VERSION 5.8 ;
BUSBITCHARS "[]" ;
DIVIDERCHAR "/" ;
UNITS
    DATABASE MICRONS 1000 ;
END UNITS

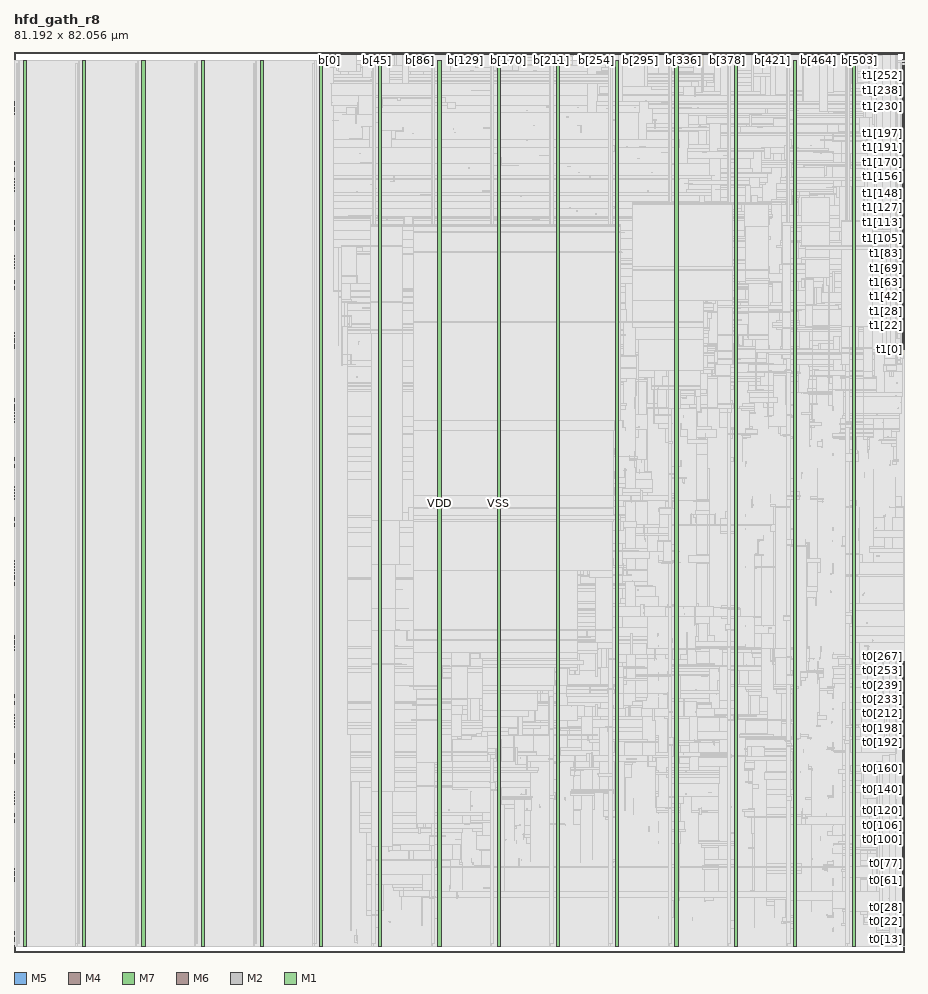
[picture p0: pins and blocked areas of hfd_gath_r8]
MACRO hfd_gath_r8
  FOREIGN hfd_gath_r8 0 0 ;
  CLASS BLOCK ;
  SIZE 81.192 BY 82.056 ;
  PIN b[0]
    DIRECTION OUTPUT ;
    USE SIGNAL ;
    PORT
      LAYER M5 ;
        RECT  28.752 81.864 28.776 82.056 ;
    END
  END b[0]
  PIN b[100]
    DIRECTION OUTPUT ;
    USE SIGNAL ;
    PORT
      LAYER M5 ;
        RECT  38.352 81.864 38.376 82.056 ;
    END
  END b[100]
  PIN b[101]
    DIRECTION OUTPUT ;
    USE SIGNAL ;
    PORT
      LAYER M5 ;
        RECT  38.448 81.864 38.472 82.056 ;
    END
  END b[101]
  PIN b[102]
    DIRECTION OUTPUT ;
    USE SIGNAL ;
    PORT
      LAYER M5 ;
        RECT  38.544 81.864 38.568 82.056 ;
    END
  END b[102]
  PIN b[103]
    DIRECTION OUTPUT ;
    USE SIGNAL ;
    PORT
      LAYER M5 ;
        RECT  38.64 81.864 38.664 82.056 ;
    END
  END b[103]
  PIN b[104]
    DIRECTION OUTPUT ;
    USE SIGNAL ;
    PORT
      LAYER M5 ;
        RECT  38.736 81.864 38.76 82.056 ;
    END
  END b[104]
  PIN b[105]
    DIRECTION OUTPUT ;
    USE SIGNAL ;
    PORT
      LAYER M5 ;
        RECT  38.832 81.864 38.856 82.056 ;
    END
  END b[105]
  PIN b[106]
    DIRECTION OUTPUT ;
    USE SIGNAL ;
    PORT
      LAYER M5 ;
        RECT  38.928 81.864 38.952 82.056 ;
    END
  END b[106]
  PIN b[107]
    DIRECTION OUTPUT ;
    USE SIGNAL ;
    PORT
      LAYER M5 ;
        RECT  39.024 81.864 39.048 82.056 ;
    END
  END b[107]
  PIN b[108]
    DIRECTION OUTPUT ;
    USE SIGNAL ;
    PORT
      LAYER M5 ;
        RECT  39.12 81.864 39.144 82.056 ;
    END
  END b[108]
  PIN b[109]
    DIRECTION OUTPUT ;
    USE SIGNAL ;
    PORT
      LAYER M5 ;
        RECT  39.216 81.864 39.24 82.056 ;
    END
  END b[109]
  PIN b[10]
    DIRECTION OUTPUT ;
    USE SIGNAL ;
    PORT
      LAYER M5 ;
        RECT  29.712 81.864 29.736 82.056 ;
    END
  END b[10]
  PIN b[110]
    DIRECTION OUTPUT ;
    USE SIGNAL ;
    PORT
      LAYER M5 ;
        RECT  39.312 81.864 39.336 82.056 ;
    END
  END b[110]
  PIN b[111]
    DIRECTION OUTPUT ;
    USE SIGNAL ;
    PORT
      LAYER M5 ;
        RECT  39.408 81.864 39.432 82.056 ;
    END
  END b[111]
  PIN b[112]
    DIRECTION OUTPUT ;
    USE SIGNAL ;
    PORT
      LAYER M5 ;
        RECT  39.504 81.864 39.528 82.056 ;
    END
  END b[112]
  PIN b[113]
    DIRECTION OUTPUT ;
    USE SIGNAL ;
    PORT
      LAYER M5 ;
        RECT  39.6 81.864 39.624 82.056 ;
    END
  END b[113]
  PIN b[114]
    DIRECTION OUTPUT ;
    USE SIGNAL ;
    PORT
      LAYER M5 ;
        RECT  39.696 81.864 39.72 82.056 ;
    END
  END b[114]
  PIN b[115]
    DIRECTION OUTPUT ;
    USE SIGNAL ;
    PORT
      LAYER M5 ;
        RECT  39.792 81.864 39.816 82.056 ;
    END
  END b[115]
  PIN b[116]
    DIRECTION OUTPUT ;
    USE SIGNAL ;
    PORT
      LAYER M5 ;
        RECT  39.888 81.864 39.912 82.056 ;
    END
  END b[116]
  PIN b[117]
    DIRECTION OUTPUT ;
    USE SIGNAL ;
    PORT
      LAYER M5 ;
        RECT  39.984 81.864 40.008 82.056 ;
    END
  END b[117]
  PIN b[118]
    DIRECTION OUTPUT ;
    USE SIGNAL ;
    PORT
      LAYER M5 ;
        RECT  40.08 81.864 40.104 82.056 ;
    END
  END b[118]
  PIN b[119]
    DIRECTION OUTPUT ;
    USE SIGNAL ;
    PORT
      LAYER M5 ;
        RECT  40.176 81.864 40.2 82.056 ;
    END
  END b[119]
  PIN b[11]
    DIRECTION OUTPUT ;
    USE SIGNAL ;
    PORT
      LAYER M5 ;
        RECT  29.808 81.864 29.832 82.056 ;
    END
  END b[11]
  PIN b[120]
    DIRECTION OUTPUT ;
    USE SIGNAL ;
    PORT
      LAYER M5 ;
        RECT  40.272 81.864 40.296 82.056 ;
    END
  END b[120]
  PIN b[121]
    DIRECTION OUTPUT ;
    USE SIGNAL ;
    PORT
      LAYER M5 ;
        RECT  40.368 81.864 40.392 82.056 ;
    END
  END b[121]
  PIN b[122]
    DIRECTION OUTPUT ;
    USE SIGNAL ;
    PORT
      LAYER M5 ;
        RECT  40.464 81.864 40.488 82.056 ;
    END
  END b[122]
  PIN b[123]
    DIRECTION OUTPUT ;
    USE SIGNAL ;
    PORT
      LAYER M5 ;
        RECT  40.56 81.864 40.584 82.056 ;
    END
  END b[123]
  PIN b[124]
    DIRECTION OUTPUT ;
    USE SIGNAL ;
    PORT
      LAYER M5 ;
        RECT  40.656 81.864 40.68 82.056 ;
    END
  END b[124]
  PIN b[125]
    DIRECTION OUTPUT ;
    USE SIGNAL ;
    PORT
      LAYER M5 ;
        RECT  40.752 81.864 40.776 82.056 ;
    END
  END b[125]
  PIN b[126]
    DIRECTION OUTPUT ;
    USE SIGNAL ;
    PORT
      LAYER M5 ;
        RECT  40.848 81.864 40.872 82.056 ;
    END
  END b[126]
  PIN b[127]
    DIRECTION OUTPUT ;
    USE SIGNAL ;
    PORT
      LAYER M5 ;
        RECT  40.944 81.864 40.968 82.056 ;
    END
  END b[127]
  PIN b[128]
    DIRECTION OUTPUT ;
    USE SIGNAL ;
    PORT
      LAYER M5 ;
        RECT  41.04 81.864 41.064 82.056 ;
    END
  END b[128]
  PIN b[129]
    DIRECTION OUTPUT ;
    USE SIGNAL ;
    PORT
      LAYER M5 ;
        RECT  41.136 81.864 41.16 82.056 ;
    END
  END b[129]
  PIN b[12]
    DIRECTION OUTPUT ;
    USE SIGNAL ;
    PORT
      LAYER M5 ;
        RECT  29.904 81.864 29.928 82.056 ;
    END
  END b[12]
  PIN b[130]
    DIRECTION OUTPUT ;
    USE SIGNAL ;
    PORT
      LAYER M5 ;
        RECT  41.232 81.864 41.256 82.056 ;
    END
  END b[130]
  PIN b[131]
    DIRECTION OUTPUT ;
    USE SIGNAL ;
    PORT
      LAYER M5 ;
        RECT  41.328 81.864 41.352 82.056 ;
    END
  END b[131]
  PIN b[132]
    DIRECTION OUTPUT ;
    USE SIGNAL ;
    PORT
      LAYER M5 ;
        RECT  41.424 81.864 41.448 82.056 ;
    END
  END b[132]
  PIN b[133]
    DIRECTION OUTPUT ;
    USE SIGNAL ;
    PORT
      LAYER M5 ;
        RECT  41.52 81.864 41.544 82.056 ;
    END
  END b[133]
  PIN b[134]
    DIRECTION OUTPUT ;
    USE SIGNAL ;
    PORT
      LAYER M5 ;
        RECT  41.616 81.864 41.64 82.056 ;
    END
  END b[134]
  PIN b[135]
    DIRECTION OUTPUT ;
    USE SIGNAL ;
    PORT
      LAYER M5 ;
        RECT  41.712 81.864 41.736 82.056 ;
    END
  END b[135]
  PIN b[136]
    DIRECTION OUTPUT ;
    USE SIGNAL ;
    PORT
      LAYER M5 ;
        RECT  41.808 81.864 41.832 82.056 ;
    END
  END b[136]
  PIN b[137]
    DIRECTION OUTPUT ;
    USE SIGNAL ;
    PORT
      LAYER M5 ;
        RECT  41.904 81.864 41.928 82.056 ;
    END
  END b[137]
  PIN b[138]
    DIRECTION OUTPUT ;
    USE SIGNAL ;
    PORT
      LAYER M5 ;
        RECT  42 81.864 42.024 82.056 ;
    END
  END b[138]
  PIN b[139]
    DIRECTION OUTPUT ;
    USE SIGNAL ;
    PORT
      LAYER M5 ;
        RECT  42.096 81.864 42.12 82.056 ;
    END
  END b[139]
  PIN b[13]
    DIRECTION OUTPUT ;
    USE SIGNAL ;
    PORT
      LAYER M5 ;
        RECT  30 81.864 30.024 82.056 ;
    END
  END b[13]
  PIN b[140]
    DIRECTION OUTPUT ;
    USE SIGNAL ;
    PORT
      LAYER M5 ;
        RECT  42.192 81.864 42.216 82.056 ;
    END
  END b[140]
  PIN b[141]
    DIRECTION OUTPUT ;
    USE SIGNAL ;
    PORT
      LAYER M5 ;
        RECT  42.288 81.864 42.312 82.056 ;
    END
  END b[141]
  PIN b[142]
    DIRECTION OUTPUT ;
    USE SIGNAL ;
    PORT
      LAYER M5 ;
        RECT  42.384 81.864 42.408 82.056 ;
    END
  END b[142]
  PIN b[143]
    DIRECTION OUTPUT ;
    USE SIGNAL ;
    PORT
      LAYER M5 ;
        RECT  42.48 81.864 42.504 82.056 ;
    END
  END b[143]
  PIN b[144]
    DIRECTION OUTPUT ;
    USE SIGNAL ;
    PORT
      LAYER M5 ;
        RECT  42.576 81.864 42.6 82.056 ;
    END
  END b[144]
  PIN b[145]
    DIRECTION OUTPUT ;
    USE SIGNAL ;
    PORT
      LAYER M5 ;
        RECT  42.672 81.864 42.696 82.056 ;
    END
  END b[145]
  PIN b[146]
    DIRECTION OUTPUT ;
    USE SIGNAL ;
    PORT
      LAYER M5 ;
        RECT  42.768 81.864 42.792 82.056 ;
    END
  END b[146]
  PIN b[147]
    DIRECTION OUTPUT ;
    USE SIGNAL ;
    PORT
      LAYER M5 ;
        RECT  42.864 81.864 42.888 82.056 ;
    END
  END b[147]
  PIN b[148]
    DIRECTION OUTPUT ;
    USE SIGNAL ;
    PORT
      LAYER M5 ;
        RECT  42.96 81.864 42.984 82.056 ;
    END
  END b[148]
  PIN b[149]
    DIRECTION OUTPUT ;
    USE SIGNAL ;
    PORT
      LAYER M5 ;
        RECT  43.056 81.864 43.08 82.056 ;
    END
  END b[149]
  PIN b[14]
    DIRECTION OUTPUT ;
    USE SIGNAL ;
    PORT
      LAYER M5 ;
        RECT  30.096 81.864 30.12 82.056 ;
    END
  END b[14]
  PIN b[150]
    DIRECTION OUTPUT ;
    USE SIGNAL ;
    PORT
      LAYER M5 ;
        RECT  43.152 81.864 43.176 82.056 ;
    END
  END b[150]
  PIN b[151]
    DIRECTION OUTPUT ;
    USE SIGNAL ;
    PORT
      LAYER M5 ;
        RECT  43.248 81.864 43.272 82.056 ;
    END
  END b[151]
  PIN b[152]
    DIRECTION OUTPUT ;
    USE SIGNAL ;
    PORT
      LAYER M5 ;
        RECT  43.344 81.864 43.368 82.056 ;
    END
  END b[152]
  PIN b[153]
    DIRECTION OUTPUT ;
    USE SIGNAL ;
    PORT
      LAYER M5 ;
        RECT  43.44 81.864 43.464 82.056 ;
    END
  END b[153]
  PIN b[154]
    DIRECTION OUTPUT ;
    USE SIGNAL ;
    PORT
      LAYER M5 ;
        RECT  43.536 81.864 43.56 82.056 ;
    END
  END b[154]
  PIN b[155]
    DIRECTION OUTPUT ;
    USE SIGNAL ;
    PORT
      LAYER M5 ;
        RECT  43.632 81.864 43.656 82.056 ;
    END
  END b[155]
  PIN b[156]
    DIRECTION OUTPUT ;
    USE SIGNAL ;
    PORT
      LAYER M5 ;
        RECT  43.728 81.864 43.752 82.056 ;
    END
  END b[156]
  PIN b[157]
    DIRECTION OUTPUT ;
    USE SIGNAL ;
    PORT
      LAYER M5 ;
        RECT  43.824 81.864 43.848 82.056 ;
    END
  END b[157]
  PIN b[158]
    DIRECTION OUTPUT ;
    USE SIGNAL ;
    PORT
      LAYER M5 ;
        RECT  43.92 81.864 43.944 82.056 ;
    END
  END b[158]
  PIN b[159]
    DIRECTION OUTPUT ;
    USE SIGNAL ;
    PORT
      LAYER M5 ;
        RECT  44.016 81.864 44.04 82.056 ;
    END
  END b[159]
  PIN b[15]
    DIRECTION OUTPUT ;
    USE SIGNAL ;
    PORT
      LAYER M5 ;
        RECT  30.192 81.864 30.216 82.056 ;
    END
  END b[15]
  PIN b[160]
    DIRECTION OUTPUT ;
    USE SIGNAL ;
    PORT
      LAYER M5 ;
        RECT  44.112 81.864 44.136 82.056 ;
    END
  END b[160]
  PIN b[161]
    DIRECTION OUTPUT ;
    USE SIGNAL ;
    PORT
      LAYER M5 ;
        RECT  44.208 81.864 44.232 82.056 ;
    END
  END b[161]
  PIN b[162]
    DIRECTION OUTPUT ;
    USE SIGNAL ;
    PORT
      LAYER M5 ;
        RECT  44.304 81.864 44.328 82.056 ;
    END
  END b[162]
  PIN b[163]
    DIRECTION OUTPUT ;
    USE SIGNAL ;
    PORT
      LAYER M5 ;
        RECT  44.4 81.864 44.424 82.056 ;
    END
  END b[163]
  PIN b[164]
    DIRECTION OUTPUT ;
    USE SIGNAL ;
    PORT
      LAYER M5 ;
        RECT  44.496 81.864 44.52 82.056 ;
    END
  END b[164]
  PIN b[165]
    DIRECTION OUTPUT ;
    USE SIGNAL ;
    PORT
      LAYER M5 ;
        RECT  44.592 81.864 44.616 82.056 ;
    END
  END b[165]
  PIN b[166]
    DIRECTION OUTPUT ;
    USE SIGNAL ;
    PORT
      LAYER M5 ;
        RECT  44.688 81.864 44.712 82.056 ;
    END
  END b[166]
  PIN b[167]
    DIRECTION OUTPUT ;
    USE SIGNAL ;
    PORT
      LAYER M5 ;
        RECT  44.784 81.864 44.808 82.056 ;
    END
  END b[167]
  PIN b[168]
    DIRECTION OUTPUT ;
    USE SIGNAL ;
    PORT
      LAYER M5 ;
        RECT  44.88 81.864 44.904 82.056 ;
    END
  END b[168]
  PIN b[169]
    DIRECTION OUTPUT ;
    USE SIGNAL ;
    PORT
      LAYER M5 ;
        RECT  44.976 81.864 45 82.056 ;
    END
  END b[169]
  PIN b[16]
    DIRECTION OUTPUT ;
    USE SIGNAL ;
    PORT
      LAYER M5 ;
        RECT  30.288 81.864 30.312 82.056 ;
    END
  END b[16]
  PIN b[170]
    DIRECTION OUTPUT ;
    USE SIGNAL ;
    PORT
      LAYER M5 ;
        RECT  45.072 81.864 45.096 82.056 ;
    END
  END b[170]
  PIN b[171]
    DIRECTION OUTPUT ;
    USE SIGNAL ;
    PORT
      LAYER M5 ;
        RECT  45.168 81.864 45.192 82.056 ;
    END
  END b[171]
  PIN b[172]
    DIRECTION OUTPUT ;
    USE SIGNAL ;
    PORT
      LAYER M5 ;
        RECT  45.264 81.864 45.288 82.056 ;
    END
  END b[172]
  PIN b[173]
    DIRECTION OUTPUT ;
    USE SIGNAL ;
    PORT
      LAYER M5 ;
        RECT  45.36 81.864 45.384 82.056 ;
    END
  END b[173]
  PIN b[174]
    DIRECTION OUTPUT ;
    USE SIGNAL ;
    PORT
      LAYER M5 ;
        RECT  45.456 81.864 45.48 82.056 ;
    END
  END b[174]
  PIN b[175]
    DIRECTION OUTPUT ;
    USE SIGNAL ;
    PORT
      LAYER M5 ;
        RECT  45.552 81.864 45.576 82.056 ;
    END
  END b[175]
  PIN b[176]
    DIRECTION OUTPUT ;
    USE SIGNAL ;
    PORT
      LAYER M5 ;
        RECT  45.648 81.864 45.672 82.056 ;
    END
  END b[176]
  PIN b[177]
    DIRECTION OUTPUT ;
    USE SIGNAL ;
    PORT
      LAYER M5 ;
        RECT  45.744 81.864 45.768 82.056 ;
    END
  END b[177]
  PIN b[178]
    DIRECTION OUTPUT ;
    USE SIGNAL ;
    PORT
      LAYER M5 ;
        RECT  45.84 81.864 45.864 82.056 ;
    END
  END b[178]
  PIN b[179]
    DIRECTION OUTPUT ;
    USE SIGNAL ;
    PORT
      LAYER M5 ;
        RECT  45.936 81.864 45.96 82.056 ;
    END
  END b[179]
  PIN b[17]
    DIRECTION OUTPUT ;
    USE SIGNAL ;
    PORT
      LAYER M5 ;
        RECT  30.384 81.864 30.408 82.056 ;
    END
  END b[17]
  PIN b[180]
    DIRECTION OUTPUT ;
    USE SIGNAL ;
    PORT
      LAYER M5 ;
        RECT  46.032 81.864 46.056 82.056 ;
    END
  END b[180]
  PIN b[181]
    DIRECTION OUTPUT ;
    USE SIGNAL ;
    PORT
      LAYER M5 ;
        RECT  46.128 81.864 46.152 82.056 ;
    END
  END b[181]
  PIN b[182]
    DIRECTION OUTPUT ;
    USE SIGNAL ;
    PORT
      LAYER M5 ;
        RECT  46.224 81.864 46.248 82.056 ;
    END
  END b[182]
  PIN b[183]
    DIRECTION OUTPUT ;
    USE SIGNAL ;
    PORT
      LAYER M5 ;
        RECT  46.32 81.864 46.344 82.056 ;
    END
  END b[183]
  PIN b[184]
    DIRECTION OUTPUT ;
    USE SIGNAL ;
    PORT
      LAYER M5 ;
        RECT  46.416 81.864 46.44 82.056 ;
    END
  END b[184]
  PIN b[185]
    DIRECTION OUTPUT ;
    USE SIGNAL ;
    PORT
      LAYER M5 ;
        RECT  46.512 81.864 46.536 82.056 ;
    END
  END b[185]
  PIN b[186]
    DIRECTION OUTPUT ;
    USE SIGNAL ;
    PORT
      LAYER M5 ;
        RECT  46.608 81.864 46.632 82.056 ;
    END
  END b[186]
  PIN b[187]
    DIRECTION OUTPUT ;
    USE SIGNAL ;
    PORT
      LAYER M5 ;
        RECT  46.704 81.864 46.728 82.056 ;
    END
  END b[187]
  PIN b[188]
    DIRECTION OUTPUT ;
    USE SIGNAL ;
    PORT
      LAYER M5 ;
        RECT  46.8 81.864 46.824 82.056 ;
    END
  END b[188]
  PIN b[189]
    DIRECTION OUTPUT ;
    USE SIGNAL ;
    PORT
      LAYER M5 ;
        RECT  46.896 81.864 46.92 82.056 ;
    END
  END b[189]
  PIN b[18]
    DIRECTION OUTPUT ;
    USE SIGNAL ;
    PORT
      LAYER M5 ;
        RECT  30.48 81.864 30.504 82.056 ;
    END
  END b[18]
  PIN b[190]
    DIRECTION OUTPUT ;
    USE SIGNAL ;
    PORT
      LAYER M5 ;
        RECT  46.992 81.864 47.016 82.056 ;
    END
  END b[190]
  PIN b[191]
    DIRECTION OUTPUT ;
    USE SIGNAL ;
    PORT
      LAYER M5 ;
        RECT  47.088 81.864 47.112 82.056 ;
    END
  END b[191]
  PIN b[192]
    DIRECTION OUTPUT ;
    USE SIGNAL ;
    PORT
      LAYER M5 ;
        RECT  47.184 81.864 47.208 82.056 ;
    END
  END b[192]
  PIN b[193]
    DIRECTION OUTPUT ;
    USE SIGNAL ;
    PORT
      LAYER M5 ;
        RECT  47.28 81.864 47.304 82.056 ;
    END
  END b[193]
  PIN b[194]
    DIRECTION OUTPUT ;
    USE SIGNAL ;
    PORT
      LAYER M5 ;
        RECT  47.376 81.864 47.4 82.056 ;
    END
  END b[194]
  PIN b[195]
    DIRECTION OUTPUT ;
    USE SIGNAL ;
    PORT
      LAYER M5 ;
        RECT  47.472 81.864 47.496 82.056 ;
    END
  END b[195]
  PIN b[196]
    DIRECTION OUTPUT ;
    USE SIGNAL ;
    PORT
      LAYER M5 ;
        RECT  47.568 81.864 47.592 82.056 ;
    END
  END b[196]
  PIN b[197]
    DIRECTION OUTPUT ;
    USE SIGNAL ;
    PORT
      LAYER M5 ;
        RECT  47.664 81.864 47.688 82.056 ;
    END
  END b[197]
  PIN b[198]
    DIRECTION OUTPUT ;
    USE SIGNAL ;
    PORT
      LAYER M5 ;
        RECT  47.76 81.864 47.784 82.056 ;
    END
  END b[198]
  PIN b[199]
    DIRECTION OUTPUT ;
    USE SIGNAL ;
    PORT
      LAYER M5 ;
        RECT  47.856 81.864 47.88 82.056 ;
    END
  END b[199]
  PIN b[19]
    DIRECTION OUTPUT ;
    USE SIGNAL ;
    PORT
      LAYER M5 ;
        RECT  30.576 81.864 30.6 82.056 ;
    END
  END b[19]
  PIN b[1]
    DIRECTION OUTPUT ;
    USE SIGNAL ;
    PORT
      LAYER M5 ;
        RECT  28.848 81.864 28.872 82.056 ;
    END
  END b[1]
  PIN b[200]
    DIRECTION OUTPUT ;
    USE SIGNAL ;
    PORT
      LAYER M5 ;
        RECT  47.952 81.864 47.976 82.056 ;
    END
  END b[200]
  PIN b[201]
    DIRECTION OUTPUT ;
    USE SIGNAL ;
    PORT
      LAYER M5 ;
        RECT  48.048 81.864 48.072 82.056 ;
    END
  END b[201]
  PIN b[202]
    DIRECTION OUTPUT ;
    USE SIGNAL ;
    PORT
      LAYER M5 ;
        RECT  48.144 81.864 48.168 82.056 ;
    END
  END b[202]
  PIN b[203]
    DIRECTION OUTPUT ;
    USE SIGNAL ;
    PORT
      LAYER M5 ;
        RECT  48.24 81.864 48.264 82.056 ;
    END
  END b[203]
  PIN b[204]
    DIRECTION OUTPUT ;
    USE SIGNAL ;
    PORT
      LAYER M5 ;
        RECT  48.336 81.864 48.36 82.056 ;
    END
  END b[204]
  PIN b[205]
    DIRECTION OUTPUT ;
    USE SIGNAL ;
    PORT
      LAYER M5 ;
        RECT  48.432 81.864 48.456 82.056 ;
    END
  END b[205]
  PIN b[206]
    DIRECTION OUTPUT ;
    USE SIGNAL ;
    PORT
      LAYER M5 ;
        RECT  48.528 81.864 48.552 82.056 ;
    END
  END b[206]
  PIN b[207]
    DIRECTION OUTPUT ;
    USE SIGNAL ;
    PORT
      LAYER M5 ;
        RECT  48.624 81.864 48.648 82.056 ;
    END
  END b[207]
  PIN b[208]
    DIRECTION OUTPUT ;
    USE SIGNAL ;
    PORT
      LAYER M5 ;
        RECT  48.72 81.864 48.744 82.056 ;
    END
  END b[208]
  PIN b[209]
    DIRECTION OUTPUT ;
    USE SIGNAL ;
    PORT
      LAYER M5 ;
        RECT  48.816 81.864 48.84 82.056 ;
    END
  END b[209]
  PIN b[20]
    DIRECTION OUTPUT ;
    USE SIGNAL ;
    PORT
      LAYER M5 ;
        RECT  30.672 81.864 30.696 82.056 ;
    END
  END b[20]
  PIN b[210]
    DIRECTION OUTPUT ;
    USE SIGNAL ;
    PORT
      LAYER M5 ;
        RECT  48.912 81.864 48.936 82.056 ;
    END
  END b[210]
  PIN b[211]
    DIRECTION OUTPUT ;
    USE SIGNAL ;
    PORT
      LAYER M5 ;
        RECT  49.008 81.864 49.032 82.056 ;
    END
  END b[211]
  PIN b[212]
    DIRECTION OUTPUT ;
    USE SIGNAL ;
    PORT
      LAYER M5 ;
        RECT  49.104 81.864 49.128 82.056 ;
    END
  END b[212]
  PIN b[213]
    DIRECTION OUTPUT ;
    USE SIGNAL ;
    PORT
      LAYER M5 ;
        RECT  49.2 81.864 49.224 82.056 ;
    END
  END b[213]
  PIN b[214]
    DIRECTION OUTPUT ;
    USE SIGNAL ;
    PORT
      LAYER M5 ;
        RECT  49.296 81.864 49.32 82.056 ;
    END
  END b[214]
  PIN b[215]
    DIRECTION OUTPUT ;
    USE SIGNAL ;
    PORT
      LAYER M5 ;
        RECT  49.392 81.864 49.416 82.056 ;
    END
  END b[215]
  PIN b[216]
    DIRECTION OUTPUT ;
    USE SIGNAL ;
    PORT
      LAYER M5 ;
        RECT  49.488 81.864 49.512 82.056 ;
    END
  END b[216]
  PIN b[217]
    DIRECTION OUTPUT ;
    USE SIGNAL ;
    PORT
      LAYER M5 ;
        RECT  49.584 81.864 49.608 82.056 ;
    END
  END b[217]
  PIN b[218]
    DIRECTION OUTPUT ;
    USE SIGNAL ;
    PORT
      LAYER M5 ;
        RECT  49.68 81.864 49.704 82.056 ;
    END
  END b[218]
  PIN b[219]
    DIRECTION OUTPUT ;
    USE SIGNAL ;
    PORT
      LAYER M5 ;
        RECT  49.776 81.864 49.8 82.056 ;
    END
  END b[219]
  PIN b[21]
    DIRECTION OUTPUT ;
    USE SIGNAL ;
    PORT
      LAYER M5 ;
        RECT  30.768 81.864 30.792 82.056 ;
    END
  END b[21]
  PIN b[220]
    DIRECTION OUTPUT ;
    USE SIGNAL ;
    PORT
      LAYER M5 ;
        RECT  49.872 81.864 49.896 82.056 ;
    END
  END b[220]
  PIN b[221]
    DIRECTION OUTPUT ;
    USE SIGNAL ;
    PORT
      LAYER M5 ;
        RECT  49.968 81.864 49.992 82.056 ;
    END
  END b[221]
  PIN b[222]
    DIRECTION OUTPUT ;
    USE SIGNAL ;
    PORT
      LAYER M5 ;
        RECT  50.064 81.864 50.088 82.056 ;
    END
  END b[222]
  PIN b[223]
    DIRECTION OUTPUT ;
    USE SIGNAL ;
    PORT
      LAYER M5 ;
        RECT  50.16 81.864 50.184 82.056 ;
    END
  END b[223]
  PIN b[224]
    DIRECTION OUTPUT ;
    USE SIGNAL ;
    PORT
      LAYER M5 ;
        RECT  50.256 81.864 50.28 82.056 ;
    END
  END b[224]
  PIN b[225]
    DIRECTION OUTPUT ;
    USE SIGNAL ;
    PORT
      LAYER M5 ;
        RECT  50.352 81.864 50.376 82.056 ;
    END
  END b[225]
  PIN b[226]
    DIRECTION OUTPUT ;
    USE SIGNAL ;
    PORT
      LAYER M5 ;
        RECT  50.448 81.864 50.472 82.056 ;
    END
  END b[226]
  PIN b[227]
    DIRECTION OUTPUT ;
    USE SIGNAL ;
    PORT
      LAYER M5 ;
        RECT  50.544 81.864 50.568 82.056 ;
    END
  END b[227]
  PIN b[228]
    DIRECTION OUTPUT ;
    USE SIGNAL ;
    PORT
      LAYER M5 ;
        RECT  50.64 81.864 50.664 82.056 ;
    END
  END b[228]
  PIN b[229]
    DIRECTION OUTPUT ;
    USE SIGNAL ;
    PORT
      LAYER M5 ;
        RECT  50.736 81.864 50.76 82.056 ;
    END
  END b[229]
  PIN b[22]
    DIRECTION OUTPUT ;
    USE SIGNAL ;
    PORT
      LAYER M5 ;
        RECT  30.864 81.864 30.888 82.056 ;
    END
  END b[22]
  PIN b[230]
    DIRECTION OUTPUT ;
    USE SIGNAL ;
    PORT
      LAYER M5 ;
        RECT  50.832 81.864 50.856 82.056 ;
    END
  END b[230]
  PIN b[231]
    DIRECTION OUTPUT ;
    USE SIGNAL ;
    PORT
      LAYER M5 ;
        RECT  50.928 81.864 50.952 82.056 ;
    END
  END b[231]
  PIN b[232]
    DIRECTION OUTPUT ;
    USE SIGNAL ;
    PORT
      LAYER M5 ;
        RECT  51.024 81.864 51.048 82.056 ;
    END
  END b[232]
  PIN b[233]
    DIRECTION OUTPUT ;
    USE SIGNAL ;
    PORT
      LAYER M5 ;
        RECT  51.12 81.864 51.144 82.056 ;
    END
  END b[233]
  PIN b[234]
    DIRECTION OUTPUT ;
    USE SIGNAL ;
    PORT
      LAYER M5 ;
        RECT  51.216 81.864 51.24 82.056 ;
    END
  END b[234]
  PIN b[235]
    DIRECTION OUTPUT ;
    USE SIGNAL ;
    PORT
      LAYER M5 ;
        RECT  51.312 81.864 51.336 82.056 ;
    END
  END b[235]
  PIN b[236]
    DIRECTION OUTPUT ;
    USE SIGNAL ;
    PORT
      LAYER M5 ;
        RECT  51.408 81.864 51.432 82.056 ;
    END
  END b[236]
  PIN b[237]
    DIRECTION OUTPUT ;
    USE SIGNAL ;
    PORT
      LAYER M5 ;
        RECT  51.504 81.864 51.528 82.056 ;
    END
  END b[237]
  PIN b[238]
    DIRECTION OUTPUT ;
    USE SIGNAL ;
    PORT
      LAYER M5 ;
        RECT  51.6 81.864 51.624 82.056 ;
    END
  END b[238]
  PIN b[239]
    DIRECTION OUTPUT ;
    USE SIGNAL ;
    PORT
      LAYER M5 ;
        RECT  51.696 81.864 51.72 82.056 ;
    END
  END b[239]
  PIN b[23]
    DIRECTION OUTPUT ;
    USE SIGNAL ;
    PORT
      LAYER M5 ;
        RECT  30.96 81.864 30.984 82.056 ;
    END
  END b[23]
  PIN b[240]
    DIRECTION OUTPUT ;
    USE SIGNAL ;
    PORT
      LAYER M5 ;
        RECT  51.792 81.864 51.816 82.056 ;
    END
  END b[240]
  PIN b[241]
    DIRECTION OUTPUT ;
    USE SIGNAL ;
    PORT
      LAYER M5 ;
        RECT  51.888 81.864 51.912 82.056 ;
    END
  END b[241]
  PIN b[242]
    DIRECTION OUTPUT ;
    USE SIGNAL ;
    PORT
      LAYER M5 ;
        RECT  51.984 81.864 52.008 82.056 ;
    END
  END b[242]
  PIN b[243]
    DIRECTION OUTPUT ;
    USE SIGNAL ;
    PORT
      LAYER M5 ;
        RECT  52.08 81.864 52.104 82.056 ;
    END
  END b[243]
  PIN b[244]
    DIRECTION OUTPUT ;
    USE SIGNAL ;
    PORT
      LAYER M5 ;
        RECT  52.176 81.864 52.2 82.056 ;
    END
  END b[244]
  PIN b[245]
    DIRECTION OUTPUT ;
    USE SIGNAL ;
    PORT
      LAYER M5 ;
        RECT  52.272 81.864 52.296 82.056 ;
    END
  END b[245]
  PIN b[246]
    DIRECTION OUTPUT ;
    USE SIGNAL ;
    PORT
      LAYER M5 ;
        RECT  52.368 81.864 52.392 82.056 ;
    END
  END b[246]
  PIN b[247]
    DIRECTION OUTPUT ;
    USE SIGNAL ;
    PORT
      LAYER M5 ;
        RECT  52.464 81.864 52.488 82.056 ;
    END
  END b[247]
  PIN b[248]
    DIRECTION OUTPUT ;
    USE SIGNAL ;
    PORT
      LAYER M5 ;
        RECT  52.56 81.864 52.584 82.056 ;
    END
  END b[248]
  PIN b[249]
    DIRECTION OUTPUT ;
    USE SIGNAL ;
    PORT
      LAYER M5 ;
        RECT  52.656 81.864 52.68 82.056 ;
    END
  END b[249]
  PIN b[24]
    DIRECTION OUTPUT ;
    USE SIGNAL ;
    PORT
      LAYER M5 ;
        RECT  31.056 81.864 31.08 82.056 ;
    END
  END b[24]
  PIN b[250]
    DIRECTION OUTPUT ;
    USE SIGNAL ;
    PORT
      LAYER M5 ;
        RECT  52.752 81.864 52.776 82.056 ;
    END
  END b[250]
  PIN b[251]
    DIRECTION OUTPUT ;
    USE SIGNAL ;
    PORT
      LAYER M5 ;
        RECT  52.848 81.864 52.872 82.056 ;
    END
  END b[251]
  PIN b[252]
    DIRECTION OUTPUT ;
    USE SIGNAL ;
    PORT
      LAYER M5 ;
        RECT  52.944 81.864 52.968 82.056 ;
    END
  END b[252]
  PIN b[253]
    DIRECTION OUTPUT ;
    USE SIGNAL ;
    PORT
      LAYER M5 ;
        RECT  53.04 81.864 53.064 82.056 ;
    END
  END b[253]
  PIN b[254]
    DIRECTION OUTPUT ;
    USE SIGNAL ;
    PORT
      LAYER M5 ;
        RECT  53.136 81.864 53.16 82.056 ;
    END
  END b[254]
  PIN b[255]
    DIRECTION OUTPUT ;
    USE SIGNAL ;
    PORT
      LAYER M5 ;
        RECT  53.232 81.864 53.256 82.056 ;
    END
  END b[255]
  PIN b[256]
    DIRECTION OUTPUT ;
    USE SIGNAL ;
    PORT
      LAYER M5 ;
        RECT  53.328 81.864 53.352 82.056 ;
    END
  END b[256]
  PIN b[257]
    DIRECTION OUTPUT ;
    USE SIGNAL ;
    PORT
      LAYER M5 ;
        RECT  53.424 81.864 53.448 82.056 ;
    END
  END b[257]
  PIN b[258]
    DIRECTION OUTPUT ;
    USE SIGNAL ;
    PORT
      LAYER M5 ;
        RECT  53.52 81.864 53.544 82.056 ;
    END
  END b[258]
  PIN b[259]
    DIRECTION OUTPUT ;
    USE SIGNAL ;
    PORT
      LAYER M5 ;
        RECT  53.616 81.864 53.64 82.056 ;
    END
  END b[259]
  PIN b[25]
    DIRECTION OUTPUT ;
    USE SIGNAL ;
    PORT
      LAYER M5 ;
        RECT  31.152 81.864 31.176 82.056 ;
    END
  END b[25]
  PIN b[260]
    DIRECTION OUTPUT ;
    USE SIGNAL ;
    PORT
      LAYER M5 ;
        RECT  53.712 81.864 53.736 82.056 ;
    END
  END b[260]
  PIN b[261]
    DIRECTION OUTPUT ;
    USE SIGNAL ;
    PORT
      LAYER M5 ;
        RECT  53.808 81.864 53.832 82.056 ;
    END
  END b[261]
  PIN b[262]
    DIRECTION OUTPUT ;
    USE SIGNAL ;
    PORT
      LAYER M5 ;
        RECT  53.904 81.864 53.928 82.056 ;
    END
  END b[262]
  PIN b[263]
    DIRECTION OUTPUT ;
    USE SIGNAL ;
    PORT
      LAYER M5 ;
        RECT  54 81.864 54.024 82.056 ;
    END
  END b[263]
  PIN b[264]
    DIRECTION OUTPUT ;
    USE SIGNAL ;
    PORT
      LAYER M5 ;
        RECT  54.096 81.864 54.12 82.056 ;
    END
  END b[264]
  PIN b[265]
    DIRECTION OUTPUT ;
    USE SIGNAL ;
    PORT
      LAYER M5 ;
        RECT  54.192 81.864 54.216 82.056 ;
    END
  END b[265]
  PIN b[266]
    DIRECTION OUTPUT ;
    USE SIGNAL ;
    PORT
      LAYER M5 ;
        RECT  54.288 81.864 54.312 82.056 ;
    END
  END b[266]
  PIN b[267]
    DIRECTION OUTPUT ;
    USE SIGNAL ;
    PORT
      LAYER M5 ;
        RECT  54.384 81.864 54.408 82.056 ;
    END
  END b[267]
  PIN b[268]
    DIRECTION OUTPUT ;
    USE SIGNAL ;
    PORT
      LAYER M5 ;
        RECT  54.48 81.864 54.504 82.056 ;
    END
  END b[268]
  PIN b[269]
    DIRECTION OUTPUT ;
    USE SIGNAL ;
    PORT
      LAYER M5 ;
        RECT  54.576 81.864 54.6 82.056 ;
    END
  END b[269]
  PIN b[26]
    DIRECTION OUTPUT ;
    USE SIGNAL ;
    PORT
      LAYER M5 ;
        RECT  31.248 81.864 31.272 82.056 ;
    END
  END b[26]
  PIN b[270]
    DIRECTION OUTPUT ;
    USE SIGNAL ;
    PORT
      LAYER M5 ;
        RECT  54.672 81.864 54.696 82.056 ;
    END
  END b[270]
  PIN b[271]
    DIRECTION OUTPUT ;
    USE SIGNAL ;
    PORT
      LAYER M5 ;
        RECT  54.768 81.864 54.792 82.056 ;
    END
  END b[271]
  PIN b[272]
    DIRECTION OUTPUT ;
    USE SIGNAL ;
    PORT
      LAYER M5 ;
        RECT  54.864 81.864 54.888 82.056 ;
    END
  END b[272]
  PIN b[273]
    DIRECTION OUTPUT ;
    USE SIGNAL ;
    PORT
      LAYER M5 ;
        RECT  54.96 81.864 54.984 82.056 ;
    END
  END b[273]
  PIN b[274]
    DIRECTION OUTPUT ;
    USE SIGNAL ;
    PORT
      LAYER M5 ;
        RECT  55.056 81.864 55.08 82.056 ;
    END
  END b[274]
  PIN b[275]
    DIRECTION OUTPUT ;
    USE SIGNAL ;
    PORT
      LAYER M5 ;
        RECT  55.152 81.864 55.176 82.056 ;
    END
  END b[275]
  PIN b[276]
    DIRECTION OUTPUT ;
    USE SIGNAL ;
    PORT
      LAYER M5 ;
        RECT  55.248 81.864 55.272 82.056 ;
    END
  END b[276]
  PIN b[277]
    DIRECTION OUTPUT ;
    USE SIGNAL ;
    PORT
      LAYER M5 ;
        RECT  55.344 81.864 55.368 82.056 ;
    END
  END b[277]
  PIN b[278]
    DIRECTION OUTPUT ;
    USE SIGNAL ;
    PORT
      LAYER M5 ;
        RECT  55.44 81.864 55.464 82.056 ;
    END
  END b[278]
  PIN b[279]
    DIRECTION OUTPUT ;
    USE SIGNAL ;
    PORT
      LAYER M5 ;
        RECT  55.536 81.864 55.56 82.056 ;
    END
  END b[279]
  PIN b[27]
    DIRECTION OUTPUT ;
    USE SIGNAL ;
    PORT
      LAYER M5 ;
        RECT  31.344 81.864 31.368 82.056 ;
    END
  END b[27]
  PIN b[280]
    DIRECTION OUTPUT ;
    USE SIGNAL ;
    PORT
      LAYER M5 ;
        RECT  55.632 81.864 55.656 82.056 ;
    END
  END b[280]
  PIN b[281]
    DIRECTION OUTPUT ;
    USE SIGNAL ;
    PORT
      LAYER M5 ;
        RECT  55.728 81.864 55.752 82.056 ;
    END
  END b[281]
  PIN b[282]
    DIRECTION OUTPUT ;
    USE SIGNAL ;
    PORT
      LAYER M5 ;
        RECT  55.824 81.864 55.848 82.056 ;
    END
  END b[282]
  PIN b[283]
    DIRECTION OUTPUT ;
    USE SIGNAL ;
    PORT
      LAYER M5 ;
        RECT  55.92 81.864 55.944 82.056 ;
    END
  END b[283]
  PIN b[284]
    DIRECTION OUTPUT ;
    USE SIGNAL ;
    PORT
      LAYER M5 ;
        RECT  56.016 81.864 56.04 82.056 ;
    END
  END b[284]
  PIN b[285]
    DIRECTION OUTPUT ;
    USE SIGNAL ;
    PORT
      LAYER M5 ;
        RECT  56.112 81.864 56.136 82.056 ;
    END
  END b[285]
  PIN b[286]
    DIRECTION OUTPUT ;
    USE SIGNAL ;
    PORT
      LAYER M5 ;
        RECT  56.208 81.864 56.232 82.056 ;
    END
  END b[286]
  PIN b[287]
    DIRECTION OUTPUT ;
    USE SIGNAL ;
    PORT
      LAYER M5 ;
        RECT  56.304 81.864 56.328 82.056 ;
    END
  END b[287]
  PIN b[288]
    DIRECTION OUTPUT ;
    USE SIGNAL ;
    PORT
      LAYER M5 ;
        RECT  56.4 81.864 56.424 82.056 ;
    END
  END b[288]
  PIN b[289]
    DIRECTION OUTPUT ;
    USE SIGNAL ;
    PORT
      LAYER M5 ;
        RECT  56.496 81.864 56.52 82.056 ;
    END
  END b[289]
  PIN b[28]
    DIRECTION OUTPUT ;
    USE SIGNAL ;
    PORT
      LAYER M5 ;
        RECT  31.44 81.864 31.464 82.056 ;
    END
  END b[28]
  PIN b[290]
    DIRECTION OUTPUT ;
    USE SIGNAL ;
    PORT
      LAYER M5 ;
        RECT  56.592 81.864 56.616 82.056 ;
    END
  END b[290]
  PIN b[291]
    DIRECTION OUTPUT ;
    USE SIGNAL ;
    PORT
      LAYER M5 ;
        RECT  56.688 81.864 56.712 82.056 ;
    END
  END b[291]
  PIN b[292]
    DIRECTION OUTPUT ;
    USE SIGNAL ;
    PORT
      LAYER M5 ;
        RECT  56.784 81.864 56.808 82.056 ;
    END
  END b[292]
  PIN b[293]
    DIRECTION OUTPUT ;
    USE SIGNAL ;
    PORT
      LAYER M5 ;
        RECT  56.88 81.864 56.904 82.056 ;
    END
  END b[293]
  PIN b[294]
    DIRECTION OUTPUT ;
    USE SIGNAL ;
    PORT
      LAYER M5 ;
        RECT  56.976 81.864 57 82.056 ;
    END
  END b[294]
  PIN b[295]
    DIRECTION OUTPUT ;
    USE SIGNAL ;
    PORT
      LAYER M5 ;
        RECT  57.072 81.864 57.096 82.056 ;
    END
  END b[295]
  PIN b[296]
    DIRECTION OUTPUT ;
    USE SIGNAL ;
    PORT
      LAYER M5 ;
        RECT  57.168 81.864 57.192 82.056 ;
    END
  END b[296]
  PIN b[297]
    DIRECTION OUTPUT ;
    USE SIGNAL ;
    PORT
      LAYER M5 ;
        RECT  57.264 81.864 57.288 82.056 ;
    END
  END b[297]
  PIN b[298]
    DIRECTION OUTPUT ;
    USE SIGNAL ;
    PORT
      LAYER M5 ;
        RECT  57.36 81.864 57.384 82.056 ;
    END
  END b[298]
  PIN b[299]
    DIRECTION OUTPUT ;
    USE SIGNAL ;
    PORT
      LAYER M5 ;
        RECT  57.456 81.864 57.48 82.056 ;
    END
  END b[299]
  PIN b[29]
    DIRECTION OUTPUT ;
    USE SIGNAL ;
    PORT
      LAYER M5 ;
        RECT  31.536 81.864 31.56 82.056 ;
    END
  END b[29]
  PIN b[2]
    DIRECTION OUTPUT ;
    USE SIGNAL ;
    PORT
      LAYER M5 ;
        RECT  28.944 81.864 28.968 82.056 ;
    END
  END b[2]
  PIN b[300]
    DIRECTION OUTPUT ;
    USE SIGNAL ;
    PORT
      LAYER M5 ;
        RECT  57.552 81.864 57.576 82.056 ;
    END
  END b[300]
  PIN b[301]
    DIRECTION OUTPUT ;
    USE SIGNAL ;
    PORT
      LAYER M5 ;
        RECT  57.648 81.864 57.672 82.056 ;
    END
  END b[301]
  PIN b[302]
    DIRECTION OUTPUT ;
    USE SIGNAL ;
    PORT
      LAYER M5 ;
        RECT  57.744 81.864 57.768 82.056 ;
    END
  END b[302]
  PIN b[303]
    DIRECTION OUTPUT ;
    USE SIGNAL ;
    PORT
      LAYER M5 ;
        RECT  57.84 81.864 57.864 82.056 ;
    END
  END b[303]
  PIN b[304]
    DIRECTION OUTPUT ;
    USE SIGNAL ;
    PORT
      LAYER M5 ;
        RECT  57.936 81.864 57.96 82.056 ;
    END
  END b[304]
  PIN b[305]
    DIRECTION OUTPUT ;
    USE SIGNAL ;
    PORT
      LAYER M5 ;
        RECT  58.032 81.864 58.056 82.056 ;
    END
  END b[305]
  PIN b[306]
    DIRECTION OUTPUT ;
    USE SIGNAL ;
    PORT
      LAYER M5 ;
        RECT  58.128 81.864 58.152 82.056 ;
    END
  END b[306]
  PIN b[307]
    DIRECTION OUTPUT ;
    USE SIGNAL ;
    PORT
      LAYER M5 ;
        RECT  58.224 81.864 58.248 82.056 ;
    END
  END b[307]
  PIN b[308]
    DIRECTION OUTPUT ;
    USE SIGNAL ;
    PORT
      LAYER M5 ;
        RECT  58.32 81.864 58.344 82.056 ;
    END
  END b[308]
  PIN b[309]
    DIRECTION OUTPUT ;
    USE SIGNAL ;
    PORT
      LAYER M5 ;
        RECT  58.416 81.864 58.44 82.056 ;
    END
  END b[309]
  PIN b[30]
    DIRECTION OUTPUT ;
    USE SIGNAL ;
    PORT
      LAYER M5 ;
        RECT  31.632 81.864 31.656 82.056 ;
    END
  END b[30]
  PIN b[310]
    DIRECTION OUTPUT ;
    USE SIGNAL ;
    PORT
      LAYER M5 ;
        RECT  58.512 81.864 58.536 82.056 ;
    END
  END b[310]
  PIN b[311]
    DIRECTION OUTPUT ;
    USE SIGNAL ;
    PORT
      LAYER M5 ;
        RECT  58.608 81.864 58.632 82.056 ;
    END
  END b[311]
  PIN b[312]
    DIRECTION OUTPUT ;
    USE SIGNAL ;
    PORT
      LAYER M5 ;
        RECT  58.704 81.864 58.728 82.056 ;
    END
  END b[312]
  PIN b[313]
    DIRECTION OUTPUT ;
    USE SIGNAL ;
    PORT
      LAYER M5 ;
        RECT  58.8 81.864 58.824 82.056 ;
    END
  END b[313]
  PIN b[314]
    DIRECTION OUTPUT ;
    USE SIGNAL ;
    PORT
      LAYER M5 ;
        RECT  58.896 81.864 58.92 82.056 ;
    END
  END b[314]
  PIN b[315]
    DIRECTION OUTPUT ;
    USE SIGNAL ;
    PORT
      LAYER M5 ;
        RECT  58.992 81.864 59.016 82.056 ;
    END
  END b[315]
  PIN b[316]
    DIRECTION OUTPUT ;
    USE SIGNAL ;
    PORT
      LAYER M5 ;
        RECT  59.088 81.864 59.112 82.056 ;
    END
  END b[316]
  PIN b[317]
    DIRECTION OUTPUT ;
    USE SIGNAL ;
    PORT
      LAYER M5 ;
        RECT  59.184 81.864 59.208 82.056 ;
    END
  END b[317]
  PIN b[318]
    DIRECTION OUTPUT ;
    USE SIGNAL ;
    PORT
      LAYER M5 ;
        RECT  59.28 81.864 59.304 82.056 ;
    END
  END b[318]
  PIN b[319]
    DIRECTION OUTPUT ;
    USE SIGNAL ;
    PORT
      LAYER M5 ;
        RECT  59.376 81.864 59.4 82.056 ;
    END
  END b[319]
  PIN b[31]
    DIRECTION OUTPUT ;
    USE SIGNAL ;
    PORT
      LAYER M5 ;
        RECT  31.728 81.864 31.752 82.056 ;
    END
  END b[31]
  PIN b[320]
    DIRECTION OUTPUT ;
    USE SIGNAL ;
    PORT
      LAYER M5 ;
        RECT  59.472 81.864 59.496 82.056 ;
    END
  END b[320]
  PIN b[321]
    DIRECTION OUTPUT ;
    USE SIGNAL ;
    PORT
      LAYER M5 ;
        RECT  59.568 81.864 59.592 82.056 ;
    END
  END b[321]
  PIN b[322]
    DIRECTION OUTPUT ;
    USE SIGNAL ;
    PORT
      LAYER M5 ;
        RECT  59.664 81.864 59.688 82.056 ;
    END
  END b[322]
  PIN b[323]
    DIRECTION OUTPUT ;
    USE SIGNAL ;
    PORT
      LAYER M5 ;
        RECT  59.76 81.864 59.784 82.056 ;
    END
  END b[323]
  PIN b[324]
    DIRECTION OUTPUT ;
    USE SIGNAL ;
    PORT
      LAYER M5 ;
        RECT  59.856 81.864 59.88 82.056 ;
    END
  END b[324]
  PIN b[325]
    DIRECTION OUTPUT ;
    USE SIGNAL ;
    PORT
      LAYER M5 ;
        RECT  59.952 81.864 59.976 82.056 ;
    END
  END b[325]
  PIN b[326]
    DIRECTION OUTPUT ;
    USE SIGNAL ;
    PORT
      LAYER M5 ;
        RECT  60.048 81.864 60.072 82.056 ;
    END
  END b[326]
  PIN b[327]
    DIRECTION OUTPUT ;
    USE SIGNAL ;
    PORT
      LAYER M5 ;
        RECT  60.144 81.864 60.168 82.056 ;
    END
  END b[327]
  PIN b[328]
    DIRECTION OUTPUT ;
    USE SIGNAL ;
    PORT
      LAYER M5 ;
        RECT  60.24 81.864 60.264 82.056 ;
    END
  END b[328]
  PIN b[329]
    DIRECTION OUTPUT ;
    USE SIGNAL ;
    PORT
      LAYER M5 ;
        RECT  60.336 81.864 60.36 82.056 ;
    END
  END b[329]
  PIN b[32]
    DIRECTION OUTPUT ;
    USE SIGNAL ;
    PORT
      LAYER M5 ;
        RECT  31.824 81.864 31.848 82.056 ;
    END
  END b[32]
  PIN b[330]
    DIRECTION OUTPUT ;
    USE SIGNAL ;
    PORT
      LAYER M5 ;
        RECT  60.432 81.864 60.456 82.056 ;
    END
  END b[330]
  PIN b[331]
    DIRECTION OUTPUT ;
    USE SIGNAL ;
    PORT
      LAYER M5 ;
        RECT  60.528 81.864 60.552 82.056 ;
    END
  END b[331]
  PIN b[332]
    DIRECTION OUTPUT ;
    USE SIGNAL ;
    PORT
      LAYER M5 ;
        RECT  60.624 81.864 60.648 82.056 ;
    END
  END b[332]
  PIN b[333]
    DIRECTION OUTPUT ;
    USE SIGNAL ;
    PORT
      LAYER M5 ;
        RECT  60.72 81.864 60.744 82.056 ;
    END
  END b[333]
  PIN b[334]
    DIRECTION OUTPUT ;
    USE SIGNAL ;
    PORT
      LAYER M5 ;
        RECT  60.816 81.864 60.84 82.056 ;
    END
  END b[334]
  PIN b[335]
    DIRECTION OUTPUT ;
    USE SIGNAL ;
    PORT
      LAYER M5 ;
        RECT  60.912 81.864 60.936 82.056 ;
    END
  END b[335]
  PIN b[336]
    DIRECTION OUTPUT ;
    USE SIGNAL ;
    PORT
      LAYER M5 ;
        RECT  61.008 81.864 61.032 82.056 ;
    END
  END b[336]
  PIN b[337]
    DIRECTION OUTPUT ;
    USE SIGNAL ;
    PORT
      LAYER M5 ;
        RECT  61.104 81.864 61.128 82.056 ;
    END
  END b[337]
  PIN b[338]
    DIRECTION OUTPUT ;
    USE SIGNAL ;
    PORT
      LAYER M5 ;
        RECT  61.2 81.864 61.224 82.056 ;
    END
  END b[338]
  PIN b[339]
    DIRECTION OUTPUT ;
    USE SIGNAL ;
    PORT
      LAYER M5 ;
        RECT  61.296 81.864 61.32 82.056 ;
    END
  END b[339]
  PIN b[33]
    DIRECTION OUTPUT ;
    USE SIGNAL ;
    PORT
      LAYER M5 ;
        RECT  31.92 81.864 31.944 82.056 ;
    END
  END b[33]
  PIN b[340]
    DIRECTION OUTPUT ;
    USE SIGNAL ;
    PORT
      LAYER M5 ;
        RECT  61.392 81.864 61.416 82.056 ;
    END
  END b[340]
  PIN b[341]
    DIRECTION OUTPUT ;
    USE SIGNAL ;
    PORT
      LAYER M5 ;
        RECT  61.488 81.864 61.512 82.056 ;
    END
  END b[341]
  PIN b[342]
    DIRECTION OUTPUT ;
    USE SIGNAL ;
    PORT
      LAYER M5 ;
        RECT  61.584 81.864 61.608 82.056 ;
    END
  END b[342]
  PIN b[343]
    DIRECTION OUTPUT ;
    USE SIGNAL ;
    PORT
      LAYER M5 ;
        RECT  61.68 81.864 61.704 82.056 ;
    END
  END b[343]
  PIN b[344]
    DIRECTION OUTPUT ;
    USE SIGNAL ;
    PORT
      LAYER M5 ;
        RECT  61.776 81.864 61.8 82.056 ;
    END
  END b[344]
  PIN b[345]
    DIRECTION OUTPUT ;
    USE SIGNAL ;
    PORT
      LAYER M5 ;
        RECT  61.872 81.864 61.896 82.056 ;
    END
  END b[345]
  PIN b[346]
    DIRECTION OUTPUT ;
    USE SIGNAL ;
    PORT
      LAYER M5 ;
        RECT  61.968 81.864 61.992 82.056 ;
    END
  END b[346]
  PIN b[347]
    DIRECTION OUTPUT ;
    USE SIGNAL ;
    PORT
      LAYER M5 ;
        RECT  62.064 81.864 62.088 82.056 ;
    END
  END b[347]
  PIN b[348]
    DIRECTION OUTPUT ;
    USE SIGNAL ;
    PORT
      LAYER M5 ;
        RECT  62.16 81.864 62.184 82.056 ;
    END
  END b[348]
  PIN b[349]
    DIRECTION OUTPUT ;
    USE SIGNAL ;
    PORT
      LAYER M5 ;
        RECT  62.256 81.864 62.28 82.056 ;
    END
  END b[349]
  PIN b[34]
    DIRECTION OUTPUT ;
    USE SIGNAL ;
    PORT
      LAYER M5 ;
        RECT  32.016 81.864 32.04 82.056 ;
    END
  END b[34]
  PIN b[350]
    DIRECTION OUTPUT ;
    USE SIGNAL ;
    PORT
      LAYER M5 ;
        RECT  62.352 81.864 62.376 82.056 ;
    END
  END b[350]
  PIN b[351]
    DIRECTION OUTPUT ;
    USE SIGNAL ;
    PORT
      LAYER M5 ;
        RECT  62.448 81.864 62.472 82.056 ;
    END
  END b[351]
  PIN b[352]
    DIRECTION OUTPUT ;
    USE SIGNAL ;
    PORT
      LAYER M5 ;
        RECT  62.544 81.864 62.568 82.056 ;
    END
  END b[352]
  PIN b[353]
    DIRECTION OUTPUT ;
    USE SIGNAL ;
    PORT
      LAYER M5 ;
        RECT  62.64 81.864 62.664 82.056 ;
    END
  END b[353]
  PIN b[354]
    DIRECTION OUTPUT ;
    USE SIGNAL ;
    PORT
      LAYER M5 ;
        RECT  62.736 81.864 62.76 82.056 ;
    END
  END b[354]
  PIN b[355]
    DIRECTION OUTPUT ;
    USE SIGNAL ;
    PORT
      LAYER M5 ;
        RECT  62.832 81.864 62.856 82.056 ;
    END
  END b[355]
  PIN b[356]
    DIRECTION OUTPUT ;
    USE SIGNAL ;
    PORT
      LAYER M5 ;
        RECT  62.928 81.864 62.952 82.056 ;
    END
  END b[356]
  PIN b[357]
    DIRECTION OUTPUT ;
    USE SIGNAL ;
    PORT
      LAYER M5 ;
        RECT  63.024 81.864 63.048 82.056 ;
    END
  END b[357]
  PIN b[358]
    DIRECTION OUTPUT ;
    USE SIGNAL ;
    PORT
      LAYER M5 ;
        RECT  63.12 81.864 63.144 82.056 ;
    END
  END b[358]
  PIN b[359]
    DIRECTION OUTPUT ;
    USE SIGNAL ;
    PORT
      LAYER M5 ;
        RECT  63.216 81.864 63.24 82.056 ;
    END
  END b[359]
  PIN b[35]
    DIRECTION OUTPUT ;
    USE SIGNAL ;
    PORT
      LAYER M5 ;
        RECT  32.112 81.864 32.136 82.056 ;
    END
  END b[35]
  PIN b[360]
    DIRECTION OUTPUT ;
    USE SIGNAL ;
    PORT
      LAYER M5 ;
        RECT  63.312 81.864 63.336 82.056 ;
    END
  END b[360]
  PIN b[361]
    DIRECTION OUTPUT ;
    USE SIGNAL ;
    PORT
      LAYER M5 ;
        RECT  63.408 81.864 63.432 82.056 ;
    END
  END b[361]
  PIN b[362]
    DIRECTION OUTPUT ;
    USE SIGNAL ;
    PORT
      LAYER M5 ;
        RECT  63.504 81.864 63.528 82.056 ;
    END
  END b[362]
  PIN b[363]
    DIRECTION OUTPUT ;
    USE SIGNAL ;
    PORT
      LAYER M5 ;
        RECT  63.6 81.864 63.624 82.056 ;
    END
  END b[363]
  PIN b[364]
    DIRECTION OUTPUT ;
    USE SIGNAL ;
    PORT
      LAYER M5 ;
        RECT  63.696 81.864 63.72 82.056 ;
    END
  END b[364]
  PIN b[365]
    DIRECTION OUTPUT ;
    USE SIGNAL ;
    PORT
      LAYER M5 ;
        RECT  63.792 81.864 63.816 82.056 ;
    END
  END b[365]
  PIN b[366]
    DIRECTION OUTPUT ;
    USE SIGNAL ;
    PORT
      LAYER M5 ;
        RECT  63.888 81.864 63.912 82.056 ;
    END
  END b[366]
  PIN b[367]
    DIRECTION OUTPUT ;
    USE SIGNAL ;
    PORT
      LAYER M5 ;
        RECT  63.984 81.864 64.008 82.056 ;
    END
  END b[367]
  PIN b[368]
    DIRECTION OUTPUT ;
    USE SIGNAL ;
    PORT
      LAYER M5 ;
        RECT  64.08 81.864 64.104 82.056 ;
    END
  END b[368]
  PIN b[369]
    DIRECTION OUTPUT ;
    USE SIGNAL ;
    PORT
      LAYER M5 ;
        RECT  64.176 81.864 64.2 82.056 ;
    END
  END b[369]
  PIN b[36]
    DIRECTION OUTPUT ;
    USE SIGNAL ;
    PORT
      LAYER M5 ;
        RECT  32.208 81.864 32.232 82.056 ;
    END
  END b[36]
  PIN b[370]
    DIRECTION OUTPUT ;
    USE SIGNAL ;
    PORT
      LAYER M5 ;
        RECT  64.272 81.864 64.296 82.056 ;
    END
  END b[370]
  PIN b[371]
    DIRECTION OUTPUT ;
    USE SIGNAL ;
    PORT
      LAYER M5 ;
        RECT  64.368 81.864 64.392 82.056 ;
    END
  END b[371]
  PIN b[372]
    DIRECTION OUTPUT ;
    USE SIGNAL ;
    PORT
      LAYER M5 ;
        RECT  64.464 81.864 64.488 82.056 ;
    END
  END b[372]
  PIN b[373]
    DIRECTION OUTPUT ;
    USE SIGNAL ;
    PORT
      LAYER M5 ;
        RECT  64.56 81.864 64.584 82.056 ;
    END
  END b[373]
  PIN b[374]
    DIRECTION OUTPUT ;
    USE SIGNAL ;
    PORT
      LAYER M5 ;
        RECT  64.656 81.864 64.68 82.056 ;
    END
  END b[374]
  PIN b[375]
    DIRECTION OUTPUT ;
    USE SIGNAL ;
    PORT
      LAYER M5 ;
        RECT  64.752 81.864 64.776 82.056 ;
    END
  END b[375]
  PIN b[376]
    DIRECTION OUTPUT ;
    USE SIGNAL ;
    PORT
      LAYER M5 ;
        RECT  64.848 81.864 64.872 82.056 ;
    END
  END b[376]
  PIN b[377]
    DIRECTION OUTPUT ;
    USE SIGNAL ;
    PORT
      LAYER M5 ;
        RECT  64.944 81.864 64.968 82.056 ;
    END
  END b[377]
  PIN b[378]
    DIRECTION OUTPUT ;
    USE SIGNAL ;
    PORT
      LAYER M5 ;
        RECT  65.04 81.864 65.064 82.056 ;
    END
  END b[378]
  PIN b[379]
    DIRECTION OUTPUT ;
    USE SIGNAL ;
    PORT
      LAYER M5 ;
        RECT  65.136 81.864 65.16 82.056 ;
    END
  END b[379]
  PIN b[37]
    DIRECTION OUTPUT ;
    USE SIGNAL ;
    PORT
      LAYER M5 ;
        RECT  32.304 81.864 32.328 82.056 ;
    END
  END b[37]
  PIN b[380]
    DIRECTION OUTPUT ;
    USE SIGNAL ;
    PORT
      LAYER M5 ;
        RECT  65.232 81.864 65.256 82.056 ;
    END
  END b[380]
  PIN b[381]
    DIRECTION OUTPUT ;
    USE SIGNAL ;
    PORT
      LAYER M5 ;
        RECT  65.328 81.864 65.352 82.056 ;
    END
  END b[381]
  PIN b[382]
    DIRECTION OUTPUT ;
    USE SIGNAL ;
    PORT
      LAYER M5 ;
        RECT  65.424 81.864 65.448 82.056 ;
    END
  END b[382]
  PIN b[383]
    DIRECTION OUTPUT ;
    USE SIGNAL ;
    PORT
      LAYER M5 ;
        RECT  65.52 81.864 65.544 82.056 ;
    END
  END b[383]
  PIN b[384]
    DIRECTION OUTPUT ;
    USE SIGNAL ;
    PORT
      LAYER M5 ;
        RECT  65.616 81.864 65.64 82.056 ;
    END
  END b[384]
  PIN b[385]
    DIRECTION OUTPUT ;
    USE SIGNAL ;
    PORT
      LAYER M5 ;
        RECT  65.712 81.864 65.736 82.056 ;
    END
  END b[385]
  PIN b[386]
    DIRECTION OUTPUT ;
    USE SIGNAL ;
    PORT
      LAYER M5 ;
        RECT  65.808 81.864 65.832 82.056 ;
    END
  END b[386]
  PIN b[387]
    DIRECTION OUTPUT ;
    USE SIGNAL ;
    PORT
      LAYER M5 ;
        RECT  65.904 81.864 65.928 82.056 ;
    END
  END b[387]
  PIN b[388]
    DIRECTION OUTPUT ;
    USE SIGNAL ;
    PORT
      LAYER M5 ;
        RECT  66 81.864 66.024 82.056 ;
    END
  END b[388]
  PIN b[389]
    DIRECTION OUTPUT ;
    USE SIGNAL ;
    PORT
      LAYER M5 ;
        RECT  66.096 81.864 66.12 82.056 ;
    END
  END b[389]
  PIN b[38]
    DIRECTION OUTPUT ;
    USE SIGNAL ;
    PORT
      LAYER M5 ;
        RECT  32.4 81.864 32.424 82.056 ;
    END
  END b[38]
  PIN b[390]
    DIRECTION OUTPUT ;
    USE SIGNAL ;
    PORT
      LAYER M5 ;
        RECT  66.192 81.864 66.216 82.056 ;
    END
  END b[390]
  PIN b[391]
    DIRECTION OUTPUT ;
    USE SIGNAL ;
    PORT
      LAYER M5 ;
        RECT  66.288 81.864 66.312 82.056 ;
    END
  END b[391]
  PIN b[392]
    DIRECTION OUTPUT ;
    USE SIGNAL ;
    PORT
      LAYER M5 ;
        RECT  66.384 81.864 66.408 82.056 ;
    END
  END b[392]
  PIN b[393]
    DIRECTION OUTPUT ;
    USE SIGNAL ;
    PORT
      LAYER M5 ;
        RECT  66.48 81.864 66.504 82.056 ;
    END
  END b[393]
  PIN b[394]
    DIRECTION OUTPUT ;
    USE SIGNAL ;
    PORT
      LAYER M5 ;
        RECT  66.576 81.864 66.6 82.056 ;
    END
  END b[394]
  PIN b[395]
    DIRECTION OUTPUT ;
    USE SIGNAL ;
    PORT
      LAYER M5 ;
        RECT  66.672 81.864 66.696 82.056 ;
    END
  END b[395]
  PIN b[396]
    DIRECTION OUTPUT ;
    USE SIGNAL ;
    PORT
      LAYER M5 ;
        RECT  66.768 81.864 66.792 82.056 ;
    END
  END b[396]
  PIN b[397]
    DIRECTION OUTPUT ;
    USE SIGNAL ;
    PORT
      LAYER M5 ;
        RECT  66.864 81.864 66.888 82.056 ;
    END
  END b[397]
  PIN b[398]
    DIRECTION OUTPUT ;
    USE SIGNAL ;
    PORT
      LAYER M5 ;
        RECT  66.96 81.864 66.984 82.056 ;
    END
  END b[398]
  PIN b[399]
    DIRECTION OUTPUT ;
    USE SIGNAL ;
    PORT
      LAYER M5 ;
        RECT  67.056 81.864 67.08 82.056 ;
    END
  END b[399]
  PIN b[39]
    DIRECTION OUTPUT ;
    USE SIGNAL ;
    PORT
      LAYER M5 ;
        RECT  32.496 81.864 32.52 82.056 ;
    END
  END b[39]
  PIN b[3]
    DIRECTION OUTPUT ;
    USE SIGNAL ;
    PORT
      LAYER M5 ;
        RECT  29.04 81.864 29.064 82.056 ;
    END
  END b[3]
  PIN b[400]
    DIRECTION OUTPUT ;
    USE SIGNAL ;
    PORT
      LAYER M5 ;
        RECT  67.152 81.864 67.176 82.056 ;
    END
  END b[400]
  PIN b[401]
    DIRECTION OUTPUT ;
    USE SIGNAL ;
    PORT
      LAYER M5 ;
        RECT  67.248 81.864 67.272 82.056 ;
    END
  END b[401]
  PIN b[402]
    DIRECTION OUTPUT ;
    USE SIGNAL ;
    PORT
      LAYER M5 ;
        RECT  67.344 81.864 67.368 82.056 ;
    END
  END b[402]
  PIN b[403]
    DIRECTION OUTPUT ;
    USE SIGNAL ;
    PORT
      LAYER M5 ;
        RECT  67.44 81.864 67.464 82.056 ;
    END
  END b[403]
  PIN b[404]
    DIRECTION OUTPUT ;
    USE SIGNAL ;
    PORT
      LAYER M5 ;
        RECT  67.536 81.864 67.56 82.056 ;
    END
  END b[404]
  PIN b[405]
    DIRECTION OUTPUT ;
    USE SIGNAL ;
    PORT
      LAYER M5 ;
        RECT  67.632 81.864 67.656 82.056 ;
    END
  END b[405]
  PIN b[406]
    DIRECTION OUTPUT ;
    USE SIGNAL ;
    PORT
      LAYER M5 ;
        RECT  67.728 81.864 67.752 82.056 ;
    END
  END b[406]
  PIN b[407]
    DIRECTION OUTPUT ;
    USE SIGNAL ;
    PORT
      LAYER M5 ;
        RECT  67.824 81.864 67.848 82.056 ;
    END
  END b[407]
  PIN b[408]
    DIRECTION OUTPUT ;
    USE SIGNAL ;
    PORT
      LAYER M5 ;
        RECT  67.92 81.864 67.944 82.056 ;
    END
  END b[408]
  PIN b[409]
    DIRECTION OUTPUT ;
    USE SIGNAL ;
    PORT
      LAYER M5 ;
        RECT  68.016 81.864 68.04 82.056 ;
    END
  END b[409]
  PIN b[40]
    DIRECTION OUTPUT ;
    USE SIGNAL ;
    PORT
      LAYER M5 ;
        RECT  32.592 81.864 32.616 82.056 ;
    END
  END b[40]
  PIN b[410]
    DIRECTION OUTPUT ;
    USE SIGNAL ;
    PORT
      LAYER M5 ;
        RECT  68.112 81.864 68.136 82.056 ;
    END
  END b[410]
  PIN b[411]
    DIRECTION OUTPUT ;
    USE SIGNAL ;
    PORT
      LAYER M5 ;
        RECT  68.208 81.864 68.232 82.056 ;
    END
  END b[411]
  PIN b[412]
    DIRECTION OUTPUT ;
    USE SIGNAL ;
    PORT
      LAYER M5 ;
        RECT  68.304 81.864 68.328 82.056 ;
    END
  END b[412]
  PIN b[413]
    DIRECTION OUTPUT ;
    USE SIGNAL ;
    PORT
      LAYER M5 ;
        RECT  68.4 81.864 68.424 82.056 ;
    END
  END b[413]
  PIN b[414]
    DIRECTION OUTPUT ;
    USE SIGNAL ;
    PORT
      LAYER M5 ;
        RECT  68.496 81.864 68.52 82.056 ;
    END
  END b[414]
  PIN b[415]
    DIRECTION OUTPUT ;
    USE SIGNAL ;
    PORT
      LAYER M5 ;
        RECT  68.592 81.864 68.616 82.056 ;
    END
  END b[415]
  PIN b[416]
    DIRECTION OUTPUT ;
    USE SIGNAL ;
    PORT
      LAYER M5 ;
        RECT  68.688 81.864 68.712 82.056 ;
    END
  END b[416]
  PIN b[417]
    DIRECTION OUTPUT ;
    USE SIGNAL ;
    PORT
      LAYER M5 ;
        RECT  68.784 81.864 68.808 82.056 ;
    END
  END b[417]
  PIN b[418]
    DIRECTION OUTPUT ;
    USE SIGNAL ;
    PORT
      LAYER M5 ;
        RECT  68.88 81.864 68.904 82.056 ;
    END
  END b[418]
  PIN b[419]
    DIRECTION OUTPUT ;
    USE SIGNAL ;
    PORT
      LAYER M5 ;
        RECT  68.976 81.864 69 82.056 ;
    END
  END b[419]
  PIN b[41]
    DIRECTION OUTPUT ;
    USE SIGNAL ;
    PORT
      LAYER M5 ;
        RECT  32.688 81.864 32.712 82.056 ;
    END
  END b[41]
  PIN b[420]
    DIRECTION OUTPUT ;
    USE SIGNAL ;
    PORT
      LAYER M5 ;
        RECT  69.072 81.864 69.096 82.056 ;
    END
  END b[420]
  PIN b[421]
    DIRECTION OUTPUT ;
    USE SIGNAL ;
    PORT
      LAYER M5 ;
        RECT  69.168 81.864 69.192 82.056 ;
    END
  END b[421]
  PIN b[422]
    DIRECTION OUTPUT ;
    USE SIGNAL ;
    PORT
      LAYER M5 ;
        RECT  69.264 81.864 69.288 82.056 ;
    END
  END b[422]
  PIN b[423]
    DIRECTION OUTPUT ;
    USE SIGNAL ;
    PORT
      LAYER M5 ;
        RECT  69.36 81.864 69.384 82.056 ;
    END
  END b[423]
  PIN b[424]
    DIRECTION OUTPUT ;
    USE SIGNAL ;
    PORT
      LAYER M5 ;
        RECT  69.456 81.864 69.48 82.056 ;
    END
  END b[424]
  PIN b[425]
    DIRECTION OUTPUT ;
    USE SIGNAL ;
    PORT
      LAYER M5 ;
        RECT  69.552 81.864 69.576 82.056 ;
    END
  END b[425]
  PIN b[426]
    DIRECTION OUTPUT ;
    USE SIGNAL ;
    PORT
      LAYER M5 ;
        RECT  69.648 81.864 69.672 82.056 ;
    END
  END b[426]
  PIN b[427]
    DIRECTION OUTPUT ;
    USE SIGNAL ;
    PORT
      LAYER M5 ;
        RECT  69.744 81.864 69.768 82.056 ;
    END
  END b[427]
  PIN b[428]
    DIRECTION OUTPUT ;
    USE SIGNAL ;
    PORT
      LAYER M5 ;
        RECT  69.84 81.864 69.864 82.056 ;
    END
  END b[428]
  PIN b[429]
    DIRECTION OUTPUT ;
    USE SIGNAL ;
    PORT
      LAYER M5 ;
        RECT  69.936 81.864 69.96 82.056 ;
    END
  END b[429]
  PIN b[42]
    DIRECTION OUTPUT ;
    USE SIGNAL ;
    PORT
      LAYER M5 ;
        RECT  32.784 81.864 32.808 82.056 ;
    END
  END b[42]
  PIN b[430]
    DIRECTION OUTPUT ;
    USE SIGNAL ;
    PORT
      LAYER M5 ;
        RECT  70.032 81.864 70.056 82.056 ;
    END
  END b[430]
  PIN b[431]
    DIRECTION OUTPUT ;
    USE SIGNAL ;
    PORT
      LAYER M5 ;
        RECT  70.128 81.864 70.152 82.056 ;
    END
  END b[431]
  PIN b[432]
    DIRECTION OUTPUT ;
    USE SIGNAL ;
    PORT
      LAYER M5 ;
        RECT  70.224 81.864 70.248 82.056 ;
    END
  END b[432]
  PIN b[433]
    DIRECTION OUTPUT ;
    USE SIGNAL ;
    PORT
      LAYER M5 ;
        RECT  70.32 81.864 70.344 82.056 ;
    END
  END b[433]
  PIN b[434]
    DIRECTION OUTPUT ;
    USE SIGNAL ;
    PORT
      LAYER M5 ;
        RECT  70.416 81.864 70.44 82.056 ;
    END
  END b[434]
  PIN b[435]
    DIRECTION OUTPUT ;
    USE SIGNAL ;
    PORT
      LAYER M5 ;
        RECT  70.512 81.864 70.536 82.056 ;
    END
  END b[435]
  PIN b[436]
    DIRECTION OUTPUT ;
    USE SIGNAL ;
    PORT
      LAYER M5 ;
        RECT  70.608 81.864 70.632 82.056 ;
    END
  END b[436]
  PIN b[437]
    DIRECTION OUTPUT ;
    USE SIGNAL ;
    PORT
      LAYER M5 ;
        RECT  70.704 81.864 70.728 82.056 ;
    END
  END b[437]
  PIN b[438]
    DIRECTION OUTPUT ;
    USE SIGNAL ;
    PORT
      LAYER M5 ;
        RECT  70.8 81.864 70.824 82.056 ;
    END
  END b[438]
  PIN b[439]
    DIRECTION OUTPUT ;
    USE SIGNAL ;
    PORT
      LAYER M5 ;
        RECT  70.896 81.864 70.92 82.056 ;
    END
  END b[439]
  PIN b[43]
    DIRECTION OUTPUT ;
    USE SIGNAL ;
    PORT
      LAYER M5 ;
        RECT  32.88 81.864 32.904 82.056 ;
    END
  END b[43]
  PIN b[440]
    DIRECTION OUTPUT ;
    USE SIGNAL ;
    PORT
      LAYER M5 ;
        RECT  70.992 81.864 71.016 82.056 ;
    END
  END b[440]
  PIN b[441]
    DIRECTION OUTPUT ;
    USE SIGNAL ;
    PORT
      LAYER M5 ;
        RECT  71.088 81.864 71.112 82.056 ;
    END
  END b[441]
  PIN b[442]
    DIRECTION OUTPUT ;
    USE SIGNAL ;
    PORT
      LAYER M5 ;
        RECT  71.184 81.864 71.208 82.056 ;
    END
  END b[442]
  PIN b[443]
    DIRECTION OUTPUT ;
    USE SIGNAL ;
    PORT
      LAYER M5 ;
        RECT  71.28 81.864 71.304 82.056 ;
    END
  END b[443]
  PIN b[444]
    DIRECTION OUTPUT ;
    USE SIGNAL ;
    PORT
      LAYER M5 ;
        RECT  71.376 81.864 71.4 82.056 ;
    END
  END b[444]
  PIN b[445]
    DIRECTION OUTPUT ;
    USE SIGNAL ;
    PORT
      LAYER M5 ;
        RECT  71.472 81.864 71.496 82.056 ;
    END
  END b[445]
  PIN b[446]
    DIRECTION OUTPUT ;
    USE SIGNAL ;
    PORT
      LAYER M5 ;
        RECT  71.568 81.864 71.592 82.056 ;
    END
  END b[446]
  PIN b[447]
    DIRECTION OUTPUT ;
    USE SIGNAL ;
    PORT
      LAYER M5 ;
        RECT  71.664 81.864 71.688 82.056 ;
    END
  END b[447]
  PIN b[448]
    DIRECTION OUTPUT ;
    USE SIGNAL ;
    PORT
      LAYER M5 ;
        RECT  71.76 81.864 71.784 82.056 ;
    END
  END b[448]
  PIN b[449]
    DIRECTION OUTPUT ;
    USE SIGNAL ;
    PORT
      LAYER M5 ;
        RECT  71.856 81.864 71.88 82.056 ;
    END
  END b[449]
  PIN b[44]
    DIRECTION OUTPUT ;
    USE SIGNAL ;
    PORT
      LAYER M5 ;
        RECT  32.976 81.864 33 82.056 ;
    END
  END b[44]
  PIN b[450]
    DIRECTION OUTPUT ;
    USE SIGNAL ;
    PORT
      LAYER M5 ;
        RECT  71.952 81.864 71.976 82.056 ;
    END
  END b[450]
  PIN b[451]
    DIRECTION OUTPUT ;
    USE SIGNAL ;
    PORT
      LAYER M5 ;
        RECT  72.048 81.864 72.072 82.056 ;
    END
  END b[451]
  PIN b[452]
    DIRECTION OUTPUT ;
    USE SIGNAL ;
    PORT
      LAYER M5 ;
        RECT  72.144 81.864 72.168 82.056 ;
    END
  END b[452]
  PIN b[453]
    DIRECTION OUTPUT ;
    USE SIGNAL ;
    PORT
      LAYER M5 ;
        RECT  72.24 81.864 72.264 82.056 ;
    END
  END b[453]
  PIN b[454]
    DIRECTION OUTPUT ;
    USE SIGNAL ;
    PORT
      LAYER M5 ;
        RECT  72.336 81.864 72.36 82.056 ;
    END
  END b[454]
  PIN b[455]
    DIRECTION OUTPUT ;
    USE SIGNAL ;
    PORT
      LAYER M5 ;
        RECT  72.432 81.864 72.456 82.056 ;
    END
  END b[455]
  PIN b[456]
    DIRECTION OUTPUT ;
    USE SIGNAL ;
    PORT
      LAYER M5 ;
        RECT  72.528 81.864 72.552 82.056 ;
    END
  END b[456]
  PIN b[457]
    DIRECTION OUTPUT ;
    USE SIGNAL ;
    PORT
      LAYER M5 ;
        RECT  72.624 81.864 72.648 82.056 ;
    END
  END b[457]
  PIN b[458]
    DIRECTION OUTPUT ;
    USE SIGNAL ;
    PORT
      LAYER M5 ;
        RECT  72.72 81.864 72.744 82.056 ;
    END
  END b[458]
  PIN b[459]
    DIRECTION OUTPUT ;
    USE SIGNAL ;
    PORT
      LAYER M5 ;
        RECT  72.816 81.864 72.84 82.056 ;
    END
  END b[459]
  PIN b[45]
    DIRECTION OUTPUT ;
    USE SIGNAL ;
    PORT
      LAYER M5 ;
        RECT  33.072 81.864 33.096 82.056 ;
    END
  END b[45]
  PIN b[460]
    DIRECTION OUTPUT ;
    USE SIGNAL ;
    PORT
      LAYER M5 ;
        RECT  72.912 81.864 72.936 82.056 ;
    END
  END b[460]
  PIN b[461]
    DIRECTION OUTPUT ;
    USE SIGNAL ;
    PORT
      LAYER M5 ;
        RECT  73.008 81.864 73.032 82.056 ;
    END
  END b[461]
  PIN b[462]
    DIRECTION OUTPUT ;
    USE SIGNAL ;
    PORT
      LAYER M5 ;
        RECT  73.104 81.864 73.128 82.056 ;
    END
  END b[462]
  PIN b[463]
    DIRECTION OUTPUT ;
    USE SIGNAL ;
    PORT
      LAYER M5 ;
        RECT  73.2 81.864 73.224 82.056 ;
    END
  END b[463]
  PIN b[464]
    DIRECTION OUTPUT ;
    USE SIGNAL ;
    PORT
      LAYER M5 ;
        RECT  73.296 81.864 73.32 82.056 ;
    END
  END b[464]
  PIN b[465]
    DIRECTION OUTPUT ;
    USE SIGNAL ;
    PORT
      LAYER M5 ;
        RECT  73.392 81.864 73.416 82.056 ;
    END
  END b[465]
  PIN b[466]
    DIRECTION OUTPUT ;
    USE SIGNAL ;
    PORT
      LAYER M5 ;
        RECT  73.488 81.864 73.512 82.056 ;
    END
  END b[466]
  PIN b[467]
    DIRECTION OUTPUT ;
    USE SIGNAL ;
    PORT
      LAYER M5 ;
        RECT  73.584 81.864 73.608 82.056 ;
    END
  END b[467]
  PIN b[468]
    DIRECTION OUTPUT ;
    USE SIGNAL ;
    PORT
      LAYER M5 ;
        RECT  73.68 81.864 73.704 82.056 ;
    END
  END b[468]
  PIN b[469]
    DIRECTION OUTPUT ;
    USE SIGNAL ;
    PORT
      LAYER M5 ;
        RECT  73.776 81.864 73.8 82.056 ;
    END
  END b[469]
  PIN b[46]
    DIRECTION OUTPUT ;
    USE SIGNAL ;
    PORT
      LAYER M5 ;
        RECT  33.168 81.864 33.192 82.056 ;
    END
  END b[46]
  PIN b[470]
    DIRECTION OUTPUT ;
    USE SIGNAL ;
    PORT
      LAYER M5 ;
        RECT  73.872 81.864 73.896 82.056 ;
    END
  END b[470]
  PIN b[471]
    DIRECTION OUTPUT ;
    USE SIGNAL ;
    PORT
      LAYER M5 ;
        RECT  73.968 81.864 73.992 82.056 ;
    END
  END b[471]
  PIN b[472]
    DIRECTION OUTPUT ;
    USE SIGNAL ;
    PORT
      LAYER M5 ;
        RECT  74.064 81.864 74.088 82.056 ;
    END
  END b[472]
  PIN b[473]
    DIRECTION OUTPUT ;
    USE SIGNAL ;
    PORT
      LAYER M5 ;
        RECT  74.16 81.864 74.184 82.056 ;
    END
  END b[473]
  PIN b[474]
    DIRECTION OUTPUT ;
    USE SIGNAL ;
    PORT
      LAYER M5 ;
        RECT  74.256 81.864 74.28 82.056 ;
    END
  END b[474]
  PIN b[475]
    DIRECTION OUTPUT ;
    USE SIGNAL ;
    PORT
      LAYER M5 ;
        RECT  74.352 81.864 74.376 82.056 ;
    END
  END b[475]
  PIN b[476]
    DIRECTION OUTPUT ;
    USE SIGNAL ;
    PORT
      LAYER M5 ;
        RECT  74.448 81.864 74.472 82.056 ;
    END
  END b[476]
  PIN b[477]
    DIRECTION OUTPUT ;
    USE SIGNAL ;
    PORT
      LAYER M5 ;
        RECT  74.544 81.864 74.568 82.056 ;
    END
  END b[477]
  PIN b[478]
    DIRECTION OUTPUT ;
    USE SIGNAL ;
    PORT
      LAYER M5 ;
        RECT  74.64 81.864 74.664 82.056 ;
    END
  END b[478]
  PIN b[479]
    DIRECTION OUTPUT ;
    USE SIGNAL ;
    PORT
      LAYER M5 ;
        RECT  74.736 81.864 74.76 82.056 ;
    END
  END b[479]
  PIN b[47]
    DIRECTION OUTPUT ;
    USE SIGNAL ;
    PORT
      LAYER M5 ;
        RECT  33.264 81.864 33.288 82.056 ;
    END
  END b[47]
  PIN b[480]
    DIRECTION OUTPUT ;
    USE SIGNAL ;
    PORT
      LAYER M5 ;
        RECT  74.832 81.864 74.856 82.056 ;
    END
  END b[480]
  PIN b[481]
    DIRECTION OUTPUT ;
    USE SIGNAL ;
    PORT
      LAYER M5 ;
        RECT  74.928 81.864 74.952 82.056 ;
    END
  END b[481]
  PIN b[482]
    DIRECTION OUTPUT ;
    USE SIGNAL ;
    PORT
      LAYER M5 ;
        RECT  75.024 81.864 75.048 82.056 ;
    END
  END b[482]
  PIN b[483]
    DIRECTION OUTPUT ;
    USE SIGNAL ;
    PORT
      LAYER M5 ;
        RECT  75.12 81.864 75.144 82.056 ;
    END
  END b[483]
  PIN b[484]
    DIRECTION OUTPUT ;
    USE SIGNAL ;
    PORT
      LAYER M5 ;
        RECT  75.216 81.864 75.24 82.056 ;
    END
  END b[484]
  PIN b[485]
    DIRECTION OUTPUT ;
    USE SIGNAL ;
    PORT
      LAYER M5 ;
        RECT  75.312 81.864 75.336 82.056 ;
    END
  END b[485]
  PIN b[486]
    DIRECTION OUTPUT ;
    USE SIGNAL ;
    PORT
      LAYER M5 ;
        RECT  75.408 81.864 75.432 82.056 ;
    END
  END b[486]
  PIN b[487]
    DIRECTION OUTPUT ;
    USE SIGNAL ;
    PORT
      LAYER M5 ;
        RECT  75.504 81.864 75.528 82.056 ;
    END
  END b[487]
  PIN b[488]
    DIRECTION OUTPUT ;
    USE SIGNAL ;
    PORT
      LAYER M5 ;
        RECT  75.6 81.864 75.624 82.056 ;
    END
  END b[488]
  PIN b[489]
    DIRECTION OUTPUT ;
    USE SIGNAL ;
    PORT
      LAYER M5 ;
        RECT  75.696 81.864 75.72 82.056 ;
    END
  END b[489]
  PIN b[48]
    DIRECTION OUTPUT ;
    USE SIGNAL ;
    PORT
      LAYER M5 ;
        RECT  33.36 81.864 33.384 82.056 ;
    END
  END b[48]
  PIN b[490]
    DIRECTION OUTPUT ;
    USE SIGNAL ;
    PORT
      LAYER M5 ;
        RECT  75.792 81.864 75.816 82.056 ;
    END
  END b[490]
  PIN b[491]
    DIRECTION OUTPUT ;
    USE SIGNAL ;
    PORT
      LAYER M5 ;
        RECT  75.888 81.864 75.912 82.056 ;
    END
  END b[491]
  PIN b[492]
    DIRECTION OUTPUT ;
    USE SIGNAL ;
    PORT
      LAYER M5 ;
        RECT  75.984 81.864 76.008 82.056 ;
    END
  END b[492]
  PIN b[493]
    DIRECTION OUTPUT ;
    USE SIGNAL ;
    PORT
      LAYER M5 ;
        RECT  76.08 81.864 76.104 82.056 ;
    END
  END b[493]
  PIN b[494]
    DIRECTION OUTPUT ;
    USE SIGNAL ;
    PORT
      LAYER M5 ;
        RECT  76.176 81.864 76.2 82.056 ;
    END
  END b[494]
  PIN b[495]
    DIRECTION OUTPUT ;
    USE SIGNAL ;
    PORT
      LAYER M5 ;
        RECT  76.272 81.864 76.296 82.056 ;
    END
  END b[495]
  PIN b[496]
    DIRECTION OUTPUT ;
    USE SIGNAL ;
    PORT
      LAYER M5 ;
        RECT  76.368 81.864 76.392 82.056 ;
    END
  END b[496]
  PIN b[497]
    DIRECTION OUTPUT ;
    USE SIGNAL ;
    PORT
      LAYER M5 ;
        RECT  76.464 81.864 76.488 82.056 ;
    END
  END b[497]
  PIN b[498]
    DIRECTION OUTPUT ;
    USE SIGNAL ;
    PORT
      LAYER M5 ;
        RECT  76.56 81.864 76.584 82.056 ;
    END
  END b[498]
  PIN b[499]
    DIRECTION OUTPUT ;
    USE SIGNAL ;
    PORT
      LAYER M5 ;
        RECT  76.656 81.864 76.68 82.056 ;
    END
  END b[499]
  PIN b[49]
    DIRECTION OUTPUT ;
    USE SIGNAL ;
    PORT
      LAYER M5 ;
        RECT  33.456 81.864 33.48 82.056 ;
    END
  END b[49]
  PIN b[4]
    DIRECTION OUTPUT ;
    USE SIGNAL ;
    PORT
      LAYER M5 ;
        RECT  29.136 81.864 29.16 82.056 ;
    END
  END b[4]
  PIN b[500]
    DIRECTION OUTPUT ;
    USE SIGNAL ;
    PORT
      LAYER M5 ;
        RECT  76.752 81.864 76.776 82.056 ;
    END
  END b[500]
  PIN b[501]
    DIRECTION OUTPUT ;
    USE SIGNAL ;
    PORT
      LAYER M5 ;
        RECT  76.848 81.864 76.872 82.056 ;
    END
  END b[501]
  PIN b[502]
    DIRECTION OUTPUT ;
    USE SIGNAL ;
    PORT
      LAYER M5 ;
        RECT  76.944 81.864 76.968 82.056 ;
    END
  END b[502]
  PIN b[503]
    DIRECTION OUTPUT ;
    USE SIGNAL ;
    PORT
      LAYER M5 ;
        RECT  77.04 81.864 77.064 82.056 ;
    END
  END b[503]
  PIN b[504]
    DIRECTION OUTPUT ;
    USE SIGNAL ;
    PORT
      LAYER M5 ;
        RECT  77.136 81.864 77.16 82.056 ;
    END
  END b[504]
  PIN b[505]
    DIRECTION OUTPUT ;
    USE SIGNAL ;
    PORT
      LAYER M5 ;
        RECT  77.232 81.864 77.256 82.056 ;
    END
  END b[505]
  PIN b[506]
    DIRECTION OUTPUT ;
    USE SIGNAL ;
    PORT
      LAYER M5 ;
        RECT  77.328 81.864 77.352 82.056 ;
    END
  END b[506]
  PIN b[507]
    DIRECTION OUTPUT ;
    USE SIGNAL ;
    PORT
      LAYER M5 ;
        RECT  77.424 81.864 77.448 82.056 ;
    END
  END b[507]
  PIN b[508]
    DIRECTION OUTPUT ;
    USE SIGNAL ;
    PORT
      LAYER M5 ;
        RECT  77.52 81.864 77.544 82.056 ;
    END
  END b[508]
  PIN b[509]
    DIRECTION OUTPUT ;
    USE SIGNAL ;
    PORT
      LAYER M5 ;
        RECT  77.616 81.864 77.64 82.056 ;
    END
  END b[509]
  PIN b[50]
    DIRECTION OUTPUT ;
    USE SIGNAL ;
    PORT
      LAYER M5 ;
        RECT  33.552 81.864 33.576 82.056 ;
    END
  END b[50]
  PIN b[510]
    DIRECTION OUTPUT ;
    USE SIGNAL ;
    PORT
      LAYER M5 ;
        RECT  77.712 81.864 77.736 82.056 ;
    END
  END b[510]
  PIN b[511]
    DIRECTION OUTPUT ;
    USE SIGNAL ;
    PORT
      LAYER M5 ;
        RECT  77.808 81.864 77.832 82.056 ;
    END
  END b[511]
  PIN b[512]
    DIRECTION OUTPUT ;
    USE SIGNAL ;
    PORT
      LAYER M5 ;
        RECT  77.904 81.864 77.928 82.056 ;
    END
  END b[512]
  PIN b[513]
    DIRECTION OUTPUT ;
    USE SIGNAL ;
    PORT
      LAYER M5 ;
        RECT  78 81.864 78.024 82.056 ;
    END
  END b[513]
  PIN b[514]
    DIRECTION OUTPUT ;
    USE SIGNAL ;
    PORT
      LAYER M5 ;
        RECT  78.096 81.864 78.12 82.056 ;
    END
  END b[514]
  PIN b[515]
    DIRECTION OUTPUT ;
    USE SIGNAL ;
    PORT
      LAYER M5 ;
        RECT  78.192 81.864 78.216 82.056 ;
    END
  END b[515]
  PIN b[516]
    DIRECTION OUTPUT ;
    USE SIGNAL ;
    PORT
      LAYER M5 ;
        RECT  78.288 81.864 78.312 82.056 ;
    END
  END b[516]
  PIN b[517]
    DIRECTION OUTPUT ;
    USE SIGNAL ;
    PORT
      LAYER M5 ;
        RECT  78.384 81.864 78.408 82.056 ;
    END
  END b[517]
  PIN b[518]
    DIRECTION OUTPUT ;
    USE SIGNAL ;
    PORT
      LAYER M5 ;
        RECT  78.48 81.864 78.504 82.056 ;
    END
  END b[518]
  PIN b[519]
    DIRECTION OUTPUT ;
    USE SIGNAL ;
    PORT
      LAYER M5 ;
        RECT  78.576 81.864 78.6 82.056 ;
    END
  END b[519]
  PIN b[51]
    DIRECTION OUTPUT ;
    USE SIGNAL ;
    PORT
      LAYER M5 ;
        RECT  33.648 81.864 33.672 82.056 ;
    END
  END b[51]
  PIN b[520]
    DIRECTION OUTPUT ;
    USE SIGNAL ;
    PORT
      LAYER M5 ;
        RECT  78.672 81.864 78.696 82.056 ;
    END
  END b[520]
  PIN b[521]
    DIRECTION OUTPUT ;
    USE SIGNAL ;
    PORT
      LAYER M5 ;
        RECT  78.768 81.864 78.792 82.056 ;
    END
  END b[521]
  PIN b[522]
    DIRECTION OUTPUT ;
    USE SIGNAL ;
    PORT
      LAYER M5 ;
        RECT  78.864 81.864 78.888 82.056 ;
    END
  END b[522]
  PIN b[523]
    DIRECTION OUTPUT ;
    USE SIGNAL ;
    PORT
      LAYER M5 ;
        RECT  78.96 81.864 78.984 82.056 ;
    END
  END b[523]
  PIN b[524]
    DIRECTION OUTPUT ;
    USE SIGNAL ;
    PORT
      LAYER M5 ;
        RECT  79.056 81.864 79.08 82.056 ;
    END
  END b[524]
  PIN b[525]
    DIRECTION OUTPUT ;
    USE SIGNAL ;
    PORT
      LAYER M5 ;
        RECT  79.152 81.864 79.176 82.056 ;
    END
  END b[525]
  PIN b[526]
    DIRECTION OUTPUT ;
    USE SIGNAL ;
    PORT
      LAYER M5 ;
        RECT  79.248 81.864 79.272 82.056 ;
    END
  END b[526]
  PIN b[527]
    DIRECTION OUTPUT ;
    USE SIGNAL ;
    PORT
      LAYER M5 ;
        RECT  79.344 81.864 79.368 82.056 ;
    END
  END b[527]
  PIN b[528]
    DIRECTION OUTPUT ;
    USE SIGNAL ;
    PORT
      LAYER M5 ;
        RECT  79.44 81.864 79.464 82.056 ;
    END
  END b[528]
  PIN b[529]
    DIRECTION OUTPUT ;
    USE SIGNAL ;
    PORT
      LAYER M5 ;
        RECT  79.536 81.864 79.56 82.056 ;
    END
  END b[529]
  PIN b[52]
    DIRECTION OUTPUT ;
    USE SIGNAL ;
    PORT
      LAYER M5 ;
        RECT  33.744 81.864 33.768 82.056 ;
    END
  END b[52]
  PIN b[530]
    DIRECTION OUTPUT ;
    USE SIGNAL ;
    PORT
      LAYER M5 ;
        RECT  79.632 81.864 79.656 82.056 ;
    END
  END b[530]
  PIN b[531]
    DIRECTION OUTPUT ;
    USE SIGNAL ;
    PORT
      LAYER M5 ;
        RECT  79.728 81.864 79.752 82.056 ;
    END
  END b[531]
  PIN b[532]
    DIRECTION OUTPUT ;
    USE SIGNAL ;
    PORT
      LAYER M5 ;
        RECT  79.824 81.864 79.848 82.056 ;
    END
  END b[532]
  PIN b[533]
    DIRECTION OUTPUT ;
    USE SIGNAL ;
    PORT
      LAYER M5 ;
        RECT  79.92 81.864 79.944 82.056 ;
    END
  END b[533]
  PIN b[534]
    DIRECTION OUTPUT ;
    USE SIGNAL ;
    PORT
      LAYER M5 ;
        RECT  80.016 81.864 80.04 82.056 ;
    END
  END b[534]
  PIN b[535]
    DIRECTION OUTPUT ;
    USE SIGNAL ;
    PORT
      LAYER M5 ;
        RECT  80.112 81.864 80.136 82.056 ;
    END
  END b[535]
  PIN b[536]
    DIRECTION OUTPUT ;
    USE SIGNAL ;
    PORT
      LAYER M5 ;
        RECT  80.208 81.864 80.232 82.056 ;
    END
  END b[536]
  PIN b[537]
    DIRECTION OUTPUT ;
    USE SIGNAL ;
    PORT
      LAYER M5 ;
        RECT  80.304 81.864 80.328 82.056 ;
    END
  END b[537]
  PIN b[538]
    DIRECTION OUTPUT ;
    USE SIGNAL ;
    PORT
      LAYER M5 ;
        RECT  80.4 81.864 80.424 82.056 ;
    END
  END b[538]
  PIN b[539]
    DIRECTION OUTPUT ;
    USE SIGNAL ;
    PORT
      LAYER M5 ;
        RECT  80.496 81.864 80.52 82.056 ;
    END
  END b[539]
  PIN b[53]
    DIRECTION OUTPUT ;
    USE SIGNAL ;
    PORT
      LAYER M5 ;
        RECT  33.84 81.864 33.864 82.056 ;
    END
  END b[53]
  PIN b[54]
    DIRECTION OUTPUT ;
    USE SIGNAL ;
    PORT
      LAYER M5 ;
        RECT  33.936 81.864 33.96 82.056 ;
    END
  END b[54]
  PIN b[55]
    DIRECTION OUTPUT ;
    USE SIGNAL ;
    PORT
      LAYER M5 ;
        RECT  34.032 81.864 34.056 82.056 ;
    END
  END b[55]
  PIN b[56]
    DIRECTION OUTPUT ;
    USE SIGNAL ;
    PORT
      LAYER M5 ;
        RECT  34.128 81.864 34.152 82.056 ;
    END
  END b[56]
  PIN b[57]
    DIRECTION OUTPUT ;
    USE SIGNAL ;
    PORT
      LAYER M5 ;
        RECT  34.224 81.864 34.248 82.056 ;
    END
  END b[57]
  PIN b[58]
    DIRECTION OUTPUT ;
    USE SIGNAL ;
    PORT
      LAYER M5 ;
        RECT  34.32 81.864 34.344 82.056 ;
    END
  END b[58]
  PIN b[59]
    DIRECTION OUTPUT ;
    USE SIGNAL ;
    PORT
      LAYER M5 ;
        RECT  34.416 81.864 34.44 82.056 ;
    END
  END b[59]
  PIN b[5]
    DIRECTION OUTPUT ;
    USE SIGNAL ;
    PORT
      LAYER M5 ;
        RECT  29.232 81.864 29.256 82.056 ;
    END
  END b[5]
  PIN b[60]
    DIRECTION OUTPUT ;
    USE SIGNAL ;
    PORT
      LAYER M5 ;
        RECT  34.512 81.864 34.536 82.056 ;
    END
  END b[60]
  PIN b[61]
    DIRECTION OUTPUT ;
    USE SIGNAL ;
    PORT
      LAYER M5 ;
        RECT  34.608 81.864 34.632 82.056 ;
    END
  END b[61]
  PIN b[62]
    DIRECTION OUTPUT ;
    USE SIGNAL ;
    PORT
      LAYER M5 ;
        RECT  34.704 81.864 34.728 82.056 ;
    END
  END b[62]
  PIN b[63]
    DIRECTION OUTPUT ;
    USE SIGNAL ;
    PORT
      LAYER M5 ;
        RECT  34.8 81.864 34.824 82.056 ;
    END
  END b[63]
  PIN b[64]
    DIRECTION OUTPUT ;
    USE SIGNAL ;
    PORT
      LAYER M5 ;
        RECT  34.896 81.864 34.92 82.056 ;
    END
  END b[64]
  PIN b[65]
    DIRECTION OUTPUT ;
    USE SIGNAL ;
    PORT
      LAYER M5 ;
        RECT  34.992 81.864 35.016 82.056 ;
    END
  END b[65]
  PIN b[66]
    DIRECTION OUTPUT ;
    USE SIGNAL ;
    PORT
      LAYER M5 ;
        RECT  35.088 81.864 35.112 82.056 ;
    END
  END b[66]
  PIN b[67]
    DIRECTION OUTPUT ;
    USE SIGNAL ;
    PORT
      LAYER M5 ;
        RECT  35.184 81.864 35.208 82.056 ;
    END
  END b[67]
  PIN b[68]
    DIRECTION OUTPUT ;
    USE SIGNAL ;
    PORT
      LAYER M5 ;
        RECT  35.28 81.864 35.304 82.056 ;
    END
  END b[68]
  PIN b[69]
    DIRECTION OUTPUT ;
    USE SIGNAL ;
    PORT
      LAYER M5 ;
        RECT  35.376 81.864 35.4 82.056 ;
    END
  END b[69]
  PIN b[6]
    DIRECTION OUTPUT ;
    USE SIGNAL ;
    PORT
      LAYER M5 ;
        RECT  29.328 81.864 29.352 82.056 ;
    END
  END b[6]
  PIN b[70]
    DIRECTION OUTPUT ;
    USE SIGNAL ;
    PORT
      LAYER M5 ;
        RECT  35.472 81.864 35.496 82.056 ;
    END
  END b[70]
  PIN b[71]
    DIRECTION OUTPUT ;
    USE SIGNAL ;
    PORT
      LAYER M5 ;
        RECT  35.568 81.864 35.592 82.056 ;
    END
  END b[71]
  PIN b[72]
    DIRECTION OUTPUT ;
    USE SIGNAL ;
    PORT
      LAYER M5 ;
        RECT  35.664 81.864 35.688 82.056 ;
    END
  END b[72]
  PIN b[73]
    DIRECTION OUTPUT ;
    USE SIGNAL ;
    PORT
      LAYER M5 ;
        RECT  35.76 81.864 35.784 82.056 ;
    END
  END b[73]
  PIN b[74]
    DIRECTION OUTPUT ;
    USE SIGNAL ;
    PORT
      LAYER M5 ;
        RECT  35.856 81.864 35.88 82.056 ;
    END
  END b[74]
  PIN b[75]
    DIRECTION OUTPUT ;
    USE SIGNAL ;
    PORT
      LAYER M5 ;
        RECT  35.952 81.864 35.976 82.056 ;
    END
  END b[75]
  PIN b[76]
    DIRECTION OUTPUT ;
    USE SIGNAL ;
    PORT
      LAYER M5 ;
        RECT  36.048 81.864 36.072 82.056 ;
    END
  END b[76]
  PIN b[77]
    DIRECTION OUTPUT ;
    USE SIGNAL ;
    PORT
      LAYER M5 ;
        RECT  36.144 81.864 36.168 82.056 ;
    END
  END b[77]
  PIN b[78]
    DIRECTION OUTPUT ;
    USE SIGNAL ;
    PORT
      LAYER M5 ;
        RECT  36.24 81.864 36.264 82.056 ;
    END
  END b[78]
  PIN b[79]
    DIRECTION OUTPUT ;
    USE SIGNAL ;
    PORT
      LAYER M5 ;
        RECT  36.336 81.864 36.36 82.056 ;
    END
  END b[79]
  PIN b[7]
    DIRECTION OUTPUT ;
    USE SIGNAL ;
    PORT
      LAYER M5 ;
        RECT  29.424 81.864 29.448 82.056 ;
    END
  END b[7]
  PIN b[80]
    DIRECTION OUTPUT ;
    USE SIGNAL ;
    PORT
      LAYER M5 ;
        RECT  36.432 81.864 36.456 82.056 ;
    END
  END b[80]
  PIN b[81]
    DIRECTION OUTPUT ;
    USE SIGNAL ;
    PORT
      LAYER M5 ;
        RECT  36.528 81.864 36.552 82.056 ;
    END
  END b[81]
  PIN b[82]
    DIRECTION OUTPUT ;
    USE SIGNAL ;
    PORT
      LAYER M5 ;
        RECT  36.624 81.864 36.648 82.056 ;
    END
  END b[82]
  PIN b[83]
    DIRECTION OUTPUT ;
    USE SIGNAL ;
    PORT
      LAYER M5 ;
        RECT  36.72 81.864 36.744 82.056 ;
    END
  END b[83]
  PIN b[84]
    DIRECTION OUTPUT ;
    USE SIGNAL ;
    PORT
      LAYER M5 ;
        RECT  36.816 81.864 36.84 82.056 ;
    END
  END b[84]
  PIN b[85]
    DIRECTION OUTPUT ;
    USE SIGNAL ;
    PORT
      LAYER M5 ;
        RECT  36.912 81.864 36.936 82.056 ;
    END
  END b[85]
  PIN b[86]
    DIRECTION OUTPUT ;
    USE SIGNAL ;
    PORT
      LAYER M5 ;
        RECT  37.008 81.864 37.032 82.056 ;
    END
  END b[86]
  PIN b[87]
    DIRECTION OUTPUT ;
    USE SIGNAL ;
    PORT
      LAYER M5 ;
        RECT  37.104 81.864 37.128 82.056 ;
    END
  END b[87]
  PIN b[88]
    DIRECTION OUTPUT ;
    USE SIGNAL ;
    PORT
      LAYER M5 ;
        RECT  37.2 81.864 37.224 82.056 ;
    END
  END b[88]
  PIN b[89]
    DIRECTION OUTPUT ;
    USE SIGNAL ;
    PORT
      LAYER M5 ;
        RECT  37.296 81.864 37.32 82.056 ;
    END
  END b[89]
  PIN b[8]
    DIRECTION OUTPUT ;
    USE SIGNAL ;
    PORT
      LAYER M5 ;
        RECT  29.52 81.864 29.544 82.056 ;
    END
  END b[8]
  PIN b[90]
    DIRECTION OUTPUT ;
    USE SIGNAL ;
    PORT
      LAYER M5 ;
        RECT  37.392 81.864 37.416 82.056 ;
    END
  END b[90]
  PIN b[91]
    DIRECTION OUTPUT ;
    USE SIGNAL ;
    PORT
      LAYER M5 ;
        RECT  37.488 81.864 37.512 82.056 ;
    END
  END b[91]
  PIN b[92]
    DIRECTION OUTPUT ;
    USE SIGNAL ;
    PORT
      LAYER M5 ;
        RECT  37.584 81.864 37.608 82.056 ;
    END
  END b[92]
  PIN b[93]
    DIRECTION OUTPUT ;
    USE SIGNAL ;
    PORT
      LAYER M5 ;
        RECT  37.68 81.864 37.704 82.056 ;
    END
  END b[93]
  PIN b[94]
    DIRECTION OUTPUT ;
    USE SIGNAL ;
    PORT
      LAYER M5 ;
        RECT  37.776 81.864 37.8 82.056 ;
    END
  END b[94]
  PIN b[95]
    DIRECTION OUTPUT ;
    USE SIGNAL ;
    PORT
      LAYER M5 ;
        RECT  37.872 81.864 37.896 82.056 ;
    END
  END b[95]
  PIN b[96]
    DIRECTION OUTPUT ;
    USE SIGNAL ;
    PORT
      LAYER M5 ;
        RECT  37.968 81.864 37.992 82.056 ;
    END
  END b[96]
  PIN b[97]
    DIRECTION OUTPUT ;
    USE SIGNAL ;
    PORT
      LAYER M5 ;
        RECT  38.064 81.864 38.088 82.056 ;
    END
  END b[97]
  PIN b[98]
    DIRECTION OUTPUT ;
    USE SIGNAL ;
    PORT
      LAYER M5 ;
        RECT  38.16 81.864 38.184 82.056 ;
    END
  END b[98]
  PIN b[99]
    DIRECTION OUTPUT ;
    USE SIGNAL ;
    PORT
      LAYER M5 ;
        RECT  38.256 81.864 38.28 82.056 ;
    END
  END b[99]
  PIN b[9]
    DIRECTION OUTPUT ;
    USE SIGNAL ;
    PORT
      LAYER M5 ;
        RECT  29.616 81.864 29.64 82.056 ;
    END
  END b[9]
  PIN ck[0]
    DIRECTION INPUT ;
    USE SIGNAL ;
    PORT
      LAYER M4 ;
        RECT  81 81.072 81.192 81.096 ;
    END
  END ck[0]
  PIN rst[0]
    DIRECTION INPUT ;
    USE SIGNAL ;
    PORT
      LAYER M4 ;
        RECT  81 81.36 81.192 81.384 ;
    END
  END rst[0]
  PIN t0[0]
    DIRECTION INPUT ;
    USE SIGNAL ;
    PORT
      LAYER M4 ;
        RECT  81 0.624 81.192 0.648 ;
    END
  END t0[0]
  PIN t0[100]
    DIRECTION INPUT ;
    USE SIGNAL ;
    PORT
      LAYER M4 ;
        RECT  81 10.224 81.192 10.248 ;
    END
  END t0[100]
  PIN t0[101]
    DIRECTION INPUT ;
    USE SIGNAL ;
    PORT
      LAYER M4 ;
        RECT  81 10.32 81.192 10.344 ;
    END
  END t0[101]
  PIN t0[102]
    DIRECTION INPUT ;
    USE SIGNAL ;
    PORT
      LAYER M4 ;
        RECT  81 10.416 81.192 10.44 ;
    END
  END t0[102]
  PIN t0[103]
    DIRECTION INPUT ;
    USE SIGNAL ;
    PORT
      LAYER M4 ;
        RECT  81 10.512 81.192 10.536 ;
    END
  END t0[103]
  PIN t0[104]
    DIRECTION INPUT ;
    USE SIGNAL ;
    PORT
      LAYER M4 ;
        RECT  81 10.608 81.192 10.632 ;
    END
  END t0[104]
  PIN t0[105]
    DIRECTION INPUT ;
    USE SIGNAL ;
    PORT
      LAYER M4 ;
        RECT  81 10.704 81.192 10.728 ;
    END
  END t0[105]
  PIN t0[106]
    DIRECTION INPUT ;
    USE SIGNAL ;
    PORT
      LAYER M4 ;
        RECT  81 10.8 81.192 10.824 ;
    END
  END t0[106]
  PIN t0[107]
    DIRECTION INPUT ;
    USE SIGNAL ;
    PORT
      LAYER M4 ;
        RECT  81 10.896 81.192 10.92 ;
    END
  END t0[107]
  PIN t0[108]
    DIRECTION INPUT ;
    USE SIGNAL ;
    PORT
      LAYER M4 ;
        RECT  81 10.992 81.192 11.016 ;
    END
  END t0[108]
  PIN t0[109]
    DIRECTION INPUT ;
    USE SIGNAL ;
    PORT
      LAYER M4 ;
        RECT  81 11.088 81.192 11.112 ;
    END
  END t0[109]
  PIN t0[10]
    DIRECTION INPUT ;
    USE SIGNAL ;
    PORT
      LAYER M4 ;
        RECT  81 1.584 81.192 1.608 ;
    END
  END t0[10]
  PIN t0[110]
    DIRECTION INPUT ;
    USE SIGNAL ;
    PORT
      LAYER M4 ;
        RECT  81 11.184 81.192 11.208 ;
    END
  END t0[110]
  PIN t0[111]
    DIRECTION INPUT ;
    USE SIGNAL ;
    PORT
      LAYER M4 ;
        RECT  81 11.28 81.192 11.304 ;
    END
  END t0[111]
  PIN t0[112]
    DIRECTION INPUT ;
    USE SIGNAL ;
    PORT
      LAYER M4 ;
        RECT  81 11.376 81.192 11.4 ;
    END
  END t0[112]
  PIN t0[113]
    DIRECTION INPUT ;
    USE SIGNAL ;
    PORT
      LAYER M4 ;
        RECT  81 11.472 81.192 11.496 ;
    END
  END t0[113]
  PIN t0[114]
    DIRECTION INPUT ;
    USE SIGNAL ;
    PORT
      LAYER M4 ;
        RECT  81 11.568 81.192 11.592 ;
    END
  END t0[114]
  PIN t0[115]
    DIRECTION INPUT ;
    USE SIGNAL ;
    PORT
      LAYER M4 ;
        RECT  81 11.664 81.192 11.688 ;
    END
  END t0[115]
  PIN t0[116]
    DIRECTION INPUT ;
    USE SIGNAL ;
    PORT
      LAYER M4 ;
        RECT  81 11.76 81.192 11.784 ;
    END
  END t0[116]
  PIN t0[117]
    DIRECTION INPUT ;
    USE SIGNAL ;
    PORT
      LAYER M4 ;
        RECT  81 11.856 81.192 11.88 ;
    END
  END t0[117]
  PIN t0[118]
    DIRECTION INPUT ;
    USE SIGNAL ;
    PORT
      LAYER M4 ;
        RECT  81 11.952 81.192 11.976 ;
    END
  END t0[118]
  PIN t0[119]
    DIRECTION INPUT ;
    USE SIGNAL ;
    PORT
      LAYER M4 ;
        RECT  81 12.048 81.192 12.072 ;
    END
  END t0[119]
  PIN t0[11]
    DIRECTION INPUT ;
    USE SIGNAL ;
    PORT
      LAYER M4 ;
        RECT  81 1.68 81.192 1.704 ;
    END
  END t0[11]
  PIN t0[120]
    DIRECTION INPUT ;
    USE SIGNAL ;
    PORT
      LAYER M4 ;
        RECT  81 12.144 81.192 12.168 ;
    END
  END t0[120]
  PIN t0[121]
    DIRECTION INPUT ;
    USE SIGNAL ;
    PORT
      LAYER M4 ;
        RECT  81 12.24 81.192 12.264 ;
    END
  END t0[121]
  PIN t0[122]
    DIRECTION INPUT ;
    USE SIGNAL ;
    PORT
      LAYER M4 ;
        RECT  81 12.336 81.192 12.36 ;
    END
  END t0[122]
  PIN t0[123]
    DIRECTION INPUT ;
    USE SIGNAL ;
    PORT
      LAYER M4 ;
        RECT  81 12.432 81.192 12.456 ;
    END
  END t0[123]
  PIN t0[124]
    DIRECTION INPUT ;
    USE SIGNAL ;
    PORT
      LAYER M4 ;
        RECT  81 12.528 81.192 12.552 ;
    END
  END t0[124]
  PIN t0[125]
    DIRECTION INPUT ;
    USE SIGNAL ;
    PORT
      LAYER M4 ;
        RECT  81 12.624 81.192 12.648 ;
    END
  END t0[125]
  PIN t0[126]
    DIRECTION INPUT ;
    USE SIGNAL ;
    PORT
      LAYER M4 ;
        RECT  81 12.72 81.192 12.744 ;
    END
  END t0[126]
  PIN t0[127]
    DIRECTION INPUT ;
    USE SIGNAL ;
    PORT
      LAYER M4 ;
        RECT  81 12.816 81.192 12.84 ;
    END
  END t0[127]
  PIN t0[128]
    DIRECTION INPUT ;
    USE SIGNAL ;
    PORT
      LAYER M4 ;
        RECT  81 12.912 81.192 12.936 ;
    END
  END t0[128]
  PIN t0[129]
    DIRECTION INPUT ;
    USE SIGNAL ;
    PORT
      LAYER M4 ;
        RECT  81 13.008 81.192 13.032 ;
    END
  END t0[129]
  PIN t0[12]
    DIRECTION INPUT ;
    USE SIGNAL ;
    PORT
      LAYER M4 ;
        RECT  81 1.776 81.192 1.8 ;
    END
  END t0[12]
  PIN t0[130]
    DIRECTION INPUT ;
    USE SIGNAL ;
    PORT
      LAYER M4 ;
        RECT  81 13.104 81.192 13.128 ;
    END
  END t0[130]
  PIN t0[131]
    DIRECTION INPUT ;
    USE SIGNAL ;
    PORT
      LAYER M4 ;
        RECT  81 13.2 81.192 13.224 ;
    END
  END t0[131]
  PIN t0[132]
    DIRECTION INPUT ;
    USE SIGNAL ;
    PORT
      LAYER M4 ;
        RECT  81 13.296 81.192 13.32 ;
    END
  END t0[132]
  PIN t0[133]
    DIRECTION INPUT ;
    USE SIGNAL ;
    PORT
      LAYER M4 ;
        RECT  81 13.392 81.192 13.416 ;
    END
  END t0[133]
  PIN t0[134]
    DIRECTION INPUT ;
    USE SIGNAL ;
    PORT
      LAYER M4 ;
        RECT  81 13.488 81.192 13.512 ;
    END
  END t0[134]
  PIN t0[135]
    DIRECTION INPUT ;
    USE SIGNAL ;
    PORT
      LAYER M4 ;
        RECT  81 13.584 81.192 13.608 ;
    END
  END t0[135]
  PIN t0[136]
    DIRECTION INPUT ;
    USE SIGNAL ;
    PORT
      LAYER M4 ;
        RECT  81 13.68 81.192 13.704 ;
    END
  END t0[136]
  PIN t0[137]
    DIRECTION INPUT ;
    USE SIGNAL ;
    PORT
      LAYER M4 ;
        RECT  81 13.776 81.192 13.8 ;
    END
  END t0[137]
  PIN t0[138]
    DIRECTION INPUT ;
    USE SIGNAL ;
    PORT
      LAYER M4 ;
        RECT  81 13.872 81.192 13.896 ;
    END
  END t0[138]
  PIN t0[139]
    DIRECTION INPUT ;
    USE SIGNAL ;
    PORT
      LAYER M4 ;
        RECT  81 13.968 81.192 13.992 ;
    END
  END t0[139]
  PIN t0[13]
    DIRECTION INPUT ;
    USE SIGNAL ;
    PORT
      LAYER M4 ;
        RECT  81 1.872 81.192 1.896 ;
    END
  END t0[13]
  PIN t0[140]
    DIRECTION INPUT ;
    USE SIGNAL ;
    PORT
      LAYER M4 ;
        RECT  81 14.064 81.192 14.088 ;
    END
  END t0[140]
  PIN t0[141]
    DIRECTION INPUT ;
    USE SIGNAL ;
    PORT
      LAYER M4 ;
        RECT  81 14.16 81.192 14.184 ;
    END
  END t0[141]
  PIN t0[142]
    DIRECTION INPUT ;
    USE SIGNAL ;
    PORT
      LAYER M4 ;
        RECT  81 14.256 81.192 14.28 ;
    END
  END t0[142]
  PIN t0[143]
    DIRECTION INPUT ;
    USE SIGNAL ;
    PORT
      LAYER M4 ;
        RECT  81 14.352 81.192 14.376 ;
    END
  END t0[143]
  PIN t0[144]
    DIRECTION INPUT ;
    USE SIGNAL ;
    PORT
      LAYER M4 ;
        RECT  81 14.448 81.192 14.472 ;
    END
  END t0[144]
  PIN t0[145]
    DIRECTION INPUT ;
    USE SIGNAL ;
    PORT
      LAYER M4 ;
        RECT  81 14.544 81.192 14.568 ;
    END
  END t0[145]
  PIN t0[146]
    DIRECTION INPUT ;
    USE SIGNAL ;
    PORT
      LAYER M4 ;
        RECT  81 14.64 81.192 14.664 ;
    END
  END t0[146]
  PIN t0[147]
    DIRECTION INPUT ;
    USE SIGNAL ;
    PORT
      LAYER M4 ;
        RECT  81 14.736 81.192 14.76 ;
    END
  END t0[147]
  PIN t0[148]
    DIRECTION INPUT ;
    USE SIGNAL ;
    PORT
      LAYER M4 ;
        RECT  81 14.832 81.192 14.856 ;
    END
  END t0[148]
  PIN t0[149]
    DIRECTION INPUT ;
    USE SIGNAL ;
    PORT
      LAYER M4 ;
        RECT  81 14.928 81.192 14.952 ;
    END
  END t0[149]
  PIN t0[14]
    DIRECTION INPUT ;
    USE SIGNAL ;
    PORT
      LAYER M4 ;
        RECT  81 1.968 81.192 1.992 ;
    END
  END t0[14]
  PIN t0[150]
    DIRECTION INPUT ;
    USE SIGNAL ;
    PORT
      LAYER M4 ;
        RECT  81 15.024 81.192 15.048 ;
    END
  END t0[150]
  PIN t0[151]
    DIRECTION INPUT ;
    USE SIGNAL ;
    PORT
      LAYER M4 ;
        RECT  81 15.12 81.192 15.144 ;
    END
  END t0[151]
  PIN t0[152]
    DIRECTION INPUT ;
    USE SIGNAL ;
    PORT
      LAYER M4 ;
        RECT  81 15.216 81.192 15.24 ;
    END
  END t0[152]
  PIN t0[153]
    DIRECTION INPUT ;
    USE SIGNAL ;
    PORT
      LAYER M4 ;
        RECT  81 15.312 81.192 15.336 ;
    END
  END t0[153]
  PIN t0[154]
    DIRECTION INPUT ;
    USE SIGNAL ;
    PORT
      LAYER M4 ;
        RECT  81 15.408 81.192 15.432 ;
    END
  END t0[154]
  PIN t0[155]
    DIRECTION INPUT ;
    USE SIGNAL ;
    PORT
      LAYER M4 ;
        RECT  81 15.504 81.192 15.528 ;
    END
  END t0[155]
  PIN t0[156]
    DIRECTION INPUT ;
    USE SIGNAL ;
    PORT
      LAYER M4 ;
        RECT  81 15.6 81.192 15.624 ;
    END
  END t0[156]
  PIN t0[157]
    DIRECTION INPUT ;
    USE SIGNAL ;
    PORT
      LAYER M4 ;
        RECT  81 15.696 81.192 15.72 ;
    END
  END t0[157]
  PIN t0[158]
    DIRECTION INPUT ;
    USE SIGNAL ;
    PORT
      LAYER M4 ;
        RECT  81 15.792 81.192 15.816 ;
    END
  END t0[158]
  PIN t0[159]
    DIRECTION INPUT ;
    USE SIGNAL ;
    PORT
      LAYER M4 ;
        RECT  81 15.888 81.192 15.912 ;
    END
  END t0[159]
  PIN t0[15]
    DIRECTION INPUT ;
    USE SIGNAL ;
    PORT
      LAYER M4 ;
        RECT  81 2.064 81.192 2.088 ;
    END
  END t0[15]
  PIN t0[160]
    DIRECTION INPUT ;
    USE SIGNAL ;
    PORT
      LAYER M4 ;
        RECT  81 15.984 81.192 16.008 ;
    END
  END t0[160]
  PIN t0[161]
    DIRECTION INPUT ;
    USE SIGNAL ;
    PORT
      LAYER M4 ;
        RECT  81 16.08 81.192 16.104 ;
    END
  END t0[161]
  PIN t0[162]
    DIRECTION INPUT ;
    USE SIGNAL ;
    PORT
      LAYER M4 ;
        RECT  81 16.176 81.192 16.2 ;
    END
  END t0[162]
  PIN t0[163]
    DIRECTION INPUT ;
    USE SIGNAL ;
    PORT
      LAYER M4 ;
        RECT  81 16.272 81.192 16.296 ;
    END
  END t0[163]
  PIN t0[164]
    DIRECTION INPUT ;
    USE SIGNAL ;
    PORT
      LAYER M4 ;
        RECT  81 16.368 81.192 16.392 ;
    END
  END t0[164]
  PIN t0[165]
    DIRECTION INPUT ;
    USE SIGNAL ;
    PORT
      LAYER M4 ;
        RECT  81 16.464 81.192 16.488 ;
    END
  END t0[165]
  PIN t0[166]
    DIRECTION INPUT ;
    USE SIGNAL ;
    PORT
      LAYER M4 ;
        RECT  81 16.56 81.192 16.584 ;
    END
  END t0[166]
  PIN t0[167]
    DIRECTION INPUT ;
    USE SIGNAL ;
    PORT
      LAYER M4 ;
        RECT  81 16.656 81.192 16.68 ;
    END
  END t0[167]
  PIN t0[168]
    DIRECTION INPUT ;
    USE SIGNAL ;
    PORT
      LAYER M4 ;
        RECT  81 16.752 81.192 16.776 ;
    END
  END t0[168]
  PIN t0[169]
    DIRECTION INPUT ;
    USE SIGNAL ;
    PORT
      LAYER M4 ;
        RECT  81 16.848 81.192 16.872 ;
    END
  END t0[169]
  PIN t0[16]
    DIRECTION INPUT ;
    USE SIGNAL ;
    PORT
      LAYER M4 ;
        RECT  81 2.16 81.192 2.184 ;
    END
  END t0[16]
  PIN t0[170]
    DIRECTION INPUT ;
    USE SIGNAL ;
    PORT
      LAYER M4 ;
        RECT  81 16.944 81.192 16.968 ;
    END
  END t0[170]
  PIN t0[171]
    DIRECTION INPUT ;
    USE SIGNAL ;
    PORT
      LAYER M4 ;
        RECT  81 17.04 81.192 17.064 ;
    END
  END t0[171]
  PIN t0[172]
    DIRECTION INPUT ;
    USE SIGNAL ;
    PORT
      LAYER M4 ;
        RECT  81 17.136 81.192 17.16 ;
    END
  END t0[172]
  PIN t0[173]
    DIRECTION INPUT ;
    USE SIGNAL ;
    PORT
      LAYER M4 ;
        RECT  81 17.232 81.192 17.256 ;
    END
  END t0[173]
  PIN t0[174]
    DIRECTION INPUT ;
    USE SIGNAL ;
    PORT
      LAYER M4 ;
        RECT  81 17.328 81.192 17.352 ;
    END
  END t0[174]
  PIN t0[175]
    DIRECTION INPUT ;
    USE SIGNAL ;
    PORT
      LAYER M4 ;
        RECT  81 17.424 81.192 17.448 ;
    END
  END t0[175]
  PIN t0[176]
    DIRECTION INPUT ;
    USE SIGNAL ;
    PORT
      LAYER M4 ;
        RECT  81 17.52 81.192 17.544 ;
    END
  END t0[176]
  PIN t0[177]
    DIRECTION INPUT ;
    USE SIGNAL ;
    PORT
      LAYER M4 ;
        RECT  81 17.616 81.192 17.64 ;
    END
  END t0[177]
  PIN t0[178]
    DIRECTION INPUT ;
    USE SIGNAL ;
    PORT
      LAYER M4 ;
        RECT  81 17.712 81.192 17.736 ;
    END
  END t0[178]
  PIN t0[179]
    DIRECTION INPUT ;
    USE SIGNAL ;
    PORT
      LAYER M4 ;
        RECT  81 17.808 81.192 17.832 ;
    END
  END t0[179]
  PIN t0[17]
    DIRECTION INPUT ;
    USE SIGNAL ;
    PORT
      LAYER M4 ;
        RECT  81 2.256 81.192 2.28 ;
    END
  END t0[17]
  PIN t0[180]
    DIRECTION INPUT ;
    USE SIGNAL ;
    PORT
      LAYER M4 ;
        RECT  81 17.904 81.192 17.928 ;
    END
  END t0[180]
  PIN t0[181]
    DIRECTION INPUT ;
    USE SIGNAL ;
    PORT
      LAYER M4 ;
        RECT  81 18 81.192 18.024 ;
    END
  END t0[181]
  PIN t0[182]
    DIRECTION INPUT ;
    USE SIGNAL ;
    PORT
      LAYER M4 ;
        RECT  81 18.096 81.192 18.12 ;
    END
  END t0[182]
  PIN t0[183]
    DIRECTION INPUT ;
    USE SIGNAL ;
    PORT
      LAYER M4 ;
        RECT  81 18.192 81.192 18.216 ;
    END
  END t0[183]
  PIN t0[184]
    DIRECTION INPUT ;
    USE SIGNAL ;
    PORT
      LAYER M4 ;
        RECT  81 18.288 81.192 18.312 ;
    END
  END t0[184]
  PIN t0[185]
    DIRECTION INPUT ;
    USE SIGNAL ;
    PORT
      LAYER M4 ;
        RECT  81 18.384 81.192 18.408 ;
    END
  END t0[185]
  PIN t0[186]
    DIRECTION INPUT ;
    USE SIGNAL ;
    PORT
      LAYER M4 ;
        RECT  81 18.48 81.192 18.504 ;
    END
  END t0[186]
  PIN t0[187]
    DIRECTION INPUT ;
    USE SIGNAL ;
    PORT
      LAYER M4 ;
        RECT  81 18.576 81.192 18.6 ;
    END
  END t0[187]
  PIN t0[188]
    DIRECTION INPUT ;
    USE SIGNAL ;
    PORT
      LAYER M4 ;
        RECT  81 18.672 81.192 18.696 ;
    END
  END t0[188]
  PIN t0[189]
    DIRECTION INPUT ;
    USE SIGNAL ;
    PORT
      LAYER M4 ;
        RECT  81 18.768 81.192 18.792 ;
    END
  END t0[189]
  PIN t0[18]
    DIRECTION INPUT ;
    USE SIGNAL ;
    PORT
      LAYER M4 ;
        RECT  81 2.352 81.192 2.376 ;
    END
  END t0[18]
  PIN t0[190]
    DIRECTION INPUT ;
    USE SIGNAL ;
    PORT
      LAYER M4 ;
        RECT  81 18.864 81.192 18.888 ;
    END
  END t0[190]
  PIN t0[191]
    DIRECTION INPUT ;
    USE SIGNAL ;
    PORT
      LAYER M4 ;
        RECT  81 18.96 81.192 18.984 ;
    END
  END t0[191]
  PIN t0[192]
    DIRECTION INPUT ;
    USE SIGNAL ;
    PORT
      LAYER M4 ;
        RECT  81 19.056 81.192 19.08 ;
    END
  END t0[192]
  PIN t0[193]
    DIRECTION INPUT ;
    USE SIGNAL ;
    PORT
      LAYER M4 ;
        RECT  81 19.152 81.192 19.176 ;
    END
  END t0[193]
  PIN t0[194]
    DIRECTION INPUT ;
    USE SIGNAL ;
    PORT
      LAYER M4 ;
        RECT  81 19.248 81.192 19.272 ;
    END
  END t0[194]
  PIN t0[195]
    DIRECTION INPUT ;
    USE SIGNAL ;
    PORT
      LAYER M4 ;
        RECT  81 19.344 81.192 19.368 ;
    END
  END t0[195]
  PIN t0[196]
    DIRECTION INPUT ;
    USE SIGNAL ;
    PORT
      LAYER M4 ;
        RECT  81 19.44 81.192 19.464 ;
    END
  END t0[196]
  PIN t0[197]
    DIRECTION INPUT ;
    USE SIGNAL ;
    PORT
      LAYER M4 ;
        RECT  81 19.536 81.192 19.56 ;
    END
  END t0[197]
  PIN t0[198]
    DIRECTION INPUT ;
    USE SIGNAL ;
    PORT
      LAYER M4 ;
        RECT  81 19.632 81.192 19.656 ;
    END
  END t0[198]
  PIN t0[199]
    DIRECTION INPUT ;
    USE SIGNAL ;
    PORT
      LAYER M4 ;
        RECT  81 19.728 81.192 19.752 ;
    END
  END t0[199]
  PIN t0[19]
    DIRECTION INPUT ;
    USE SIGNAL ;
    PORT
      LAYER M4 ;
        RECT  81 2.448 81.192 2.472 ;
    END
  END t0[19]
  PIN t0[1]
    DIRECTION INPUT ;
    USE SIGNAL ;
    PORT
      LAYER M4 ;
        RECT  81 0.72 81.192 0.744 ;
    END
  END t0[1]
  PIN t0[200]
    DIRECTION INPUT ;
    USE SIGNAL ;
    PORT
      LAYER M4 ;
        RECT  81 19.824 81.192 19.848 ;
    END
  END t0[200]
  PIN t0[201]
    DIRECTION INPUT ;
    USE SIGNAL ;
    PORT
      LAYER M4 ;
        RECT  81 19.92 81.192 19.944 ;
    END
  END t0[201]
  PIN t0[202]
    DIRECTION INPUT ;
    USE SIGNAL ;
    PORT
      LAYER M4 ;
        RECT  81 20.016 81.192 20.04 ;
    END
  END t0[202]
  PIN t0[203]
    DIRECTION INPUT ;
    USE SIGNAL ;
    PORT
      LAYER M4 ;
        RECT  81 20.112 81.192 20.136 ;
    END
  END t0[203]
  PIN t0[204]
    DIRECTION INPUT ;
    USE SIGNAL ;
    PORT
      LAYER M4 ;
        RECT  81 20.208 81.192 20.232 ;
    END
  END t0[204]
  PIN t0[205]
    DIRECTION INPUT ;
    USE SIGNAL ;
    PORT
      LAYER M4 ;
        RECT  81 20.304 81.192 20.328 ;
    END
  END t0[205]
  PIN t0[206]
    DIRECTION INPUT ;
    USE SIGNAL ;
    PORT
      LAYER M4 ;
        RECT  81 20.4 81.192 20.424 ;
    END
  END t0[206]
  PIN t0[207]
    DIRECTION INPUT ;
    USE SIGNAL ;
    PORT
      LAYER M4 ;
        RECT  81 20.496 81.192 20.52 ;
    END
  END t0[207]
  PIN t0[208]
    DIRECTION INPUT ;
    USE SIGNAL ;
    PORT
      LAYER M4 ;
        RECT  81 20.592 81.192 20.616 ;
    END
  END t0[208]
  PIN t0[209]
    DIRECTION INPUT ;
    USE SIGNAL ;
    PORT
      LAYER M4 ;
        RECT  81 20.688 81.192 20.712 ;
    END
  END t0[209]
  PIN t0[20]
    DIRECTION INPUT ;
    USE SIGNAL ;
    PORT
      LAYER M4 ;
        RECT  81 2.544 81.192 2.568 ;
    END
  END t0[20]
  PIN t0[210]
    DIRECTION INPUT ;
    USE SIGNAL ;
    PORT
      LAYER M4 ;
        RECT  81 20.784 81.192 20.808 ;
    END
  END t0[210]
  PIN t0[211]
    DIRECTION INPUT ;
    USE SIGNAL ;
    PORT
      LAYER M4 ;
        RECT  81 20.88 81.192 20.904 ;
    END
  END t0[211]
  PIN t0[212]
    DIRECTION INPUT ;
    USE SIGNAL ;
    PORT
      LAYER M4 ;
        RECT  81 20.976 81.192 21 ;
    END
  END t0[212]
  PIN t0[213]
    DIRECTION INPUT ;
    USE SIGNAL ;
    PORT
      LAYER M4 ;
        RECT  81 21.072 81.192 21.096 ;
    END
  END t0[213]
  PIN t0[214]
    DIRECTION INPUT ;
    USE SIGNAL ;
    PORT
      LAYER M4 ;
        RECT  81 21.168 81.192 21.192 ;
    END
  END t0[214]
  PIN t0[215]
    DIRECTION INPUT ;
    USE SIGNAL ;
    PORT
      LAYER M4 ;
        RECT  81 21.264 81.192 21.288 ;
    END
  END t0[215]
  PIN t0[216]
    DIRECTION INPUT ;
    USE SIGNAL ;
    PORT
      LAYER M4 ;
        RECT  81 21.36 81.192 21.384 ;
    END
  END t0[216]
  PIN t0[217]
    DIRECTION INPUT ;
    USE SIGNAL ;
    PORT
      LAYER M4 ;
        RECT  81 21.456 81.192 21.48 ;
    END
  END t0[217]
  PIN t0[218]
    DIRECTION INPUT ;
    USE SIGNAL ;
    PORT
      LAYER M4 ;
        RECT  81 21.552 81.192 21.576 ;
    END
  END t0[218]
  PIN t0[219]
    DIRECTION INPUT ;
    USE SIGNAL ;
    PORT
      LAYER M4 ;
        RECT  81 21.648 81.192 21.672 ;
    END
  END t0[219]
  PIN t0[21]
    DIRECTION INPUT ;
    USE SIGNAL ;
    PORT
      LAYER M4 ;
        RECT  81 2.64 81.192 2.664 ;
    END
  END t0[21]
  PIN t0[220]
    DIRECTION INPUT ;
    USE SIGNAL ;
    PORT
      LAYER M4 ;
        RECT  81 21.744 81.192 21.768 ;
    END
  END t0[220]
  PIN t0[221]
    DIRECTION INPUT ;
    USE SIGNAL ;
    PORT
      LAYER M4 ;
        RECT  81 21.84 81.192 21.864 ;
    END
  END t0[221]
  PIN t0[222]
    DIRECTION INPUT ;
    USE SIGNAL ;
    PORT
      LAYER M4 ;
        RECT  81 21.936 81.192 21.96 ;
    END
  END t0[222]
  PIN t0[223]
    DIRECTION INPUT ;
    USE SIGNAL ;
    PORT
      LAYER M4 ;
        RECT  81 22.032 81.192 22.056 ;
    END
  END t0[223]
  PIN t0[224]
    DIRECTION INPUT ;
    USE SIGNAL ;
    PORT
      LAYER M4 ;
        RECT  81 22.128 81.192 22.152 ;
    END
  END t0[224]
  PIN t0[225]
    DIRECTION INPUT ;
    USE SIGNAL ;
    PORT
      LAYER M4 ;
        RECT  81 22.224 81.192 22.248 ;
    END
  END t0[225]
  PIN t0[226]
    DIRECTION INPUT ;
    USE SIGNAL ;
    PORT
      LAYER M4 ;
        RECT  81 22.32 81.192 22.344 ;
    END
  END t0[226]
  PIN t0[227]
    DIRECTION INPUT ;
    USE SIGNAL ;
    PORT
      LAYER M4 ;
        RECT  81 22.416 81.192 22.44 ;
    END
  END t0[227]
  PIN t0[228]
    DIRECTION INPUT ;
    USE SIGNAL ;
    PORT
      LAYER M4 ;
        RECT  81 22.512 81.192 22.536 ;
    END
  END t0[228]
  PIN t0[229]
    DIRECTION INPUT ;
    USE SIGNAL ;
    PORT
      LAYER M4 ;
        RECT  81 22.608 81.192 22.632 ;
    END
  END t0[229]
  PIN t0[22]
    DIRECTION INPUT ;
    USE SIGNAL ;
    PORT
      LAYER M4 ;
        RECT  81 2.736 81.192 2.76 ;
    END
  END t0[22]
  PIN t0[230]
    DIRECTION INPUT ;
    USE SIGNAL ;
    PORT
      LAYER M4 ;
        RECT  81 22.704 81.192 22.728 ;
    END
  END t0[230]
  PIN t0[231]
    DIRECTION INPUT ;
    USE SIGNAL ;
    PORT
      LAYER M4 ;
        RECT  81 22.8 81.192 22.824 ;
    END
  END t0[231]
  PIN t0[232]
    DIRECTION INPUT ;
    USE SIGNAL ;
    PORT
      LAYER M4 ;
        RECT  81 22.896 81.192 22.92 ;
    END
  END t0[232]
  PIN t0[233]
    DIRECTION INPUT ;
    USE SIGNAL ;
    PORT
      LAYER M4 ;
        RECT  81 22.992 81.192 23.016 ;
    END
  END t0[233]
  PIN t0[234]
    DIRECTION INPUT ;
    USE SIGNAL ;
    PORT
      LAYER M4 ;
        RECT  81 23.088 81.192 23.112 ;
    END
  END t0[234]
  PIN t0[235]
    DIRECTION INPUT ;
    USE SIGNAL ;
    PORT
      LAYER M4 ;
        RECT  81 23.184 81.192 23.208 ;
    END
  END t0[235]
  PIN t0[236]
    DIRECTION INPUT ;
    USE SIGNAL ;
    PORT
      LAYER M4 ;
        RECT  81 23.28 81.192 23.304 ;
    END
  END t0[236]
  PIN t0[237]
    DIRECTION INPUT ;
    USE SIGNAL ;
    PORT
      LAYER M4 ;
        RECT  81 23.376 81.192 23.4 ;
    END
  END t0[237]
  PIN t0[238]
    DIRECTION INPUT ;
    USE SIGNAL ;
    PORT
      LAYER M4 ;
        RECT  81 23.472 81.192 23.496 ;
    END
  END t0[238]
  PIN t0[239]
    DIRECTION INPUT ;
    USE SIGNAL ;
    PORT
      LAYER M4 ;
        RECT  81 23.568 81.192 23.592 ;
    END
  END t0[239]
  PIN t0[23]
    DIRECTION INPUT ;
    USE SIGNAL ;
    PORT
      LAYER M4 ;
        RECT  81 2.832 81.192 2.856 ;
    END
  END t0[23]
  PIN t0[240]
    DIRECTION INPUT ;
    USE SIGNAL ;
    PORT
      LAYER M4 ;
        RECT  81 23.664 81.192 23.688 ;
    END
  END t0[240]
  PIN t0[241]
    DIRECTION INPUT ;
    USE SIGNAL ;
    PORT
      LAYER M4 ;
        RECT  81 23.76 81.192 23.784 ;
    END
  END t0[241]
  PIN t0[242]
    DIRECTION INPUT ;
    USE SIGNAL ;
    PORT
      LAYER M4 ;
        RECT  81 23.856 81.192 23.88 ;
    END
  END t0[242]
  PIN t0[243]
    DIRECTION INPUT ;
    USE SIGNAL ;
    PORT
      LAYER M4 ;
        RECT  81 23.952 81.192 23.976 ;
    END
  END t0[243]
  PIN t0[244]
    DIRECTION INPUT ;
    USE SIGNAL ;
    PORT
      LAYER M4 ;
        RECT  81 24.048 81.192 24.072 ;
    END
  END t0[244]
  PIN t0[245]
    DIRECTION INPUT ;
    USE SIGNAL ;
    PORT
      LAYER M4 ;
        RECT  81 24.144 81.192 24.168 ;
    END
  END t0[245]
  PIN t0[246]
    DIRECTION INPUT ;
    USE SIGNAL ;
    PORT
      LAYER M4 ;
        RECT  81 24.24 81.192 24.264 ;
    END
  END t0[246]
  PIN t0[247]
    DIRECTION INPUT ;
    USE SIGNAL ;
    PORT
      LAYER M4 ;
        RECT  81 24.336 81.192 24.36 ;
    END
  END t0[247]
  PIN t0[248]
    DIRECTION INPUT ;
    USE SIGNAL ;
    PORT
      LAYER M4 ;
        RECT  81 24.432 81.192 24.456 ;
    END
  END t0[248]
  PIN t0[249]
    DIRECTION INPUT ;
    USE SIGNAL ;
    PORT
      LAYER M4 ;
        RECT  81 24.528 81.192 24.552 ;
    END
  END t0[249]
  PIN t0[24]
    DIRECTION INPUT ;
    USE SIGNAL ;
    PORT
      LAYER M4 ;
        RECT  81 2.928 81.192 2.952 ;
    END
  END t0[24]
  PIN t0[250]
    DIRECTION INPUT ;
    USE SIGNAL ;
    PORT
      LAYER M4 ;
        RECT  81 24.624 81.192 24.648 ;
    END
  END t0[250]
  PIN t0[251]
    DIRECTION INPUT ;
    USE SIGNAL ;
    PORT
      LAYER M4 ;
        RECT  81 24.72 81.192 24.744 ;
    END
  END t0[251]
  PIN t0[252]
    DIRECTION INPUT ;
    USE SIGNAL ;
    PORT
      LAYER M4 ;
        RECT  81 24.816 81.192 24.84 ;
    END
  END t0[252]
  PIN t0[253]
    DIRECTION INPUT ;
    USE SIGNAL ;
    PORT
      LAYER M4 ;
        RECT  81 24.912 81.192 24.936 ;
    END
  END t0[253]
  PIN t0[254]
    DIRECTION INPUT ;
    USE SIGNAL ;
    PORT
      LAYER M4 ;
        RECT  81 25.008 81.192 25.032 ;
    END
  END t0[254]
  PIN t0[255]
    DIRECTION INPUT ;
    USE SIGNAL ;
    PORT
      LAYER M4 ;
        RECT  81 25.104 81.192 25.128 ;
    END
  END t0[255]
  PIN t0[256]
    DIRECTION INPUT ;
    USE SIGNAL ;
    PORT
      LAYER M4 ;
        RECT  81 25.2 81.192 25.224 ;
    END
  END t0[256]
  PIN t0[257]
    DIRECTION INPUT ;
    USE SIGNAL ;
    PORT
      LAYER M4 ;
        RECT  81 25.296 81.192 25.32 ;
    END
  END t0[257]
  PIN t0[258]
    DIRECTION INPUT ;
    USE SIGNAL ;
    PORT
      LAYER M4 ;
        RECT  81 25.392 81.192 25.416 ;
    END
  END t0[258]
  PIN t0[259]
    DIRECTION INPUT ;
    USE SIGNAL ;
    PORT
      LAYER M4 ;
        RECT  81 25.488 81.192 25.512 ;
    END
  END t0[259]
  PIN t0[25]
    DIRECTION INPUT ;
    USE SIGNAL ;
    PORT
      LAYER M4 ;
        RECT  81 3.024 81.192 3.048 ;
    END
  END t0[25]
  PIN t0[260]
    DIRECTION INPUT ;
    USE SIGNAL ;
    PORT
      LAYER M4 ;
        RECT  81 25.584 81.192 25.608 ;
    END
  END t0[260]
  PIN t0[261]
    DIRECTION INPUT ;
    USE SIGNAL ;
    PORT
      LAYER M4 ;
        RECT  81 25.68 81.192 25.704 ;
    END
  END t0[261]
  PIN t0[262]
    DIRECTION INPUT ;
    USE SIGNAL ;
    PORT
      LAYER M4 ;
        RECT  81 25.776 81.192 25.8 ;
    END
  END t0[262]
  PIN t0[263]
    DIRECTION INPUT ;
    USE SIGNAL ;
    PORT
      LAYER M4 ;
        RECT  81 25.872 81.192 25.896 ;
    END
  END t0[263]
  PIN t0[264]
    DIRECTION INPUT ;
    USE SIGNAL ;
    PORT
      LAYER M4 ;
        RECT  81 25.968 81.192 25.992 ;
    END
  END t0[264]
  PIN t0[265]
    DIRECTION INPUT ;
    USE SIGNAL ;
    PORT
      LAYER M4 ;
        RECT  81 26.064 81.192 26.088 ;
    END
  END t0[265]
  PIN t0[266]
    DIRECTION INPUT ;
    USE SIGNAL ;
    PORT
      LAYER M4 ;
        RECT  81 26.16 81.192 26.184 ;
    END
  END t0[266]
  PIN t0[267]
    DIRECTION INPUT ;
    USE SIGNAL ;
    PORT
      LAYER M4 ;
        RECT  81 26.256 81.192 26.28 ;
    END
  END t0[267]
  PIN t0[268]
    DIRECTION INPUT ;
    USE SIGNAL ;
    PORT
      LAYER M4 ;
        RECT  81 26.352 81.192 26.376 ;
    END
  END t0[268]
  PIN t0[269]
    DIRECTION INPUT ;
    USE SIGNAL ;
    PORT
      LAYER M4 ;
        RECT  81 26.448 81.192 26.472 ;
    END
  END t0[269]
  PIN t0[26]
    DIRECTION INPUT ;
    USE SIGNAL ;
    PORT
      LAYER M4 ;
        RECT  81 3.12 81.192 3.144 ;
    END
  END t0[26]
  PIN t0[27]
    DIRECTION INPUT ;
    USE SIGNAL ;
    PORT
      LAYER M4 ;
        RECT  81 3.216 81.192 3.24 ;
    END
  END t0[27]
  PIN t0[28]
    DIRECTION INPUT ;
    USE SIGNAL ;
    PORT
      LAYER M4 ;
        RECT  81 3.312 81.192 3.336 ;
    END
  END t0[28]
  PIN t0[29]
    DIRECTION INPUT ;
    USE SIGNAL ;
    PORT
      LAYER M4 ;
        RECT  81 3.408 81.192 3.432 ;
    END
  END t0[29]
  PIN t0[2]
    DIRECTION INPUT ;
    USE SIGNAL ;
    PORT
      LAYER M4 ;
        RECT  81 0.816 81.192 0.84 ;
    END
  END t0[2]
  PIN t0[30]
    DIRECTION INPUT ;
    USE SIGNAL ;
    PORT
      LAYER M4 ;
        RECT  81 3.504 81.192 3.528 ;
    END
  END t0[30]
  PIN t0[31]
    DIRECTION INPUT ;
    USE SIGNAL ;
    PORT
      LAYER M4 ;
        RECT  81 3.6 81.192 3.624 ;
    END
  END t0[31]
  PIN t0[32]
    DIRECTION INPUT ;
    USE SIGNAL ;
    PORT
      LAYER M4 ;
        RECT  81 3.696 81.192 3.72 ;
    END
  END t0[32]
  PIN t0[33]
    DIRECTION INPUT ;
    USE SIGNAL ;
    PORT
      LAYER M4 ;
        RECT  81 3.792 81.192 3.816 ;
    END
  END t0[33]
  PIN t0[34]
    DIRECTION INPUT ;
    USE SIGNAL ;
    PORT
      LAYER M4 ;
        RECT  81 3.888 81.192 3.912 ;
    END
  END t0[34]
  PIN t0[35]
    DIRECTION INPUT ;
    USE SIGNAL ;
    PORT
      LAYER M4 ;
        RECT  81 3.984 81.192 4.008 ;
    END
  END t0[35]
  PIN t0[36]
    DIRECTION INPUT ;
    USE SIGNAL ;
    PORT
      LAYER M4 ;
        RECT  81 4.08 81.192 4.104 ;
    END
  END t0[36]
  PIN t0[37]
    DIRECTION INPUT ;
    USE SIGNAL ;
    PORT
      LAYER M4 ;
        RECT  81 4.176 81.192 4.2 ;
    END
  END t0[37]
  PIN t0[38]
    DIRECTION INPUT ;
    USE SIGNAL ;
    PORT
      LAYER M4 ;
        RECT  81 4.272 81.192 4.296 ;
    END
  END t0[38]
  PIN t0[39]
    DIRECTION INPUT ;
    USE SIGNAL ;
    PORT
      LAYER M4 ;
        RECT  81 4.368 81.192 4.392 ;
    END
  END t0[39]
  PIN t0[3]
    DIRECTION INPUT ;
    USE SIGNAL ;
    PORT
      LAYER M4 ;
        RECT  81 0.912 81.192 0.936 ;
    END
  END t0[3]
  PIN t0[40]
    DIRECTION INPUT ;
    USE SIGNAL ;
    PORT
      LAYER M4 ;
        RECT  81 4.464 81.192 4.488 ;
    END
  END t0[40]
  PIN t0[41]
    DIRECTION INPUT ;
    USE SIGNAL ;
    PORT
      LAYER M4 ;
        RECT  81 4.56 81.192 4.584 ;
    END
  END t0[41]
  PIN t0[42]
    DIRECTION INPUT ;
    USE SIGNAL ;
    PORT
      LAYER M4 ;
        RECT  81 4.656 81.192 4.68 ;
    END
  END t0[42]
  PIN t0[43]
    DIRECTION INPUT ;
    USE SIGNAL ;
    PORT
      LAYER M4 ;
        RECT  81 4.752 81.192 4.776 ;
    END
  END t0[43]
  PIN t0[44]
    DIRECTION INPUT ;
    USE SIGNAL ;
    PORT
      LAYER M4 ;
        RECT  81 4.848 81.192 4.872 ;
    END
  END t0[44]
  PIN t0[45]
    DIRECTION INPUT ;
    USE SIGNAL ;
    PORT
      LAYER M4 ;
        RECT  81 4.944 81.192 4.968 ;
    END
  END t0[45]
  PIN t0[46]
    DIRECTION INPUT ;
    USE SIGNAL ;
    PORT
      LAYER M4 ;
        RECT  81 5.04 81.192 5.064 ;
    END
  END t0[46]
  PIN t0[47]
    DIRECTION INPUT ;
    USE SIGNAL ;
    PORT
      LAYER M4 ;
        RECT  81 5.136 81.192 5.16 ;
    END
  END t0[47]
  PIN t0[48]
    DIRECTION INPUT ;
    USE SIGNAL ;
    PORT
      LAYER M4 ;
        RECT  81 5.232 81.192 5.256 ;
    END
  END t0[48]
  PIN t0[49]
    DIRECTION INPUT ;
    USE SIGNAL ;
    PORT
      LAYER M4 ;
        RECT  81 5.328 81.192 5.352 ;
    END
  END t0[49]
  PIN t0[4]
    DIRECTION INPUT ;
    USE SIGNAL ;
    PORT
      LAYER M4 ;
        RECT  81 1.008 81.192 1.032 ;
    END
  END t0[4]
  PIN t0[50]
    DIRECTION INPUT ;
    USE SIGNAL ;
    PORT
      LAYER M4 ;
        RECT  81 5.424 81.192 5.448 ;
    END
  END t0[50]
  PIN t0[51]
    DIRECTION INPUT ;
    USE SIGNAL ;
    PORT
      LAYER M4 ;
        RECT  81 5.52 81.192 5.544 ;
    END
  END t0[51]
  PIN t0[52]
    DIRECTION INPUT ;
    USE SIGNAL ;
    PORT
      LAYER M4 ;
        RECT  81 5.616 81.192 5.64 ;
    END
  END t0[52]
  PIN t0[53]
    DIRECTION INPUT ;
    USE SIGNAL ;
    PORT
      LAYER M4 ;
        RECT  81 5.712 81.192 5.736 ;
    END
  END t0[53]
  PIN t0[54]
    DIRECTION INPUT ;
    USE SIGNAL ;
    PORT
      LAYER M4 ;
        RECT  81 5.808 81.192 5.832 ;
    END
  END t0[54]
  PIN t0[55]
    DIRECTION INPUT ;
    USE SIGNAL ;
    PORT
      LAYER M4 ;
        RECT  81 5.904 81.192 5.928 ;
    END
  END t0[55]
  PIN t0[56]
    DIRECTION INPUT ;
    USE SIGNAL ;
    PORT
      LAYER M4 ;
        RECT  81 6 81.192 6.024 ;
    END
  END t0[56]
  PIN t0[57]
    DIRECTION INPUT ;
    USE SIGNAL ;
    PORT
      LAYER M4 ;
        RECT  81 6.096 81.192 6.12 ;
    END
  END t0[57]
  PIN t0[58]
    DIRECTION INPUT ;
    USE SIGNAL ;
    PORT
      LAYER M4 ;
        RECT  81 6.192 81.192 6.216 ;
    END
  END t0[58]
  PIN t0[59]
    DIRECTION INPUT ;
    USE SIGNAL ;
    PORT
      LAYER M4 ;
        RECT  81 6.288 81.192 6.312 ;
    END
  END t0[59]
  PIN t0[5]
    DIRECTION INPUT ;
    USE SIGNAL ;
    PORT
      LAYER M4 ;
        RECT  81 1.104 81.192 1.128 ;
    END
  END t0[5]
  PIN t0[60]
    DIRECTION INPUT ;
    USE SIGNAL ;
    PORT
      LAYER M4 ;
        RECT  81 6.384 81.192 6.408 ;
    END
  END t0[60]
  PIN t0[61]
    DIRECTION INPUT ;
    USE SIGNAL ;
    PORT
      LAYER M4 ;
        RECT  81 6.48 81.192 6.504 ;
    END
  END t0[61]
  PIN t0[62]
    DIRECTION INPUT ;
    USE SIGNAL ;
    PORT
      LAYER M4 ;
        RECT  81 6.576 81.192 6.6 ;
    END
  END t0[62]
  PIN t0[63]
    DIRECTION INPUT ;
    USE SIGNAL ;
    PORT
      LAYER M4 ;
        RECT  81 6.672 81.192 6.696 ;
    END
  END t0[63]
  PIN t0[64]
    DIRECTION INPUT ;
    USE SIGNAL ;
    PORT
      LAYER M4 ;
        RECT  81 6.768 81.192 6.792 ;
    END
  END t0[64]
  PIN t0[65]
    DIRECTION INPUT ;
    USE SIGNAL ;
    PORT
      LAYER M4 ;
        RECT  81 6.864 81.192 6.888 ;
    END
  END t0[65]
  PIN t0[66]
    DIRECTION INPUT ;
    USE SIGNAL ;
    PORT
      LAYER M4 ;
        RECT  81 6.96 81.192 6.984 ;
    END
  END t0[66]
  PIN t0[67]
    DIRECTION INPUT ;
    USE SIGNAL ;
    PORT
      LAYER M4 ;
        RECT  81 7.056 81.192 7.08 ;
    END
  END t0[67]
  PIN t0[68]
    DIRECTION INPUT ;
    USE SIGNAL ;
    PORT
      LAYER M4 ;
        RECT  81 7.152 81.192 7.176 ;
    END
  END t0[68]
  PIN t0[69]
    DIRECTION INPUT ;
    USE SIGNAL ;
    PORT
      LAYER M4 ;
        RECT  81 7.248 81.192 7.272 ;
    END
  END t0[69]
  PIN t0[6]
    DIRECTION INPUT ;
    USE SIGNAL ;
    PORT
      LAYER M4 ;
        RECT  81 1.2 81.192 1.224 ;
    END
  END t0[6]
  PIN t0[70]
    DIRECTION INPUT ;
    USE SIGNAL ;
    PORT
      LAYER M4 ;
        RECT  81 7.344 81.192 7.368 ;
    END
  END t0[70]
  PIN t0[71]
    DIRECTION INPUT ;
    USE SIGNAL ;
    PORT
      LAYER M4 ;
        RECT  81 7.44 81.192 7.464 ;
    END
  END t0[71]
  PIN t0[72]
    DIRECTION INPUT ;
    USE SIGNAL ;
    PORT
      LAYER M4 ;
        RECT  81 7.536 81.192 7.56 ;
    END
  END t0[72]
  PIN t0[73]
    DIRECTION INPUT ;
    USE SIGNAL ;
    PORT
      LAYER M4 ;
        RECT  81 7.632 81.192 7.656 ;
    END
  END t0[73]
  PIN t0[74]
    DIRECTION INPUT ;
    USE SIGNAL ;
    PORT
      LAYER M4 ;
        RECT  81 7.728 81.192 7.752 ;
    END
  END t0[74]
  PIN t0[75]
    DIRECTION INPUT ;
    USE SIGNAL ;
    PORT
      LAYER M4 ;
        RECT  81 7.824 81.192 7.848 ;
    END
  END t0[75]
  PIN t0[76]
    DIRECTION INPUT ;
    USE SIGNAL ;
    PORT
      LAYER M4 ;
        RECT  81 7.92 81.192 7.944 ;
    END
  END t0[76]
  PIN t0[77]
    DIRECTION INPUT ;
    USE SIGNAL ;
    PORT
      LAYER M4 ;
        RECT  81 8.016 81.192 8.04 ;
    END
  END t0[77]
  PIN t0[78]
    DIRECTION INPUT ;
    USE SIGNAL ;
    PORT
      LAYER M4 ;
        RECT  81 8.112 81.192 8.136 ;
    END
  END t0[78]
  PIN t0[79]
    DIRECTION INPUT ;
    USE SIGNAL ;
    PORT
      LAYER M4 ;
        RECT  81 8.208 81.192 8.232 ;
    END
  END t0[79]
  PIN t0[7]
    DIRECTION INPUT ;
    USE SIGNAL ;
    PORT
      LAYER M4 ;
        RECT  81 1.296 81.192 1.32 ;
    END
  END t0[7]
  PIN t0[80]
    DIRECTION INPUT ;
    USE SIGNAL ;
    PORT
      LAYER M4 ;
        RECT  81 8.304 81.192 8.328 ;
    END
  END t0[80]
  PIN t0[81]
    DIRECTION INPUT ;
    USE SIGNAL ;
    PORT
      LAYER M4 ;
        RECT  81 8.4 81.192 8.424 ;
    END
  END t0[81]
  PIN t0[82]
    DIRECTION INPUT ;
    USE SIGNAL ;
    PORT
      LAYER M4 ;
        RECT  81 8.496 81.192 8.52 ;
    END
  END t0[82]
  PIN t0[83]
    DIRECTION INPUT ;
    USE SIGNAL ;
    PORT
      LAYER M4 ;
        RECT  81 8.592 81.192 8.616 ;
    END
  END t0[83]
  PIN t0[84]
    DIRECTION INPUT ;
    USE SIGNAL ;
    PORT
      LAYER M4 ;
        RECT  81 8.688 81.192 8.712 ;
    END
  END t0[84]
  PIN t0[85]
    DIRECTION INPUT ;
    USE SIGNAL ;
    PORT
      LAYER M4 ;
        RECT  81 8.784 81.192 8.808 ;
    END
  END t0[85]
  PIN t0[86]
    DIRECTION INPUT ;
    USE SIGNAL ;
    PORT
      LAYER M4 ;
        RECT  81 8.88 81.192 8.904 ;
    END
  END t0[86]
  PIN t0[87]
    DIRECTION INPUT ;
    USE SIGNAL ;
    PORT
      LAYER M4 ;
        RECT  81 8.976 81.192 9 ;
    END
  END t0[87]
  PIN t0[88]
    DIRECTION INPUT ;
    USE SIGNAL ;
    PORT
      LAYER M4 ;
        RECT  81 9.072 81.192 9.096 ;
    END
  END t0[88]
  PIN t0[89]
    DIRECTION INPUT ;
    USE SIGNAL ;
    PORT
      LAYER M4 ;
        RECT  81 9.168 81.192 9.192 ;
    END
  END t0[89]
  PIN t0[8]
    DIRECTION INPUT ;
    USE SIGNAL ;
    PORT
      LAYER M4 ;
        RECT  81 1.392 81.192 1.416 ;
    END
  END t0[8]
  PIN t0[90]
    DIRECTION INPUT ;
    USE SIGNAL ;
    PORT
      LAYER M4 ;
        RECT  81 9.264 81.192 9.288 ;
    END
  END t0[90]
  PIN t0[91]
    DIRECTION INPUT ;
    USE SIGNAL ;
    PORT
      LAYER M4 ;
        RECT  81 9.36 81.192 9.384 ;
    END
  END t0[91]
  PIN t0[92]
    DIRECTION INPUT ;
    USE SIGNAL ;
    PORT
      LAYER M4 ;
        RECT  81 9.456 81.192 9.48 ;
    END
  END t0[92]
  PIN t0[93]
    DIRECTION INPUT ;
    USE SIGNAL ;
    PORT
      LAYER M4 ;
        RECT  81 9.552 81.192 9.576 ;
    END
  END t0[93]
  PIN t0[94]
    DIRECTION INPUT ;
    USE SIGNAL ;
    PORT
      LAYER M4 ;
        RECT  81 9.648 81.192 9.672 ;
    END
  END t0[94]
  PIN t0[95]
    DIRECTION INPUT ;
    USE SIGNAL ;
    PORT
      LAYER M4 ;
        RECT  81 9.744 81.192 9.768 ;
    END
  END t0[95]
  PIN t0[96]
    DIRECTION INPUT ;
    USE SIGNAL ;
    PORT
      LAYER M4 ;
        RECT  81 9.84 81.192 9.864 ;
    END
  END t0[96]
  PIN t0[97]
    DIRECTION INPUT ;
    USE SIGNAL ;
    PORT
      LAYER M4 ;
        RECT  81 9.936 81.192 9.96 ;
    END
  END t0[97]
  PIN t0[98]
    DIRECTION INPUT ;
    USE SIGNAL ;
    PORT
      LAYER M4 ;
        RECT  81 10.032 81.192 10.056 ;
    END
  END t0[98]
  PIN t0[99]
    DIRECTION INPUT ;
    USE SIGNAL ;
    PORT
      LAYER M4 ;
        RECT  81 10.128 81.192 10.152 ;
    END
  END t0[99]
  PIN t0[9]
    DIRECTION INPUT ;
    USE SIGNAL ;
    PORT
      LAYER M4 ;
        RECT  81 1.488 81.192 1.512 ;
    END
  END t0[9]
  PIN t1[0]
    DIRECTION INPUT ;
    USE SIGNAL ;
    PORT
      LAYER M4 ;
        RECT  81 54.96 81.192 54.984 ;
    END
  END t1[0]
  PIN t1[100]
    DIRECTION INPUT ;
    USE SIGNAL ;
    PORT
      LAYER M4 ;
        RECT  81 64.56 81.192 64.584 ;
    END
  END t1[100]
  PIN t1[101]
    DIRECTION INPUT ;
    USE SIGNAL ;
    PORT
      LAYER M4 ;
        RECT  81 64.656 81.192 64.68 ;
    END
  END t1[101]
  PIN t1[102]
    DIRECTION INPUT ;
    USE SIGNAL ;
    PORT
      LAYER M4 ;
        RECT  81 64.752 81.192 64.776 ;
    END
  END t1[102]
  PIN t1[103]
    DIRECTION INPUT ;
    USE SIGNAL ;
    PORT
      LAYER M4 ;
        RECT  81 64.848 81.192 64.872 ;
    END
  END t1[103]
  PIN t1[104]
    DIRECTION INPUT ;
    USE SIGNAL ;
    PORT
      LAYER M4 ;
        RECT  81 64.944 81.192 64.968 ;
    END
  END t1[104]
  PIN t1[105]
    DIRECTION INPUT ;
    USE SIGNAL ;
    PORT
      LAYER M4 ;
        RECT  81 65.04 81.192 65.064 ;
    END
  END t1[105]
  PIN t1[106]
    DIRECTION INPUT ;
    USE SIGNAL ;
    PORT
      LAYER M4 ;
        RECT  81 65.136 81.192 65.16 ;
    END
  END t1[106]
  PIN t1[107]
    DIRECTION INPUT ;
    USE SIGNAL ;
    PORT
      LAYER M4 ;
        RECT  81 65.232 81.192 65.256 ;
    END
  END t1[107]
  PIN t1[108]
    DIRECTION INPUT ;
    USE SIGNAL ;
    PORT
      LAYER M4 ;
        RECT  81 65.328 81.192 65.352 ;
    END
  END t1[108]
  PIN t1[109]
    DIRECTION INPUT ;
    USE SIGNAL ;
    PORT
      LAYER M4 ;
        RECT  81 65.424 81.192 65.448 ;
    END
  END t1[109]
  PIN t1[10]
    DIRECTION INPUT ;
    USE SIGNAL ;
    PORT
      LAYER M4 ;
        RECT  81 55.92 81.192 55.944 ;
    END
  END t1[10]
  PIN t1[110]
    DIRECTION INPUT ;
    USE SIGNAL ;
    PORT
      LAYER M4 ;
        RECT  81 65.52 81.192 65.544 ;
    END
  END t1[110]
  PIN t1[111]
    DIRECTION INPUT ;
    USE SIGNAL ;
    PORT
      LAYER M4 ;
        RECT  81 65.616 81.192 65.64 ;
    END
  END t1[111]
  PIN t1[112]
    DIRECTION INPUT ;
    USE SIGNAL ;
    PORT
      LAYER M4 ;
        RECT  81 65.712 81.192 65.736 ;
    END
  END t1[112]
  PIN t1[113]
    DIRECTION INPUT ;
    USE SIGNAL ;
    PORT
      LAYER M4 ;
        RECT  81 65.808 81.192 65.832 ;
    END
  END t1[113]
  PIN t1[114]
    DIRECTION INPUT ;
    USE SIGNAL ;
    PORT
      LAYER M4 ;
        RECT  81 65.904 81.192 65.928 ;
    END
  END t1[114]
  PIN t1[115]
    DIRECTION INPUT ;
    USE SIGNAL ;
    PORT
      LAYER M4 ;
        RECT  81 66 81.192 66.024 ;
    END
  END t1[115]
  PIN t1[116]
    DIRECTION INPUT ;
    USE SIGNAL ;
    PORT
      LAYER M4 ;
        RECT  81 66.096 81.192 66.12 ;
    END
  END t1[116]
  PIN t1[117]
    DIRECTION INPUT ;
    USE SIGNAL ;
    PORT
      LAYER M4 ;
        RECT  81 66.192 81.192 66.216 ;
    END
  END t1[117]
  PIN t1[118]
    DIRECTION INPUT ;
    USE SIGNAL ;
    PORT
      LAYER M4 ;
        RECT  81 66.288 81.192 66.312 ;
    END
  END t1[118]
  PIN t1[119]
    DIRECTION INPUT ;
    USE SIGNAL ;
    PORT
      LAYER M4 ;
        RECT  81 66.384 81.192 66.408 ;
    END
  END t1[119]
  PIN t1[11]
    DIRECTION INPUT ;
    USE SIGNAL ;
    PORT
      LAYER M4 ;
        RECT  81 56.016 81.192 56.04 ;
    END
  END t1[11]
  PIN t1[120]
    DIRECTION INPUT ;
    USE SIGNAL ;
    PORT
      LAYER M4 ;
        RECT  81 66.48 81.192 66.504 ;
    END
  END t1[120]
  PIN t1[121]
    DIRECTION INPUT ;
    USE SIGNAL ;
    PORT
      LAYER M4 ;
        RECT  81 66.576 81.192 66.6 ;
    END
  END t1[121]
  PIN t1[122]
    DIRECTION INPUT ;
    USE SIGNAL ;
    PORT
      LAYER M4 ;
        RECT  81 66.672 81.192 66.696 ;
    END
  END t1[122]
  PIN t1[123]
    DIRECTION INPUT ;
    USE SIGNAL ;
    PORT
      LAYER M4 ;
        RECT  81 66.768 81.192 66.792 ;
    END
  END t1[123]
  PIN t1[124]
    DIRECTION INPUT ;
    USE SIGNAL ;
    PORT
      LAYER M4 ;
        RECT  81 66.864 81.192 66.888 ;
    END
  END t1[124]
  PIN t1[125]
    DIRECTION INPUT ;
    USE SIGNAL ;
    PORT
      LAYER M4 ;
        RECT  81 66.96 81.192 66.984 ;
    END
  END t1[125]
  PIN t1[126]
    DIRECTION INPUT ;
    USE SIGNAL ;
    PORT
      LAYER M4 ;
        RECT  81 67.056 81.192 67.08 ;
    END
  END t1[126]
  PIN t1[127]
    DIRECTION INPUT ;
    USE SIGNAL ;
    PORT
      LAYER M4 ;
        RECT  81 67.152 81.192 67.176 ;
    END
  END t1[127]
  PIN t1[128]
    DIRECTION INPUT ;
    USE SIGNAL ;
    PORT
      LAYER M4 ;
        RECT  81 67.248 81.192 67.272 ;
    END
  END t1[128]
  PIN t1[129]
    DIRECTION INPUT ;
    USE SIGNAL ;
    PORT
      LAYER M4 ;
        RECT  81 67.344 81.192 67.368 ;
    END
  END t1[129]
  PIN t1[12]
    DIRECTION INPUT ;
    USE SIGNAL ;
    PORT
      LAYER M4 ;
        RECT  81 56.112 81.192 56.136 ;
    END
  END t1[12]
  PIN t1[130]
    DIRECTION INPUT ;
    USE SIGNAL ;
    PORT
      LAYER M4 ;
        RECT  81 67.44 81.192 67.464 ;
    END
  END t1[130]
  PIN t1[131]
    DIRECTION INPUT ;
    USE SIGNAL ;
    PORT
      LAYER M4 ;
        RECT  81 67.536 81.192 67.56 ;
    END
  END t1[131]
  PIN t1[132]
    DIRECTION INPUT ;
    USE SIGNAL ;
    PORT
      LAYER M4 ;
        RECT  81 67.632 81.192 67.656 ;
    END
  END t1[132]
  PIN t1[133]
    DIRECTION INPUT ;
    USE SIGNAL ;
    PORT
      LAYER M4 ;
        RECT  81 67.728 81.192 67.752 ;
    END
  END t1[133]
  PIN t1[134]
    DIRECTION INPUT ;
    USE SIGNAL ;
    PORT
      LAYER M4 ;
        RECT  81 67.824 81.192 67.848 ;
    END
  END t1[134]
  PIN t1[135]
    DIRECTION INPUT ;
    USE SIGNAL ;
    PORT
      LAYER M4 ;
        RECT  81 67.92 81.192 67.944 ;
    END
  END t1[135]
  PIN t1[136]
    DIRECTION INPUT ;
    USE SIGNAL ;
    PORT
      LAYER M4 ;
        RECT  81 68.016 81.192 68.04 ;
    END
  END t1[136]
  PIN t1[137]
    DIRECTION INPUT ;
    USE SIGNAL ;
    PORT
      LAYER M4 ;
        RECT  81 68.112 81.192 68.136 ;
    END
  END t1[137]
  PIN t1[138]
    DIRECTION INPUT ;
    USE SIGNAL ;
    PORT
      LAYER M4 ;
        RECT  81 68.208 81.192 68.232 ;
    END
  END t1[138]
  PIN t1[139]
    DIRECTION INPUT ;
    USE SIGNAL ;
    PORT
      LAYER M4 ;
        RECT  81 68.304 81.192 68.328 ;
    END
  END t1[139]
  PIN t1[13]
    DIRECTION INPUT ;
    USE SIGNAL ;
    PORT
      LAYER M4 ;
        RECT  81 56.208 81.192 56.232 ;
    END
  END t1[13]
  PIN t1[140]
    DIRECTION INPUT ;
    USE SIGNAL ;
    PORT
      LAYER M4 ;
        RECT  81 68.4 81.192 68.424 ;
    END
  END t1[140]
  PIN t1[141]
    DIRECTION INPUT ;
    USE SIGNAL ;
    PORT
      LAYER M4 ;
        RECT  81 68.496 81.192 68.52 ;
    END
  END t1[141]
  PIN t1[142]
    DIRECTION INPUT ;
    USE SIGNAL ;
    PORT
      LAYER M4 ;
        RECT  81 68.592 81.192 68.616 ;
    END
  END t1[142]
  PIN t1[143]
    DIRECTION INPUT ;
    USE SIGNAL ;
    PORT
      LAYER M4 ;
        RECT  81 68.688 81.192 68.712 ;
    END
  END t1[143]
  PIN t1[144]
    DIRECTION INPUT ;
    USE SIGNAL ;
    PORT
      LAYER M4 ;
        RECT  81 68.784 81.192 68.808 ;
    END
  END t1[144]
  PIN t1[145]
    DIRECTION INPUT ;
    USE SIGNAL ;
    PORT
      LAYER M4 ;
        RECT  81 68.88 81.192 68.904 ;
    END
  END t1[145]
  PIN t1[146]
    DIRECTION INPUT ;
    USE SIGNAL ;
    PORT
      LAYER M4 ;
        RECT  81 68.976 81.192 69 ;
    END
  END t1[146]
  PIN t1[147]
    DIRECTION INPUT ;
    USE SIGNAL ;
    PORT
      LAYER M4 ;
        RECT  81 69.072 81.192 69.096 ;
    END
  END t1[147]
  PIN t1[148]
    DIRECTION INPUT ;
    USE SIGNAL ;
    PORT
      LAYER M4 ;
        RECT  81 69.168 81.192 69.192 ;
    END
  END t1[148]
  PIN t1[149]
    DIRECTION INPUT ;
    USE SIGNAL ;
    PORT
      LAYER M4 ;
        RECT  81 69.264 81.192 69.288 ;
    END
  END t1[149]
  PIN t1[14]
    DIRECTION INPUT ;
    USE SIGNAL ;
    PORT
      LAYER M4 ;
        RECT  81 56.304 81.192 56.328 ;
    END
  END t1[14]
  PIN t1[150]
    DIRECTION INPUT ;
    USE SIGNAL ;
    PORT
      LAYER M4 ;
        RECT  81 69.36 81.192 69.384 ;
    END
  END t1[150]
  PIN t1[151]
    DIRECTION INPUT ;
    USE SIGNAL ;
    PORT
      LAYER M4 ;
        RECT  81 69.456 81.192 69.48 ;
    END
  END t1[151]
  PIN t1[152]
    DIRECTION INPUT ;
    USE SIGNAL ;
    PORT
      LAYER M4 ;
        RECT  81 69.552 81.192 69.576 ;
    END
  END t1[152]
  PIN t1[153]
    DIRECTION INPUT ;
    USE SIGNAL ;
    PORT
      LAYER M4 ;
        RECT  81 69.648 81.192 69.672 ;
    END
  END t1[153]
  PIN t1[154]
    DIRECTION INPUT ;
    USE SIGNAL ;
    PORT
      LAYER M4 ;
        RECT  81 69.744 81.192 69.768 ;
    END
  END t1[154]
  PIN t1[155]
    DIRECTION INPUT ;
    USE SIGNAL ;
    PORT
      LAYER M4 ;
        RECT  81 69.84 81.192 69.864 ;
    END
  END t1[155]
  PIN t1[156]
    DIRECTION INPUT ;
    USE SIGNAL ;
    PORT
      LAYER M4 ;
        RECT  81 69.936 81.192 69.96 ;
    END
  END t1[156]
  PIN t1[157]
    DIRECTION INPUT ;
    USE SIGNAL ;
    PORT
      LAYER M4 ;
        RECT  81 70.032 81.192 70.056 ;
    END
  END t1[157]
  PIN t1[158]
    DIRECTION INPUT ;
    USE SIGNAL ;
    PORT
      LAYER M4 ;
        RECT  81 70.128 81.192 70.152 ;
    END
  END t1[158]
  PIN t1[159]
    DIRECTION INPUT ;
    USE SIGNAL ;
    PORT
      LAYER M4 ;
        RECT  81 70.224 81.192 70.248 ;
    END
  END t1[159]
  PIN t1[15]
    DIRECTION INPUT ;
    USE SIGNAL ;
    PORT
      LAYER M4 ;
        RECT  81 56.4 81.192 56.424 ;
    END
  END t1[15]
  PIN t1[160]
    DIRECTION INPUT ;
    USE SIGNAL ;
    PORT
      LAYER M4 ;
        RECT  81 70.32 81.192 70.344 ;
    END
  END t1[160]
  PIN t1[161]
    DIRECTION INPUT ;
    USE SIGNAL ;
    PORT
      LAYER M4 ;
        RECT  81 70.416 81.192 70.44 ;
    END
  END t1[161]
  PIN t1[162]
    DIRECTION INPUT ;
    USE SIGNAL ;
    PORT
      LAYER M4 ;
        RECT  81 70.512 81.192 70.536 ;
    END
  END t1[162]
  PIN t1[163]
    DIRECTION INPUT ;
    USE SIGNAL ;
    PORT
      LAYER M4 ;
        RECT  81 70.608 81.192 70.632 ;
    END
  END t1[163]
  PIN t1[164]
    DIRECTION INPUT ;
    USE SIGNAL ;
    PORT
      LAYER M4 ;
        RECT  81 70.704 81.192 70.728 ;
    END
  END t1[164]
  PIN t1[165]
    DIRECTION INPUT ;
    USE SIGNAL ;
    PORT
      LAYER M4 ;
        RECT  81 70.8 81.192 70.824 ;
    END
  END t1[165]
  PIN t1[166]
    DIRECTION INPUT ;
    USE SIGNAL ;
    PORT
      LAYER M4 ;
        RECT  81 70.896 81.192 70.92 ;
    END
  END t1[166]
  PIN t1[167]
    DIRECTION INPUT ;
    USE SIGNAL ;
    PORT
      LAYER M4 ;
        RECT  81 70.992 81.192 71.016 ;
    END
  END t1[167]
  PIN t1[168]
    DIRECTION INPUT ;
    USE SIGNAL ;
    PORT
      LAYER M4 ;
        RECT  81 71.088 81.192 71.112 ;
    END
  END t1[168]
  PIN t1[169]
    DIRECTION INPUT ;
    USE SIGNAL ;
    PORT
      LAYER M4 ;
        RECT  81 71.184 81.192 71.208 ;
    END
  END t1[169]
  PIN t1[16]
    DIRECTION INPUT ;
    USE SIGNAL ;
    PORT
      LAYER M4 ;
        RECT  81 56.496 81.192 56.52 ;
    END
  END t1[16]
  PIN t1[170]
    DIRECTION INPUT ;
    USE SIGNAL ;
    PORT
      LAYER M4 ;
        RECT  81 71.28 81.192 71.304 ;
    END
  END t1[170]
  PIN t1[171]
    DIRECTION INPUT ;
    USE SIGNAL ;
    PORT
      LAYER M4 ;
        RECT  81 71.376 81.192 71.4 ;
    END
  END t1[171]
  PIN t1[172]
    DIRECTION INPUT ;
    USE SIGNAL ;
    PORT
      LAYER M4 ;
        RECT  81 71.472 81.192 71.496 ;
    END
  END t1[172]
  PIN t1[173]
    DIRECTION INPUT ;
    USE SIGNAL ;
    PORT
      LAYER M4 ;
        RECT  81 71.568 81.192 71.592 ;
    END
  END t1[173]
  PIN t1[174]
    DIRECTION INPUT ;
    USE SIGNAL ;
    PORT
      LAYER M4 ;
        RECT  81 71.664 81.192 71.688 ;
    END
  END t1[174]
  PIN t1[175]
    DIRECTION INPUT ;
    USE SIGNAL ;
    PORT
      LAYER M4 ;
        RECT  81 71.76 81.192 71.784 ;
    END
  END t1[175]
  PIN t1[176]
    DIRECTION INPUT ;
    USE SIGNAL ;
    PORT
      LAYER M4 ;
        RECT  81 71.856 81.192 71.88 ;
    END
  END t1[176]
  PIN t1[177]
    DIRECTION INPUT ;
    USE SIGNAL ;
    PORT
      LAYER M4 ;
        RECT  81 71.952 81.192 71.976 ;
    END
  END t1[177]
  PIN t1[178]
    DIRECTION INPUT ;
    USE SIGNAL ;
    PORT
      LAYER M4 ;
        RECT  81 72.048 81.192 72.072 ;
    END
  END t1[178]
  PIN t1[179]
    DIRECTION INPUT ;
    USE SIGNAL ;
    PORT
      LAYER M4 ;
        RECT  81 72.144 81.192 72.168 ;
    END
  END t1[179]
  PIN t1[17]
    DIRECTION INPUT ;
    USE SIGNAL ;
    PORT
      LAYER M4 ;
        RECT  81 56.592 81.192 56.616 ;
    END
  END t1[17]
  PIN t1[180]
    DIRECTION INPUT ;
    USE SIGNAL ;
    PORT
      LAYER M4 ;
        RECT  81 72.24 81.192 72.264 ;
    END
  END t1[180]
  PIN t1[181]
    DIRECTION INPUT ;
    USE SIGNAL ;
    PORT
      LAYER M4 ;
        RECT  81 72.336 81.192 72.36 ;
    END
  END t1[181]
  PIN t1[182]
    DIRECTION INPUT ;
    USE SIGNAL ;
    PORT
      LAYER M4 ;
        RECT  81 72.432 81.192 72.456 ;
    END
  END t1[182]
  PIN t1[183]
    DIRECTION INPUT ;
    USE SIGNAL ;
    PORT
      LAYER M4 ;
        RECT  81 72.528 81.192 72.552 ;
    END
  END t1[183]
  PIN t1[184]
    DIRECTION INPUT ;
    USE SIGNAL ;
    PORT
      LAYER M4 ;
        RECT  81 72.624 81.192 72.648 ;
    END
  END t1[184]
  PIN t1[185]
    DIRECTION INPUT ;
    USE SIGNAL ;
    PORT
      LAYER M4 ;
        RECT  81 72.72 81.192 72.744 ;
    END
  END t1[185]
  PIN t1[186]
    DIRECTION INPUT ;
    USE SIGNAL ;
    PORT
      LAYER M4 ;
        RECT  81 72.816 81.192 72.84 ;
    END
  END t1[186]
  PIN t1[187]
    DIRECTION INPUT ;
    USE SIGNAL ;
    PORT
      LAYER M4 ;
        RECT  81 72.912 81.192 72.936 ;
    END
  END t1[187]
  PIN t1[188]
    DIRECTION INPUT ;
    USE SIGNAL ;
    PORT
      LAYER M4 ;
        RECT  81 73.008 81.192 73.032 ;
    END
  END t1[188]
  PIN t1[189]
    DIRECTION INPUT ;
    USE SIGNAL ;
    PORT
      LAYER M4 ;
        RECT  81 73.104 81.192 73.128 ;
    END
  END t1[189]
  PIN t1[18]
    DIRECTION INPUT ;
    USE SIGNAL ;
    PORT
      LAYER M4 ;
        RECT  81 56.688 81.192 56.712 ;
    END
  END t1[18]
  PIN t1[190]
    DIRECTION INPUT ;
    USE SIGNAL ;
    PORT
      LAYER M4 ;
        RECT  81 73.2 81.192 73.224 ;
    END
  END t1[190]
  PIN t1[191]
    DIRECTION INPUT ;
    USE SIGNAL ;
    PORT
      LAYER M4 ;
        RECT  81 73.296 81.192 73.32 ;
    END
  END t1[191]
  PIN t1[192]
    DIRECTION INPUT ;
    USE SIGNAL ;
    PORT
      LAYER M4 ;
        RECT  81 73.392 81.192 73.416 ;
    END
  END t1[192]
  PIN t1[193]
    DIRECTION INPUT ;
    USE SIGNAL ;
    PORT
      LAYER M4 ;
        RECT  81 73.488 81.192 73.512 ;
    END
  END t1[193]
  PIN t1[194]
    DIRECTION INPUT ;
    USE SIGNAL ;
    PORT
      LAYER M4 ;
        RECT  81 73.584 81.192 73.608 ;
    END
  END t1[194]
  PIN t1[195]
    DIRECTION INPUT ;
    USE SIGNAL ;
    PORT
      LAYER M4 ;
        RECT  81 73.68 81.192 73.704 ;
    END
  END t1[195]
  PIN t1[196]
    DIRECTION INPUT ;
    USE SIGNAL ;
    PORT
      LAYER M4 ;
        RECT  81 73.776 81.192 73.8 ;
    END
  END t1[196]
  PIN t1[197]
    DIRECTION INPUT ;
    USE SIGNAL ;
    PORT
      LAYER M4 ;
        RECT  81 73.872 81.192 73.896 ;
    END
  END t1[197]
  PIN t1[198]
    DIRECTION INPUT ;
    USE SIGNAL ;
    PORT
      LAYER M4 ;
        RECT  81 73.968 81.192 73.992 ;
    END
  END t1[198]
  PIN t1[199]
    DIRECTION INPUT ;
    USE SIGNAL ;
    PORT
      LAYER M4 ;
        RECT  81 74.064 81.192 74.088 ;
    END
  END t1[199]
  PIN t1[19]
    DIRECTION INPUT ;
    USE SIGNAL ;
    PORT
      LAYER M4 ;
        RECT  81 56.784 81.192 56.808 ;
    END
  END t1[19]
  PIN t1[1]
    DIRECTION INPUT ;
    USE SIGNAL ;
    PORT
      LAYER M4 ;
        RECT  81 55.056 81.192 55.08 ;
    END
  END t1[1]
  PIN t1[200]
    DIRECTION INPUT ;
    USE SIGNAL ;
    PORT
      LAYER M4 ;
        RECT  81 74.16 81.192 74.184 ;
    END
  END t1[200]
  PIN t1[201]
    DIRECTION INPUT ;
    USE SIGNAL ;
    PORT
      LAYER M4 ;
        RECT  81 74.256 81.192 74.28 ;
    END
  END t1[201]
  PIN t1[202]
    DIRECTION INPUT ;
    USE SIGNAL ;
    PORT
      LAYER M4 ;
        RECT  81 74.352 81.192 74.376 ;
    END
  END t1[202]
  PIN t1[203]
    DIRECTION INPUT ;
    USE SIGNAL ;
    PORT
      LAYER M4 ;
        RECT  81 74.448 81.192 74.472 ;
    END
  END t1[203]
  PIN t1[204]
    DIRECTION INPUT ;
    USE SIGNAL ;
    PORT
      LAYER M4 ;
        RECT  81 74.544 81.192 74.568 ;
    END
  END t1[204]
  PIN t1[205]
    DIRECTION INPUT ;
    USE SIGNAL ;
    PORT
      LAYER M4 ;
        RECT  81 74.64 81.192 74.664 ;
    END
  END t1[205]
  PIN t1[206]
    DIRECTION INPUT ;
    USE SIGNAL ;
    PORT
      LAYER M4 ;
        RECT  81 74.736 81.192 74.76 ;
    END
  END t1[206]
  PIN t1[207]
    DIRECTION INPUT ;
    USE SIGNAL ;
    PORT
      LAYER M4 ;
        RECT  81 74.832 81.192 74.856 ;
    END
  END t1[207]
  PIN t1[208]
    DIRECTION INPUT ;
    USE SIGNAL ;
    PORT
      LAYER M4 ;
        RECT  81 74.928 81.192 74.952 ;
    END
  END t1[208]
  PIN t1[209]
    DIRECTION INPUT ;
    USE SIGNAL ;
    PORT
      LAYER M4 ;
        RECT  81 75.024 81.192 75.048 ;
    END
  END t1[209]
  PIN t1[20]
    DIRECTION INPUT ;
    USE SIGNAL ;
    PORT
      LAYER M4 ;
        RECT  81 56.88 81.192 56.904 ;
    END
  END t1[20]
  PIN t1[210]
    DIRECTION INPUT ;
    USE SIGNAL ;
    PORT
      LAYER M4 ;
        RECT  81 75.12 81.192 75.144 ;
    END
  END t1[210]
  PIN t1[211]
    DIRECTION INPUT ;
    USE SIGNAL ;
    PORT
      LAYER M4 ;
        RECT  81 75.216 81.192 75.24 ;
    END
  END t1[211]
  PIN t1[212]
    DIRECTION INPUT ;
    USE SIGNAL ;
    PORT
      LAYER M4 ;
        RECT  81 75.312 81.192 75.336 ;
    END
  END t1[212]
  PIN t1[213]
    DIRECTION INPUT ;
    USE SIGNAL ;
    PORT
      LAYER M4 ;
        RECT  81 75.408 81.192 75.432 ;
    END
  END t1[213]
  PIN t1[214]
    DIRECTION INPUT ;
    USE SIGNAL ;
    PORT
      LAYER M4 ;
        RECT  81 75.504 81.192 75.528 ;
    END
  END t1[214]
  PIN t1[215]
    DIRECTION INPUT ;
    USE SIGNAL ;
    PORT
      LAYER M4 ;
        RECT  81 75.6 81.192 75.624 ;
    END
  END t1[215]
  PIN t1[216]
    DIRECTION INPUT ;
    USE SIGNAL ;
    PORT
      LAYER M4 ;
        RECT  81 75.696 81.192 75.72 ;
    END
  END t1[216]
  PIN t1[217]
    DIRECTION INPUT ;
    USE SIGNAL ;
    PORT
      LAYER M4 ;
        RECT  81 75.792 81.192 75.816 ;
    END
  END t1[217]
  PIN t1[218]
    DIRECTION INPUT ;
    USE SIGNAL ;
    PORT
      LAYER M4 ;
        RECT  81 75.888 81.192 75.912 ;
    END
  END t1[218]
  PIN t1[219]
    DIRECTION INPUT ;
    USE SIGNAL ;
    PORT
      LAYER M4 ;
        RECT  81 75.984 81.192 76.008 ;
    END
  END t1[219]
  PIN t1[21]
    DIRECTION INPUT ;
    USE SIGNAL ;
    PORT
      LAYER M4 ;
        RECT  81 56.976 81.192 57 ;
    END
  END t1[21]
  PIN t1[220]
    DIRECTION INPUT ;
    USE SIGNAL ;
    PORT
      LAYER M4 ;
        RECT  81 76.08 81.192 76.104 ;
    END
  END t1[220]
  PIN t1[221]
    DIRECTION INPUT ;
    USE SIGNAL ;
    PORT
      LAYER M4 ;
        RECT  81 76.176 81.192 76.2 ;
    END
  END t1[221]
  PIN t1[222]
    DIRECTION INPUT ;
    USE SIGNAL ;
    PORT
      LAYER M4 ;
        RECT  81 76.272 81.192 76.296 ;
    END
  END t1[222]
  PIN t1[223]
    DIRECTION INPUT ;
    USE SIGNAL ;
    PORT
      LAYER M4 ;
        RECT  81 76.368 81.192 76.392 ;
    END
  END t1[223]
  PIN t1[224]
    DIRECTION INPUT ;
    USE SIGNAL ;
    PORT
      LAYER M4 ;
        RECT  81 76.464 81.192 76.488 ;
    END
  END t1[224]
  PIN t1[225]
    DIRECTION INPUT ;
    USE SIGNAL ;
    PORT
      LAYER M4 ;
        RECT  81 76.56 81.192 76.584 ;
    END
  END t1[225]
  PIN t1[226]
    DIRECTION INPUT ;
    USE SIGNAL ;
    PORT
      LAYER M4 ;
        RECT  81 76.656 81.192 76.68 ;
    END
  END t1[226]
  PIN t1[227]
    DIRECTION INPUT ;
    USE SIGNAL ;
    PORT
      LAYER M4 ;
        RECT  81 76.752 81.192 76.776 ;
    END
  END t1[227]
  PIN t1[228]
    DIRECTION INPUT ;
    USE SIGNAL ;
    PORT
      LAYER M4 ;
        RECT  81 76.848 81.192 76.872 ;
    END
  END t1[228]
  PIN t1[229]
    DIRECTION INPUT ;
    USE SIGNAL ;
    PORT
      LAYER M4 ;
        RECT  81 76.944 81.192 76.968 ;
    END
  END t1[229]
  PIN t1[22]
    DIRECTION INPUT ;
    USE SIGNAL ;
    PORT
      LAYER M4 ;
        RECT  81 57.072 81.192 57.096 ;
    END
  END t1[22]
  PIN t1[230]
    DIRECTION INPUT ;
    USE SIGNAL ;
    PORT
      LAYER M4 ;
        RECT  81 77.04 81.192 77.064 ;
    END
  END t1[230]
  PIN t1[231]
    DIRECTION INPUT ;
    USE SIGNAL ;
    PORT
      LAYER M4 ;
        RECT  81 77.136 81.192 77.16 ;
    END
  END t1[231]
  PIN t1[232]
    DIRECTION INPUT ;
    USE SIGNAL ;
    PORT
      LAYER M4 ;
        RECT  81 77.232 81.192 77.256 ;
    END
  END t1[232]
  PIN t1[233]
    DIRECTION INPUT ;
    USE SIGNAL ;
    PORT
      LAYER M4 ;
        RECT  81 77.328 81.192 77.352 ;
    END
  END t1[233]
  PIN t1[234]
    DIRECTION INPUT ;
    USE SIGNAL ;
    PORT
      LAYER M4 ;
        RECT  81 77.424 81.192 77.448 ;
    END
  END t1[234]
  PIN t1[235]
    DIRECTION INPUT ;
    USE SIGNAL ;
    PORT
      LAYER M4 ;
        RECT  81 77.52 81.192 77.544 ;
    END
  END t1[235]
  PIN t1[236]
    DIRECTION INPUT ;
    USE SIGNAL ;
    PORT
      LAYER M4 ;
        RECT  81 77.616 81.192 77.64 ;
    END
  END t1[236]
  PIN t1[237]
    DIRECTION INPUT ;
    USE SIGNAL ;
    PORT
      LAYER M4 ;
        RECT  81 77.712 81.192 77.736 ;
    END
  END t1[237]
  PIN t1[238]
    DIRECTION INPUT ;
    USE SIGNAL ;
    PORT
      LAYER M4 ;
        RECT  81 77.808 81.192 77.832 ;
    END
  END t1[238]
  PIN t1[239]
    DIRECTION INPUT ;
    USE SIGNAL ;
    PORT
      LAYER M4 ;
        RECT  81 77.904 81.192 77.928 ;
    END
  END t1[239]
  PIN t1[23]
    DIRECTION INPUT ;
    USE SIGNAL ;
    PORT
      LAYER M4 ;
        RECT  81 57.168 81.192 57.192 ;
    END
  END t1[23]
  PIN t1[240]
    DIRECTION INPUT ;
    USE SIGNAL ;
    PORT
      LAYER M4 ;
        RECT  81 78 81.192 78.024 ;
    END
  END t1[240]
  PIN t1[241]
    DIRECTION INPUT ;
    USE SIGNAL ;
    PORT
      LAYER M4 ;
        RECT  81 78.096 81.192 78.12 ;
    END
  END t1[241]
  PIN t1[242]
    DIRECTION INPUT ;
    USE SIGNAL ;
    PORT
      LAYER M4 ;
        RECT  81 78.192 81.192 78.216 ;
    END
  END t1[242]
  PIN t1[243]
    DIRECTION INPUT ;
    USE SIGNAL ;
    PORT
      LAYER M4 ;
        RECT  81 78.288 81.192 78.312 ;
    END
  END t1[243]
  PIN t1[244]
    DIRECTION INPUT ;
    USE SIGNAL ;
    PORT
      LAYER M4 ;
        RECT  81 78.384 81.192 78.408 ;
    END
  END t1[244]
  PIN t1[245]
    DIRECTION INPUT ;
    USE SIGNAL ;
    PORT
      LAYER M4 ;
        RECT  81 78.48 81.192 78.504 ;
    END
  END t1[245]
  PIN t1[246]
    DIRECTION INPUT ;
    USE SIGNAL ;
    PORT
      LAYER M4 ;
        RECT  81 78.576 81.192 78.6 ;
    END
  END t1[246]
  PIN t1[247]
    DIRECTION INPUT ;
    USE SIGNAL ;
    PORT
      LAYER M4 ;
        RECT  81 78.672 81.192 78.696 ;
    END
  END t1[247]
  PIN t1[248]
    DIRECTION INPUT ;
    USE SIGNAL ;
    PORT
      LAYER M4 ;
        RECT  81 78.768 81.192 78.792 ;
    END
  END t1[248]
  PIN t1[249]
    DIRECTION INPUT ;
    USE SIGNAL ;
    PORT
      LAYER M4 ;
        RECT  81 78.864 81.192 78.888 ;
    END
  END t1[249]
  PIN t1[24]
    DIRECTION INPUT ;
    USE SIGNAL ;
    PORT
      LAYER M4 ;
        RECT  81 57.264 81.192 57.288 ;
    END
  END t1[24]
  PIN t1[250]
    DIRECTION INPUT ;
    USE SIGNAL ;
    PORT
      LAYER M4 ;
        RECT  81 78.96 81.192 78.984 ;
    END
  END t1[250]
  PIN t1[251]
    DIRECTION INPUT ;
    USE SIGNAL ;
    PORT
      LAYER M4 ;
        RECT  81 79.056 81.192 79.08 ;
    END
  END t1[251]
  PIN t1[252]
    DIRECTION INPUT ;
    USE SIGNAL ;
    PORT
      LAYER M4 ;
        RECT  81 79.152 81.192 79.176 ;
    END
  END t1[252]
  PIN t1[253]
    DIRECTION INPUT ;
    USE SIGNAL ;
    PORT
      LAYER M4 ;
        RECT  81 79.248 81.192 79.272 ;
    END
  END t1[253]
  PIN t1[254]
    DIRECTION INPUT ;
    USE SIGNAL ;
    PORT
      LAYER M4 ;
        RECT  81 79.344 81.192 79.368 ;
    END
  END t1[254]
  PIN t1[255]
    DIRECTION INPUT ;
    USE SIGNAL ;
    PORT
      LAYER M4 ;
        RECT  81 79.44 81.192 79.464 ;
    END
  END t1[255]
  PIN t1[256]
    DIRECTION INPUT ;
    USE SIGNAL ;
    PORT
      LAYER M4 ;
        RECT  81 79.536 81.192 79.56 ;
    END
  END t1[256]
  PIN t1[257]
    DIRECTION INPUT ;
    USE SIGNAL ;
    PORT
      LAYER M4 ;
        RECT  81 79.632 81.192 79.656 ;
    END
  END t1[257]
  PIN t1[258]
    DIRECTION INPUT ;
    USE SIGNAL ;
    PORT
      LAYER M4 ;
        RECT  81 79.728 81.192 79.752 ;
    END
  END t1[258]
  PIN t1[259]
    DIRECTION INPUT ;
    USE SIGNAL ;
    PORT
      LAYER M4 ;
        RECT  81 79.824 81.192 79.848 ;
    END
  END t1[259]
  PIN t1[25]
    DIRECTION INPUT ;
    USE SIGNAL ;
    PORT
      LAYER M4 ;
        RECT  81 57.36 81.192 57.384 ;
    END
  END t1[25]
  PIN t1[260]
    DIRECTION INPUT ;
    USE SIGNAL ;
    PORT
      LAYER M4 ;
        RECT  81 79.92 81.192 79.944 ;
    END
  END t1[260]
  PIN t1[261]
    DIRECTION INPUT ;
    USE SIGNAL ;
    PORT
      LAYER M4 ;
        RECT  81 80.016 81.192 80.04 ;
    END
  END t1[261]
  PIN t1[262]
    DIRECTION INPUT ;
    USE SIGNAL ;
    PORT
      LAYER M4 ;
        RECT  81 80.112 81.192 80.136 ;
    END
  END t1[262]
  PIN t1[263]
    DIRECTION INPUT ;
    USE SIGNAL ;
    PORT
      LAYER M4 ;
        RECT  81 80.208 81.192 80.232 ;
    END
  END t1[263]
  PIN t1[264]
    DIRECTION INPUT ;
    USE SIGNAL ;
    PORT
      LAYER M4 ;
        RECT  81 80.304 81.192 80.328 ;
    END
  END t1[264]
  PIN t1[265]
    DIRECTION INPUT ;
    USE SIGNAL ;
    PORT
      LAYER M4 ;
        RECT  81 80.4 81.192 80.424 ;
    END
  END t1[265]
  PIN t1[266]
    DIRECTION INPUT ;
    USE SIGNAL ;
    PORT
      LAYER M4 ;
        RECT  81 80.496 81.192 80.52 ;
    END
  END t1[266]
  PIN t1[267]
    DIRECTION INPUT ;
    USE SIGNAL ;
    PORT
      LAYER M4 ;
        RECT  81 80.592 81.192 80.616 ;
    END
  END t1[267]
  PIN t1[268]
    DIRECTION INPUT ;
    USE SIGNAL ;
    PORT
      LAYER M4 ;
        RECT  81 80.688 81.192 80.712 ;
    END
  END t1[268]
  PIN t1[269]
    DIRECTION INPUT ;
    USE SIGNAL ;
    PORT
      LAYER M4 ;
        RECT  81 80.784 81.192 80.808 ;
    END
  END t1[269]
  PIN t1[26]
    DIRECTION INPUT ;
    USE SIGNAL ;
    PORT
      LAYER M4 ;
        RECT  81 57.456 81.192 57.48 ;
    END
  END t1[26]
  PIN t1[27]
    DIRECTION INPUT ;
    USE SIGNAL ;
    PORT
      LAYER M4 ;
        RECT  81 57.552 81.192 57.576 ;
    END
  END t1[27]
  PIN t1[28]
    DIRECTION INPUT ;
    USE SIGNAL ;
    PORT
      LAYER M4 ;
        RECT  81 57.648 81.192 57.672 ;
    END
  END t1[28]
  PIN t1[29]
    DIRECTION INPUT ;
    USE SIGNAL ;
    PORT
      LAYER M4 ;
        RECT  81 57.744 81.192 57.768 ;
    END
  END t1[29]
  PIN t1[2]
    DIRECTION INPUT ;
    USE SIGNAL ;
    PORT
      LAYER M4 ;
        RECT  81 55.152 81.192 55.176 ;
    END
  END t1[2]
  PIN t1[30]
    DIRECTION INPUT ;
    USE SIGNAL ;
    PORT
      LAYER M4 ;
        RECT  81 57.84 81.192 57.864 ;
    END
  END t1[30]
  PIN t1[31]
    DIRECTION INPUT ;
    USE SIGNAL ;
    PORT
      LAYER M4 ;
        RECT  81 57.936 81.192 57.96 ;
    END
  END t1[31]
  PIN t1[32]
    DIRECTION INPUT ;
    USE SIGNAL ;
    PORT
      LAYER M4 ;
        RECT  81 58.032 81.192 58.056 ;
    END
  END t1[32]
  PIN t1[33]
    DIRECTION INPUT ;
    USE SIGNAL ;
    PORT
      LAYER M4 ;
        RECT  81 58.128 81.192 58.152 ;
    END
  END t1[33]
  PIN t1[34]
    DIRECTION INPUT ;
    USE SIGNAL ;
    PORT
      LAYER M4 ;
        RECT  81 58.224 81.192 58.248 ;
    END
  END t1[34]
  PIN t1[35]
    DIRECTION INPUT ;
    USE SIGNAL ;
    PORT
      LAYER M4 ;
        RECT  81 58.32 81.192 58.344 ;
    END
  END t1[35]
  PIN t1[36]
    DIRECTION INPUT ;
    USE SIGNAL ;
    PORT
      LAYER M4 ;
        RECT  81 58.416 81.192 58.44 ;
    END
  END t1[36]
  PIN t1[37]
    DIRECTION INPUT ;
    USE SIGNAL ;
    PORT
      LAYER M4 ;
        RECT  81 58.512 81.192 58.536 ;
    END
  END t1[37]
  PIN t1[38]
    DIRECTION INPUT ;
    USE SIGNAL ;
    PORT
      LAYER M4 ;
        RECT  81 58.608 81.192 58.632 ;
    END
  END t1[38]
  PIN t1[39]
    DIRECTION INPUT ;
    USE SIGNAL ;
    PORT
      LAYER M4 ;
        RECT  81 58.704 81.192 58.728 ;
    END
  END t1[39]
  PIN t1[3]
    DIRECTION INPUT ;
    USE SIGNAL ;
    PORT
      LAYER M4 ;
        RECT  81 55.248 81.192 55.272 ;
    END
  END t1[3]
  PIN t1[40]
    DIRECTION INPUT ;
    USE SIGNAL ;
    PORT
      LAYER M4 ;
        RECT  81 58.8 81.192 58.824 ;
    END
  END t1[40]
  PIN t1[41]
    DIRECTION INPUT ;
    USE SIGNAL ;
    PORT
      LAYER M4 ;
        RECT  81 58.896 81.192 58.92 ;
    END
  END t1[41]
  PIN t1[42]
    DIRECTION INPUT ;
    USE SIGNAL ;
    PORT
      LAYER M4 ;
        RECT  81 58.992 81.192 59.016 ;
    END
  END t1[42]
  PIN t1[43]
    DIRECTION INPUT ;
    USE SIGNAL ;
    PORT
      LAYER M4 ;
        RECT  81 59.088 81.192 59.112 ;
    END
  END t1[43]
  PIN t1[44]
    DIRECTION INPUT ;
    USE SIGNAL ;
    PORT
      LAYER M4 ;
        RECT  81 59.184 81.192 59.208 ;
    END
  END t1[44]
  PIN t1[45]
    DIRECTION INPUT ;
    USE SIGNAL ;
    PORT
      LAYER M4 ;
        RECT  81 59.28 81.192 59.304 ;
    END
  END t1[45]
  PIN t1[46]
    DIRECTION INPUT ;
    USE SIGNAL ;
    PORT
      LAYER M4 ;
        RECT  81 59.376 81.192 59.4 ;
    END
  END t1[46]
  PIN t1[47]
    DIRECTION INPUT ;
    USE SIGNAL ;
    PORT
      LAYER M4 ;
        RECT  81 59.472 81.192 59.496 ;
    END
  END t1[47]
  PIN t1[48]
    DIRECTION INPUT ;
    USE SIGNAL ;
    PORT
      LAYER M4 ;
        RECT  81 59.568 81.192 59.592 ;
    END
  END t1[48]
  PIN t1[49]
    DIRECTION INPUT ;
    USE SIGNAL ;
    PORT
      LAYER M4 ;
        RECT  81 59.664 81.192 59.688 ;
    END
  END t1[49]
  PIN t1[4]
    DIRECTION INPUT ;
    USE SIGNAL ;
    PORT
      LAYER M4 ;
        RECT  81 55.344 81.192 55.368 ;
    END
  END t1[4]
  PIN t1[50]
    DIRECTION INPUT ;
    USE SIGNAL ;
    PORT
      LAYER M4 ;
        RECT  81 59.76 81.192 59.784 ;
    END
  END t1[50]
  PIN t1[51]
    DIRECTION INPUT ;
    USE SIGNAL ;
    PORT
      LAYER M4 ;
        RECT  81 59.856 81.192 59.88 ;
    END
  END t1[51]
  PIN t1[52]
    DIRECTION INPUT ;
    USE SIGNAL ;
    PORT
      LAYER M4 ;
        RECT  81 59.952 81.192 59.976 ;
    END
  END t1[52]
  PIN t1[53]
    DIRECTION INPUT ;
    USE SIGNAL ;
    PORT
      LAYER M4 ;
        RECT  81 60.048 81.192 60.072 ;
    END
  END t1[53]
  PIN t1[54]
    DIRECTION INPUT ;
    USE SIGNAL ;
    PORT
      LAYER M4 ;
        RECT  81 60.144 81.192 60.168 ;
    END
  END t1[54]
  PIN t1[55]
    DIRECTION INPUT ;
    USE SIGNAL ;
    PORT
      LAYER M4 ;
        RECT  81 60.24 81.192 60.264 ;
    END
  END t1[55]
  PIN t1[56]
    DIRECTION INPUT ;
    USE SIGNAL ;
    PORT
      LAYER M4 ;
        RECT  81 60.336 81.192 60.36 ;
    END
  END t1[56]
  PIN t1[57]
    DIRECTION INPUT ;
    USE SIGNAL ;
    PORT
      LAYER M4 ;
        RECT  81 60.432 81.192 60.456 ;
    END
  END t1[57]
  PIN t1[58]
    DIRECTION INPUT ;
    USE SIGNAL ;
    PORT
      LAYER M4 ;
        RECT  81 60.528 81.192 60.552 ;
    END
  END t1[58]
  PIN t1[59]
    DIRECTION INPUT ;
    USE SIGNAL ;
    PORT
      LAYER M4 ;
        RECT  81 60.624 81.192 60.648 ;
    END
  END t1[59]
  PIN t1[5]
    DIRECTION INPUT ;
    USE SIGNAL ;
    PORT
      LAYER M4 ;
        RECT  81 55.44 81.192 55.464 ;
    END
  END t1[5]
  PIN t1[60]
    DIRECTION INPUT ;
    USE SIGNAL ;
    PORT
      LAYER M4 ;
        RECT  81 60.72 81.192 60.744 ;
    END
  END t1[60]
  PIN t1[61]
    DIRECTION INPUT ;
    USE SIGNAL ;
    PORT
      LAYER M4 ;
        RECT  81 60.816 81.192 60.84 ;
    END
  END t1[61]
  PIN t1[62]
    DIRECTION INPUT ;
    USE SIGNAL ;
    PORT
      LAYER M4 ;
        RECT  81 60.912 81.192 60.936 ;
    END
  END t1[62]
  PIN t1[63]
    DIRECTION INPUT ;
    USE SIGNAL ;
    PORT
      LAYER M4 ;
        RECT  81 61.008 81.192 61.032 ;
    END
  END t1[63]
  PIN t1[64]
    DIRECTION INPUT ;
    USE SIGNAL ;
    PORT
      LAYER M4 ;
        RECT  81 61.104 81.192 61.128 ;
    END
  END t1[64]
  PIN t1[65]
    DIRECTION INPUT ;
    USE SIGNAL ;
    PORT
      LAYER M4 ;
        RECT  81 61.2 81.192 61.224 ;
    END
  END t1[65]
  PIN t1[66]
    DIRECTION INPUT ;
    USE SIGNAL ;
    PORT
      LAYER M4 ;
        RECT  81 61.296 81.192 61.32 ;
    END
  END t1[66]
  PIN t1[67]
    DIRECTION INPUT ;
    USE SIGNAL ;
    PORT
      LAYER M4 ;
        RECT  81 61.392 81.192 61.416 ;
    END
  END t1[67]
  PIN t1[68]
    DIRECTION INPUT ;
    USE SIGNAL ;
    PORT
      LAYER M4 ;
        RECT  81 61.488 81.192 61.512 ;
    END
  END t1[68]
  PIN t1[69]
    DIRECTION INPUT ;
    USE SIGNAL ;
    PORT
      LAYER M4 ;
        RECT  81 61.584 81.192 61.608 ;
    END
  END t1[69]
  PIN t1[6]
    DIRECTION INPUT ;
    USE SIGNAL ;
    PORT
      LAYER M4 ;
        RECT  81 55.536 81.192 55.56 ;
    END
  END t1[6]
  PIN t1[70]
    DIRECTION INPUT ;
    USE SIGNAL ;
    PORT
      LAYER M4 ;
        RECT  81 61.68 81.192 61.704 ;
    END
  END t1[70]
  PIN t1[71]
    DIRECTION INPUT ;
    USE SIGNAL ;
    PORT
      LAYER M4 ;
        RECT  81 61.776 81.192 61.8 ;
    END
  END t1[71]
  PIN t1[72]
    DIRECTION INPUT ;
    USE SIGNAL ;
    PORT
      LAYER M4 ;
        RECT  81 61.872 81.192 61.896 ;
    END
  END t1[72]
  PIN t1[73]
    DIRECTION INPUT ;
    USE SIGNAL ;
    PORT
      LAYER M4 ;
        RECT  81 61.968 81.192 61.992 ;
    END
  END t1[73]
  PIN t1[74]
    DIRECTION INPUT ;
    USE SIGNAL ;
    PORT
      LAYER M4 ;
        RECT  81 62.064 81.192 62.088 ;
    END
  END t1[74]
  PIN t1[75]
    DIRECTION INPUT ;
    USE SIGNAL ;
    PORT
      LAYER M4 ;
        RECT  81 62.16 81.192 62.184 ;
    END
  END t1[75]
  PIN t1[76]
    DIRECTION INPUT ;
    USE SIGNAL ;
    PORT
      LAYER M4 ;
        RECT  81 62.256 81.192 62.28 ;
    END
  END t1[76]
  PIN t1[77]
    DIRECTION INPUT ;
    USE SIGNAL ;
    PORT
      LAYER M4 ;
        RECT  81 62.352 81.192 62.376 ;
    END
  END t1[77]
  PIN t1[78]
    DIRECTION INPUT ;
    USE SIGNAL ;
    PORT
      LAYER M4 ;
        RECT  81 62.448 81.192 62.472 ;
    END
  END t1[78]
  PIN t1[79]
    DIRECTION INPUT ;
    USE SIGNAL ;
    PORT
      LAYER M4 ;
        RECT  81 62.544 81.192 62.568 ;
    END
  END t1[79]
  PIN t1[7]
    DIRECTION INPUT ;
    USE SIGNAL ;
    PORT
      LAYER M4 ;
        RECT  81 55.632 81.192 55.656 ;
    END
  END t1[7]
  PIN t1[80]
    DIRECTION INPUT ;
    USE SIGNAL ;
    PORT
      LAYER M4 ;
        RECT  81 62.64 81.192 62.664 ;
    END
  END t1[80]
  PIN t1[81]
    DIRECTION INPUT ;
    USE SIGNAL ;
    PORT
      LAYER M4 ;
        RECT  81 62.736 81.192 62.76 ;
    END
  END t1[81]
  PIN t1[82]
    DIRECTION INPUT ;
    USE SIGNAL ;
    PORT
      LAYER M4 ;
        RECT  81 62.832 81.192 62.856 ;
    END
  END t1[82]
  PIN t1[83]
    DIRECTION INPUT ;
    USE SIGNAL ;
    PORT
      LAYER M4 ;
        RECT  81 62.928 81.192 62.952 ;
    END
  END t1[83]
  PIN t1[84]
    DIRECTION INPUT ;
    USE SIGNAL ;
    PORT
      LAYER M4 ;
        RECT  81 63.024 81.192 63.048 ;
    END
  END t1[84]
  PIN t1[85]
    DIRECTION INPUT ;
    USE SIGNAL ;
    PORT
      LAYER M4 ;
        RECT  81 63.12 81.192 63.144 ;
    END
  END t1[85]
  PIN t1[86]
    DIRECTION INPUT ;
    USE SIGNAL ;
    PORT
      LAYER M4 ;
        RECT  81 63.216 81.192 63.24 ;
    END
  END t1[86]
  PIN t1[87]
    DIRECTION INPUT ;
    USE SIGNAL ;
    PORT
      LAYER M4 ;
        RECT  81 63.312 81.192 63.336 ;
    END
  END t1[87]
  PIN t1[88]
    DIRECTION INPUT ;
    USE SIGNAL ;
    PORT
      LAYER M4 ;
        RECT  81 63.408 81.192 63.432 ;
    END
  END t1[88]
  PIN t1[89]
    DIRECTION INPUT ;
    USE SIGNAL ;
    PORT
      LAYER M4 ;
        RECT  81 63.504 81.192 63.528 ;
    END
  END t1[89]
  PIN t1[8]
    DIRECTION INPUT ;
    USE SIGNAL ;
    PORT
      LAYER M4 ;
        RECT  81 55.728 81.192 55.752 ;
    END
  END t1[8]
  PIN t1[90]
    DIRECTION INPUT ;
    USE SIGNAL ;
    PORT
      LAYER M4 ;
        RECT  81 63.6 81.192 63.624 ;
    END
  END t1[90]
  PIN t1[91]
    DIRECTION INPUT ;
    USE SIGNAL ;
    PORT
      LAYER M4 ;
        RECT  81 63.696 81.192 63.72 ;
    END
  END t1[91]
  PIN t1[92]
    DIRECTION INPUT ;
    USE SIGNAL ;
    PORT
      LAYER M4 ;
        RECT  81 63.792 81.192 63.816 ;
    END
  END t1[92]
  PIN t1[93]
    DIRECTION INPUT ;
    USE SIGNAL ;
    PORT
      LAYER M4 ;
        RECT  81 63.888 81.192 63.912 ;
    END
  END t1[93]
  PIN t1[94]
    DIRECTION INPUT ;
    USE SIGNAL ;
    PORT
      LAYER M4 ;
        RECT  81 63.984 81.192 64.008 ;
    END
  END t1[94]
  PIN t1[95]
    DIRECTION INPUT ;
    USE SIGNAL ;
    PORT
      LAYER M4 ;
        RECT  81 64.08 81.192 64.104 ;
    END
  END t1[95]
  PIN t1[96]
    DIRECTION INPUT ;
    USE SIGNAL ;
    PORT
      LAYER M4 ;
        RECT  81 64.176 81.192 64.2 ;
    END
  END t1[96]
  PIN t1[97]
    DIRECTION INPUT ;
    USE SIGNAL ;
    PORT
      LAYER M4 ;
        RECT  81 64.272 81.192 64.296 ;
    END
  END t1[97]
  PIN t1[98]
    DIRECTION INPUT ;
    USE SIGNAL ;
    PORT
      LAYER M4 ;
        RECT  81 64.368 81.192 64.392 ;
    END
  END t1[98]
  PIN t1[99]
    DIRECTION INPUT ;
    USE SIGNAL ;
    PORT
      LAYER M4 ;
        RECT  81 64.464 81.192 64.488 ;
    END
  END t1[99]
  PIN t1[9]
    DIRECTION INPUT ;
    USE SIGNAL ;
    PORT
      LAYER M4 ;
        RECT  81 55.824 81.192 55.848 ;
    END
  END t1[9]
  PIN VDD
    DIRECTION INOUT ;
    USE POWER ;
    PORT
      LAYER M7 ;
        RECT  71.056 0.531 71.344 81.279 ;
        RECT  60.256 0.531 60.544 81.279 ;
        RECT  49.456 0.531 49.744 81.279 ;
        RECT  38.656 0.531 38.944 81.279 ;
        RECT  27.856 0.531 28.144 81.279 ;
        RECT  17.056 0.531 17.344 81.279 ;
        RECT  6.256 0.531 6.544 81.279 ;
      LAYER M6 ;
        RECT  0 77.172 0.032 77.46 ;
        RECT  0 71.772 0.032 72.06 ;
        RECT  0 66.372 0.032 66.66 ;
        RECT  0 60.972 0.032 61.26 ;
        RECT  0 55.572 0.032 55.86 ;
        RECT  0 50.172 0.032 50.46 ;
        RECT  0 44.772 0.032 45.06 ;
        RECT  0 39.372 0.032 39.66 ;
        RECT  0 33.972 0.032 34.26 ;
        RECT  0 28.572 0.032 28.86 ;
        RECT  0 23.172 0.032 23.46 ;
        RECT  0 17.772 0.032 18.06 ;
        RECT  0 12.372 0.032 12.66 ;
        RECT  0 6.972 0.032 7.26 ;
        RECT  0 1.572 0.032 1.86 ;
      LAYER M2 ;
        RECT  0 81.261 0.018 81.279 ;
        RECT  0 80.721 0.018 80.739 ;
        RECT  0 80.181 0.018 80.199 ;
        RECT  0 79.641 0.018 79.659 ;
        RECT  0 79.101 0.018 79.119 ;
        RECT  0 78.561 0.018 78.579 ;
        RECT  0 78.021 0.018 78.039 ;
        RECT  0 77.481 0.018 77.499 ;
        RECT  0 76.941 0.018 76.959 ;
        RECT  0 76.401 0.018 76.419 ;
        RECT  0 75.861 0.018 75.879 ;
        RECT  0 75.321 0.018 75.339 ;
        RECT  0 74.781 0.018 74.799 ;
        RECT  0 74.241 0.018 74.259 ;
        RECT  0 73.701 0.018 73.719 ;
        RECT  0 73.161 0.018 73.179 ;
        RECT  0 72.621 0.018 72.639 ;
        RECT  0 72.081 0.018 72.099 ;
        RECT  0 71.541 0.018 71.559 ;
        RECT  0 71.001 0.018 71.019 ;
        RECT  0 70.461 0.018 70.479 ;
        RECT  0 69.921 0.018 69.939 ;
        RECT  0 69.381 0.018 69.399 ;
        RECT  0 68.841 0.018 68.859 ;
        RECT  0 68.301 0.018 68.319 ;
        RECT  0 67.761 0.018 67.779 ;
        RECT  0 67.221 0.018 67.239 ;
        RECT  0 66.681 0.018 66.699 ;
        RECT  0 66.141 0.018 66.159 ;
        RECT  0 65.601 0.018 65.619 ;
        RECT  0 65.061 0.018 65.079 ;
        RECT  0 64.521 0.018 64.539 ;
        RECT  0 63.981 0.018 63.999 ;
        RECT  0 63.441 0.018 63.459 ;
        RECT  0 62.901 0.018 62.919 ;
        RECT  0 62.361 0.018 62.379 ;
        RECT  0 61.821 0.018 61.839 ;
        RECT  0 61.281 0.018 61.299 ;
        RECT  0 60.741 0.018 60.759 ;
        RECT  0 60.201 0.018 60.219 ;
        RECT  0 59.661 0.018 59.679 ;
        RECT  0 59.121 0.018 59.139 ;
        RECT  0 58.581 0.018 58.599 ;
        RECT  0 58.041 0.018 58.059 ;
        RECT  0 57.501 0.018 57.519 ;
        RECT  0 56.961 0.018 56.979 ;
        RECT  0 56.421 0.018 56.439 ;
        RECT  0 55.881 0.018 55.899 ;
        RECT  0 55.341 0.018 55.359 ;
        RECT  0 54.801 0.018 54.819 ;
        RECT  0 54.261 0.018 54.279 ;
        RECT  0 53.721 0.018 53.739 ;
        RECT  0 53.181 0.018 53.199 ;
        RECT  0 52.641 0.018 52.659 ;
        RECT  0 52.101 0.018 52.119 ;
        RECT  0 51.561 0.018 51.579 ;
        RECT  0 51.021 0.018 51.039 ;
        RECT  0 50.481 0.018 50.499 ;
        RECT  0 49.941 0.018 49.959 ;
        RECT  0 49.401 0.018 49.419 ;
        RECT  0 48.861 0.018 48.879 ;
        RECT  0 48.321 0.018 48.339 ;
        RECT  0 47.781 0.018 47.799 ;
        RECT  0 47.241 0.018 47.259 ;
        RECT  0 46.701 0.018 46.719 ;
        RECT  0 46.161 0.018 46.179 ;
        RECT  0 45.621 0.018 45.639 ;
        RECT  0 45.081 0.018 45.099 ;
        RECT  0 44.541 0.018 44.559 ;
        RECT  0 44.001 0.018 44.019 ;
        RECT  0 43.461 0.018 43.479 ;
        RECT  0 42.921 0.018 42.939 ;
        RECT  0 42.381 0.018 42.399 ;
        RECT  0 41.841 0.018 41.859 ;
        RECT  0 41.301 0.018 41.319 ;
        RECT  0 40.761 0.018 40.779 ;
        RECT  0 40.221 0.018 40.239 ;
        RECT  0 39.681 0.018 39.699 ;
        RECT  0 39.141 0.018 39.159 ;
        RECT  0 38.601 0.018 38.619 ;
        RECT  0 38.061 0.018 38.079 ;
        RECT  0 37.521 0.018 37.539 ;
        RECT  0 36.981 0.018 36.999 ;
        RECT  0 36.441 0.018 36.459 ;
        RECT  0 35.901 0.018 35.919 ;
        RECT  0 35.361 0.018 35.379 ;
        RECT  0 34.821 0.018 34.839 ;
        RECT  0 34.281 0.018 34.299 ;
        RECT  0 33.741 0.018 33.759 ;
        RECT  0 33.201 0.018 33.219 ;
        RECT  0 32.661 0.018 32.679 ;
        RECT  0 32.121 0.018 32.139 ;
        RECT  0 31.581 0.018 31.599 ;
        RECT  0 31.041 0.018 31.059 ;
        RECT  0 30.501 0.018 30.519 ;
        RECT  0 29.961 0.018 29.979 ;
        RECT  0 29.421 0.018 29.439 ;
        RECT  0 28.881 0.018 28.899 ;
        RECT  0 28.341 0.018 28.359 ;
        RECT  0 27.801 0.018 27.819 ;
        RECT  0 27.261 0.018 27.279 ;
        RECT  0 26.721 0.018 26.739 ;
        RECT  0 26.181 0.018 26.199 ;
        RECT  0 25.641 0.018 25.659 ;
        RECT  0 25.101 0.018 25.119 ;
        RECT  0 24.561 0.018 24.579 ;
        RECT  0 24.021 0.018 24.039 ;
        RECT  0 23.481 0.018 23.499 ;
        RECT  0 22.941 0.018 22.959 ;
        RECT  0 22.401 0.018 22.419 ;
        RECT  0 21.861 0.018 21.879 ;
        RECT  0 21.321 0.018 21.339 ;
        RECT  0 20.781 0.018 20.799 ;
        RECT  0 20.241 0.018 20.259 ;
        RECT  0 19.701 0.018 19.719 ;
        RECT  0 19.161 0.018 19.179 ;
        RECT  0 18.621 0.018 18.639 ;
        RECT  0 18.081 0.018 18.099 ;
        RECT  0 17.541 0.018 17.559 ;
        RECT  0 17.001 0.018 17.019 ;
        RECT  0 16.461 0.018 16.479 ;
        RECT  0 15.921 0.018 15.939 ;
        RECT  0 15.381 0.018 15.399 ;
        RECT  0 14.841 0.018 14.859 ;
        RECT  0 14.301 0.018 14.319 ;
        RECT  0 13.761 0.018 13.779 ;
        RECT  0 13.221 0.018 13.239 ;
        RECT  0 12.681 0.018 12.699 ;
        RECT  0 12.141 0.018 12.159 ;
        RECT  0 11.601 0.018 11.619 ;
        RECT  0 11.061 0.018 11.079 ;
        RECT  0 10.521 0.018 10.539 ;
        RECT  0 9.981 0.018 9.999 ;
        RECT  0 9.441 0.018 9.459 ;
        RECT  0 8.901 0.018 8.919 ;
        RECT  0 8.361 0.018 8.379 ;
        RECT  0 7.821 0.018 7.839 ;
        RECT  0 7.281 0.018 7.299 ;
        RECT  0 6.741 0.018 6.759 ;
        RECT  0 6.201 0.018 6.219 ;
        RECT  0 5.661 0.018 5.679 ;
        RECT  0 5.121 0.018 5.139 ;
        RECT  0 4.581 0.018 4.599 ;
        RECT  0 4.041 0.018 4.059 ;
        RECT  0 3.501 0.018 3.519 ;
        RECT  0 2.961 0.018 2.979 ;
        RECT  0 2.421 0.018 2.439 ;
        RECT  0 1.881 0.018 1.899 ;
        RECT  0 1.341 0.018 1.359 ;
        RECT  0 0.801 0.018 0.819 ;
      LAYER M1 ;
        RECT  0 81.261 0.018 81.279 ;
        RECT  0 80.721 0.018 80.739 ;
        RECT  0 80.181 0.018 80.199 ;
        RECT  0 79.641 0.018 79.659 ;
        RECT  0 79.101 0.018 79.119 ;
        RECT  0 78.561 0.018 78.579 ;
        RECT  0 78.021 0.018 78.039 ;
        RECT  0 77.481 0.018 77.499 ;
        RECT  0 76.941 0.018 76.959 ;
        RECT  0 76.401 0.018 76.419 ;
        RECT  0 75.861 0.018 75.879 ;
        RECT  0 75.321 0.018 75.339 ;
        RECT  0 74.781 0.018 74.799 ;
        RECT  0 74.241 0.018 74.259 ;
        RECT  0 73.701 0.018 73.719 ;
        RECT  0 73.161 0.018 73.179 ;
        RECT  0 72.621 0.018 72.639 ;
        RECT  0 72.081 0.018 72.099 ;
        RECT  0 71.541 0.018 71.559 ;
        RECT  0 71.001 0.018 71.019 ;
        RECT  0 70.461 0.018 70.479 ;
        RECT  0 69.921 0.018 69.939 ;
        RECT  0 69.381 0.018 69.399 ;
        RECT  0 68.841 0.018 68.859 ;
        RECT  0 68.301 0.018 68.319 ;
        RECT  0 67.761 0.018 67.779 ;
        RECT  0 67.221 0.018 67.239 ;
        RECT  0 66.681 0.018 66.699 ;
        RECT  0 66.141 0.018 66.159 ;
        RECT  0 65.601 0.018 65.619 ;
        RECT  0 65.061 0.018 65.079 ;
        RECT  0 64.521 0.018 64.539 ;
        RECT  0 63.981 0.018 63.999 ;
        RECT  0 63.441 0.018 63.459 ;
        RECT  0 62.901 0.018 62.919 ;
        RECT  0 62.361 0.018 62.379 ;
        RECT  0 61.821 0.018 61.839 ;
        RECT  0 61.281 0.018 61.299 ;
        RECT  0 60.741 0.018 60.759 ;
        RECT  0 60.201 0.018 60.219 ;
        RECT  0 59.661 0.018 59.679 ;
        RECT  0 59.121 0.018 59.139 ;
        RECT  0 58.581 0.018 58.599 ;
        RECT  0 58.041 0.018 58.059 ;
        RECT  0 57.501 0.018 57.519 ;
        RECT  0 56.961 0.018 56.979 ;
        RECT  0 56.421 0.018 56.439 ;
        RECT  0 55.881 0.018 55.899 ;
        RECT  0 55.341 0.018 55.359 ;
        RECT  0 54.801 0.018 54.819 ;
        RECT  0 54.261 0.018 54.279 ;
        RECT  0 53.721 0.018 53.739 ;
        RECT  0 53.181 0.018 53.199 ;
        RECT  0 52.641 0.018 52.659 ;
        RECT  0 52.101 0.018 52.119 ;
        RECT  0 51.561 0.018 51.579 ;
        RECT  0 51.021 0.018 51.039 ;
        RECT  0 50.481 0.018 50.499 ;
        RECT  0 49.941 0.018 49.959 ;
        RECT  0 49.401 0.018 49.419 ;
        RECT  0 48.861 0.018 48.879 ;
        RECT  0 48.321 0.018 48.339 ;
        RECT  0 47.781 0.018 47.799 ;
        RECT  0 47.241 0.018 47.259 ;
        RECT  0 46.701 0.018 46.719 ;
        RECT  0 46.161 0.018 46.179 ;
        RECT  0 45.621 0.018 45.639 ;
        RECT  0 45.081 0.018 45.099 ;
        RECT  0 44.541 0.018 44.559 ;
        RECT  0 44.001 0.018 44.019 ;
        RECT  0 43.461 0.018 43.479 ;
        RECT  0 42.921 0.018 42.939 ;
        RECT  0 42.381 0.018 42.399 ;
        RECT  0 41.841 0.018 41.859 ;
        RECT  0 41.301 0.018 41.319 ;
        RECT  0 40.761 0.018 40.779 ;
        RECT  0 40.221 0.018 40.239 ;
        RECT  0 39.681 0.018 39.699 ;
        RECT  0 39.141 0.018 39.159 ;
        RECT  0 38.601 0.018 38.619 ;
        RECT  0 38.061 0.018 38.079 ;
        RECT  0 37.521 0.018 37.539 ;
        RECT  0 36.981 0.018 36.999 ;
        RECT  0 36.441 0.018 36.459 ;
        RECT  0 35.901 0.018 35.919 ;
        RECT  0 35.361 0.018 35.379 ;
        RECT  0 34.821 0.018 34.839 ;
        RECT  0 34.281 0.018 34.299 ;
        RECT  0 33.741 0.018 33.759 ;
        RECT  0 33.201 0.018 33.219 ;
        RECT  0 32.661 0.018 32.679 ;
        RECT  0 32.121 0.018 32.139 ;
        RECT  0 31.581 0.018 31.599 ;
        RECT  0 31.041 0.018 31.059 ;
        RECT  0 30.501 0.018 30.519 ;
        RECT  0 29.961 0.018 29.979 ;
        RECT  0 29.421 0.018 29.439 ;
        RECT  0 28.881 0.018 28.899 ;
        RECT  0 28.341 0.018 28.359 ;
        RECT  0 27.801 0.018 27.819 ;
        RECT  0 27.261 0.018 27.279 ;
        RECT  0 26.721 0.018 26.739 ;
        RECT  0 26.181 0.018 26.199 ;
        RECT  0 25.641 0.018 25.659 ;
        RECT  0 25.101 0.018 25.119 ;
        RECT  0 24.561 0.018 24.579 ;
        RECT  0 24.021 0.018 24.039 ;
        RECT  0 23.481 0.018 23.499 ;
        RECT  0 22.941 0.018 22.959 ;
        RECT  0 22.401 0.018 22.419 ;
        RECT  0 21.861 0.018 21.879 ;
        RECT  0 21.321 0.018 21.339 ;
        RECT  0 20.781 0.018 20.799 ;
        RECT  0 20.241 0.018 20.259 ;
        RECT  0 19.701 0.018 19.719 ;
        RECT  0 19.161 0.018 19.179 ;
        RECT  0 18.621 0.018 18.639 ;
        RECT  0 18.081 0.018 18.099 ;
        RECT  0 17.541 0.018 17.559 ;
        RECT  0 17.001 0.018 17.019 ;
        RECT  0 16.461 0.018 16.479 ;
        RECT  0 15.921 0.018 15.939 ;
        RECT  0 15.381 0.018 15.399 ;
        RECT  0 14.841 0.018 14.859 ;
        RECT  0 14.301 0.018 14.319 ;
        RECT  0 13.761 0.018 13.779 ;
        RECT  0 13.221 0.018 13.239 ;
        RECT  0 12.681 0.018 12.699 ;
        RECT  0 12.141 0.018 12.159 ;
        RECT  0 11.601 0.018 11.619 ;
        RECT  0 11.061 0.018 11.079 ;
        RECT  0 10.521 0.018 10.539 ;
        RECT  0 9.981 0.018 9.999 ;
        RECT  0 9.441 0.018 9.459 ;
        RECT  0 8.901 0.018 8.919 ;
        RECT  0 8.361 0.018 8.379 ;
        RECT  0 7.821 0.018 7.839 ;
        RECT  0 7.281 0.018 7.299 ;
        RECT  0 6.741 0.018 6.759 ;
        RECT  0 6.201 0.018 6.219 ;
        RECT  0 5.661 0.018 5.679 ;
        RECT  0 5.121 0.018 5.139 ;
        RECT  0 4.581 0.018 4.599 ;
        RECT  0 4.041 0.018 4.059 ;
        RECT  0 3.501 0.018 3.519 ;
        RECT  0 2.961 0.018 2.979 ;
        RECT  0 2.421 0.018 2.439 ;
        RECT  0 1.881 0.018 1.899 ;
        RECT  0 1.341 0.018 1.359 ;
        RECT  0 0.801 0.018 0.819 ;
    END
  END VDD
  PIN VSS
    DIRECTION INOUT ;
    USE GROUND ;
    PORT
      LAYER M7 ;
        RECT  76.456 0.531 76.744 81.279 ;
        RECT  65.656 0.531 65.944 81.279 ;
        RECT  54.856 0.531 55.144 81.279 ;
        RECT  44.056 0.531 44.344 81.279 ;
        RECT  33.256 0.531 33.544 81.279 ;
        RECT  22.456 0.531 22.744 81.279 ;
        RECT  11.656 0.531 11.944 81.279 ;
        RECT  0.856 0.531 1.144 81.279 ;
      LAYER M6 ;
        RECT  0 76.596 0.032 76.884 ;
        RECT  0 71.196 0.032 71.484 ;
        RECT  0 65.796 0.032 66.084 ;
        RECT  0 60.396 0.032 60.684 ;
        RECT  0 54.996 0.032 55.284 ;
        RECT  0 49.596 0.032 49.884 ;
        RECT  0 44.196 0.032 44.484 ;
        RECT  0 38.796 0.032 39.084 ;
        RECT  0 33.396 0.032 33.684 ;
        RECT  0 27.996 0.032 28.284 ;
        RECT  0 22.596 0.032 22.884 ;
        RECT  0 17.196 0.032 17.484 ;
        RECT  0 11.796 0.032 12.084 ;
        RECT  0 6.396 0.032 6.684 ;
        RECT  0 0.996 0.032 1.284 ;
      LAYER M2 ;
        RECT  0 80.991 0.018 81.009 ;
        RECT  0 80.451 0.018 80.469 ;
        RECT  0 79.911 0.018 79.929 ;
        RECT  0 79.371 0.018 79.389 ;
        RECT  0 78.831 0.018 78.849 ;
        RECT  0 78.291 0.018 78.309 ;
        RECT  0 77.751 0.018 77.769 ;
        RECT  0 77.211 0.018 77.229 ;
        RECT  0 76.671 0.018 76.689 ;
        RECT  0 76.131 0.018 76.149 ;
        RECT  0 75.591 0.018 75.609 ;
        RECT  0 75.051 0.018 75.069 ;
        RECT  0 74.511 0.018 74.529 ;
        RECT  0 73.971 0.018 73.989 ;
        RECT  0 73.431 0.018 73.449 ;
        RECT  0 72.891 0.018 72.909 ;
        RECT  0 72.351 0.018 72.369 ;
        RECT  0 71.811 0.018 71.829 ;
        RECT  0 71.271 0.018 71.289 ;
        RECT  0 70.731 0.018 70.749 ;
        RECT  0 70.191 0.018 70.209 ;
        RECT  0 69.651 0.018 69.669 ;
        RECT  0 69.111 0.018 69.129 ;
        RECT  0 68.571 0.018 68.589 ;
        RECT  0 68.031 0.018 68.049 ;
        RECT  0 67.491 0.018 67.509 ;
        RECT  0 66.951 0.018 66.969 ;
        RECT  0 66.411 0.018 66.429 ;
        RECT  0 65.871 0.018 65.889 ;
        RECT  0 65.331 0.018 65.349 ;
        RECT  0 64.791 0.018 64.809 ;
        RECT  0 64.251 0.018 64.269 ;
        RECT  0 63.711 0.018 63.729 ;
        RECT  0 63.171 0.018 63.189 ;
        RECT  0 62.631 0.018 62.649 ;
        RECT  0 62.091 0.018 62.109 ;
        RECT  0 61.551 0.018 61.569 ;
        RECT  0 61.011 0.018 61.029 ;
        RECT  0 60.471 0.018 60.489 ;
        RECT  0 59.931 0.018 59.949 ;
        RECT  0 59.391 0.018 59.409 ;
        RECT  0 58.851 0.018 58.869 ;
        RECT  0 58.311 0.018 58.329 ;
        RECT  0 57.771 0.018 57.789 ;
        RECT  0 57.231 0.018 57.249 ;
        RECT  0 56.691 0.018 56.709 ;
        RECT  0 56.151 0.018 56.169 ;
        RECT  0 55.611 0.018 55.629 ;
        RECT  0 55.071 0.018 55.089 ;
        RECT  0 54.531 0.018 54.549 ;
        RECT  0 53.991 0.018 54.009 ;
        RECT  0 53.451 0.018 53.469 ;
        RECT  0 52.911 0.018 52.929 ;
        RECT  0 52.371 0.018 52.389 ;
        RECT  0 51.831 0.018 51.849 ;
        RECT  0 51.291 0.018 51.309 ;
        RECT  0 50.751 0.018 50.769 ;
        RECT  0 50.211 0.018 50.229 ;
        RECT  0 49.671 0.018 49.689 ;
        RECT  0 49.131 0.018 49.149 ;
        RECT  0 48.591 0.018 48.609 ;
        RECT  0 48.051 0.018 48.069 ;
        RECT  0 47.511 0.018 47.529 ;
        RECT  0 46.971 0.018 46.989 ;
        RECT  0 46.431 0.018 46.449 ;
        RECT  0 45.891 0.018 45.909 ;
        RECT  0 45.351 0.018 45.369 ;
        RECT  0 44.811 0.018 44.829 ;
        RECT  0 44.271 0.018 44.289 ;
        RECT  0 43.731 0.018 43.749 ;
        RECT  0 43.191 0.018 43.209 ;
        RECT  0 42.651 0.018 42.669 ;
        RECT  0 42.111 0.018 42.129 ;
        RECT  0 41.571 0.018 41.589 ;
        RECT  0 41.031 0.018 41.049 ;
        RECT  0 40.491 0.018 40.509 ;
        RECT  0 39.951 0.018 39.969 ;
        RECT  0 39.411 0.018 39.429 ;
        RECT  0 38.871 0.018 38.889 ;
        RECT  0 38.331 0.018 38.349 ;
        RECT  0 37.791 0.018 37.809 ;
        RECT  0 37.251 0.018 37.269 ;
        RECT  0 36.711 0.018 36.729 ;
        RECT  0 36.171 0.018 36.189 ;
        RECT  0 35.631 0.018 35.649 ;
        RECT  0 35.091 0.018 35.109 ;
        RECT  0 34.551 0.018 34.569 ;
        RECT  0 34.011 0.018 34.029 ;
        RECT  0 33.471 0.018 33.489 ;
        RECT  0 32.931 0.018 32.949 ;
        RECT  0 32.391 0.018 32.409 ;
        RECT  0 31.851 0.018 31.869 ;
        RECT  0 31.311 0.018 31.329 ;
        RECT  0 30.771 0.018 30.789 ;
        RECT  0 30.231 0.018 30.249 ;
        RECT  0 29.691 0.018 29.709 ;
        RECT  0 29.151 0.018 29.169 ;
        RECT  0 28.611 0.018 28.629 ;
        RECT  0 28.071 0.018 28.089 ;
        RECT  0 27.531 0.018 27.549 ;
        RECT  0 26.991 0.018 27.009 ;
        RECT  0 26.451 0.018 26.469 ;
        RECT  0 25.911 0.018 25.929 ;
        RECT  0 25.371 0.018 25.389 ;
        RECT  0 24.831 0.018 24.849 ;
        RECT  0 24.291 0.018 24.309 ;
        RECT  0 23.751 0.018 23.769 ;
        RECT  0 23.211 0.018 23.229 ;
        RECT  0 22.671 0.018 22.689 ;
        RECT  0 22.131 0.018 22.149 ;
        RECT  0 21.591 0.018 21.609 ;
        RECT  0 21.051 0.018 21.069 ;
        RECT  0 20.511 0.018 20.529 ;
        RECT  0 19.971 0.018 19.989 ;
        RECT  0 19.431 0.018 19.449 ;
        RECT  0 18.891 0.018 18.909 ;
        RECT  0 18.351 0.018 18.369 ;
        RECT  0 17.811 0.018 17.829 ;
        RECT  0 17.271 0.018 17.289 ;
        RECT  0 16.731 0.018 16.749 ;
        RECT  0 16.191 0.018 16.209 ;
        RECT  0 15.651 0.018 15.669 ;
        RECT  0 15.111 0.018 15.129 ;
        RECT  0 14.571 0.018 14.589 ;
        RECT  0 14.031 0.018 14.049 ;
        RECT  0 13.491 0.018 13.509 ;
        RECT  0 12.951 0.018 12.969 ;
        RECT  0 12.411 0.018 12.429 ;
        RECT  0 11.871 0.018 11.889 ;
        RECT  0 11.331 0.018 11.349 ;
        RECT  0 10.791 0.018 10.809 ;
        RECT  0 10.251 0.018 10.269 ;
        RECT  0 9.711 0.018 9.729 ;
        RECT  0 9.171 0.018 9.189 ;
        RECT  0 8.631 0.018 8.649 ;
        RECT  0 8.091 0.018 8.109 ;
        RECT  0 7.551 0.018 7.569 ;
        RECT  0 7.011 0.018 7.029 ;
        RECT  0 6.471 0.018 6.489 ;
        RECT  0 5.931 0.018 5.949 ;
        RECT  0 5.391 0.018 5.409 ;
        RECT  0 4.851 0.018 4.869 ;
        RECT  0 4.311 0.018 4.329 ;
        RECT  0 3.771 0.018 3.789 ;
        RECT  0 3.231 0.018 3.249 ;
        RECT  0 2.691 0.018 2.709 ;
        RECT  0 2.151 0.018 2.169 ;
        RECT  0 1.611 0.018 1.629 ;
        RECT  0 1.071 0.018 1.089 ;
        RECT  0 0.531 0.018 0.549 ;
      LAYER M1 ;
        RECT  0 80.991 0.018 81.009 ;
        RECT  0 80.451 0.018 80.469 ;
        RECT  0 79.911 0.018 79.929 ;
        RECT  0 79.371 0.018 79.389 ;
        RECT  0 78.831 0.018 78.849 ;
        RECT  0 78.291 0.018 78.309 ;
        RECT  0 77.751 0.018 77.769 ;
        RECT  0 77.211 0.018 77.229 ;
        RECT  0 76.671 0.018 76.689 ;
        RECT  0 76.131 0.018 76.149 ;
        RECT  0 75.591 0.018 75.609 ;
        RECT  0 75.051 0.018 75.069 ;
        RECT  0 74.511 0.018 74.529 ;
        RECT  0 73.971 0.018 73.989 ;
        RECT  0 73.431 0.018 73.449 ;
        RECT  0 72.891 0.018 72.909 ;
        RECT  0 72.351 0.018 72.369 ;
        RECT  0 71.811 0.018 71.829 ;
        RECT  0 71.271 0.018 71.289 ;
        RECT  0 70.731 0.018 70.749 ;
        RECT  0 70.191 0.018 70.209 ;
        RECT  0 69.651 0.018 69.669 ;
        RECT  0 69.111 0.018 69.129 ;
        RECT  0 68.571 0.018 68.589 ;
        RECT  0 68.031 0.018 68.049 ;
        RECT  0 67.491 0.018 67.509 ;
        RECT  0 66.951 0.018 66.969 ;
        RECT  0 66.411 0.018 66.429 ;
        RECT  0 65.871 0.018 65.889 ;
        RECT  0 65.331 0.018 65.349 ;
        RECT  0 64.791 0.018 64.809 ;
        RECT  0 64.251 0.018 64.269 ;
        RECT  0 63.711 0.018 63.729 ;
        RECT  0 63.171 0.018 63.189 ;
        RECT  0 62.631 0.018 62.649 ;
        RECT  0 62.091 0.018 62.109 ;
        RECT  0 61.551 0.018 61.569 ;
        RECT  0 61.011 0.018 61.029 ;
        RECT  0 60.471 0.018 60.489 ;
        RECT  0 59.931 0.018 59.949 ;
        RECT  0 59.391 0.018 59.409 ;
        RECT  0 58.851 0.018 58.869 ;
        RECT  0 58.311 0.018 58.329 ;
        RECT  0 57.771 0.018 57.789 ;
        RECT  0 57.231 0.018 57.249 ;
        RECT  0 56.691 0.018 56.709 ;
        RECT  0 56.151 0.018 56.169 ;
        RECT  0 55.611 0.018 55.629 ;
        RECT  0 55.071 0.018 55.089 ;
        RECT  0 54.531 0.018 54.549 ;
        RECT  0 53.991 0.018 54.009 ;
        RECT  0 53.451 0.018 53.469 ;
        RECT  0 52.911 0.018 52.929 ;
        RECT  0 52.371 0.018 52.389 ;
        RECT  0 51.831 0.018 51.849 ;
        RECT  0 51.291 0.018 51.309 ;
        RECT  0 50.751 0.018 50.769 ;
        RECT  0 50.211 0.018 50.229 ;
        RECT  0 49.671 0.018 49.689 ;
        RECT  0 49.131 0.018 49.149 ;
        RECT  0 48.591 0.018 48.609 ;
        RECT  0 48.051 0.018 48.069 ;
        RECT  0 47.511 0.018 47.529 ;
        RECT  0 46.971 0.018 46.989 ;
        RECT  0 46.431 0.018 46.449 ;
        RECT  0 45.891 0.018 45.909 ;
        RECT  0 45.351 0.018 45.369 ;
        RECT  0 44.811 0.018 44.829 ;
        RECT  0 44.271 0.018 44.289 ;
        RECT  0 43.731 0.018 43.749 ;
        RECT  0 43.191 0.018 43.209 ;
        RECT  0 42.651 0.018 42.669 ;
        RECT  0 42.111 0.018 42.129 ;
        RECT  0 41.571 0.018 41.589 ;
        RECT  0 41.031 0.018 41.049 ;
        RECT  0 40.491 0.018 40.509 ;
        RECT  0 39.951 0.018 39.969 ;
        RECT  0 39.411 0.018 39.429 ;
        RECT  0 38.871 0.018 38.889 ;
        RECT  0 38.331 0.018 38.349 ;
        RECT  0 37.791 0.018 37.809 ;
        RECT  0 37.251 0.018 37.269 ;
        RECT  0 36.711 0.018 36.729 ;
        RECT  0 36.171 0.018 36.189 ;
        RECT  0 35.631 0.018 35.649 ;
        RECT  0 35.091 0.018 35.109 ;
        RECT  0 34.551 0.018 34.569 ;
        RECT  0 34.011 0.018 34.029 ;
        RECT  0 33.471 0.018 33.489 ;
        RECT  0 32.931 0.018 32.949 ;
        RECT  0 32.391 0.018 32.409 ;
        RECT  0 31.851 0.018 31.869 ;
        RECT  0 31.311 0.018 31.329 ;
        RECT  0 30.771 0.018 30.789 ;
        RECT  0 30.231 0.018 30.249 ;
        RECT  0 29.691 0.018 29.709 ;
        RECT  0 29.151 0.018 29.169 ;
        RECT  0 28.611 0.018 28.629 ;
        RECT  0 28.071 0.018 28.089 ;
        RECT  0 27.531 0.018 27.549 ;
        RECT  0 26.991 0.018 27.009 ;
        RECT  0 26.451 0.018 26.469 ;
        RECT  0 25.911 0.018 25.929 ;
        RECT  0 25.371 0.018 25.389 ;
        RECT  0 24.831 0.018 24.849 ;
        RECT  0 24.291 0.018 24.309 ;
        RECT  0 23.751 0.018 23.769 ;
        RECT  0 23.211 0.018 23.229 ;
        RECT  0 22.671 0.018 22.689 ;
        RECT  0 22.131 0.018 22.149 ;
        RECT  0 21.591 0.018 21.609 ;
        RECT  0 21.051 0.018 21.069 ;
        RECT  0 20.511 0.018 20.529 ;
        RECT  0 19.971 0.018 19.989 ;
        RECT  0 19.431 0.018 19.449 ;
        RECT  0 18.891 0.018 18.909 ;
        RECT  0 18.351 0.018 18.369 ;
        RECT  0 17.811 0.018 17.829 ;
        RECT  0 17.271 0.018 17.289 ;
        RECT  0 16.731 0.018 16.749 ;
        RECT  0 16.191 0.018 16.209 ;
        RECT  0 15.651 0.018 15.669 ;
        RECT  0 15.111 0.018 15.129 ;
        RECT  0 14.571 0.018 14.589 ;
        RECT  0 14.031 0.018 14.049 ;
        RECT  0 13.491 0.018 13.509 ;
        RECT  0 12.951 0.018 12.969 ;
        RECT  0 12.411 0.018 12.429 ;
        RECT  0 11.871 0.018 11.889 ;
        RECT  0 11.331 0.018 11.349 ;
        RECT  0 10.791 0.018 10.809 ;
        RECT  0 10.251 0.018 10.269 ;
        RECT  0 9.711 0.018 9.729 ;
        RECT  0 9.171 0.018 9.189 ;
        RECT  0 8.631 0.018 8.649 ;
        RECT  0 8.091 0.018 8.109 ;
        RECT  0 7.551 0.018 7.569 ;
        RECT  0 7.011 0.018 7.029 ;
        RECT  0 6.471 0.018 6.489 ;
        RECT  0 5.931 0.018 5.949 ;
        RECT  0 5.391 0.018 5.409 ;
        RECT  0 4.851 0.018 4.869 ;
        RECT  0 4.311 0.018 4.329 ;
        RECT  0 3.771 0.018 3.789 ;
        RECT  0 3.231 0.018 3.249 ;
        RECT  0 2.691 0.018 2.709 ;
        RECT  0 2.151 0.018 2.169 ;
        RECT  0 1.611 0.018 1.629 ;
        RECT  0 1.071 0.018 1.089 ;
        RECT  0 0.531 0.018 0.549 ;
    END
  END VSS
  OBS
    LAYER RVTN ;
     RECT  0 0.54 81.162 0.675 ;
     RECT  0 0.945 81.162 1.215 ;
     RECT  0 1.485 81.162 1.755 ;
     RECT  0 2.025 81.162 2.295 ;
     RECT  0 2.565 81.162 2.835 ;
     RECT  0 3.105 81.162 3.375 ;
     RECT  0 3.645 81.162 3.915 ;
     RECT  0 4.185 81.162 4.455 ;
     RECT  0 4.725 81.162 4.995 ;
     RECT  0 5.265 81.162 5.535 ;
     RECT  0 5.805 81.162 6.075 ;
     RECT  0 6.345 81.162 6.615 ;
     RECT  0 6.885 81.162 7.155 ;
     RECT  0 7.425 81.162 7.695 ;
     RECT  0 7.965 81.162 8.235 ;
     RECT  0 8.505 81.162 8.775 ;
     RECT  0 9.045 81.162 9.315 ;
     RECT  0 9.585 81.162 9.855 ;
     RECT  0 10.125 81.162 10.395 ;
     RECT  0 10.665 81.162 10.935 ;
     RECT  0 11.205 81.162 11.475 ;
     RECT  0 11.745 81.162 12.015 ;
     RECT  0 12.285 81.162 12.555 ;
     RECT  0 12.825 81.162 13.095 ;
     RECT  0 13.365 81.162 13.635 ;
     RECT  0 13.905 81.162 14.175 ;
     RECT  0 14.445 81.162 14.715 ;
     RECT  0 14.985 81.162 15.255 ;
     RECT  0 15.525 81.162 15.795 ;
     RECT  0 16.065 81.162 16.335 ;
     RECT  0 16.605 81.162 16.875 ;
     RECT  0 17.145 81.162 17.415 ;
     RECT  0 17.685 81.162 17.955 ;
     RECT  0 18.225 81.162 18.495 ;
     RECT  0 18.765 81.162 19.035 ;
     RECT  0 19.305 81.162 19.575 ;
     RECT  0 19.845 81.162 20.115 ;
     RECT  0 20.385 81.162 20.655 ;
     RECT  0 20.925 81.162 21.195 ;
     RECT  0 21.465 81.162 21.735 ;
     RECT  0 22.005 81.162 22.275 ;
     RECT  0 22.545 81.162 22.815 ;
     RECT  0 23.085 81.162 23.355 ;
     RECT  0 23.625 81.162 23.895 ;
     RECT  0 24.165 81.162 24.435 ;
     RECT  0 24.705 81.162 24.975 ;
     RECT  0 25.245 81.162 25.515 ;
     RECT  0 25.785 81.162 26.055 ;
     RECT  0 26.325 81.162 26.595 ;
     RECT  0 26.865 81.162 27.135 ;
     RECT  0 27.405 81.162 27.675 ;
     RECT  0 27.945 81.162 28.215 ;
     RECT  0 28.485 81.162 28.755 ;
     RECT  0 29.025 81.162 29.295 ;
     RECT  0 29.565 81.162 29.835 ;
     RECT  0 30.105 81.162 30.375 ;
     RECT  0 30.645 81.162 30.915 ;
     RECT  0 31.185 81.162 31.455 ;
     RECT  0 31.725 81.162 31.995 ;
     RECT  0 32.265 81.162 32.535 ;
     RECT  0 32.805 81.162 33.075 ;
     RECT  0 33.345 81.162 33.615 ;
     RECT  0 33.885 81.162 34.155 ;
     RECT  0 34.425 81.162 34.695 ;
     RECT  0 34.965 81.162 35.235 ;
     RECT  0 35.505 81.162 35.775 ;
     RECT  0 36.045 81.162 36.315 ;
     RECT  0 36.585 81.162 36.855 ;
     RECT  0 37.125 81.162 37.395 ;
     RECT  0 37.665 81.162 37.935 ;
     RECT  0 38.205 81.162 38.475 ;
     RECT  0 38.745 81.162 39.015 ;
     RECT  0 39.285 81.162 39.555 ;
     RECT  0 39.825 81.162 40.095 ;
     RECT  0 40.365 81.162 40.635 ;
     RECT  0 40.905 81.162 41.175 ;
     RECT  0 41.445 81.162 41.715 ;
     RECT  0 41.985 81.162 42.255 ;
     RECT  0 42.525 81.162 42.795 ;
     RECT  0 43.065 81.162 43.335 ;
     RECT  0 43.605 81.162 43.875 ;
     RECT  0 44.145 81.162 44.415 ;
     RECT  0 44.685 81.162 44.955 ;
     RECT  0 45.225 81.162 45.495 ;
     RECT  0 45.765 81.162 46.035 ;
     RECT  0 46.305 81.162 46.575 ;
     RECT  0 46.845 81.162 47.115 ;
     RECT  0 47.385 81.162 47.655 ;
     RECT  0 47.925 81.162 48.195 ;
     RECT  0 48.465 81.162 48.735 ;
     RECT  0 49.005 81.162 49.275 ;
     RECT  0 49.545 81.162 49.815 ;
     RECT  0 50.085 81.162 50.355 ;
     RECT  0 50.625 81.162 50.895 ;
     RECT  0 51.165 81.162 51.435 ;
     RECT  0 51.705 81.162 51.975 ;
     RECT  0 52.245 81.162 52.515 ;
     RECT  0 52.785 81.162 53.055 ;
     RECT  0 53.325 81.162 53.595 ;
     RECT  0 53.865 81.162 54.135 ;
     RECT  0 54.405 81.162 54.675 ;
     RECT  0 54.945 81.162 55.215 ;
     RECT  0 55.485 81.162 55.755 ;
     RECT  0 56.025 81.162 56.295 ;
     RECT  0 56.565 81.162 56.835 ;
     RECT  0 57.105 81.162 57.375 ;
     RECT  0 57.645 81.162 57.915 ;
     RECT  0 58.185 81.162 58.455 ;
     RECT  0 58.725 81.162 58.995 ;
     RECT  0 59.265 81.162 59.535 ;
     RECT  0 59.805 81.162 60.075 ;
     RECT  0 60.345 81.162 60.615 ;
     RECT  0 60.885 81.162 61.155 ;
     RECT  0 61.425 81.162 61.695 ;
     RECT  0 61.965 81.162 62.235 ;
     RECT  0 62.505 81.162 62.775 ;
     RECT  0 63.045 81.162 63.315 ;
     RECT  0 63.585 81.162 63.855 ;
     RECT  0 64.125 81.162 64.395 ;
     RECT  0 64.665 81.162 64.935 ;
     RECT  0 65.205 81.162 65.475 ;
     RECT  0 65.745 81.162 66.015 ;
     RECT  0 66.285 81.162 66.555 ;
     RECT  0 66.825 81.162 67.095 ;
     RECT  0 67.365 81.162 67.635 ;
     RECT  0 67.905 81.162 68.175 ;
     RECT  0 68.445 81.162 68.715 ;
     RECT  0 68.985 81.162 69.255 ;
     RECT  0 69.525 81.162 69.795 ;
     RECT  0 70.065 81.162 70.335 ;
     RECT  0 70.605 81.162 70.875 ;
     RECT  0 71.145 81.162 71.415 ;
     RECT  0 71.685 81.162 71.955 ;
     RECT  0 72.225 81.162 72.495 ;
     RECT  0 72.765 81.162 73.035 ;
     RECT  0 73.305 81.162 73.575 ;
     RECT  0 73.845 81.162 74.115 ;
     RECT  0 74.385 81.162 74.655 ;
     RECT  0 74.925 81.162 75.195 ;
     RECT  0 75.465 81.162 75.735 ;
     RECT  0 76.005 81.162 76.275 ;
     RECT  0 76.545 81.162 76.815 ;
     RECT  0 77.085 81.162 77.355 ;
     RECT  0 77.625 81.162 77.895 ;
     RECT  0 78.165 81.162 78.435 ;
     RECT  0 78.705 81.162 78.975 ;
     RECT  0 79.245 81.162 79.515 ;
     RECT  0 79.785 81.162 80.055 ;
     RECT  0 80.325 81.162 80.595 ;
     RECT  0 80.865 81.162 81.135 ;
    LAYER RVTP ;
     RECT  0 0.675 81.162 0.945 ;
     RECT  0 1.215 81.162 1.485 ;
     RECT  0 1.755 81.162 2.025 ;
     RECT  0 2.295 81.162 2.565 ;
     RECT  0 2.835 81.162 3.105 ;
     RECT  0 3.375 81.162 3.645 ;
     RECT  0 3.915 81.162 4.185 ;
     RECT  0 4.455 81.162 4.725 ;
     RECT  0 4.995 81.162 5.265 ;
     RECT  0 5.535 81.162 5.805 ;
     RECT  0 6.075 81.162 6.345 ;
     RECT  0 6.615 81.162 6.885 ;
     RECT  0 7.155 81.162 7.425 ;
     RECT  0 7.695 81.162 7.965 ;
     RECT  0 8.235 81.162 8.505 ;
     RECT  0 8.775 81.162 9.045 ;
     RECT  0 9.315 81.162 9.585 ;
     RECT  0 9.855 81.162 10.125 ;
     RECT  0 10.395 81.162 10.665 ;
     RECT  0 10.935 81.162 11.205 ;
     RECT  0 11.475 81.162 11.745 ;
     RECT  0 12.015 81.162 12.285 ;
     RECT  0 12.555 81.162 12.825 ;
     RECT  0 13.095 81.162 13.365 ;
     RECT  0 13.635 81.162 13.905 ;
     RECT  0 14.175 81.162 14.445 ;
     RECT  0 14.715 81.162 14.985 ;
     RECT  0 15.255 81.162 15.525 ;
     RECT  0 15.795 81.162 16.065 ;
     RECT  0 16.335 81.162 16.605 ;
     RECT  0 16.875 81.162 17.145 ;
     RECT  0 17.415 81.162 17.685 ;
     RECT  0 17.955 81.162 18.225 ;
     RECT  0 18.495 81.162 18.765 ;
     RECT  0 19.035 81.162 19.305 ;
     RECT  0 19.575 81.162 19.845 ;
     RECT  0 20.115 81.162 20.385 ;
     RECT  0 20.655 81.162 20.925 ;
     RECT  0 21.195 81.162 21.465 ;
     RECT  0 21.735 81.162 22.005 ;
     RECT  0 22.275 81.162 22.545 ;
     RECT  0 22.815 81.162 23.085 ;
     RECT  0 23.355 81.162 23.625 ;
     RECT  0 23.895 81.162 24.165 ;
     RECT  0 24.435 81.162 24.705 ;
     RECT  0 24.975 81.162 25.245 ;
     RECT  0 25.515 81.162 25.785 ;
     RECT  0 26.055 81.162 26.325 ;
     RECT  0 26.595 81.162 26.865 ;
     RECT  0 27.135 81.162 27.405 ;
     RECT  0 27.675 81.162 27.945 ;
     RECT  0 28.215 81.162 28.485 ;
     RECT  0 28.755 81.162 29.025 ;
     RECT  0 29.295 81.162 29.565 ;
     RECT  0 29.835 81.162 30.105 ;
     RECT  0 30.375 81.162 30.645 ;
     RECT  0 30.915 81.162 31.185 ;
     RECT  0 31.455 81.162 31.725 ;
     RECT  0 31.995 81.162 32.265 ;
     RECT  0 32.535 81.162 32.805 ;
     RECT  0 33.075 81.162 33.345 ;
     RECT  0 33.615 81.162 33.885 ;
     RECT  0 34.155 81.162 34.425 ;
     RECT  0 34.695 81.162 34.965 ;
     RECT  0 35.235 81.162 35.505 ;
     RECT  0 35.775 81.162 36.045 ;
     RECT  0 36.315 81.162 36.585 ;
     RECT  0 36.855 81.162 37.125 ;
     RECT  0 37.395 81.162 37.665 ;
     RECT  0 37.935 81.162 38.205 ;
     RECT  0 38.475 81.162 38.745 ;
     RECT  0 39.015 81.162 39.285 ;
     RECT  0 39.555 81.162 39.825 ;
     RECT  0 40.095 81.162 40.365 ;
     RECT  0 40.635 81.162 40.905 ;
     RECT  0 41.175 81.162 41.445 ;
     RECT  0 41.715 81.162 41.985 ;
     RECT  0 42.255 81.162 42.525 ;
     RECT  0 42.795 81.162 43.065 ;
     RECT  0 43.335 81.162 43.605 ;
     RECT  0 43.875 81.162 44.145 ;
     RECT  0 44.415 81.162 44.685 ;
     RECT  0 44.955 81.162 45.225 ;
     RECT  0 45.495 81.162 45.765 ;
     RECT  0 46.035 81.162 46.305 ;
     RECT  0 46.575 81.162 46.845 ;
     RECT  0 47.115 81.162 47.385 ;
     RECT  0 47.655 81.162 47.925 ;
     RECT  0 48.195 81.162 48.465 ;
     RECT  0 48.735 81.162 49.005 ;
     RECT  0 49.275 81.162 49.545 ;
     RECT  0 49.815 81.162 50.085 ;
     RECT  0 50.355 81.162 50.625 ;
     RECT  0 50.895 81.162 51.165 ;
     RECT  0 51.435 81.162 51.705 ;
     RECT  0 51.975 81.162 52.245 ;
     RECT  0 52.515 81.162 52.785 ;
     RECT  0 53.055 81.162 53.325 ;
     RECT  0 53.595 81.162 53.865 ;
     RECT  0 54.135 81.162 54.405 ;
     RECT  0 54.675 81.162 54.945 ;
     RECT  0 55.215 81.162 55.485 ;
     RECT  0 55.755 81.162 56.025 ;
     RECT  0 56.295 81.162 56.565 ;
     RECT  0 56.835 81.162 57.105 ;
     RECT  0 57.375 81.162 57.645 ;
     RECT  0 57.915 81.162 58.185 ;
     RECT  0 58.455 81.162 58.725 ;
     RECT  0 58.995 81.162 59.265 ;
     RECT  0 59.535 81.162 59.805 ;
     RECT  0 60.075 81.162 60.345 ;
     RECT  0 60.615 81.162 60.885 ;
     RECT  0 61.155 81.162 61.425 ;
     RECT  0 61.695 81.162 61.965 ;
     RECT  0 62.235 81.162 62.505 ;
     RECT  0 62.775 81.162 63.045 ;
     RECT  0 63.315 81.162 63.585 ;
     RECT  0 63.855 81.162 64.125 ;
     RECT  0 64.395 81.162 64.665 ;
     RECT  0 64.935 81.162 65.205 ;
     RECT  0 65.475 81.162 65.745 ;
     RECT  0 66.015 81.162 66.285 ;
     RECT  0 66.555 81.162 66.825 ;
     RECT  0 67.095 81.162 67.365 ;
     RECT  0 67.635 81.162 67.905 ;
     RECT  0 68.175 81.162 68.445 ;
     RECT  0 68.715 81.162 68.985 ;
     RECT  0 69.255 81.162 69.525 ;
     RECT  0 69.795 81.162 70.065 ;
     RECT  0 70.335 81.162 70.605 ;
     RECT  0 70.875 81.162 71.145 ;
     RECT  0 71.415 81.162 71.685 ;
     RECT  0 71.955 81.162 72.225 ;
     RECT  0 72.495 81.162 72.765 ;
     RECT  0 73.035 81.162 73.305 ;
     RECT  0 73.575 81.162 73.845 ;
     RECT  0 74.115 81.162 74.385 ;
     RECT  0 74.655 81.162 74.925 ;
     RECT  0 75.195 81.162 75.465 ;
     RECT  0 75.735 81.162 76.005 ;
     RECT  0 76.275 81.162 76.545 ;
     RECT  0 76.815 81.162 77.085 ;
     RECT  0 77.355 81.162 77.625 ;
     RECT  0 77.895 81.162 78.165 ;
     RECT  0 78.435 81.162 78.705 ;
     RECT  0 78.975 81.162 79.245 ;
     RECT  0 79.515 81.162 79.785 ;
     RECT  0 80.055 81.162 80.325 ;
     RECT  0 80.595 81.162 80.865 ;
     RECT  0 81.135 81.162 81.27 ;
    LAYER M1 ;
     RECT  0 0.531 81.162 81.279 ;
    LAYER M2 ;
     RECT  0 0.531 81.162 81.279 ;
     RECT  81.162 22.788 81.167 22.806 ;
     RECT  81.162 31.122 81.167 31.14 ;
     RECT  81.162 55.728 81.167 55.746 ;
     RECT  81.162 62.244 81.167 62.262 ;
     RECT  81.162 64.134 81.167 64.152 ;
     RECT  81.162 74.628 81.167 74.646 ;
    LAYER M3 ;
     RECT  80.388 0.619 80.406 0.715 ;
     RECT  0.255 0.523 0.345 0.793 ;
     RECT  5.655 0.523 5.745 0.793 ;
     RECT  11.055 0.523 11.145 0.793 ;
     RECT  16.455 0.523 16.545 0.793 ;
     RECT  21.855 0.523 21.945 0.793 ;
     RECT  27.255 0.523 27.345 0.793 ;
     RECT  32.655 0.523 32.745 0.793 ;
     RECT  38.055 0.523 38.145 0.793 ;
     RECT  43.455 0.523 43.545 0.793 ;
     RECT  48.855 0.523 48.945 0.793 ;
     RECT  54.255 0.523 54.345 0.793 ;
     RECT  59.655 0.523 59.745 0.793 ;
     RECT  65.055 0.523 65.145 0.793 ;
     RECT  70.455 0.523 70.545 0.793 ;
     RECT  75.855 0.523 75.945 0.793 ;
     RECT  79.812 0.715 80.406 0.811 ;
     RECT  79.812 0.811 80.442 0.907 ;
     RECT  79.812 0.907 80.478 1.003 ;
     RECT  31.068 0.859 31.086 1.021 ;
     RECT  79.812 1.003 80.514 1.099 ;
     RECT  78.408 0.859 78.426 1.139 ;
     RECT  79.812 1.099 80.586 1.195 ;
     RECT  79.812 1.195 80.622 1.291 ;
     RECT  79.272 1.291 80.658 1.387 ;
     RECT  31.068 1.021 31.302 1.421 ;
     RECT  79.272 1.387 80.694 1.435 ;
     RECT  31.068 1.421 31.086 1.481 ;
     RECT  79.272 1.435 80.766 1.483 ;
     RECT  79.272 1.483 80.838 1.795 ;
     RECT  78.66 1.795 80.838 1.963 ;
     RECT  32.655 0.793 32.937 2.065 ;
     RECT  65.055 0.793 65.337 2.101 ;
     RECT  70.455 0.793 70.737 2.101 ;
     RECT  74.664 1.831 74.682 2.101 ;
     RECT  74.664 2.101 74.754 2.129 ;
     RECT  32.655 2.065 32.994 2.227 ;
     RECT  74.736 2.129 74.754 2.255 ;
     RECT  78.624 1.963 80.838 2.291 ;
     RECT  75.855 0.793 76.137 2.371 ;
     RECT  75.456 2.371 76.137 2.561 ;
     RECT  78.66 2.291 80.694 2.597 ;
     RECT  77.508 2.539 77.526 2.635 ;
     RECT  70.455 2.101 71.154 2.641 ;
     RECT  78.66 2.597 80.658 2.669 ;
     RECT  34.236 2.725 34.254 2.765 ;
     RECT  70.02 2.641 71.154 2.795 ;
     RECT  34.164 2.767 34.182 2.813 ;
     RECT  65.055 2.101 65.826 2.839 ;
     RECT  79.2 2.669 80.658 2.861 ;
     RECT  38.055 0.793 38.337 3.073 ;
     RECT  61.848 2.875 61.866 3.101 ;
     RECT  70.056 2.795 71.154 3.101 ;
     RECT  59.655 0.793 59.937 3.109 ;
     RECT  70.38 3.101 71.154 3.145 ;
     RECT  74.664 3.109 74.682 3.181 ;
     RECT  77.472 2.635 77.526 3.181 ;
     RECT  58.716 3.073 58.734 3.209 ;
     RECT  74.196 3.181 74.682 3.271 ;
     RECT  70.38 3.145 71.37 3.335 ;
     RECT  74.124 3.271 74.682 3.341 ;
     RECT  32.655 2.227 33.426 3.343 ;
     RECT  77.472 3.181 77.814 3.379 ;
     RECT  74.628 3.341 74.682 3.605 ;
     RECT  75.672 2.561 76.137 3.691 ;
     RECT  75.672 3.691 76.374 3.721 ;
     RECT  79.2 2.861 80.514 3.787 ;
     RECT  32.112 3.343 33.426 3.811 ;
     RECT  78.66 3.787 80.514 3.811 ;
     RECT  75.492 3.721 76.446 3.875 ;
     RECT  69.3 3.181 69.318 4.261 ;
     RECT  68.652 4.261 69.318 4.621 ;
     RECT  70.38 3.335 71.154 4.651 ;
     RECT  59.655 3.109 60.138 4.693 ;
     RECT  63 4.621 63.018 4.693 ;
     RECT  63.756 4.657 63.774 4.693 ;
     RECT  70.38 4.651 71.73 4.699 ;
     RECT  75.492 3.875 76.374 4.721 ;
     RECT  68.616 4.621 69.318 4.793 ;
     RECT  68.652 4.793 69.318 4.801 ;
     RECT  70.38 4.699 71.802 4.801 ;
     RECT  75.492 4.721 76.302 4.829 ;
     RECT  37.188 2.461 37.206 4.927 ;
     RECT  38.055 3.073 38.934 4.927 ;
     RECT  40.392 4.891 40.41 4.928 ;
     RECT  37.188 4.927 38.934 4.973 ;
     RECT  35.316 3.847 35.334 5.035 ;
     RECT  35.316 5.035 35.514 5.071 ;
     RECT  40.464 5.071 40.482 5.117 ;
     RECT  65.055 2.839 65.898 5.305 ;
     RECT  67.536 2.191 67.554 5.305 ;
     RECT  68.652 4.801 71.802 5.333 ;
     RECT  63 4.693 63.774 5.341 ;
     RECT  64.944 5.305 65.898 5.341 ;
     RECT  63 5.341 65.898 5.357 ;
     RECT  78.66 3.811 80.622 5.419 ;
     RECT  37.188 4.973 37.206 5.467 ;
     RECT  78.66 5.419 80.982 5.467 ;
     RECT  78.66 5.467 81.054 5.504 ;
     RECT  36.792 5.467 37.206 5.515 ;
     RECT  35.136 5.071 35.514 5.563 ;
     RECT  67.14 5.305 67.554 5.567 ;
     RECT  74.628 3.605 74.646 5.567 ;
     RECT  34.848 5.563 35.514 5.611 ;
     RECT  43.455 0.793 43.737 5.773 ;
     RECT  39.672 5.035 39.69 5.809 ;
     RECT  34.56 5.611 35.514 5.845 ;
     RECT  34.524 5.845 35.514 5.881 ;
     RECT  36.432 5.515 37.206 5.881 ;
     RECT  42.768 5.773 43.737 5.909 ;
     RECT  39.672 5.809 39.762 6.035 ;
     RECT  39.744 6.035 39.762 6.071 ;
     RECT  32.112 3.811 33.714 6.151 ;
     RECT  34.524 5.881 37.206 6.151 ;
     RECT  77.22 3.379 77.814 6.571 ;
     RECT  78.66 5.504 80.874 6.571 ;
     RECT  77.22 6.571 80.874 6.619 ;
     RECT  74.664 6.043 74.682 6.719 ;
     RECT  77.22 6.619 80.946 6.719 ;
     RECT  75.492 4.829 76.137 6.763 ;
     RECT  32.112 6.151 37.206 7.051 ;
     RECT  38.055 4.973 38.934 7.051 ;
     RECT  68.652 5.333 71.334 7.123 ;
     RECT  75.492 6.763 76.374 7.321 ;
     RECT  68.652 7.123 71.766 7.393 ;
     RECT  74.124 7.321 74.142 7.393 ;
     RECT  75.456 7.321 76.374 7.493 ;
     RECT  63 5.357 64.242 7.501 ;
     RECT  73.908 7.393 74.142 7.501 ;
     RECT  73.692 7.501 74.142 7.619 ;
     RECT  43.455 5.909 43.737 7.699 ;
     RECT  73.728 7.619 74.142 7.727 ;
     RECT  75.492 7.493 76.374 7.727 ;
     RECT  73.8 7.727 74.142 7.735 ;
     RECT  41.94 7.771 41.958 7.861 ;
     RECT  42.804 7.699 43.737 7.861 ;
     RECT  41.94 7.861 43.737 7.889 ;
     RECT  62.748 7.501 64.242 7.889 ;
     RECT  73.8 7.735 74.754 7.889 ;
     RECT  77.22 6.719 80.802 7.889 ;
     RECT  73.836 7.889 74.682 7.961 ;
     RECT  40.896 5.701 40.914 8.005 ;
     RECT  63 7.889 64.242 8.005 ;
     RECT  65.055 5.357 65.898 8.005 ;
     RECT  68.652 7.393 71.838 8.069 ;
     RECT  41.832 8.005 41.85 8.159 ;
     RECT  54.255 0.793 54.537 8.167 ;
     RECT  40.644 8.005 40.914 8.195 ;
     RECT  74.124 7.961 74.682 8.231 ;
     RECT  72.684 3.721 72.702 8.239 ;
     RECT  54.255 8.167 54.702 8.275 ;
     RECT  74.664 8.231 74.682 8.303 ;
     RECT  32.112 7.051 38.934 8.311 ;
     RECT  39.78 6.151 39.798 8.311 ;
     RECT  41.724 8.203 41.742 8.311 ;
     RECT  77.22 7.889 80.766 8.339 ;
     RECT  32.112 8.311 39.798 8.401 ;
     RECT  40.644 8.195 40.77 8.401 ;
     RECT  47.088 8.239 47.106 8.401 ;
     RECT  72.684 8.239 72.738 8.401 ;
     RECT  32.112 8.401 40.77 8.429 ;
     RECT  41.688 8.311 41.742 8.429 ;
     RECT  46.26 8.311 46.278 8.429 ;
     RECT  63 8.005 65.898 8.429 ;
     RECT  54.255 8.275 54.846 8.465 ;
     RECT  41.688 8.429 41.706 8.501 ;
     RECT  78.66 8.339 80.766 8.501 ;
     RECT  46.08 8.491 46.098 8.537 ;
     RECT  47.052 8.401 47.106 8.537 ;
     RECT  72.684 8.401 72.846 8.537 ;
     RECT  78.696 8.501 80.766 8.779 ;
     RECT  75.492 7.727 76.137 8.815 ;
     RECT  78.696 8.779 80.91 8.969 ;
     RECT  78.696 8.969 80.766 9.005 ;
     RECT  42.588 7.889 43.737 9.211 ;
     RECT  77.22 8.339 77.814 9.259 ;
     RECT  78.696 9.005 80.622 9.259 ;
     RECT  42.444 9.211 43.737 9.355 ;
     RECT  75.492 8.815 76.446 9.355 ;
     RECT  77.22 9.259 80.622 9.355 ;
     RECT  67.356 5.567 67.554 9.391 ;
     RECT  74.628 8.971 74.646 9.419 ;
     RECT  66.924 9.391 67.554 9.545 ;
     RECT  75.492 9.355 80.622 9.545 ;
     RECT  63 8.429 64.242 9.553 ;
     RECT  62.712 9.553 64.242 9.751 ;
     RECT  65.055 8.429 65.898 9.751 ;
     RECT  74.736 9.751 74.754 9.787 ;
     RECT  75.492 9.545 76.482 9.787 ;
     RECT  32.112 8.429 39.942 9.823 ;
     RECT  40.752 8.429 40.77 9.823 ;
     RECT  74.736 9.787 76.482 9.851 ;
     RECT  47.052 8.537 47.07 9.859 ;
     RECT  75.168 9.851 76.41 9.887 ;
     RECT  59.655 4.693 60.714 9.931 ;
     RECT  62.712 9.751 65.898 9.931 ;
     RECT  77.22 9.545 80.622 10.027 ;
     RECT  58.716 9.931 58.734 10.049 ;
     RECT  62.424 9.931 65.898 10.049 ;
     RECT  75.168 9.887 76.137 10.049 ;
     RECT  62.424 10.049 64.314 10.121 ;
     RECT  45.792 9.859 45.81 10.157 ;
     RECT  44.748 4.963 44.766 10.201 ;
     RECT  44.748 10.201 44.838 10.253 ;
     RECT  46.728 9.859 47.07 10.435 ;
     RECT  73.548 10.201 73.566 10.499 ;
     RECT  42.156 9.355 43.737 10.589 ;
     RECT  74.628 10.603 74.646 10.633 ;
     RECT  46.584 10.435 47.07 10.669 ;
     RECT  46.404 10.669 47.07 10.733 ;
     RECT  65.055 10.049 65.898 10.769 ;
     RECT  77.22 10.027 80.838 10.795 ;
     RECT  67.356 9.545 67.554 10.831 ;
     RECT  65.055 10.769 65.826 10.859 ;
     RECT  32.112 9.823 40.77 10.867 ;
     RECT  31.464 10.867 40.77 10.939 ;
     RECT  74.124 10.633 74.646 10.967 ;
     RECT  42.156 10.589 42.714 11.011 ;
     RECT  58.788 10.867 58.806 11.011 ;
     RECT  59.655 9.931 60.786 11.011 ;
     RECT  58.716 11.011 58.806 11.039 ;
     RECT  59.655 11.011 61.218 11.129 ;
     RECT  76.932 10.795 80.838 11.165 ;
     RECT  31.464 10.939 40.914 11.245 ;
     RECT  41.796 11.011 42.714 11.245 ;
     RECT  31.464 11.245 41.022 11.281 ;
     RECT  41.76 11.245 42.714 11.281 ;
     RECT  45.648 10.201 45.666 11.281 ;
     RECT  45.648 11.281 45.774 11.399 ;
     RECT  57.888 10.975 57.906 11.399 ;
     RECT  74.628 10.967 74.646 11.435 ;
     RECT  77.22 11.165 80.838 11.507 ;
     RECT  45.648 11.399 45.666 11.515 ;
     RECT  46.584 10.733 47.07 11.551 ;
     RECT  45.612 11.515 45.666 11.552 ;
     RECT  50.256 11.551 50.274 11.641 ;
     RECT  51.624 8.131 51.642 11.641 ;
     RECT  50.112 11.641 50.274 11.669 ;
     RECT  50.112 11.669 50.13 11.693 ;
     RECT  31.464 11.281 42.714 11.705 ;
     RECT  74.736 11.551 74.754 11.705 ;
     RECT  78.624 11.507 80.838 11.705 ;
     RECT  41.652 11.705 42.714 11.785 ;
     RECT  43.455 10.589 43.737 11.785 ;
     RECT  58.716 11.039 58.734 11.821 ;
     RECT  58.716 11.821 58.806 11.849 ;
     RECT  58.788 11.849 58.806 11.939 ;
     RECT  59.655 11.129 61.146 11.939 ;
     RECT  41.652 11.785 43.737 11.975 ;
     RECT  54.255 8.465 54.537 12.091 ;
     RECT  72.684 8.537 72.702 12.187 ;
     RECT  68.652 8.069 71.334 12.235 ;
     RECT  72.072 12.187 72.702 12.235 ;
     RECT  78.66 11.705 80.838 12.245 ;
     RECT  53.964 12.091 54.537 12.253 ;
     RECT  67.284 10.831 67.554 12.283 ;
     RECT  53.964 12.253 54.882 12.325 ;
     RECT  66.924 12.283 67.554 12.361 ;
     RECT  31.464 11.705 40.878 12.451 ;
     RECT  41.652 11.975 42.714 12.451 ;
     RECT  68.652 12.235 72.702 12.515 ;
     RECT  72.18 12.515 72.702 12.557 ;
     RECT  74.088 12.235 74.106 12.587 ;
     RECT  31.464 12.451 42.714 12.721 ;
     RECT  43.455 11.975 43.737 12.721 ;
     RECT  62.424 10.121 64.242 12.721 ;
     RECT  58.716 12.595 58.734 12.757 ;
     RECT  59.655 11.939 60.786 12.757 ;
     RECT  78.66 12.245 80.766 12.785 ;
     RECT  66.6 12.361 67.554 12.793 ;
     RECT  61.74 12.721 64.242 12.857 ;
     RECT  51.048 11.641 51.642 12.865 ;
     RECT  58.572 12.757 60.786 12.865 ;
     RECT  46.548 11.551 47.07 12.901 ;
     RECT  53.712 12.325 54.882 12.929 ;
     RECT  51.048 12.865 51.678 12.991 ;
     RECT  66.384 12.793 67.554 13.019 ;
     RECT  52.704 8.401 52.722 13.027 ;
     RECT  66.996 13.019 67.554 13.091 ;
     RECT  44.748 10.253 44.766 13.099 ;
     RECT  45.648 11.552 45.666 13.099 ;
     RECT  67.356 13.091 67.554 13.127 ;
     RECT  65.055 10.859 65.337 13.135 ;
     RECT  68.652 12.515 71.334 13.163 ;
     RECT  58.536 12.865 60.786 13.171 ;
     RECT  58.5 13.171 60.786 13.199 ;
     RECT  47.916 13.171 48.006 13.289 ;
     RECT  65.055 13.135 65.394 13.289 ;
     RECT  44.748 13.099 45.666 13.405 ;
     RECT  47.916 13.289 47.934 13.469 ;
     RECT  59.655 13.199 60.786 13.531 ;
     RECT  78.66 12.785 80.694 13.867 ;
     RECT  50.256 13.801 50.274 13.909 ;
     RECT  72.684 12.557 72.702 13.909 ;
     RECT  44.46 13.405 45.666 13.945 ;
     RECT  46.548 12.901 47.142 13.945 ;
     RECT  48.855 0.793 49.137 13.945 ;
     RECT  56.448 12.559 56.466 13.973 ;
     RECT  44.46 13.945 47.142 13.981 ;
     RECT  44.46 13.981 47.178 14.071 ;
     RECT  74.232 13.981 74.25 14.071 ;
     RECT  50.184 13.909 50.274 14.099 ;
     RECT  72.144 13.909 72.702 14.099 ;
     RECT  59.655 13.531 61.002 14.143 ;
     RECT  61.812 12.857 64.242 14.143 ;
     RECT  74.232 14.071 74.682 14.143 ;
     RECT  44.46 14.071 47.25 14.171 ;
     RECT  58.5 13.199 58.554 14.179 ;
     RECT  51.048 12.991 51.786 14.251 ;
     RECT  52.704 13.027 52.902 14.251 ;
     RECT  74.16 14.143 74.682 14.279 ;
     RECT  68.652 13.163 71.154 14.341 ;
     RECT  78.66 13.867 80.838 14.449 ;
     RECT  50.724 14.251 52.902 14.477 ;
     RECT  53.712 12.929 54.774 14.485 ;
     RECT  58.5 14.179 58.734 14.485 ;
     RECT  48.855 13.945 49.41 14.521 ;
     RECT  50.76 14.477 52.902 14.521 ;
     RECT  53.712 14.485 54.846 14.521 ;
     RECT  75.492 10.049 76.137 14.539 ;
     RECT  77.22 11.507 77.814 14.539 ;
     RECT  78.66 14.449 80.946 14.549 ;
     RECT  58.5 14.485 58.806 14.639 ;
     RECT  50.76 14.521 54.846 14.675 ;
     RECT  50.796 14.675 54.846 14.747 ;
     RECT  50.796 14.747 54.774 14.783 ;
     RECT  68.652 14.341 71.334 14.783 ;
     RECT  52.704 14.783 54.774 14.813 ;
     RECT  50.868 14.783 51.822 14.819 ;
     RECT  51.048 14.819 51.822 14.861 ;
     RECT  67.356 13.127 67.374 14.881 ;
     RECT  31.464 12.721 43.737 14.989 ;
     RECT  44.46 14.171 47.106 14.989 ;
     RECT  75.492 14.539 77.814 15.061 ;
     RECT  78.66 14.549 80.694 15.061 ;
     RECT  74.664 14.279 74.682 15.179 ;
     RECT  67.356 14.881 67.878 15.287 ;
     RECT  59.655 14.143 64.242 15.331 ;
     RECT  67.356 15.287 67.374 15.331 ;
     RECT  66.996 15.331 67.374 15.421 ;
     RECT  30.708 1.993 30.726 15.529 ;
     RECT  31.464 14.989 47.106 15.529 ;
     RECT  66.708 15.421 67.374 15.557 ;
     RECT  75.492 15.061 80.694 15.595 ;
     RECT  48.855 14.521 49.59 15.719 ;
     RECT  68.652 14.783 70.974 15.763 ;
     RECT  55.692 12.901 55.71 15.871 ;
     RECT  59.655 15.331 64.314 15.871 ;
     RECT  51.048 14.861 51.642 16.069 ;
     RECT  58.5 14.639 58.734 16.141 ;
     RECT  59.508 15.871 64.314 16.141 ;
     RECT  75.492 15.595 80.838 16.267 ;
     RECT  75.204 16.267 80.838 16.295 ;
     RECT  58.5 16.141 64.314 16.331 ;
     RECT  68.4 15.763 70.974 16.331 ;
     RECT  30.708 15.529 47.106 16.339 ;
     RECT  77.22 16.295 80.838 16.411 ;
     RECT  68.472 16.331 70.974 16.439 ;
     RECT  71.712 16.339 71.73 16.439 ;
     RECT  58.5 16.331 58.734 16.529 ;
     RECT  59.508 16.331 64.314 16.529 ;
     RECT  30.708 16.339 47.754 16.537 ;
     RECT  50.724 16.069 51.642 16.537 ;
     RECT  66.996 15.557 67.374 16.537 ;
     RECT  72.684 14.099 72.702 16.537 ;
     RECT  50.724 16.537 51.894 16.609 ;
     RECT  52.704 14.813 53.406 16.609 ;
     RECT  72.684 16.537 72.774 16.609 ;
     RECT  75.204 16.295 76.266 16.673 ;
     RECT  66.564 16.537 67.374 16.681 ;
     RECT  72.612 16.609 72.774 16.681 ;
     RECT  72.396 16.681 72.774 16.709 ;
     RECT  77.22 16.411 80.946 16.747 ;
     RECT  66.564 16.681 67.482 16.771 ;
     RECT  30.708 16.537 47.826 16.799 ;
     RECT  50.724 16.609 53.406 16.799 ;
     RECT  59.508 16.529 61.614 16.799 ;
     RECT  30.708 16.799 47.79 16.835 ;
     RECT  62.424 16.529 64.314 16.879 ;
     RECT  65.055 13.289 65.337 16.879 ;
     RECT  72.396 16.709 72.702 16.907 ;
     RECT  58.5 16.529 58.554 16.915 ;
     RECT  75.492 16.673 76.266 17.041 ;
     RECT  77.22 16.747 80.982 17.041 ;
     RECT  72.396 16.907 72.414 17.069 ;
     RECT  55.692 15.871 56.322 17.113 ;
     RECT  59.655 16.799 61.614 17.141 ;
     RECT  48.855 15.719 49.137 17.149 ;
     RECT  66.564 16.771 67.554 17.249 ;
     RECT  48.855 17.149 49.338 17.311 ;
     RECT  55.692 17.113 56.358 17.311 ;
     RECT  57.816 16.915 58.554 17.375 ;
     RECT  55.692 17.311 56.646 17.419 ;
     RECT  66.708 17.249 67.554 17.419 ;
     RECT  68.652 16.439 70.974 17.419 ;
     RECT  48.855 17.311 49.806 17.581 ;
     RECT  55.692 17.419 56.898 17.581 ;
     RECT  48.855 17.581 49.878 17.689 ;
     RECT  54.255 14.813 54.774 17.689 ;
     RECT  51.048 16.799 53.406 17.725 ;
     RECT  58.5 17.375 58.554 17.725 ;
     RECT  58.5 17.725 58.842 17.755 ;
     RECT  59.655 17.141 59.937 17.755 ;
     RECT  30.708 16.835 47.106 17.761 ;
     RECT  60.696 17.141 61.614 17.761 ;
     RECT  62.424 16.879 65.337 17.761 ;
     RECT  48.855 17.689 49.914 17.851 ;
     RECT  55.692 17.581 57.726 17.879 ;
     RECT  60.696 17.761 61.65 17.887 ;
     RECT  62.424 17.761 65.394 17.887 ;
     RECT  60.696 17.887 65.394 17.947 ;
     RECT  48.855 17.851 49.986 17.951 ;
     RECT  30.708 17.761 47.61 17.959 ;
     RECT  49.86 17.951 49.986 17.959 ;
     RECT  50.796 17.725 53.406 17.959 ;
     RECT  60.66 17.947 65.394 17.987 ;
     RECT  60.696 17.987 65.337 18.059 ;
     RECT  60.768 18.059 65.337 18.149 ;
     RECT  54.255 17.689 54.81 18.185 ;
     RECT  30.708 17.959 47.682 18.194 ;
     RECT  58.5 17.755 59.937 18.221 ;
     RECT  75.492 17.041 80.982 18.221 ;
     RECT  75.492 18.221 76.266 18.229 ;
     RECT  66.708 17.419 70.974 18.265 ;
     RECT  30.708 18.194 47.646 18.293 ;
     RECT  74.808 18.229 76.266 18.301 ;
     RECT  49.86 17.959 53.406 18.329 ;
     RECT  74.736 18.301 76.266 18.329 ;
     RECT  74.736 18.329 74.754 18.379 ;
     RECT  66.708 18.265 71.226 18.427 ;
     RECT  74.592 18.379 74.754 18.427 ;
     RECT  72 18.229 72.018 18.455 ;
     RECT  74.052 18.427 74.754 18.464 ;
     RECT  66.6 18.427 71.226 18.527 ;
     RECT  66.708 18.527 71.226 18.571 ;
     RECT  74.196 18.464 74.754 18.605 ;
     RECT  49.86 18.329 51.714 18.689 ;
     RECT  48.855 17.951 49.137 18.805 ;
     RECT  77.292 18.221 80.982 18.805 ;
     RECT  59.544 18.221 59.937 18.859 ;
     RECT  60.768 18.149 61.614 18.859 ;
     RECT  52.704 18.329 53.406 19.075 ;
     RECT  55.692 17.879 57.33 19.111 ;
     RECT  58.5 18.221 58.734 19.111 ;
     RECT  59.544 18.859 61.614 19.111 ;
     RECT  62.388 18.149 64.314 19.111 ;
     RECT  74.664 18.605 74.682 19.139 ;
     RECT  54.255 18.185 54.774 19.201 ;
     RECT  55.692 19.111 58.734 19.201 ;
     RECT  54.255 19.201 58.734 19.229 ;
     RECT  48.78 18.805 49.137 19.265 ;
     RECT  59.544 19.111 64.314 19.325 ;
     RECT  50.436 18.689 51.714 19.339 ;
     RECT  52.452 19.075 53.406 19.339 ;
     RECT  62.352 19.325 64.314 19.345 ;
     RECT  65.055 18.149 65.337 19.345 ;
     RECT  75.492 18.329 76.266 19.345 ;
     RECT  77.292 18.805 81.126 19.345 ;
     RECT  50.436 19.339 53.406 19.379 ;
     RECT  54.255 19.229 57.762 19.379 ;
     RECT  58.5 19.229 58.734 19.381 ;
     RECT  66.708 18.571 71.334 19.381 ;
     RECT  66.708 19.381 71.55 19.471 ;
     RECT  72.612 19.435 72.63 19.471 ;
     RECT  66.708 19.471 71.73 19.499 ;
     RECT  72.612 19.471 72.738 19.517 ;
     RECT  72.612 19.517 72.63 19.535 ;
     RECT  66.708 19.499 70.974 19.543 ;
     RECT  58.5 19.381 58.806 19.571 ;
     RECT  71.712 19.499 71.73 19.615 ;
     RECT  66.132 19.543 70.974 19.643 ;
     RECT  75.492 19.345 81.126 19.643 ;
     RECT  58.5 19.571 58.734 19.769 ;
     RECT  66.132 19.643 69.21 19.805 ;
     RECT  71.712 19.615 72.414 19.805 ;
     RECT  30.708 18.293 47.394 19.813 ;
     RECT  66.24 19.805 68.706 19.913 ;
     RECT  71.712 19.805 71.73 19.949 ;
     RECT  62.352 19.345 65.337 20.111 ;
     RECT  54.255 19.379 57.33 20.119 ;
     RECT  50.436 19.379 51.75 20.191 ;
     RECT  48.855 19.265 49.137 20.299 ;
     RECT  30.42 19.813 47.394 20.353 ;
     RECT  77.148 19.643 81.126 20.381 ;
     RECT  48.852 20.299 49.137 20.389 ;
     RECT  49.86 20.191 51.75 20.389 ;
     RECT  52.704 19.379 53.406 20.425 ;
     RECT  54.144 20.119 57.33 20.425 ;
     RECT  48.852 20.389 51.75 20.489 ;
     RECT  77.256 20.381 81.126 20.525 ;
     RECT  50.436 20.489 51.75 20.587 ;
     RECT  73.26 20.551 73.278 20.587 ;
     RECT  73.152 20.587 73.278 20.624 ;
     RECT  30.42 20.353 48.006 20.659 ;
     RECT  48.852 20.489 49.59 20.659 ;
     RECT  70.02 19.643 70.974 20.821 ;
     RECT  74.556 20.821 74.574 20.893 ;
     RECT  30.42 20.659 49.59 20.921 ;
     RECT  70.02 20.821 71.118 20.993 ;
     RECT  74.556 20.893 74.646 20.993 ;
     RECT  66.708 19.913 68.706 21.091 ;
     RECT  70.02 20.993 70.974 21.091 ;
     RECT  58.5 19.769 58.518 21.115 ;
     RECT  58.356 21.115 58.518 21.119 ;
     RECT  52.704 20.425 57.33 21.155 ;
     RECT  58.356 21.119 58.374 21.155 ;
     RECT  66.708 21.091 70.974 21.163 ;
     RECT  66.096 21.163 70.974 21.191 ;
     RECT  73.26 20.624 73.278 21.235 ;
     RECT  48.78 20.921 49.59 21.271 ;
     RECT  50.436 20.587 51.786 21.271 ;
     RECT  59.544 19.325 61.614 21.271 ;
     RECT  66.096 21.191 68.706 21.271 ;
     RECT  62.352 20.111 64.314 21.361 ;
     RECT  65.055 20.111 65.337 21.361 ;
     RECT  59.292 21.271 61.614 21.533 ;
     RECT  73.26 21.235 74.106 21.541 ;
     RECT  54.255 21.155 57.33 21.569 ;
     RECT  73.224 21.541 74.106 21.569 ;
     RECT  62.352 21.361 65.337 21.631 ;
     RECT  66.06 21.271 68.706 21.631 ;
     RECT  62.352 21.631 68.706 21.659 ;
     RECT  48.78 21.271 51.786 21.803 ;
     RECT  73.224 21.569 73.422 21.839 ;
     RECT  68.004 21.659 68.706 21.929 ;
     RECT  30.42 20.921 47.97 22.081 ;
     RECT  48.78 21.803 49.626 22.081 ;
     RECT  58.788 22.009 58.806 22.081 ;
     RECT  75.492 19.643 76.266 22.081 ;
     RECT  77.292 20.525 81.126 22.081 ;
     RECT  58.716 22.081 58.806 22.109 ;
     RECT  74.664 22.081 74.682 22.199 ;
     RECT  62.352 21.659 65.826 22.235 ;
     RECT  50.436 21.803 51.786 22.315 ;
     RECT  52.704 21.155 53.442 22.315 ;
     RECT  54.255 21.569 54.63 22.505 ;
     RECT  55.584 21.569 57.33 22.505 ;
     RECT  59.544 21.533 61.614 22.549 ;
     RECT  62.352 22.235 63.558 22.549 ;
     RECT  30.42 22.081 49.626 22.621 ;
     RECT  59.544 22.549 63.558 22.649 ;
     RECT  30.42 22.621 49.662 22.739 ;
     RECT  59.616 22.649 63.558 22.739 ;
     RECT  75.492 22.081 81.126 22.739 ;
     RECT  50.436 22.315 53.442 22.747 ;
     RECT  54.255 22.505 54.537 22.747 ;
     RECT  75.855 22.739 81.126 22.783 ;
     RECT  56.412 22.505 57.33 22.811 ;
     RECT  30.42 22.739 49.59 22.883 ;
     RECT  56.628 22.811 57.33 22.891 ;
     RECT  64.296 22.235 65.826 22.919 ;
     RECT  59.616 22.739 63.378 23.081 ;
     RECT  56.628 22.891 57.654 23.161 ;
     RECT  74.664 23.089 74.682 23.161 ;
     RECT  58.716 22.109 58.734 23.189 ;
     RECT  68.004 21.929 68.67 23.189 ;
     RECT  50.436 22.747 54.537 23.287 ;
     RECT  66.996 21.659 67.158 23.359 ;
     RECT  68.004 23.189 68.13 23.359 ;
     RECT  58.788 23.359 58.806 23.459 ;
     RECT  59.616 23.081 59.937 23.521 ;
     RECT  70.02 21.191 70.974 23.557 ;
     RECT  74.664 23.161 74.754 23.557 ;
     RECT  60.768 23.081 63.378 23.563 ;
     RECT  64.296 22.919 64.314 23.563 ;
     RECT  59.22 23.521 59.937 23.597 ;
     RECT  48.855 22.883 49.59 23.665 ;
     RECT  59.616 23.597 59.937 23.693 ;
     RECT  66.996 23.359 68.13 23.755 ;
     RECT  66.96 23.755 68.13 23.791 ;
     RECT  73.404 21.839 73.422 23.827 ;
     RECT  74.16 23.557 74.754 23.827 ;
     RECT  60.768 23.563 64.314 23.855 ;
     RECT  48.855 23.665 49.662 23.885 ;
     RECT  69.516 23.557 70.974 23.899 ;
     RECT  69.228 23.899 70.974 23.935 ;
     RECT  50.4 23.287 54.537 23.947 ;
     RECT  66.744 23.791 68.13 23.971 ;
     RECT  73.404 23.827 74.754 23.999 ;
     RECT  69.228 23.935 71.262 24.061 ;
     RECT  75.855 22.783 81.162 24.125 ;
     RECT  74.196 23.999 74.754 24.133 ;
     RECT  74.196 24.133 74.826 24.161 ;
     RECT  69.228 24.061 71.55 24.233 ;
     RECT  75.855 24.125 76.662 24.233 ;
     RECT  50.4 23.947 54.702 24.241 ;
     RECT  65.055 22.919 65.826 24.241 ;
     RECT  66.708 23.971 68.13 24.241 ;
     RECT  77.544 24.125 81.162 24.269 ;
     RECT  50.328 24.241 54.846 24.317 ;
     RECT  65.055 24.241 68.13 24.395 ;
     RECT  69.228 24.233 71.01 24.395 ;
     RECT  55.584 22.505 55.602 24.403 ;
     RECT  50.436 24.317 54.846 24.431 ;
     RECT  70.455 24.395 71.01 24.431 ;
     RECT  74.664 24.161 74.826 24.439 ;
     RECT  75.855 24.233 76.446 24.439 ;
     RECT  48.855 23.885 49.338 24.745 ;
     RECT  55.584 24.403 55.854 24.745 ;
     RECT  56.628 23.161 57.726 24.745 ;
     RECT  64.152 23.855 64.314 24.773 ;
     RECT  48.816 24.745 49.338 24.781 ;
     RECT  71.748 24.331 71.766 24.781 ;
     RECT  73.404 23.999 73.422 24.859 ;
     RECT  55.584 24.745 57.726 24.899 ;
     RECT  74.664 24.439 76.446 24.971 ;
     RECT  54.255 24.431 54.846 25.003 ;
     RECT  55.584 24.899 55.854 25.003 ;
     RECT  71.748 24.781 72.198 25.051 ;
     RECT  73.26 24.859 73.422 25.051 ;
     RECT  54.255 25.003 55.854 25.079 ;
     RECT  56.628 24.899 57.726 25.141 ;
     RECT  58.716 24.781 58.734 25.141 ;
     RECT  56.628 25.141 58.914 25.147 ;
     RECT  59.655 23.693 59.937 25.147 ;
     RECT  56.628 25.147 59.937 25.177 ;
     RECT  60.768 23.855 63.378 25.177 ;
     RECT  56.628 25.177 63.378 25.277 ;
     RECT  58.788 25.277 63.378 25.313 ;
     RECT  74.7 24.971 76.446 25.321 ;
     RECT  77.796 24.269 81.162 25.321 ;
     RECT  73.26 25.051 73.782 25.435 ;
     RECT  58.788 25.313 58.806 25.439 ;
     RECT  30.42 22.883 48.006 25.447 ;
     RECT  48.816 24.781 49.59 25.447 ;
     RECT  30.42 25.447 49.59 25.483 ;
     RECT  71.748 25.051 72.306 25.519 ;
     RECT  73.152 25.435 73.782 25.519 ;
     RECT  59.544 25.313 63.378 25.583 ;
     RECT  64.296 24.773 64.314 25.591 ;
     RECT  71.748 25.519 73.782 25.619 ;
     RECT  72.288 25.619 73.782 25.661 ;
     RECT  65.055 24.395 66.15 25.681 ;
     RECT  66.996 24.395 68.13 25.681 ;
     RECT  70.455 24.431 70.974 25.709 ;
     RECT  55.836 25.079 55.854 25.825 ;
     RECT  56.628 25.277 57.762 25.825 ;
     RECT  30.42 25.483 49.662 25.861 ;
     RECT  50.436 24.431 53.442 25.861 ;
     RECT  59.655 25.583 63.378 25.861 ;
     RECT  64.188 25.591 64.314 25.861 ;
     RECT  74.7 25.321 81.162 25.861 ;
     RECT  73.26 25.661 73.782 25.889 ;
     RECT  55.44 25.825 57.762 25.979 ;
     RECT  59.655 25.861 64.314 25.987 ;
     RECT  65.055 25.681 68.13 25.987 ;
     RECT  30.42 25.861 53.442 26.015 ;
     RECT  74.664 25.861 81.162 26.051 ;
     RECT  59.655 25.987 68.13 26.141 ;
     RECT  59.655 26.141 66.474 26.159 ;
     RECT  75.204 26.051 81.162 26.237 ;
     RECT  59.655 26.159 63.846 26.249 ;
     RECT  73.26 25.889 73.314 26.249 ;
     RECT  69.228 24.395 69.39 26.251 ;
     RECT  62.244 26.249 63.846 26.321 ;
     RECT  54.255 25.079 54.537 26.365 ;
     RECT  55.44 25.979 55.854 26.365 ;
     RECT  73.296 26.249 73.314 26.519 ;
     RECT  72.288 25.661 72.414 26.527 ;
     RECT  59.655 26.249 61.362 26.663 ;
     RECT  70.455 25.709 70.737 26.671 ;
     RECT  56.628 25.979 57.762 26.731 ;
     RECT  58.572 26.635 58.59 26.731 ;
     RECT  59.655 26.663 59.994 26.761 ;
     RECT  70.455 26.671 71.01 26.761 ;
     RECT  73.404 26.671 73.422 26.761 ;
     RECT  30.42 26.015 49.482 26.789 ;
     RECT  56.628 26.731 58.59 26.789 ;
     RECT  69.156 26.251 69.39 26.797 ;
     RECT  75.204 26.237 76.194 26.797 ;
     RECT  50.328 26.015 53.442 26.861 ;
     RECT  68.976 26.797 69.39 26.861 ;
     RECT  73.404 26.761 73.566 26.861 ;
     RECT  67.536 26.141 68.13 26.869 ;
     RECT  50.724 26.861 53.442 26.923 ;
     RECT  50.724 26.923 53.478 27.059 ;
     RECT  69.048 26.861 69.39 27.095 ;
     RECT  74.664 26.797 76.194 27.095 ;
     RECT  74.664 27.095 74.754 27.131 ;
     RECT  59.364 26.761 59.994 27.139 ;
     RECT  60.768 26.663 61.362 27.167 ;
     RECT  67.356 26.869 68.13 27.175 ;
     RECT  67.212 27.175 68.13 27.211 ;
     RECT  50.724 27.059 53.442 27.239 ;
     RECT  58.788 27.139 59.994 27.239 ;
     RECT  64.62 26.159 66.474 27.301 ;
     RECT  67.212 27.211 68.166 27.301 ;
     RECT  64.62 27.301 68.166 27.329 ;
     RECT  74.736 27.131 74.754 27.329 ;
     RECT  75.855 27.095 76.194 27.365 ;
     RECT  62.244 26.321 63.378 27.373 ;
     RECT  73.548 26.861 73.566 27.373 ;
     RECT  50.76 27.239 53.442 27.473 ;
     RECT  70.455 26.761 71.082 27.571 ;
     RECT  64.62 27.329 68.13 27.607 ;
     RECT  30.42 26.789 49.137 27.643 ;
     RECT  54.255 26.365 55.854 27.643 ;
     RECT  56.628 26.789 57.726 27.643 ;
     RECT  72.288 26.527 72.486 27.643 ;
     RECT  58.788 27.239 59.937 27.671 ;
     RECT  70.455 27.571 71.118 27.677 ;
     RECT  62.136 27.373 63.378 27.715 ;
     RECT  64.296 27.607 68.13 27.715 ;
     RECT  62.136 27.715 68.13 27.743 ;
     RECT  70.455 27.677 71.082 27.743 ;
     RECT  72.288 27.643 72.522 27.743 ;
     RECT  30.42 27.643 49.338 27.869 ;
     RECT  62.136 27.743 66.726 27.869 ;
     RECT  72.288 27.743 72.486 27.869 ;
     RECT  73.548 27.373 73.638 27.869 ;
     RECT  58.716 27.841 58.734 27.941 ;
     RECT  66.708 27.869 66.726 28.049 ;
     RECT  49.86 28.021 49.878 28.139 ;
     RECT  51.048 27.473 53.442 28.219 ;
     RECT  75.855 27.365 76.137 28.219 ;
     RECT  77.076 26.237 81.162 28.219 ;
     RECT  59.655 27.671 59.937 28.255 ;
     RECT  50.724 28.219 53.442 28.291 ;
     RECT  62.136 27.869 65.826 28.319 ;
     RECT  54.255 27.643 57.726 28.381 ;
     RECT  50.616 28.291 53.442 28.411 ;
     RECT  50.472 28.411 53.442 28.451 ;
     RECT  50.724 28.451 53.442 28.525 ;
     RECT  54.216 28.381 57.726 28.525 ;
     RECT  59.655 28.255 59.994 28.589 ;
     RECT  62.136 28.319 62.406 28.751 ;
     RECT  50.724 28.525 57.726 28.787 ;
     RECT  58.68 28.723 58.698 28.831 ;
     RECT  75.855 28.219 81.162 28.831 ;
     RECT  63.252 28.319 63.846 28.859 ;
     RECT  58.68 28.831 58.77 29.021 ;
     RECT  58.68 29.021 58.698 29.057 ;
     RECT  67.536 27.743 68.13 29.083 ;
     RECT  69.228 27.095 69.39 29.083 ;
     RECT  61.344 27.167 61.362 29.129 ;
     RECT  65.055 28.319 65.826 29.335 ;
     RECT  64.872 29.335 65.826 29.371 ;
     RECT  64.872 29.371 65.862 29.405 ;
     RECT  54.255 28.787 57.726 29.597 ;
     RECT  50.724 28.787 53.442 29.641 ;
     RECT  75.816 28.831 81.162 29.669 ;
     RECT  66.708 29.641 66.726 29.795 ;
     RECT  67.536 29.083 69.39 29.795 ;
     RECT  62.244 28.751 62.406 29.851 ;
     RECT  62.028 29.851 62.406 29.911 ;
     RECT  63.252 28.859 63.378 29.911 ;
     RECT  50.328 29.641 53.442 30.065 ;
     RECT  30.42 27.869 49.137 30.181 ;
     RECT  30.42 30.181 49.806 30.221 ;
     RECT  70.455 27.743 70.737 30.235 ;
     RECT  65.055 29.405 65.862 30.451 ;
     RECT  67.536 29.795 68.13 30.541 ;
     RECT  55.44 29.597 57.726 30.605 ;
     RECT  67.428 30.541 68.13 30.605 ;
     RECT  70.164 30.235 70.737 30.605 ;
     RECT  55.44 30.605 55.854 30.667 ;
     RECT  64.512 30.451 65.862 30.721 ;
     RECT  55.296 30.667 55.854 30.749 ;
     RECT  59.655 28.589 59.937 30.811 ;
     RECT  62.028 29.911 63.378 30.947 ;
     RECT  56.628 30.605 57.726 30.991 ;
     RECT  58.716 30.811 58.734 30.991 ;
     RECT  62.028 30.947 62.406 31.019 ;
     RECT  51.048 30.065 53.442 31.099 ;
     RECT  75.855 29.669 81.162 31.145 ;
     RECT  64.224 30.721 65.862 31.243 ;
     RECT  50.616 31.099 53.442 31.261 ;
     RECT  61.092 30.805 61.11 31.325 ;
     RECT  50.436 31.261 53.442 31.351 ;
     RECT  63.252 30.947 63.378 31.351 ;
     RECT  64.224 31.243 66.186 31.351 ;
     RECT  63.252 31.351 66.186 31.379 ;
     RECT  59.544 30.811 59.937 31.387 ;
     RECT  54.255 29.597 54.537 31.423 ;
     RECT  55.296 30.749 55.782 31.423 ;
     RECT  63.252 31.379 65.826 31.451 ;
     RECT  63.252 31.451 63.738 31.469 ;
     RECT  56.628 30.991 58.734 31.483 ;
     RECT  59.544 31.387 60.462 31.483 ;
     RECT  56.628 31.483 60.462 31.523 ;
     RECT  59.58 31.523 60.462 31.559 ;
     RECT  64.512 31.451 65.826 31.559 ;
     RECT  59.58 31.559 60.39 31.649 ;
     RECT  59.58 31.649 59.937 31.721 ;
     RECT  75.855 31.145 81.09 31.757 ;
     RECT  54.255 31.423 55.782 31.793 ;
     RECT  62.244 31.019 62.406 31.793 ;
     RECT  50.22 31.351 53.442 31.801 ;
     RECT  50.076 31.801 53.442 31.919 ;
     RECT  50.22 31.919 53.442 31.955 ;
     RECT  55.296 31.793 55.782 32.225 ;
     RECT  72.288 27.869 72.306 32.296 ;
     RECT  73.116 31.621 73.134 32.296 ;
     RECT  56.628 31.523 58.734 32.369 ;
     RECT  50.4 31.955 53.442 32.881 ;
     RECT  54.255 31.793 54.537 32.881 ;
     RECT  72.288 32.296 73.134 32.881 ;
     RECT  74.484 32.809 74.502 32.881 ;
     RECT  74.412 32.881 74.502 32.909 ;
     RECT  74.412 32.909 74.43 32.999 ;
     RECT  50.4 32.881 54.537 33.151 ;
     RECT  55.44 32.225 55.782 33.151 ;
     RECT  56.628 32.369 58.446 33.305 ;
     RECT  72.288 32.881 73.242 33.341 ;
     RECT  56.628 33.305 58.23 33.377 ;
     RECT  50.4 33.151 55.782 33.421 ;
     RECT  56.628 33.377 57.726 33.421 ;
     RECT  50.076 33.421 55.782 33.485 ;
     RECT  50.076 33.485 50.598 33.581 ;
     RECT  51.624 33.485 55.782 33.611 ;
     RECT  55.44 33.611 55.782 33.787 ;
     RECT  56.556 33.421 57.726 33.787 ;
     RECT  30.42 30.221 49.137 33.961 ;
     RECT  30.42 33.961 49.194 34.051 ;
     RECT  50.076 33.581 50.418 34.051 ;
     RECT  30.42 34.051 50.418 34.151 ;
     RECT  51.624 33.611 54.537 34.205 ;
     RECT  75.855 31.757 76.137 34.267 ;
     RECT  77.076 31.757 81.09 34.267 ;
     RECT  75.855 34.267 81.09 34.397 ;
     RECT  74.484 34.456 74.502 34.493 ;
     RECT  73.224 33.341 73.242 34.591 ;
     RECT  55.44 33.787 57.726 34.771 ;
     RECT  55.44 34.771 57.798 34.889 ;
     RECT  54.255 34.205 54.537 35.041 ;
     RECT  55.44 34.889 55.818 35.041 ;
     RECT  67.536 30.605 68.13 35.041 ;
     RECT  69.228 29.795 69.39 35.041 ;
     RECT  66.708 35.041 66.726 35.159 ;
     RECT  67.536 35.041 69.39 35.159 ;
     RECT  54.255 35.041 55.818 35.231 ;
     RECT  59.655 31.721 59.937 35.401 ;
     RECT  62.244 31.793 62.262 35.401 ;
     RECT  63.252 31.469 63.378 35.401 ;
     RECT  74.664 34.501 74.682 35.429 ;
     RECT  59.655 35.401 60.066 35.509 ;
     RECT  70.455 30.605 70.737 35.509 ;
     RECT  59.655 35.509 60.786 35.515 ;
     RECT  77.076 34.397 81.09 35.537 ;
     RECT  59.112 35.515 60.786 35.545 ;
     RECT  62.244 35.401 63.378 35.545 ;
     RECT  72.288 33.341 72.306 35.545 ;
     RECT  73.224 34.591 73.566 35.545 ;
     RECT  58.716 35.545 60.786 35.549 ;
     RECT  54.255 35.231 54.702 35.581 ;
     RECT  70.455 35.509 70.758 35.699 ;
     RECT  58.716 35.549 60.534 35.735 ;
     RECT  54.18 35.581 54.702 35.843 ;
     RECT  72.288 35.545 73.566 35.843 ;
     RECT  55.44 35.231 55.818 35.851 ;
     RECT  56.628 34.889 57.798 35.851 ;
     RECT  72.288 35.843 73.242 35.885 ;
     RECT  51.624 34.205 53.442 36.085 ;
     RECT  54.18 35.843 54.537 36.085 ;
     RECT  50.4 34.151 50.418 36.121 ;
     RECT  67.536 35.159 68.13 36.121 ;
     RECT  51.624 36.085 54.537 36.125 ;
     RECT  58.716 35.735 58.734 36.149 ;
     RECT  61.524 35.545 63.378 36.149 ;
     RECT  77.076 35.537 77.382 36.235 ;
     RECT  67.536 36.121 68.346 36.239 ;
     RECT  77.04 36.235 77.382 36.239 ;
     RECT  62.244 36.149 63.378 36.275 ;
     RECT  77.04 36.239 77.094 36.275 ;
     RECT  67.644 36.239 67.842 36.311 ;
     RECT  78.372 35.537 81.09 36.391 ;
     RECT  50.4 36.121 50.706 36.481 ;
     RECT  59.655 35.735 60.534 36.481 ;
     RECT  55.44 35.851 57.978 36.545 ;
     RECT  59.655 36.481 60.642 36.557 ;
     RECT  59.655 36.557 60.462 36.571 ;
     RECT  50.4 36.481 50.814 36.661 ;
     RECT  55.44 36.545 57.798 36.779 ;
     RECT  77.976 36.391 81.09 36.815 ;
     RECT  30.42 34.151 49.482 36.931 ;
     RECT  50.4 36.661 50.886 36.931 ;
     RECT  75.855 34.397 76.137 36.931 ;
     RECT  77.976 36.815 79.326 36.959 ;
     RECT  70.455 35.699 70.737 37.003 ;
     RECT  72.288 35.885 72.306 37.003 ;
     RECT  71.928 37.003 72.306 37.049 ;
     RECT  75.456 36.931 76.137 37.049 ;
     RECT  59.22 36.571 60.462 37.165 ;
     RECT  58.716 37.165 60.462 37.193 ;
     RECT  54.255 36.125 54.537 37.201 ;
     RECT  55.44 36.779 55.782 37.201 ;
     RECT  72.144 37.049 72.306 37.243 ;
     RECT  72.144 37.243 72.486 37.319 ;
     RECT  70.455 37.003 71.19 37.399 ;
     RECT  67.824 36.311 67.842 37.435 ;
     RECT  74.592 37.399 74.61 37.499 ;
     RECT  67.824 37.435 67.986 37.561 ;
     RECT  77.076 36.275 77.094 37.561 ;
     RECT  70.455 37.399 71.37 37.589 ;
     RECT  72.144 37.319 72.162 37.589 ;
     RECT  67.824 37.561 68.31 37.613 ;
     RECT  78.372 36.959 79.326 37.831 ;
     RECT  80.064 36.815 81.09 37.831 ;
     RECT  75.564 37.049 76.137 37.895 ;
     RECT  56.628 36.779 57.798 37.939 ;
     RECT  68.292 37.613 68.31 38.003 ;
     RECT  56.628 37.939 57.906 38.011 ;
     RECT  58.716 37.193 59.937 38.011 ;
     RECT  56.628 38.011 59.937 38.129 ;
     RECT  65.055 31.559 65.826 38.129 ;
     RECT  65.055 38.129 65.754 38.173 ;
     RECT  30.42 36.931 50.886 38.209 ;
     RECT  51.624 36.125 53.442 38.209 ;
     RECT  64.404 38.173 65.754 38.309 ;
     RECT  69.228 35.159 69.39 38.371 ;
     RECT  78.372 37.831 81.09 38.399 ;
     RECT  70.455 37.589 71.226 38.479 ;
     RECT  66.708 38.479 66.726 38.579 ;
     RECT  70.455 38.479 71.298 38.579 ;
     RECT  76.968 37.561 77.094 38.579 ;
     RECT  54.255 37.201 55.782 38.641 ;
     RECT  30.42 38.209 53.442 38.669 ;
     RECT  74.664 38.443 74.682 38.669 ;
     RECT  58.752 38.129 59.937 38.717 ;
     RECT  59.184 38.717 59.937 38.741 ;
     RECT  54.252 38.641 55.782 38.821 ;
     RECT  68.976 38.371 69.39 38.975 ;
     RECT  51.3 38.669 53.442 39.091 ;
     RECT  54.216 38.821 55.782 39.091 ;
     RECT  62.244 36.275 62.262 39.181 ;
     RECT  64.404 38.309 65.337 39.515 ;
     RECT  59.655 38.741 59.937 39.595 ;
     RECT  80.064 38.399 81.09 39.623 ;
     RECT  30.42 38.669 50.418 39.631 ;
     RECT  51.3 39.091 55.782 39.631 ;
     RECT  62.136 39.181 62.262 39.631 ;
     RECT  78.372 38.399 79.326 39.659 ;
     RECT  79.308 39.659 79.326 39.721 ;
     RECT  30.42 39.631 55.782 39.773 ;
     RECT  79.308 39.721 79.434 39.785 ;
     RECT  66.708 39.721 66.726 39.857 ;
     RECT  79.416 39.785 79.434 39.857 ;
     RECT  59.04 39.595 59.937 39.865 ;
     RECT  61.92 39.631 62.262 39.865 ;
     RECT  63.252 36.275 63.378 39.865 ;
     RECT  61.74 39.865 62.262 39.901 ;
     RECT  63.252 39.865 63.918 39.901 ;
     RECT  51.3 39.773 55.782 39.917 ;
     RECT  61.74 39.901 63.918 39.917 ;
     RECT  58.896 39.865 59.937 40.171 ;
     RECT  64.872 39.515 65.337 40.199 ;
     RECT  62.136 39.917 63.378 40.289 ;
     RECT  58.716 40.171 59.937 40.397 ;
     RECT  59.436 40.397 59.937 40.405 ;
     RECT  59.436 40.405 59.994 40.441 ;
     RECT  80.388 39.623 81.09 40.507 ;
     RECT  75.855 37.895 76.137 40.555 ;
     RECT  77.076 38.579 77.094 40.559 ;
     RECT  79.812 40.507 81.09 40.559 ;
     RECT  54.255 39.917 55.782 40.595 ;
     RECT  80.388 40.559 81.09 40.595 ;
     RECT  69.228 38.975 69.39 40.603 ;
     RECT  67.284 40.555 67.302 40.711 ;
     RECT  75.855 40.555 76.302 40.711 ;
     RECT  67.284 40.711 67.446 40.829 ;
     RECT  69.012 40.603 69.39 40.829 ;
     RECT  55.584 40.595 55.782 41.035 ;
     RECT  56.628 38.129 57.726 41.035 ;
     RECT  73.224 35.885 73.242 41.035 ;
     RECT  62.244 40.289 63.378 41.071 ;
     RECT  59.436 40.441 60.57 41.099 ;
     RECT  61.92 41.071 63.378 41.165 ;
     RECT  75.855 40.711 76.806 41.171 ;
     RECT  62.244 41.165 63.378 41.243 ;
     RECT  51.3 39.917 53.442 41.251 ;
     RECT  54.255 40.595 54.594 41.251 ;
     RECT  73.224 41.035 73.71 41.251 ;
     RECT  67.284 40.829 67.374 41.279 ;
     RECT  59.436 41.099 60.426 41.341 ;
     RECT  70.455 38.579 70.737 41.341 ;
     RECT  71.604 41.323 71.622 41.341 ;
     RECT  72.612 41.251 73.818 41.369 ;
     RECT  59.004 41.341 60.426 41.405 ;
     RECT  67.356 41.279 67.374 41.513 ;
     RECT  72.612 41.369 73.242 41.513 ;
     RECT  80.388 40.595 80.946 41.513 ;
     RECT  55.584 41.035 57.726 41.521 ;
     RECT  80.388 41.513 80.766 41.549 ;
     RECT  70.455 41.341 71.622 41.611 ;
     RECT  59.436 41.405 60.426 41.648 ;
     RECT  51.3 41.251 54.594 41.683 ;
     RECT  68.976 40.981 68.994 41.711 ;
     RECT  59.655 41.648 60.426 41.783 ;
     RECT  55.512 41.521 57.726 41.881 ;
     RECT  70.455 41.611 71.658 41.945 ;
     RECT  55.512 41.881 58.23 42.215 ;
     RECT  51.3 41.683 54.738 42.331 ;
     RECT  55.512 42.215 55.782 42.331 ;
     RECT  51.3 42.331 55.782 42.749 ;
     RECT  60.984 42.763 61.002 42.811 ;
     RECT  56.628 42.215 58.23 43.061 ;
     RECT  30.42 39.773 50.418 43.099 ;
     RECT  51.3 42.749 53.442 43.099 ;
     RECT  70.455 41.945 71.298 43.133 ;
     RECT  59.655 41.783 59.937 43.141 ;
     RECT  60.984 42.811 61.11 43.141 ;
     RECT  59.655 43.141 61.326 43.259 ;
     RECT  54.255 42.749 55.782 43.295 ;
     RECT  80.388 41.549 80.406 43.295 ;
     RECT  71.82 43.141 71.838 43.609 ;
     RECT  56.628 43.061 58.086 43.709 ;
     RECT  71.82 43.609 71.91 43.709 ;
     RECT  77.544 43.231 77.562 43.709 ;
     RECT  54.255 43.295 54.738 43.799 ;
     RECT  57.528 43.709 58.086 43.799 ;
     RECT  30.42 43.099 53.442 43.807 ;
     RECT  54.255 43.799 54.594 43.807 ;
     RECT  78.372 39.659 78.39 43.979 ;
     RECT  55.62 43.295 55.782 44.069 ;
     RECT  63.252 41.243 63.378 44.069 ;
     RECT  73.224 41.513 73.242 44.105 ;
     RECT  56.628 43.709 56.754 44.185 ;
     RECT  59.655 43.259 60.426 44.221 ;
     RECT  59.655 44.221 60.822 44.249 ;
     RECT  79.884 44.383 79.902 44.429 ;
     RECT  66.708 44.221 66.726 44.581 ;
     RECT  70.455 43.133 70.794 44.645 ;
     RECT  30.42 43.807 54.594 44.689 ;
     RECT  66.708 44.581 66.798 44.717 ;
     RECT  65.055 40.199 65.337 44.761 ;
     RECT  80.064 44.491 80.442 44.761 ;
     RECT  60.804 44.249 60.822 44.789 ;
     RECT  80.064 44.761 80.622 44.789 ;
     RECT  56.556 44.185 56.754 44.851 ;
     RECT  56.088 44.851 56.754 44.875 ;
     RECT  57.528 43.799 57.726 44.875 ;
     RECT  80.172 44.789 80.622 44.879 ;
     RECT  56.088 44.875 57.726 44.915 ;
     RECT  75.855 41.171 76.137 44.971 ;
     RECT  56.088 44.915 56.862 45.005 ;
     RECT  75.855 44.971 76.23 45.023 ;
     RECT  65.055 44.761 65.574 45.059 ;
     RECT  56.556 45.005 56.862 45.197 ;
     RECT  30.42 44.689 54.702 45.221 ;
     RECT  54.255 45.221 54.702 45.391 ;
     RECT  62.244 41.243 62.262 45.391 ;
     RECT  63.252 44.069 63.27 45.391 ;
     RECT  77.004 45.031 77.022 45.403 ;
     RECT  74.664 45.301 74.682 45.455 ;
     RECT  76.968 45.403 77.022 45.535 ;
     RECT  77.904 44.995 77.922 45.571 ;
     RECT  56.556 45.197 56.646 45.599 ;
     RECT  76.86 45.535 77.022 45.599 ;
     RECT  76.86 45.599 76.878 45.725 ;
     RECT  75.855 45.023 76.137 45.841 ;
     RECT  77.832 45.571 77.922 45.841 ;
     RECT  54.255 45.391 54.738 45.869 ;
     RECT  30.42 45.221 53.442 45.959 ;
     RECT  80.172 44.879 80.478 46.075 ;
     RECT  54.255 45.869 54.702 46.111 ;
     RECT  73.656 45.967 73.674 46.111 ;
     RECT  77.832 45.841 77.958 46.111 ;
     RECT  62.244 45.391 63.27 46.381 ;
     RECT  79.056 46.345 79.074 46.381 ;
     RECT  80.028 46.075 80.478 46.381 ;
     RECT  59.655 44.249 59.937 46.471 ;
     RECT  73.26 46.111 73.674 46.535 ;
     RECT  79.056 46.381 80.478 46.615 ;
     RECT  78.912 46.615 80.478 46.685 ;
     RECT  72.504 46.075 72.522 46.741 ;
     RECT  75.855 45.841 76.842 46.741 ;
     RECT  61.416 46.381 63.27 46.769 ;
     RECT  73.656 46.535 73.674 46.769 ;
     RECT  66.42 44.725 66.438 46.777 ;
     RECT  70.455 44.645 70.737 46.777 ;
     RECT  75.276 46.741 76.842 46.777 ;
     RECT  65.055 45.059 65.337 46.813 ;
     RECT  66.42 46.777 66.726 46.849 ;
     RECT  66.42 46.849 66.762 46.885 ;
     RECT  77.832 46.111 78.03 46.885 ;
     RECT  56.628 45.599 56.646 46.921 ;
     RECT  62.244 46.769 63.27 46.921 ;
     RECT  74.772 46.777 76.842 46.921 ;
     RECT  79.236 46.685 80.478 46.925 ;
     RECT  61.416 46.769 61.434 47.011 ;
     RECT  70.455 46.777 70.938 47.011 ;
     RECT  74.664 46.921 76.842 47.011 ;
     RECT  77.832 46.885 78.39 47.011 ;
     RECT  70.164 47.011 70.938 47.039 ;
     RECT  66.42 46.885 67.158 47.119 ;
     RECT  70.164 47.039 70.737 47.131 ;
     RECT  30.42 45.959 53.334 47.191 ;
     RECT  54.216 46.111 54.702 47.191 ;
     RECT  65.055 46.813 65.502 47.191 ;
     RECT  66.348 47.119 67.158 47.191 ;
     RECT  69.912 47.131 70.737 47.281 ;
     RECT  30.42 47.191 54.702 47.309 ;
     RECT  66.276 47.191 67.806 47.309 ;
     RECT  69.66 47.281 70.737 47.309 ;
     RECT  74.664 47.011 78.39 47.309 ;
     RECT  66.42 47.309 67.806 47.315 ;
     RECT  75.24 47.309 78.39 47.345 ;
     RECT  80.028 46.925 80.478 47.425 ;
     RECT  57.708 44.915 57.726 47.461 ;
     RECT  60.804 47.011 61.434 47.615 ;
     RECT  62.244 46.921 64.026 47.615 ;
     RECT  56.628 46.921 56.898 47.623 ;
     RECT  57.672 47.461 57.726 47.623 ;
     RECT  65.055 47.191 65.538 47.623 ;
     RECT  66.672 47.315 67.806 47.651 ;
     RECT  75.384 47.345 78.39 47.659 ;
     RECT  79.236 46.925 79.29 47.659 ;
     RECT  80.028 47.425 80.73 47.659 ;
     RECT  59.4 46.471 59.937 47.731 ;
     RECT  65.055 47.623 65.682 47.732 ;
     RECT  66.672 47.651 67.374 47.759 ;
     RECT  75.384 47.659 80.73 47.759 ;
     RECT  55.728 47.551 55.746 47.821 ;
     RECT  65.055 47.732 65.646 47.821 ;
     RECT  72.504 46.741 72.702 47.821 ;
     RECT  55.476 47.821 55.746 47.849 ;
     RECT  64.368 47.821 65.646 47.849 ;
     RECT  30.42 47.309 53.334 47.885 ;
     RECT  62.244 47.615 63.558 47.885 ;
     RECT  67.032 47.759 67.374 47.885 ;
     RECT  69.66 47.309 69.678 47.933 ;
     RECT  72.504 47.821 72.99 48.001 ;
     RECT  75.384 47.759 78.39 48.091 ;
     RECT  75.312 48.091 78.39 48.128 ;
     RECT  60.804 47.615 60.822 48.155 ;
     RECT  58.788 47.731 59.937 48.187 ;
     RECT  58.788 48.187 60.03 48.227 ;
     RECT  72.504 48.001 73.638 48.299 ;
     RECT  72.504 48.299 72.99 48.389 ;
     RECT  55.476 47.849 55.566 48.425 ;
     RECT  55.548 48.425 55.566 48.467 ;
     RECT  72.504 48.389 72.954 48.509 ;
     RECT  75.384 48.128 78.39 48.659 ;
     RECT  75.528 48.659 78.39 48.667 ;
     RECT  79.236 47.759 80.73 48.667 ;
     RECT  70.455 47.309 70.737 48.775 ;
     RECT  68.76 47.695 68.778 48.805 ;
     RECT  68.472 48.805 68.778 48.811 ;
     RECT  70.455 48.775 71.046 48.811 ;
     RECT  30.42 47.885 53.01 48.839 ;
     RECT  68.472 48.811 69.102 48.845 ;
     RECT  58.788 48.227 59.937 48.907 ;
     RECT  61.02 48.739 61.038 48.929 ;
     RECT  70.455 48.811 71.262 48.929 ;
     RECT  75.528 48.667 80.73 48.929 ;
     RECT  68.76 48.845 69.102 48.937 ;
     RECT  56.628 47.623 57.726 49.037 ;
     RECT  72.504 48.509 72.666 49.045 ;
     RECT  67.032 47.885 67.05 49.081 ;
     RECT  75.6 48.929 80.73 49.081 ;
     RECT  54.255 47.309 54.702 49.171 ;
     RECT  64.368 47.849 65.337 49.195 ;
     RECT  67.032 49.081 67.626 49.199 ;
     RECT  71.784 49.045 72.666 49.199 ;
     RECT  54.255 49.171 54.99 49.351 ;
     RECT  67.032 49.199 67.554 49.351 ;
     RECT  54.252 49.351 54.99 49.441 ;
     RECT  54.252 49.441 55.71 49.469 ;
     RECT  56.628 49.037 56.646 49.513 ;
     RECT  66.312 49.351 67.554 49.531 ;
     RECT  57.708 49.037 57.726 49.549 ;
     RECT  58.752 48.907 59.937 49.549 ;
     RECT  64.368 49.195 65.394 49.613 ;
     RECT  68.76 48.937 69.246 49.621 ;
     RECT  57.708 49.549 59.937 49.649 ;
     RECT  66.132 49.531 67.554 49.775 ;
     RECT  74.664 49.351 74.682 49.775 ;
     RECT  70.455 48.929 71.046 49.819 ;
     RECT  54.255 49.469 55.71 49.855 ;
     RECT  65.055 49.613 65.394 49.855 ;
     RECT  62.244 47.885 63.27 49.891 ;
     RECT  70.452 49.819 71.046 49.891 ;
     RECT  72.504 49.199 72.666 49.891 ;
     RECT  61.524 49.891 63.27 49.949 ;
     RECT  57.708 49.649 58.698 50.009 ;
     RECT  66.456 49.775 67.554 50.009 ;
     RECT  72.504 49.891 73.278 50.009 ;
     RECT  54.255 49.855 55.818 50.045 ;
     RECT  67.032 50.009 67.554 50.089 ;
     RECT  68.292 49.621 69.246 50.089 ;
     RECT  67.032 50.089 69.246 50.125 ;
     RECT  65.055 49.855 65.538 50.315 ;
     RECT  65.055 50.315 65.337 50.431 ;
     RECT  60.948 50.431 61.29 50.539 ;
     RECT  67.032 50.125 69.57 50.549 ;
     RECT  56.556 49.513 56.646 50.585 ;
     RECT  75.6 49.081 80.946 50.665 ;
     RECT  56.628 50.585 56.646 50.701 ;
     RECT  60.768 50.539 61.29 50.701 ;
     RECT  62.028 49.949 63.27 50.701 ;
     RECT  72.504 50.009 73.206 50.791 ;
     RECT  72.468 50.791 73.206 50.827 ;
     RECT  74.232 49.855 74.646 50.827 ;
     RECT  72.468 50.827 74.646 50.935 ;
     RECT  60.66 50.701 63.27 50.963 ;
     RECT  67.032 50.549 69.246 50.971 ;
     RECT  70.38 49.891 71.046 50.971 ;
     RECT  71.964 50.935 74.646 50.971 ;
     RECT  75.6 50.665 81.018 50.999 ;
     RECT  70.38 50.971 74.646 51.005 ;
     RECT  30.42 48.839 52.326 51.061 ;
     RECT  72.36 51.005 74.646 51.089 ;
     RECT  60.66 50.963 62.262 51.161 ;
     RECT  75.6 50.999 78.642 51.205 ;
     RECT  66.888 50.971 69.246 51.233 ;
     RECT  30.42 51.061 52.866 51.241 ;
     RECT  64.512 50.431 65.337 51.241 ;
     RECT  74.232 51.089 74.646 51.241 ;
     RECT  75.564 51.205 78.642 51.241 ;
     RECT  63.144 50.963 63.27 51.293 ;
     RECT  74.232 51.241 78.642 51.293 ;
     RECT  58.68 50.009 58.698 51.331 ;
     RECT  59.472 49.649 59.937 51.331 ;
     RECT  58.68 51.331 59.937 51.359 ;
     RECT  60.66 51.161 61.326 51.395 ;
     RECT  72.36 51.089 73.206 51.395 ;
     RECT  58.752 51.359 59.937 51.581 ;
     RECT  30.42 51.241 53.046 51.595 ;
     RECT  66.996 51.233 69.246 51.629 ;
     RECT  30.42 51.595 53.37 51.635 ;
     RECT  64.512 51.241 65.574 51.673 ;
     RECT  54.255 50.045 55.602 51.745 ;
     RECT  30.42 51.635 52.758 51.809 ;
     RECT  54.036 51.745 55.602 51.899 ;
     RECT  64.512 51.673 66.006 51.907 ;
     RECT  30.42 51.809 52.326 51.935 ;
     RECT  54.255 51.899 55.602 51.979 ;
     RECT  64.404 51.907 66.006 51.979 ;
     RECT  66.996 51.629 68.094 51.979 ;
     RECT  56.628 50.701 56.754 52.051 ;
     RECT  57.708 50.009 57.726 52.051 ;
     RECT  70.38 51.005 71.55 52.051 ;
     RECT  56.628 52.051 57.726 52.169 ;
     RECT  72.396 51.395 73.206 52.205 ;
     RECT  63.252 51.293 63.27 52.249 ;
     RECT  64.404 51.979 68.094 52.249 ;
     RECT  54.255 51.979 55.854 52.321 ;
     RECT  56.628 52.169 56.754 52.321 ;
     RECT  75.456 51.293 78.642 52.321 ;
     RECT  57.528 52.169 57.726 52.322 ;
     RECT  57.564 52.322 57.726 52.405 ;
     RECT  74.232 51.293 74.646 52.411 ;
     RECT  75.384 52.321 78.642 52.445 ;
     RECT  63.252 52.249 68.094 52.447 ;
     RECT  72.504 52.205 73.206 52.507 ;
     RECT  74.124 52.411 74.646 52.507 ;
     RECT  59.148 51.581 59.937 52.511 ;
     RECT  70.344 52.051 71.55 52.519 ;
     RECT  72.504 52.507 74.646 52.519 ;
     RECT  75.384 52.445 78.426 52.519 ;
     RECT  69.228 51.629 69.246 52.591 ;
     RECT  70.02 52.519 71.55 52.591 ;
     RECT  69.228 52.591 71.55 52.744 ;
     RECT  62.244 51.161 62.262 52.753 ;
     RECT  69.228 52.744 71.694 52.79 ;
     RECT  63.252 52.447 68.454 52.817 ;
     RECT  62.244 52.753 62.514 52.861 ;
     RECT  63.252 52.817 66.006 52.861 ;
     RECT  66.888 52.817 68.454 52.861 ;
     RECT  69.228 52.79 71.658 52.861 ;
     RECT  66.888 52.861 71.658 52.889 ;
     RECT  79.38 50.999 81.018 52.951 ;
     RECT  57.564 52.405 58.338 53.015 ;
     RECT  72.504 52.519 78.426 53.015 ;
     RECT  59.472 52.511 59.937 53.024 ;
     RECT  57.708 53.015 58.338 53.131 ;
     RECT  59.58 53.024 59.937 53.131 ;
     RECT  60.66 51.395 60.678 53.131 ;
     RECT  54.255 52.321 56.754 53.227 ;
     RECT  53.82 53.227 56.754 53.285 ;
     RECT  62.244 52.861 66.006 53.285 ;
     RECT  72.504 53.015 74.754 53.365 ;
     RECT  57.708 53.131 58.734 53.393 ;
     RECT  30.42 51.935 51.318 53.401 ;
     RECT  52.092 51.935 52.326 53.401 ;
     RECT  62.244 53.285 62.262 53.401 ;
     RECT  79.236 52.951 81.018 53.519 ;
     RECT  79.308 53.519 81.018 53.555 ;
     RECT  66.924 52.889 71.658 53.563 ;
     RECT  72.396 53.365 74.754 53.563 ;
     RECT  66.924 53.563 74.754 53.591 ;
     RECT  66.924 53.591 69.246 53.663 ;
     RECT  63.252 53.285 66.006 53.671 ;
     RECT  66.924 53.663 68.634 53.671 ;
     RECT  63.252 53.671 68.634 53.789 ;
     RECT  30.42 53.401 52.326 53.897 ;
     RECT  70.128 53.591 74.754 54.031 ;
     RECT  75.492 53.015 78.426 54.031 ;
     RECT  51.876 53.897 52.326 54.095 ;
     RECT  64.98 53.789 68.634 54.095 ;
     RECT  79.38 53.555 81.018 54.103 ;
     RECT  54.255 53.285 56.754 54.283 ;
     RECT  52.02 54.095 52.326 54.365 ;
     RECT  53.964 54.283 56.754 54.365 ;
     RECT  59.58 53.131 60.678 54.373 ;
     RECT  61.74 53.401 62.262 54.373 ;
     RECT  63.252 53.789 63.882 54.373 ;
     RECT  56.628 54.365 56.754 54.409 ;
     RECT  53.964 54.365 55.602 54.445 ;
     RECT  56.628 54.409 56.97 54.481 ;
     RECT  57.708 53.393 58.194 54.481 ;
     RECT  58.932 54.373 60.678 54.481 ;
     RECT  70.128 54.031 78.426 54.481 ;
     RECT  68.616 54.095 68.634 54.523 ;
     RECT  69.912 54.481 78.426 54.523 ;
     RECT  61.74 54.373 63.882 54.607 ;
     RECT  56.628 54.481 60.678 54.635 ;
     RECT  59.58 54.635 60.678 54.643 ;
     RECT  61.524 54.607 63.882 54.643 ;
     RECT  59.58 54.643 63.882 54.671 ;
     RECT  68.616 54.523 78.426 54.679 ;
     RECT  79.38 54.103 81.09 54.679 ;
     RECT  59.58 54.671 62.262 54.701 ;
     RECT  68.616 54.679 81.09 54.701 ;
     RECT  52.092 54.365 52.326 54.763 ;
     RECT  63.216 54.671 63.882 54.811 ;
     RECT  68.652 54.701 81.09 54.947 ;
     RECT  64.98 54.095 67.77 54.949 ;
     RECT  63.216 54.811 63.99 54.985 ;
     RECT  64.944 54.949 67.77 54.985 ;
     RECT  53.64 54.445 55.602 55.021 ;
     RECT  69.84 54.947 81.09 55.037 ;
     RECT  59.616 54.701 62.262 55.049 ;
     RECT  52.092 54.763 52.65 55.183 ;
     RECT  53.604 55.021 55.602 55.183 ;
     RECT  69.84 55.037 71.622 55.211 ;
     RECT  63.216 54.985 67.77 55.247 ;
     RECT  68.652 54.947 68.85 55.319 ;
     RECT  52.092 55.183 55.602 55.409 ;
     RECT  63.216 55.247 66.15 55.409 ;
     RECT  63.216 55.409 66.078 55.445 ;
     RECT  61.74 55.049 62.262 55.453 ;
     RECT  63.216 55.445 63.342 55.453 ;
     RECT  68.652 55.319 68.67 55.517 ;
     RECT  72.504 55.037 81.09 55.723 ;
     RECT  56.628 54.635 58.734 55.831 ;
     RECT  59.616 55.049 60.822 55.831 ;
     RECT  67.032 55.247 67.77 55.993 ;
     RECT  56.628 55.831 60.822 56.029 ;
     RECT  61.74 55.453 63.342 56.029 ;
     RECT  67.032 55.993 68.094 56.029 ;
     RECT  53.676 55.409 55.602 56.191 ;
     RECT  64.404 55.445 66.078 56.191 ;
     RECT  66.888 56.029 68.094 56.191 ;
     RECT  53.676 56.191 55.71 56.227 ;
     RECT  64.404 56.191 68.094 56.237 ;
     RECT  53.676 56.227 55.782 56.327 ;
     RECT  30.42 53.897 50.958 56.371 ;
     RECT  56.628 56.029 63.342 56.429 ;
     RECT  66.888 56.237 68.094 56.497 ;
     RECT  64.404 56.237 65.934 56.569 ;
     RECT  70.02 55.211 71.622 56.605 ;
     RECT  72.504 55.723 81.162 56.605 ;
     RECT  30.42 56.371 51.138 56.641 ;
     RECT  52.092 55.409 52.542 56.641 ;
     RECT  53.676 56.327 55.602 56.641 ;
     RECT  61.092 56.429 63.342 56.641 ;
     RECT  64.332 56.569 65.934 56.641 ;
     RECT  66.888 56.497 68.13 56.669 ;
     RECT  68.112 56.669 68.13 56.683 ;
     RECT  70.02 56.605 81.162 56.731 ;
     RECT  30.42 56.641 55.602 56.759 ;
     RECT  61.092 56.641 63.414 56.831 ;
     RECT  61.74 56.831 63.414 56.903 ;
     RECT  64.26 56.641 65.934 56.903 ;
     RECT  30.42 56.759 53.442 56.909 ;
     RECT  69.48 56.731 81.162 56.911 ;
     RECT  69.192 56.911 81.162 57.137 ;
     RECT  64.944 56.903 65.934 57.181 ;
     RECT  66.888 56.669 67.374 57.181 ;
     RECT  30.42 56.909 53.154 57.209 ;
     RECT  64.944 57.181 67.374 57.209 ;
     RECT  30.42 57.209 52.866 57.335 ;
     RECT  69.192 57.137 71.622 57.371 ;
     RECT  68.112 56.683 68.274 57.415 ;
     RECT  54.18 56.759 55.602 57.445 ;
     RECT  56.628 56.429 57.726 57.445 ;
     RECT  54.18 57.445 57.726 57.451 ;
     RECT  58.716 56.429 59.937 57.451 ;
     RECT  60.732 57.379 60.75 57.451 ;
     RECT  54.18 57.451 59.937 57.485 ;
     RECT  56.628 57.485 59.937 57.541 ;
     RECT  60.66 57.451 60.75 57.541 ;
     RECT  68.112 57.415 68.382 57.541 ;
     RECT  69.48 57.371 71.622 57.569 ;
     RECT  63.252 56.903 63.414 57.721 ;
     RECT  67.86 57.541 68.382 58.081 ;
     RECT  56.628 57.541 60.75 58.153 ;
     RECT  64.944 57.209 67.05 58.189 ;
     RECT  67.86 58.081 68.418 58.225 ;
     RECT  61.74 56.903 62.262 58.261 ;
     RECT  63.252 57.721 63.558 58.261 ;
     RECT  64.368 58.189 67.05 58.261 ;
     RECT  69.768 57.569 71.55 58.351 ;
     RECT  67.86 58.225 68.49 58.363 ;
     RECT  69.264 58.351 71.55 58.363 ;
     RECT  56.628 58.153 60.786 58.379 ;
     RECT  63.252 58.261 67.05 58.415 ;
     RECT  61.596 58.261 62.262 58.423 ;
     RECT  63.252 58.415 63.81 58.423 ;
     RECT  30.42 57.335 52.326 58.459 ;
     RECT  53.172 58.261 53.19 58.459 ;
     RECT  30.42 58.459 53.19 58.531 ;
     RECT  61.596 58.423 63.81 58.531 ;
     RECT  67.86 58.363 71.55 58.531 ;
     RECT  54.18 57.485 55.818 58.559 ;
     RECT  67.86 58.531 71.766 58.621 ;
     RECT  72.504 57.137 81.162 58.621 ;
     RECT  61.56 58.531 63.81 58.721 ;
     RECT  64.944 58.415 67.05 58.891 ;
     RECT  67.86 58.621 81.162 58.955 ;
     RECT  64.944 58.891 67.122 58.999 ;
     RECT  67.86 58.955 68.022 58.999 ;
     RECT  30.42 58.531 53.298 59.161 ;
     RECT  54.18 58.559 55.746 59.161 ;
     RECT  61.74 58.721 63.81 59.161 ;
     RECT  30.42 59.161 55.746 59.189 ;
     RECT  69.012 58.955 81.162 59.225 ;
     RECT  69.012 59.225 69.174 59.261 ;
     RECT  64.944 58.999 68.022 59.297 ;
     RECT  56.628 58.379 60.462 59.341 ;
     RECT  56.628 59.341 60.534 59.459 ;
     RECT  64.944 59.297 67.05 59.459 ;
     RECT  67.86 59.297 68.022 59.459 ;
     RECT  67.86 59.459 67.878 59.495 ;
     RECT  61.74 59.161 63.954 59.605 ;
     RECT  64.944 59.459 65.934 59.605 ;
     RECT  56.628 59.459 59.994 59.645 ;
     RECT  61.74 59.605 65.934 59.645 ;
     RECT  29.592 55.255 29.61 59.701 ;
     RECT  30.42 59.189 53.154 59.701 ;
     RECT  29.592 59.701 53.154 59.729 ;
     RECT  53.964 59.189 55.746 60.151 ;
     RECT  29.592 59.729 52.326 60.241 ;
     RECT  70.02 59.225 81.162 60.305 ;
     RECT  29.088 60.241 52.326 60.341 ;
     RECT  64.944 59.645 65.934 60.385 ;
     RECT  66.708 59.459 67.05 60.385 ;
     RECT  56.628 59.645 57.726 60.421 ;
     RECT  58.464 59.645 59.994 60.421 ;
     RECT  60.732 59.701 60.75 60.421 ;
     RECT  61.74 59.645 63.954 60.421 ;
     RECT  56.628 60.421 63.954 60.511 ;
     RECT  64.944 60.385 67.05 60.511 ;
     RECT  53.136 59.729 53.154 60.539 ;
     RECT  56.628 60.511 67.05 60.539 ;
     RECT  58.464 60.539 67.05 60.605 ;
     RECT  53.892 60.151 55.746 60.655 ;
     RECT  60.696 60.605 67.05 60.655 ;
     RECT  69.156 59.261 69.174 60.691 ;
     RECT  60.696 60.655 67.194 60.845 ;
     RECT  68.616 60.691 69.174 60.845 ;
     RECT  68.724 60.845 69.174 60.953 ;
     RECT  53.424 60.655 55.746 60.961 ;
     RECT  56.628 60.539 57.726 60.961 ;
     RECT  68.76 60.953 69.174 61.051 ;
     RECT  70.02 60.305 70.794 61.051 ;
     RECT  60.696 60.845 67.05 61.133 ;
     RECT  68.76 61.051 70.794 61.159 ;
     RECT  71.532 60.305 81.162 61.159 ;
     RECT  60.696 61.133 65.898 61.385 ;
     RECT  53.424 60.961 57.726 61.579 ;
     RECT  58.464 60.605 59.937 61.579 ;
     RECT  63.252 61.385 65.898 61.691 ;
     RECT  68.76 61.159 81.162 61.889 ;
     RECT  68.76 61.889 68.922 62.041 ;
     RECT  67.896 62.005 67.914 62.045 ;
     RECT  66.708 61.133 67.05 62.131 ;
     RECT  64.44 61.691 65.898 62.167 ;
     RECT  66.708 62.131 67.302 62.167 ;
     RECT  68.724 62.041 68.922 62.167 ;
     RECT  69.768 61.889 81.162 62.267 ;
     RECT  53.424 61.579 59.937 62.275 ;
     RECT  60.696 61.385 62.262 62.275 ;
     RECT  53.424 62.275 62.262 62.311 ;
     RECT  68.076 62.167 68.922 62.501 ;
     RECT  68.256 62.501 68.418 62.582 ;
     RECT  53.28 62.311 62.262 62.671 ;
     RECT  68.256 62.582 68.382 62.699 ;
     RECT  69.768 62.267 81.126 62.699 ;
     RECT  53.136 62.671 62.262 62.731 ;
     RECT  63.252 61.691 63.486 62.731 ;
     RECT  53.136 62.731 63.486 62.743 ;
     RECT  64.44 62.167 67.302 62.743 ;
     RECT  53.136 62.743 67.302 62.807 ;
     RECT  53.136 62.807 67.05 62.813 ;
     RECT  53.424 62.813 67.05 63.077 ;
     RECT  64.512 63.077 67.05 63.149 ;
     RECT  53.424 63.077 63.774 63.239 ;
     RECT  70.02 62.699 81.09 63.239 ;
     RECT  68.256 62.699 68.346 63.245 ;
     RECT  66.672 63.149 67.05 63.553 ;
     RECT  68.256 63.245 68.274 63.553 ;
     RECT  30.42 60.341 52.326 63.589 ;
     RECT  30.42 63.589 52.542 63.661 ;
     RECT  63.216 63.239 63.774 63.779 ;
     RECT  66.672 63.553 68.274 63.815 ;
     RECT  53.424 63.239 62.262 64.021 ;
     RECT  63.216 63.779 63.702 64.021 ;
     RECT  68.004 63.815 68.274 64.021 ;
     RECT  71.496 63.239 81.09 64.129 ;
     RECT  29.088 60.341 29.61 64.201 ;
     RECT  30.42 63.661 52.614 64.201 ;
     RECT  64.512 63.149 65.898 64.201 ;
     RECT  66.672 63.815 67.05 64.201 ;
     RECT  70.02 63.239 70.737 64.201 ;
     RECT  68.004 64.021 68.31 64.205 ;
     RECT  68.184 64.205 68.31 64.319 ;
     RECT  69.552 64.201 70.737 64.391 ;
     RECT  69.84 64.391 70.737 64.411 ;
     RECT  68.256 64.319 68.31 64.435 ;
     RECT  69.84 64.411 70.758 64.67 ;
     RECT  69.876 64.67 70.758 64.705 ;
     RECT  71.496 64.129 81.162 64.705 ;
     RECT  64.512 64.201 67.05 64.741 ;
     RECT  68.256 64.435 68.634 64.831 ;
     RECT  64.512 64.741 67.086 64.859 ;
     RECT  69.876 64.705 81.162 64.859 ;
     RECT  70.02 64.859 81.162 64.895 ;
     RECT  29.088 64.201 52.614 64.939 ;
     RECT  68.256 64.831 68.778 64.939 ;
     RECT  53.424 64.021 63.702 65.011 ;
     RECT  64.512 64.859 67.05 65.011 ;
     RECT  68.256 64.939 68.994 65.261 ;
     RECT  70.02 64.895 74.394 65.677 ;
     RECT  75.24 64.895 81.162 65.677 ;
     RECT  29.088 64.939 52.686 65.821 ;
     RECT  53.424 65.011 67.05 65.821 ;
     RECT  68.256 65.261 68.274 65.821 ;
     RECT  67.788 65.821 68.274 66.289 ;
     RECT  29.088 65.821 67.05 66.721 ;
     RECT  67.788 66.289 68.85 66.721 ;
     RECT  29.088 66.721 68.85 66.901 ;
     RECT  29.088 66.901 69.102 66.991 ;
     RECT  29.088 66.991 69.138 67.055 ;
     RECT  70.02 65.677 81.162 67.127 ;
     RECT  61.488 67.055 69.138 67.199 ;
     RECT  61.488 67.199 69.03 67.559 ;
     RECT  67.032 67.559 69.03 67.667 ;
     RECT  29.088 67.055 60.714 67.801 ;
     RECT  61.488 67.559 66.294 67.801 ;
     RECT  72.504 67.127 81.162 68.099 ;
     RECT  67.788 67.667 69.03 68.341 ;
     RECT  70.02 67.127 71.55 68.341 ;
     RECT  29.088 67.801 66.294 68.381 ;
     RECT  67.788 68.341 71.55 68.405 ;
     RECT  69.048 68.405 71.55 68.639 ;
     RECT  67.032 67.667 67.05 68.755 ;
     RECT  67.788 68.405 68.274 68.755 ;
     RECT  64.404 68.381 66.294 68.791 ;
     RECT  67.032 68.755 68.274 68.791 ;
     RECT  69.552 68.639 71.55 68.791 ;
     RECT  29.088 68.381 63.63 69.017 ;
     RECT  72.504 68.099 73.926 69.061 ;
     RECT  74.772 68.099 81.162 69.061 ;
     RECT  72.504 69.061 81.162 69.179 ;
     RECT  29.088 69.017 63.558 69.215 ;
     RECT  69.552 68.791 71.622 69.331 ;
     RECT  72.504 69.179 74.682 69.331 ;
     RECT  61.344 69.215 63.558 69.521 ;
     RECT  69.552 69.331 74.682 69.565 ;
     RECT  64.404 68.791 68.274 69.719 ;
     RECT  64.404 69.719 67.122 69.872 ;
     RECT  61.488 69.521 63.558 69.961 ;
     RECT  64.404 69.872 67.05 69.961 ;
     RECT  68.004 69.719 68.274 69.997 ;
     RECT  69.516 69.565 74.682 70.025 ;
     RECT  68.004 69.997 68.562 70.141 ;
     RECT  61.488 69.961 67.05 70.295 ;
     RECT  69.912 70.025 74.682 70.375 ;
     RECT  75.456 69.179 81.162 70.375 ;
     RECT  29.088 69.215 60.534 70.411 ;
     RECT  29.088 70.411 60.642 70.501 ;
     RECT  61.488 70.295 63.558 70.501 ;
     RECT  69.912 70.375 81.162 70.601 ;
     RECT  64.404 70.295 67.05 70.609 ;
     RECT  68.004 70.141 68.706 70.609 ;
     RECT  69.912 70.601 73.926 70.637 ;
     RECT  29.088 70.501 63.558 70.799 ;
     RECT  64.404 70.609 68.706 70.951 ;
     RECT  64.404 70.951 69.03 71.069 ;
     RECT  64.404 71.069 67.302 71.411 ;
     RECT  68.184 71.069 69.03 71.491 ;
     RECT  70.02 70.637 73.926 71.491 ;
     RECT  68.184 71.491 73.926 71.761 ;
     RECT  74.664 70.601 81.162 71.761 ;
     RECT  29.088 70.799 63.378 71.879 ;
     RECT  68.184 71.761 81.162 71.951 ;
     RECT  68.184 71.951 74.682 72.185 ;
     RECT  61.416 71.879 63.378 72.301 ;
     RECT  64.404 71.411 67.122 72.301 ;
     RECT  61.416 72.301 67.122 72.391 ;
     RECT  69.984 72.185 74.682 72.941 ;
     RECT  61.416 72.391 67.41 72.959 ;
     RECT  64.116 72.959 67.41 73.003 ;
     RECT  68.184 72.185 69.246 73.003 ;
     RECT  64.116 73.003 69.246 73.111 ;
     RECT  69.984 72.941 74.286 73.111 ;
     RECT  61.416 72.959 63.378 73.265 ;
     RECT  64.116 73.111 74.286 73.265 ;
     RECT  29.088 71.879 60.534 73.381 ;
     RECT  61.488 73.265 63.378 73.643 ;
     RECT  75.456 71.951 81.162 73.921 ;
     RECT  29.088 73.381 60.642 74.039 ;
     RECT  57.708 74.039 60.642 74.075 ;
     RECT  64.404 73.265 73.926 74.461 ;
     RECT  74.664 73.921 81.162 74.461 ;
     RECT  64.404 74.461 81.162 74.662 ;
     RECT  64.404 74.662 81.126 74.717 ;
     RECT  57.708 74.075 60.606 74.821 ;
     RECT  61.488 73.643 62.442 74.821 ;
     RECT  75.132 74.717 81.126 74.849 ;
     RECT  57.708 74.821 62.442 74.929 ;
     RECT  63.18 73.643 63.378 74.929 ;
     RECT  57.708 74.929 63.378 75.155 ;
     RECT  61.488 75.155 63.378 75.425 ;
     RECT  64.404 74.717 74.214 75.469 ;
     RECT  75.132 74.849 77.094 75.469 ;
     RECT  63.18 75.425 63.378 75.541 ;
     RECT  64.404 75.469 77.094 75.541 ;
     RECT  57.708 75.155 60.606 75.569 ;
     RECT  63.18 75.541 77.094 76.075 ;
     RECT  77.976 74.849 81.126 76.075 ;
     RECT  61.488 75.425 62.442 76.243 ;
     RECT  63.18 76.075 81.126 76.243 ;
     RECT  58.176 75.569 60.606 76.441 ;
     RECT  61.488 76.243 81.126 76.441 ;
     RECT  29.088 74.039 56.934 76.505 ;
     RECT  53.064 76.505 56.934 76.585 ;
     RECT  58.176 76.441 81.126 76.891 ;
     RECT  29.088 76.505 52.326 77.161 ;
     RECT  53.064 76.585 57.006 77.161 ;
     RECT  57.816 76.891 81.126 77.261 ;
     RECT  57.816 77.261 78.21 77.315 ;
     RECT  53.064 77.161 57.042 77.549 ;
     RECT  53.208 77.549 57.042 77.557 ;
     RECT  57.816 77.315 78.174 77.557 ;
     RECT  79.02 77.261 81.126 77.819 ;
     RECT  28.98 77.161 52.326 78.061 ;
     RECT  53.208 77.557 78.174 78.089 ;
     RECT  79.02 77.819 81.054 78.091 ;
     RECT  53.208 78.089 60.93 78.161 ;
     RECT  61.74 78.089 78.174 78.187 ;
     RECT  78.984 78.091 81.054 78.187 ;
     RECT  61.74 78.187 81.054 78.467 ;
     RECT  63.18 78.467 81.054 78.701 ;
     RECT  28.944 78.061 52.326 79.141 ;
     RECT  53.208 78.161 60.534 79.141 ;
     RECT  28.944 79.141 60.534 79.229 ;
     RECT  63.18 78.701 80.982 79.277 ;
     RECT  29.088 79.229 60.534 79.321 ;
     RECT  61.74 78.467 62.442 79.321 ;
     RECT  29.088 79.321 62.442 79.447 ;
     RECT  63.18 79.277 63.774 79.447 ;
     RECT  29.088 79.447 63.774 79.745 ;
     RECT  64.728 79.277 80.982 79.745 ;
     RECT  29.088 79.745 31.77 80.015 ;
     RECT  32.58 79.745 63.774 80.015 ;
     RECT  53.1 80.015 63.774 80.059 ;
     RECT  64.98 79.745 80.982 80.123 ;
     RECT  53.1 80.059 64.134 80.159 ;
     RECT  32.58 80.015 36.162 80.285 ;
     RECT  37.296 80.015 52.326 80.285 ;
     RECT  53.1 80.159 57.222 80.285 ;
     RECT  58.14 80.159 64.134 80.321 ;
     RECT  53.604 80.285 57.222 80.381 ;
     RECT  68.976 80.123 80.982 80.429 ;
     RECT  68.976 80.429 71.586 80.525 ;
     RECT  75.132 80.429 80.802 80.525 ;
     RECT  64.116 80.321 64.134 80.555 ;
     RECT  72.612 80.429 73.998 80.555 ;
     RECT  30.492 80.015 31.77 80.627 ;
     RECT  58.14 80.321 63.378 80.627 ;
     RECT  75.132 80.525 80.73 80.627 ;
     RECT  58.14 80.627 62.442 80.663 ;
     RECT  30.852 80.627 31.77 80.669 ;
     RECT  53.604 80.381 57.15 80.669 ;
     RECT  69.084 80.525 71.586 80.669 ;
     RECT  29.088 80.015 29.754 80.671 ;
     RECT  30.924 80.669 31.77 80.813 ;
     RECT  53.964 80.669 57.15 80.813 ;
     RECT  59.616 80.663 62.442 80.813 ;
     RECT  32.655 80.285 36.162 80.825 ;
     RECT  37.404 80.285 52.326 80.825 ;
     RECT  31.284 80.813 31.77 80.861 ;
     RECT  34.416 80.825 36.162 80.861 ;
     RECT  37.404 80.825 50.958 80.861 ;
     RECT  79.02 80.627 80.73 80.897 ;
     RECT  58.14 80.663 58.806 80.909 ;
     RECT  31.356 80.861 31.77 80.933 ;
     RECT  28.764 80.671 29.754 80.957 ;
     RECT  31.356 80.933 31.554 80.957 ;
     RECT  34.416 80.861 34.434 80.957 ;
     RECT  37.44 80.861 50.958 80.957 ;
     RECT  54.108 80.813 57.15 80.957 ;
     RECT  59.655 80.813 62.442 80.957 ;
     RECT  63.18 80.627 63.378 80.957 ;
     RECT  69.084 80.669 71.262 80.957 ;
     RECT  72.648 80.555 73.998 80.957 ;
     RECT  75.132 80.627 78.102 80.957 ;
     RECT  79.02 80.897 80.586 80.957 ;
     RECT  56.448 80.957 56.466 81.005 ;
     RECT  77.544 80.957 78.102 81.005 ;
     RECT  0.255 0.793 0.537 81.017 ;
     RECT  5.655 0.793 5.937 81.017 ;
     RECT  11.055 0.793 11.337 81.017 ;
     RECT  16.455 0.793 16.737 81.017 ;
     RECT  21.855 0.793 22.137 81.017 ;
     RECT  27.255 0.793 27.537 81.017 ;
     RECT  32.655 80.825 33.642 81.017 ;
     RECT  59.655 80.957 60.246 81.017 ;
     RECT  75.132 80.957 76.662 81.017 ;
     RECT  77.904 81.005 78.102 81.053 ;
     RECT  79.272 80.957 80.586 81.095 ;
     RECT  58.176 80.909 58.806 81.101 ;
     RECT  61.416 80.957 62.442 81.101 ;
     RECT  70.416 80.957 71.262 81.101 ;
     RECT  37.44 80.957 43.83 81.149 ;
     RECT  72.648 80.957 73.242 81.149 ;
     RECT  77.904 81.053 77.922 81.149 ;
     RECT  29.196 80.957 29.754 81.211 ;
     RECT  0.447 81.017 0.537 81.287 ;
     RECT  5.847 81.017 5.937 81.287 ;
     RECT  11.247 81.017 11.337 81.287 ;
     RECT  16.647 81.017 16.737 81.287 ;
     RECT  22.047 81.017 22.137 81.287 ;
     RECT  27.447 81.017 27.537 81.287 ;
     RECT  38.247 81.149 43.83 81.287 ;
     RECT  44.604 80.957 50.958 81.287 ;
     RECT  59.847 81.017 60.246 81.287 ;
     RECT  70.596 81.101 71.262 81.437 ;
     RECT  32.796 81.017 33.642 81.485 ;
     RECT  75.132 81.017 75.15 81.595 ;
     RECT  35.244 80.861 36.162 81.643 ;
     RECT  64.98 80.123 68.238 81.643 ;
     RECT  49.464 81.287 50.958 81.677 ;
     RECT  54.108 80.957 55.134 81.691 ;
     RECT  64.26 81.643 68.238 81.725 ;
     RECT  73.98 80.957 73.998 81.725 ;
     RECT  29.196 81.211 29.826 81.739 ;
     RECT  30.888 81.595 31.086 81.739 ;
     RECT  32.796 81.485 33.498 81.739 ;
     RECT  37.44 81.149 37.458 81.739 ;
     RECT  52.092 80.825 52.326 81.739 ;
     RECT  59.976 81.287 60.246 81.739 ;
     RECT  61.416 81.101 62.118 81.739 ;
     RECT  71.244 81.437 71.262 81.739 ;
     RECT  74.916 81.595 75.15 81.739 ;
     RECT  34.632 81.643 36.162 81.773 ;
     RECT  38.376 81.287 43.83 81.773 ;
     RECT  49.68 81.677 50.958 81.773 ;
     RECT  52.092 81.739 53.19 81.773 ;
     RECT  64.26 81.725 65.898 81.773 ;
     RECT  75.996 81.017 76.662 81.773 ;
     RECT  69.084 80.957 69.246 81.787 ;
     RECT  34.74 81.773 36.162 81.821 ;
     RECT  38.376 81.773 41.022 81.821 ;
     RECT  44.604 81.287 48.69 81.821 ;
     RECT  49.68 81.773 50.418 81.821 ;
     RECT  59.976 81.739 62.118 81.821 ;
     RECT  64.26 81.773 65.754 81.821 ;
     RECT  66.708 81.725 68.238 81.821 ;
     RECT  71.244 81.739 71.838 81.821 ;
     RECT  56.952 81.739 56.97 81.835 ;
     RECT  58.176 81.101 58.266 81.835 ;
     RECT  71.82 81.821 71.838 81.835 ;
     RECT  75.996 81.773 76.338 81.835 ;
     RECT  29.196 81.739 31.194 81.869 ;
     RECT  32.544 81.739 33.498 81.869 ;
     RECT  34.92 81.821 36.162 81.869 ;
     RECT  37.008 81.739 37.458 81.869 ;
     RECT  38.376 81.821 40.05 81.869 ;
     RECT  41.004 81.821 41.022 81.869 ;
     RECT  41.832 81.773 42.318 81.869 ;
     RECT  43.056 81.773 43.83 81.869 ;
     RECT  44.604 81.821 44.622 81.869 ;
     RECT  45.504 81.821 47.214 81.869 ;
     RECT  48.132 81.821 48.69 81.869 ;
     RECT  49.68 81.821 50.094 81.869 ;
     RECT  52.236 81.773 53.19 81.869 ;
     RECT  54.036 81.691 55.134 81.869 ;
     RECT  56.952 81.835 58.266 81.869 ;
     RECT  60.084 81.821 62.118 81.869 ;
     RECT  63.216 80.957 63.378 81.869 ;
     RECT  64.26 81.821 64.998 81.869 ;
     RECT  65.736 81.821 65.754 81.869 ;
     RECT  66.708 81.821 67.626 81.869 ;
     RECT  69.084 81.787 69.318 81.869 ;
     RECT  71.82 81.835 71.946 81.869 ;
     RECT  73.296 81.739 73.314 81.869 ;
     RECT  74.34 81.739 75.15 81.869 ;
     RECT  75.888 81.835 76.338 81.869 ;
     RECT  79.272 81.095 79.29 81.869 ;
     RECT  80.316 81.095 80.586 81.869 ;
     RECT  57.456 81.869 58.194 81.917 ;
     RECT  60.228 81.869 60.426 81.917 ;
     RECT  67.608 81.869 67.626 81.917 ;
     RECT  75.024 81.869 75.042 81.917 ;
     RECT  54.108 81.869 54.126 81.965 ;
     RECT  57.456 81.917 57.474 81.965 ;
     RECT  60.228 81.917 60.246 81.965 ;
     RECT  64.26 81.869 64.278 81.965 ;
     RECT  66.708 81.869 66.726 81.965 ;
     RECT  69.192 81.869 69.318 81.965 ;
     RECT  75.888 81.869 75.906 81.965 ;
     RECT  50.076 81.869 50.094 82.013 ;
     RECT  55.044 81.869 55.062 82.013 ;
     RECT  61.956 81.869 61.974 82.013 ;
     RECT  71.928 81.869 71.946 82.013 ;
    LAYER M4 ;
     RECT  0.248 0.528 0.352 81.012 ;
     RECT  0.352 0.798 0.44 81.012 ;
     RECT  0.44 0.798 0.544 81.282 ;
     RECT  5.648 0.528 5.752 81.012 ;
     RECT  5.752 0.798 5.84 81.012 ;
     RECT  5.84 0.798 5.944 81.282 ;
     RECT  11.048 0.528 11.152 81.012 ;
     RECT  11.152 0.798 11.24 81.012 ;
     RECT  11.24 0.798 11.344 81.282 ;
     RECT  16.448 0.528 16.552 81.012 ;
     RECT  16.552 0.798 16.64 81.012 ;
     RECT  16.64 0.798 16.744 81.282 ;
     RECT  21.848 0.528 21.952 81.012 ;
     RECT  21.952 0.798 22.04 81.012 ;
     RECT  22.04 0.798 22.144 81.282 ;
     RECT  27.248 0.528 27.352 81.012 ;
     RECT  27.352 0.798 27.44 81.012 ;
     RECT  27.44 0.798 27.544 81.282 ;
     RECT  28.837 79.2 28.973 79.224 ;
     RECT  28.925 77.472 29.009 77.496 ;
     RECT  28.709 80.928 29.125 80.952 ;
     RECT  29.125 80.928 29.221 81.864 ;
     RECT  29.221 80.784 29.317 81.864 ;
     RECT  29.317 80.64 29.393 81.864 ;
     RECT  29.029 75.792 29.549 75.816 ;
     RECT  29.393 80.352 29.605 81.864 ;
     RECT  29.989 76.368 30.277 76.392 ;
     RECT  30.085 57.024 30.553 57.048 ;
     RECT  29.893 53.52 30.661 53.544 ;
     RECT  30.653 59.232 30.668 59.256 ;
     RECT  30.668 59.232 30.737 59.496 ;
     RECT  30.373 79.2 30.737 79.224 ;
     RECT  30.661 53.52 30.755 54.504 ;
     RECT  30.553 57.024 30.755 58.008 ;
     RECT  30.737 59.28 30.755 59.496 ;
     RECT  30.755 57.024 30.773 57.048 ;
     RECT  30.517 67.104 30.949 67.128 ;
     RECT  30.277 76.368 31.1 76.968 ;
     RECT  30.985 61.632 31.129 61.656 ;
     RECT  30.755 53.52 31.133 53.544 ;
     RECT  30.755 59.28 31.187 59.304 ;
     RECT  31.1 75.552 31.187 76.968 ;
     RECT  31.129 61.632 31.189 61.8 ;
     RECT  31.189 60.96 31.213 61.8 ;
     RECT  29.605 80.304 31.228 81.864 ;
     RECT  31.228 80.304 31.235 81.768 ;
     RECT  31.196 69.312 31.283 69.336 ;
     RECT  31.189 52.416 31.313 52.44 ;
     RECT  31.057 0.864 31.331 1.464 ;
     RECT  31.213 60.96 31.331 61.656 ;
     RECT  31.187 76.368 31.333 76.968 ;
     RECT  31.333 76.368 31.381 77.496 ;
     RECT  31.381 55.632 31.468 55.656 ;
     RECT  30.565 74.112 31.525 74.136 ;
     RECT  31.477 72.816 31.564 72.84 ;
     RECT  31.235 80.304 31.565 80.952 ;
     RECT  31.565 80.304 31.601 80.328 ;
     RECT  31.045 63.84 31.741 63.864 ;
     RECT  31.525 74.112 31.813 74.184 ;
     RECT  31.717 75.216 31.813 75.24 ;
     RECT  31.813 74.112 32.389 75.24 ;
     RECT  31.741 58.704 32.485 58.728 ;
     RECT  30.949 67.104 32.485 67.176 ;
     RECT  31.909 56.736 32.533 56.76 ;
     RECT  32.492 81.744 32.533 81.768 ;
     RECT  32.533 56.4 32.648 56.76 ;
     RECT  32.485 58.704 32.648 59.256 ;
     RECT  31.331 60.96 32.648 60.984 ;
     RECT  31.741 63.84 32.648 64.392 ;
     RECT  32.485 66.192 32.648 67.176 ;
     RECT  32.485 69.984 32.648 70.008 ;
     RECT  31.621 71.952 32.648 71.976 ;
     RECT  32.389 73.344 32.648 75.24 ;
     RECT  31.381 76.368 32.648 78.12 ;
     RECT  32.485 79.488 32.648 79.512 ;
     RECT  32.533 81.744 32.648 81.864 ;
     RECT  32.648 0.528 32.752 81.864 ;
     RECT  32.752 0.798 32.944 81.864 ;
     RECT  32.944 3.312 33.085 3.384 ;
     RECT  32.944 69.6 33.085 69.624 ;
     RECT  32.944 67.008 33.185 67.176 ;
     RECT  33.085 3.312 33.203 3.336 ;
     RECT  32.944 61.632 33.292 61.656 ;
     RECT  32.944 73.344 33.34 75.672 ;
     RECT  32.944 79.152 33.509 81.864 ;
     RECT  32.944 77.04 33.617 77.88 ;
     RECT  32.944 56.736 33.683 57.528 ;
     RECT  33.925 65.28 33.973 65.304 ;
     RECT  33.185 67.008 33.973 67.032 ;
     RECT  33.973 65.184 34.013 65.304 ;
     RECT  34.013 65.184 34.057 65.208 ;
     RECT  33.973 66.72 34.085 67.032 ;
     RECT  33.937 37.056 34.163 37.08 ;
     RECT  33.981 55.44 34.163 55.464 ;
     RECT  33.683 57.504 34.163 57.528 ;
     RECT  32.944 9.648 34.165 9.672 ;
     RECT  33.509 79.152 34.193 81.768 ;
     RECT  34.153 2.784 34.213 2.808 ;
     RECT  34.213 2.736 34.3 2.808 ;
     RECT  34.22 52.656 34.307 52.68 ;
     RECT  34.3 2.784 34.355 2.808 ;
     RECT  33.34 73.344 34.409 74.856 ;
     RECT  34.153 17.76 34.585 17.784 ;
     RECT  34.357 70.224 34.585 70.248 ;
     RECT  34.193 80.832 34.66 81.768 ;
     RECT  34.585 70.224 34.697 70.728 ;
     RECT  34.697 70.224 34.733 70.248 ;
     RECT  34.652 44.88 34.739 44.904 ;
     RECT  34.652 50.688 34.739 50.712 ;
     RECT  34.409 74.16 34.739 74.856 ;
     RECT  32.944 29.376 34.741 29.4 ;
     RECT  34.66 80.832 34.865 81.816 ;
     RECT  34.837 57.024 34.921 57.048 ;
     RECT  34.309 27.888 34.949 27.912 ;
     RECT  33.617 77.856 34.981 77.88 ;
     RECT  34.94 54.096 35.027 54.12 ;
     RECT  34.741 29.28 35.129 29.4 ;
     RECT  32.944 26.208 35.228 26.232 ;
     RECT  34.165 9.216 35.237 9.672 ;
     RECT  34.981 77.616 35.267 77.88 ;
     RECT  35.228 26.208 35.315 26.28 ;
     RECT  35.269 40.032 35.365 40.056 ;
     RECT  34.213 22.656 35.381 22.68 ;
     RECT  34.405 33.024 35.381 33.048 ;
     RECT  34.739 74.832 35.413 74.856 ;
     RECT  34.193 79.152 35.441 79.512 ;
     RECT  34.865 80.832 35.441 81.864 ;
     RECT  34.837 5.568 35.485 5.592 ;
     RECT  35.413 74.832 35.5 75.192 ;
     RECT  34.085 67.008 35.509 67.032 ;
     RECT  35.509 66.336 35.564 67.032 ;
     RECT  35.129 29.28 35.756 29.304 ;
     RECT  35.315 26.208 35.813 26.232 ;
     RECT  35.756 28.416 35.843 29.304 ;
     RECT  35.237 9.216 35.941 9.288 ;
     RECT  35.365 39.312 35.953 40.056 ;
     RECT  34.789 31.296 35.957 31.32 ;
     RECT  34.933 47.28 35.957 47.304 ;
     RECT  35.441 79.152 35.957 81.864 ;
     RECT  35.941 8.352 36.028 9.288 ;
     RECT  36.028 8.4 36.029 9.288 ;
     RECT  35.843 29.28 36.029 29.304 ;
     RECT  32.944 24.288 36.131 24.312 ;
     RECT  35.077 35.328 36.137 35.352 ;
     RECT  36.229 21.12 36.316 21.144 ;
     RECT  35.564 66.24 36.373 67.032 ;
     RECT  36.313 22.464 36.397 22.488 ;
     RECT  36.373 66.192 36.46 67.032 ;
     RECT  36.373 74.64 36.461 74.664 ;
     RECT  36.029 8.4 36.467 9.24 ;
     RECT  35.953 39.312 36.533 40.488 ;
     RECT  35.125 60.432 36.533 60.456 ;
     RECT  36.46 67.008 36.533 67.032 ;
     RECT  36.517 36.816 36.62 36.84 ;
     RECT  34.645 14.64 36.641 14.664 ;
     RECT  36.517 25.968 36.7 25.992 ;
     RECT  36.62 36.384 36.707 36.84 ;
     RECT  36.716 29.76 36.803 29.784 ;
     RECT  34.585 17.76 36.805 17.88 ;
     RECT  36.709 11.328 36.889 11.352 ;
     RECT  36.469 54.192 36.893 54.216 ;
     RECT  36.889 10.8 37.037 11.352 ;
     RECT  36.961 56.352 37.045 56.376 ;
     RECT  37.037 11.328 37.333 11.352 ;
     RECT  37.333 11.328 37.477 11.784 ;
     RECT  36.533 39.312 37.861 40.056 ;
     RECT  35.485 5.04 37.897 5.592 ;
     RECT  36.467 9.216 37.909 9.24 ;
     RECT  37.285 24.96 37.909 24.984 ;
     RECT  37.621 26.112 37.909 26.136 ;
     RECT  37.897 4.944 38.048 5.592 ;
     RECT  37.909 9.216 38.048 10.2 ;
     RECT  37.477 11.328 38.048 11.976 ;
     RECT  36.805 17.088 38.048 17.88 ;
     RECT  37.765 20.304 38.048 20.328 ;
     RECT  36.421 23.904 38.048 23.928 ;
     RECT  37.909 24.96 38.048 26.136 ;
     RECT  37.573 27.312 38.048 27.336 ;
     RECT  37.045 28.416 38.048 28.44 ;
     RECT  36.901 30.048 38.048 30.408 ;
     RECT  36.613 33.6 38.048 33.624 ;
     RECT  37.669 35.52 38.048 35.544 ;
     RECT  36.707 36.816 38.048 36.84 ;
     RECT  36.949 38.112 38.048 38.136 ;
     RECT  37.861 39.312 38.048 40.584 ;
     RECT  37.004 44.592 38.048 44.616 ;
     RECT  37.484 46.896 38.048 46.92 ;
     RECT  37.772 48.912 38.048 48.936 ;
     RECT  37.681 51.888 38.048 51.912 ;
     RECT  37.045 69.024 38.048 69.048 ;
     RECT  37.861 70.752 38.048 70.776 ;
     RECT  32.944 71.856 38.048 71.88 ;
     RECT  35.267 77.856 38.048 77.88 ;
     RECT  35.957 79.152 38.048 79.176 ;
     RECT  35.957 80.304 38.048 81.864 ;
     RECT  38.048 0.528 38.152 81.864 ;
     RECT  38.152 0.798 38.344 81.864 ;
     RECT  38.344 20.304 38.477 21.144 ;
     RECT  38.344 38.112 38.483 40.584 ;
     RECT  38.344 71.904 38.483 71.928 ;
     RECT  38.344 7.728 38.521 8.376 ;
     RECT  38.344 17.088 38.693 17.88 ;
     RECT  38.344 24.864 38.771 26.136 ;
     RECT  38.344 30.048 38.801 30.312 ;
     RECT  38.344 36.816 38.801 37.128 ;
     RECT  38.344 63.984 38.845 64.104 ;
     RECT  38.344 42.72 38.867 42.744 ;
     RECT  38.845 64.08 38.867 64.104 ;
     RECT  38.344 4.944 38.909 5.592 ;
     RECT  38.771 24.96 39.053 26.136 ;
     RECT  38.344 15.168 39.059 15.192 ;
     RECT  38.344 55.968 39.313 55.992 ;
     RECT  38.344 10.56 39.341 10.584 ;
     RECT  38.344 77.472 39.341 77.88 ;
     RECT  38.483 38.112 39.347 40.056 ;
     RECT  38.344 32.448 39.377 32.472 ;
     RECT  38.801 37.104 39.385 37.128 ;
     RECT  39.356 23.04 39.443 23.064 ;
     RECT  39.397 48.096 39.445 48.12 ;
     RECT  39.445 48.096 39.485 48.984 ;
     RECT  39.341 77.472 39.493 77.496 ;
     RECT  39.485 48.96 39.529 48.984 ;
     RECT  39.596 12.912 39.683 12.936 ;
     RECT  39.053 26.112 39.701 26.136 ;
     RECT  39.349 27.312 39.737 27.336 ;
     RECT  39.347 39.312 39.773 40.056 ;
     RECT  38.344 80.304 39.773 81.864 ;
     RECT  38.693 17.328 39.877 17.88 ;
     RECT  38.344 35.088 39.877 35.544 ;
     RECT  39.877 17.328 39.925 18.792 ;
     RECT  39.053 24.96 39.971 25.032 ;
     RECT  39.773 39.312 39.971 39.624 ;
     RECT  39.925 40.992 40.012 41.016 ;
     RECT  39.925 17.328 40.019 19.464 ;
     RECT  39.877 34.8 40.019 35.544 ;
     RECT  39.877 42.72 40.019 42.744 ;
     RECT  40.028 75.024 40.115 75.048 ;
     RECT  39.971 24.96 40.133 24.984 ;
     RECT  39.773 80.928 40.211 81.864 ;
     RECT  39.493 76.896 40.241 77.496 ;
     RECT  39.781 27.888 40.277 27.912 ;
     RECT  40.201 74.736 40.285 74.76 ;
     RECT  40.213 44.592 40.3 44.616 ;
     RECT  39.971 39.6 40.349 39.624 ;
     RECT  38.909 4.944 40.381 5.544 ;
     RECT  40.381 4.896 40.465 5.544 ;
     RECT  40.445 42.768 40.529 42.792 ;
     RECT  39.973 14.784 40.597 14.808 ;
     RECT  40.549 51.936 40.636 51.96 ;
     RECT  38.477 21.12 40.693 21.144 ;
     RECT  40.597 14.784 40.709 14.856 ;
     RECT  40.273 10.224 40.781 10.248 ;
     RECT  40.453 63.216 40.781 63.24 ;
     RECT  40.211 81.648 40.781 81.864 ;
     RECT  40.019 19.344 40.789 19.464 ;
     RECT  40.693 21.072 40.837 21.144 ;
     RECT  40.741 47.712 40.889 47.736 ;
     RECT  40.019 35.52 41.269 35.544 ;
     RECT  40.837 21.072 41.317 21.672 ;
     RECT  41.029 23.088 41.317 23.112 ;
     RECT  40.709 14.784 41.321 14.808 ;
     RECT  41.269 35.376 41.393 35.544 ;
     RECT  41.413 71.472 41.5 71.496 ;
     RECT  41.084 11.664 41.507 11.688 ;
     RECT  41.221 27.168 41.509 27.192 ;
     RECT  41.509 27.072 41.564 27.192 ;
     RECT  41.317 21.072 41.645 23.112 ;
     RECT  41.564 26.112 41.651 27.192 ;
     RECT  41.605 14.592 41.717 14.616 ;
     RECT  40.789 19.344 41.753 19.704 ;
     RECT  41.605 13.296 41.789 13.32 ;
     RECT  38.801 30.288 41.825 30.312 ;
     RECT  41.597 80.352 41.897 80.376 ;
     RECT  40.781 81.696 42.085 81.864 ;
     RECT  41.785 32.208 42.179 32.232 ;
     RECT  41.753 19.68 42.181 19.704 ;
     RECT  41.645 21.12 42.401 23.112 ;
     RECT  41.651 26.736 42.469 27.192 ;
     RECT  42.181 19.68 42.661 19.944 ;
     RECT  39.347 38.112 42.757 38.136 ;
     RECT  42.401 22.464 42.853 23.112 ;
     RECT  40.019 17.328 43.189 17.88 ;
     RECT  42.469 26.736 43.333 27.336 ;
     RECT  40.465 4.944 43.448 5.544 ;
     RECT  38.521 7.728 43.448 7.752 ;
     RECT  43.333 15.456 43.448 15.48 ;
     RECT  43.189 17.328 43.448 18.216 ;
     RECT  42.661 19.68 43.448 20.136 ;
     RECT  42.401 21.12 43.448 21.144 ;
     RECT  42.853 22.464 43.448 23.928 ;
     RECT  43.333 26.64 43.448 27.336 ;
     RECT  38.344 33.552 43.448 33.576 ;
     RECT  41.393 35.52 43.448 35.544 ;
     RECT  43.093 36.912 43.448 36.936 ;
     RECT  42.757 37.968 43.448 38.136 ;
     RECT  43.1 50.976 43.448 51 ;
     RECT  42.757 69.36 43.448 69.384 ;
     RECT  42.805 75.12 43.448 75.144 ;
     RECT  41.701 78.528 43.448 78.552 ;
     RECT  42.085 80.64 43.448 81.864 ;
     RECT  43.448 0.528 43.552 81.864 ;
     RECT  43.552 0.798 43.744 81.864 ;
     RECT  43.744 14.784 43.907 15.48 ;
     RECT  43.744 17.328 43.949 21.144 ;
     RECT  43.744 22.464 43.949 23.928 ;
     RECT  43.744 29.568 43.955 29.592 ;
     RECT  43.744 34.752 43.955 35.544 ;
     RECT  43.744 37.968 43.955 38.808 ;
     RECT  43.744 42.768 43.955 42.792 ;
     RECT  43.744 43.92 43.955 43.944 ;
     RECT  43.744 50.544 43.955 50.568 ;
     RECT  43.744 54.576 43.955 54.744 ;
     RECT  43.744 66.768 43.955 66.792 ;
     RECT  43.744 80.352 43.955 81.864 ;
     RECT  43.744 36.912 43.985 36.936 ;
     RECT  43.955 80.352 43.985 80.664 ;
     RECT  43.744 31.536 44.099 31.56 ;
     RECT  43.744 26.64 44.129 27.336 ;
     RECT  43.955 35.424 44.243 35.544 ;
     RECT  43.744 71.664 44.284 72.792 ;
     RECT  44.284 71.664 44.483 72.456 ;
     RECT  43.907 14.784 44.489 14.808 ;
     RECT  43.949 17.328 44.489 19.368 ;
     RECT  43.955 37.968 44.489 37.992 ;
     RECT  43.949 22.464 44.741 23.112 ;
     RECT  44.78 10.224 44.867 10.248 ;
     RECT  43.744 33.264 45.013 33.576 ;
     RECT  44.129 26.736 45.101 27.336 ;
     RECT  43.955 81.744 45.125 81.864 ;
     RECT  45.013 32.88 45.137 33.576 ;
     RECT  45.125 81.696 45.164 81.864 ;
     RECT  44.869 30.816 45.205 30.84 ;
     RECT  45.308 65.664 45.395 65.688 ;
     RECT  45.101 26.736 45.425 27.288 ;
     RECT  43.985 80.352 45.445 80.376 ;
     RECT  45.164 81.552 45.445 81.864 ;
     RECT  44.489 17.328 45.521 18.6 ;
     RECT  45.061 19.776 45.521 19.8 ;
     RECT  45.425 26.736 45.533 27.192 ;
     RECT  45.521 17.328 45.605 19.8 ;
     RECT  45.605 17.328 45.709 18.6 ;
     RECT  44.243 35.52 45.713 35.544 ;
     RECT  45.781 37.296 45.788 37.32 ;
     RECT  45.788 37.296 45.868 37.608 ;
     RECT  45.605 19.776 45.877 19.8 ;
     RECT  43.949 21.024 45.877 21.144 ;
     RECT  45.709 17.088 45.893 18.6 ;
     RECT  44.741 22.464 45.965 22.488 ;
     RECT  44.483 71.664 45.965 71.688 ;
     RECT  45.877 19.776 46.021 21.144 ;
     RECT  43.744 7.728 46.028 7.752 ;
     RECT  45.445 80.352 46.037 81.864 ;
     RECT  46.028 7.728 46.115 8.52 ;
     RECT  45.601 11.52 46.163 11.544 ;
     RECT  45.868 37.488 46.163 37.608 ;
     RECT  45.205 39.888 46.163 39.912 ;
     RECT  45.589 52.512 46.181 52.536 ;
     RECT  46.213 68.88 46.3 68.904 ;
     RECT  46.021 19.776 46.397 22.2 ;
     RECT  46.364 10.704 46.451 10.728 ;
     RECT  46.163 37.488 46.469 37.512 ;
     RECT  46.037 80.928 46.613 81.864 ;
     RECT  46.22 14.352 46.645 14.376 ;
     RECT  46.645 14.352 46.739 14.808 ;
     RECT  46.321 58.608 46.739 58.632 ;
     RECT  45.893 17.088 46.748 17.88 ;
     RECT  46.741 13.008 46.828 13.032 ;
     RECT  46.741 73.968 46.828 73.992 ;
     RECT  46.741 76.704 46.828 76.728 ;
     RECT  46.748 16.56 46.835 17.88 ;
     RECT  46.309 25.056 46.937 25.08 ;
     RECT  46.892 61.392 46.979 61.416 ;
     RECT  46.981 40.272 47.068 40.296 ;
     RECT  47.18 64.752 47.267 64.776 ;
     RECT  45.205 30.576 47.276 30.84 ;
     RECT  47.005 14.112 47.315 14.136 ;
     RECT  45.533 26.928 47.317 27.192 ;
     RECT  47.276 30.576 47.363 31.368 ;
     RECT  47.276 36.384 47.363 36.408 ;
     RECT  47.372 38.64 47.459 38.664 ;
     RECT  47.372 75.36 47.459 75.384 ;
     RECT  46.397 21.024 47.461 22.2 ;
     RECT  47.461 21.024 47.549 22.488 ;
     RECT  47.516 57.456 47.603 57.48 ;
     RECT  47.509 46.704 47.621 46.728 ;
     RECT  47.365 80.352 47.657 80.376 ;
     RECT  46.613 81.6 47.795 81.864 ;
     RECT  47.317 26.928 47.797 27.24 ;
     RECT  47.317 66.768 47.873 66.792 ;
     RECT  47.797 26.928 48.085 27.864 ;
     RECT  47.293 41.616 48.133 41.64 ;
     RECT  47.701 23.568 48.181 23.592 ;
     RECT  45.137 33.552 48.193 33.576 ;
     RECT  48.085 26.736 48.517 27.864 ;
     RECT  48.301 61.584 48.524 61.608 ;
     RECT  48.133 41.616 48.613 42.024 ;
     RECT  48.524 60.72 48.653 61.608 ;
     RECT  47.605 25.536 48.661 25.56 ;
     RECT  48.469 38.448 48.661 38.472 ;
     RECT  46.397 19.776 48.709 19.8 ;
     RECT  47.549 21.12 48.709 22.488 ;
     RECT  48.181 23.568 48.709 23.88 ;
     RECT  43.744 4.944 48.848 5.544 ;
     RECT  46.115 7.728 48.848 7.752 ;
     RECT  46.835 17.328 48.848 17.88 ;
     RECT  48.709 19.776 48.848 23.88 ;
     RECT  48.661 24.912 48.848 25.56 ;
     RECT  48.517 26.64 48.848 27.864 ;
     RECT  47.363 30.576 48.848 30.84 ;
     RECT  48.193 33.552 48.848 33.816 ;
     RECT  48.653 36.96 48.848 36.984 ;
     RECT  48.661 38.448 48.848 38.664 ;
     RECT  48.421 39.744 48.848 39.768 ;
     RECT  48.613 41.376 48.848 42.024 ;
     RECT  48.188 55.44 48.848 55.464 ;
     RECT  48.661 58.608 48.848 58.632 ;
     RECT  48.653 59.856 48.848 61.608 ;
     RECT  48.62 63.216 48.848 63.24 ;
     RECT  47.893 72.576 48.848 72.6 ;
     RECT  48.517 77.04 48.848 77.064 ;
     RECT  47.795 81.648 48.848 81.864 ;
     RECT  48.848 0.528 48.952 81.864 ;
     RECT  48.952 0.798 49.144 81.864 ;
     RECT  49.144 14.064 49.283 14.088 ;
     RECT  49.144 65.904 49.427 65.928 ;
     RECT  49.144 25.536 49.457 27.192 ;
     RECT  49.144 43.248 49.781 43.8 ;
     RECT  49.144 30.192 49.817 30.84 ;
     RECT  49.144 62.16 49.817 62.184 ;
     RECT  49.144 81.552 49.955 81.864 ;
     RECT  49.955 81.696 49.958 81.864 ;
     RECT  49.781 43.776 50.003 43.8 ;
     RECT  49.958 81.744 50.065 81.864 ;
     RECT  49.144 11.664 50.147 11.688 ;
     RECT  49.144 64.032 50.147 64.056 ;
     RECT  49.144 47.28 50.177 47.88 ;
     RECT  49.144 74.064 50.188 74.088 ;
     RECT  50.149 62.304 50.236 62.328 ;
     RECT  49.144 33.552 50.245 33.576 ;
     RECT  50.197 56.88 50.285 56.904 ;
     RECT  49.144 49.2 50.341 49.224 ;
     RECT  49.144 23.568 50.357 24.312 ;
     RECT  50.444 28.416 50.531 28.44 ;
     RECT  50.389 76.128 50.531 76.152 ;
     RECT  49.817 30.576 50.581 30.84 ;
     RECT  50.245 33.552 50.581 34.392 ;
     RECT  49.144 19.776 50.629 19.8 ;
     RECT  49.457 25.968 50.629 27.192 ;
     RECT  50.581 30.576 50.668 31.128 ;
     RECT  50.629 19.776 50.717 19.848 ;
     RECT  50.437 71.616 50.717 71.64 ;
     RECT  50.173 60.048 50.723 60.072 ;
     RECT  50.636 67.824 50.723 67.848 ;
     RECT  49.144 38.448 50.725 38.472 ;
     RECT  49.144 36.528 50.821 36.552 ;
     RECT  49.144 53.472 50.876 53.496 ;
     RECT  50.876 53.472 50.963 53.544 ;
     RECT  50.065 81.744 50.969 82.008 ;
     RECT  50.341 49.2 51.041 49.56 ;
     RECT  49.144 17.328 51.068 17.88 ;
     RECT  50.629 25.344 51.068 27.192 ;
     RECT  51.041 49.2 51.109 49.224 ;
     RECT  49.144 39.744 51.113 39.768 ;
     RECT  51.068 16.464 51.155 17.88 ;
     RECT  51.068 25.344 51.155 27.336 ;
     RECT  51.109 14.832 51.289 14.856 ;
     RECT  50.581 33.456 51.293 34.392 ;
     RECT  50.177 47.28 51.293 47.304 ;
     RECT  50.963 53.472 51.329 53.496 ;
     RECT  49.144 21.12 51.365 22.488 ;
     RECT  51.289 14.784 51.373 14.856 ;
     RECT  51.308 67.536 51.395 67.56 ;
     RECT  50.725 38.448 51.397 38.616 ;
     RECT  51.109 48.432 51.401 49.224 ;
     RECT  51.349 76.992 51.473 77.016 ;
     RECT  50.929 43.104 51.493 43.128 ;
     RECT  51.155 25.344 51.545 27.192 ;
     RECT  51.445 63.792 51.581 63.816 ;
     RECT  51.5 71.04 51.587 71.064 ;
     RECT  49.144 41.376 51.637 42.024 ;
     RECT  51.349 75.36 51.637 75.384 ;
     RECT  51.637 40.56 51.653 42.024 ;
     RECT  50.821 36.432 51.685 36.552 ;
     RECT  51.653 40.56 51.724 41.4 ;
     RECT  51.637 74.736 51.725 75.384 ;
     RECT  51.493 43.104 51.781 43.896 ;
     RECT  51.373 14.832 51.833 14.856 ;
     RECT  51.685 35.856 51.877 36.552 ;
     RECT  51.293 34.368 51.937 34.392 ;
     RECT  51.397 38.16 51.973 38.616 ;
     RECT  51.365 21.504 51.977 22.488 ;
     RECT  51.877 35.856 52.013 36.6 ;
     RECT  50.969 81.792 52.037 82.008 ;
     RECT  50.533 28.656 52.172 28.68 ;
     RECT  51.155 17.328 52.225 17.88 ;
     RECT  51.925 59.808 52.229 59.832 ;
     RECT  52.172 28.656 52.259 29.4 ;
     RECT  51.937 34.368 52.259 34.872 ;
     RECT  52.172 56.64 52.259 56.664 ;
     RECT  51.973 38.16 52.261 39.048 ;
     RECT  50.717 19.776 52.268 19.8 ;
     RECT  52.268 19.344 52.355 19.8 ;
     RECT  52.225 17.328 52.453 18.12 ;
     RECT  52.259 34.368 52.453 34.392 ;
     RECT  51.829 65.568 52.473 65.592 ;
     RECT  50.357 23.568 52.501 23.592 ;
     RECT  52.259 28.656 52.553 28.68 ;
     RECT  52.469 70.656 52.553 70.68 ;
     RECT  52.501 23.568 52.588 24.12 ;
     RECT  52.508 66.912 52.595 66.936 ;
     RECT  52.453 16.8 52.621 18.12 ;
     RECT  51.977 21.504 52.7 22.344 ;
     RECT  52.621 16.8 52.739 18.168 ;
     RECT  51.401 48.432 52.741 48.456 ;
     RECT  52.261 38.16 52.769 39.912 ;
     RECT  52.741 47.856 52.769 48.456 ;
     RECT  52.7 20.976 52.787 22.344 ;
     RECT  52.739 16.8 52.877 17.88 ;
     RECT  52.621 54.768 52.979 54.792 ;
     RECT  52.769 38.448 52.981 39.912 ;
     RECT  51.724 41.136 52.981 41.4 ;
     RECT  51.545 25.632 53.017 27.192 ;
     RECT  52.981 67.248 53.036 67.272 ;
     RECT  52.787 21.504 53.053 22.344 ;
     RECT  53.036 67.248 53.093 67.368 ;
     RECT  53.093 67.344 53.123 67.368 ;
     RECT  52.981 38.448 53.165 41.4 ;
     RECT  53.084 59.232 53.171 59.256 ;
     RECT  53.084 62.784 53.171 62.808 ;
     RECT  52.355 19.776 53.201 19.8 ;
     RECT  53.053 21.504 53.201 22.536 ;
     RECT  53.017 25.104 53.201 27.192 ;
     RECT  53.201 25.632 53.221 27.192 ;
     RECT  53.029 28.224 53.221 28.44 ;
     RECT  53.221 25.632 53.237 28.44 ;
     RECT  50.668 30.576 53.317 30.84 ;
     RECT  53.341 78.912 53.42 78.936 ;
     RECT  53.237 25.968 53.605 28.44 ;
     RECT  53.317 30.576 53.701 31.464 ;
     RECT  53.557 54.48 53.797 54.504 ;
     RECT  53.593 80.64 53.953 80.664 ;
     RECT  52.037 81.744 53.953 82.008 ;
     RECT  53.605 25.968 54.037 28.488 ;
     RECT  53.701 29.616 54.037 31.464 ;
     RECT  52.588 23.568 54.133 23.88 ;
     RECT  51.781 42.72 54.133 43.896 ;
     RECT  49.144 4.944 54.248 5.544 ;
     RECT  49.144 7.728 54.248 7.752 ;
     RECT  53.701 14.784 54.248 14.808 ;
     RECT  53.228 16.224 54.248 16.248 ;
     RECT  52.877 17.328 54.248 17.88 ;
     RECT  53.941 20.448 54.248 20.472 ;
     RECT  53.201 21.504 54.248 22.2 ;
     RECT  54.133 23.568 54.248 23.976 ;
     RECT  54.037 25.968 54.248 31.464 ;
     RECT  53.653 33.024 54.248 33.048 ;
     RECT  52.453 34.176 54.248 34.392 ;
     RECT  52.013 36.096 54.248 36.6 ;
     RECT  53.165 38.448 54.248 39.912 ;
     RECT  53.165 41.136 54.248 41.4 ;
     RECT  54.133 42.576 54.248 43.896 ;
     RECT  51.013 45.168 54.248 45.192 ;
     RECT  52.769 47.856 54.248 47.88 ;
     RECT  53.341 51.6 54.248 51.624 ;
     RECT  53.797 53.232 54.248 53.256 ;
     RECT  53.797 54.288 54.248 54.504 ;
     RECT  53.269 56.88 54.248 56.904 ;
     RECT  53.509 61.392 54.248 61.416 ;
     RECT  53.845 64.56 54.248 64.584 ;
     RECT  54.241 73.536 54.248 73.56 ;
     RECT  53.989 76.896 54.248 76.92 ;
     RECT  53.42 78.288 54.248 78.936 ;
     RECT  53.953 80.64 54.248 82.008 ;
     RECT  54.248 0.528 54.352 82.008 ;
     RECT  54.352 0.798 54.544 82.008 ;
     RECT  54.544 23.568 54.713 23.976 ;
     RECT  54.544 47.616 54.755 49.368 ;
     RECT  54.544 55.776 54.755 57.144 ;
     RECT  54.544 67.824 54.755 67.944 ;
     RECT  54.544 72.96 54.755 73.56 ;
     RECT  54.755 55.776 54.768 55.896 ;
     RECT  54.755 67.824 54.785 67.848 ;
     RECT  54.544 75.792 54.785 75.864 ;
     RECT  54.544 25.008 54.796 29.592 ;
     RECT  54.755 48.432 54.803 49.368 ;
     RECT  54.755 57.024 54.803 57.144 ;
     RECT  54.785 75.84 54.803 75.864 ;
     RECT  54.768 55.872 54.821 55.896 ;
     RECT  54.803 57.12 54.893 57.144 ;
     RECT  54.755 72.96 54.995 72.984 ;
     RECT  54.796 27.168 55.073 29.592 ;
     RECT  54.544 77.52 55.073 82.008 ;
     RECT  55.073 27.168 55.109 28.44 ;
     RECT  54.544 42.72 55.109 43.128 ;
     RECT  55.073 29.568 55.145 29.592 ;
     RECT  54.544 60.864 55.181 60.888 ;
     RECT  55.109 42.72 55.289 42.744 ;
     RECT  54.544 38.448 55.331 39.48 ;
     RECT  54.544 63.792 55.469 63.816 ;
     RECT  55.073 77.52 55.475 81.96 ;
     RECT  54.544 34.368 55.525 34.392 ;
     RECT  54.796 25.008 55.571 25.992 ;
     RECT  55.475 77.52 55.571 77.544 ;
     RECT  55.331 38.448 55.577 39.24 ;
     RECT  54.803 48.432 55.577 48.456 ;
     RECT  55.525 34.368 55.612 35.4 ;
     RECT  54.544 65.616 55.685 65.64 ;
     RECT  54.544 21.504 55.753 22.2 ;
     RECT  55.612 34.368 55.859 34.872 ;
     RECT  55.609 43.92 55.859 43.944 ;
     RECT  55.859 34.368 55.901 34.824 ;
     RECT  55.861 73.392 55.948 73.416 ;
     RECT  55.753 21.504 56.005 22.248 ;
     RECT  56.005 21.504 56.053 22.44 ;
     RECT  54.544 45.168 56.077 45.192 ;
     RECT  56.053 21.504 56.14 22.488 ;
     RECT  56.077 44.976 56.161 45.192 ;
     RECT  55.109 27.168 56.185 28.152 ;
     RECT  56.14 21.504 56.189 22.44 ;
     RECT  56.108 57.456 56.195 57.48 ;
     RECT  54.544 41.136 56.245 41.64 ;
     RECT  55.901 34.368 56.297 34.392 ;
     RECT  56.245 41.04 56.332 41.64 ;
     RECT  56.185 27.168 56.435 29.016 ;
     RECT  56.357 33.792 56.441 33.816 ;
     RECT  56.54 76.992 56.627 77.016 ;
     RECT  55.577 38.688 56.729 39.24 ;
     RECT  56.161 45.168 56.873 45.192 ;
     RECT  56.828 33.024 56.915 33.048 ;
     RECT  54.544 36.528 56.945 36.6 ;
     RECT  56.725 47.808 57.011 47.832 ;
     RECT  56.833 60.288 57.011 60.312 ;
     RECT  56.917 49.008 57.017 49.032 ;
     RECT  56.869 72.336 57.017 72.36 ;
     RECT  56.389 56.976 57.089 57 ;
     RECT  57.013 43.68 57.1 43.704 ;
     RECT  56.332 41.136 57.109 41.64 ;
     RECT  54.544 30.576 57.157 31.464 ;
     RECT  56.189 21.504 57.197 22.248 ;
     RECT  57.164 44.88 57.251 44.904 ;
     RECT  57.109 41.136 57.305 42.12 ;
     RECT  56.773 64.368 57.305 64.392 ;
     RECT  56.729 38.688 57.437 38.952 ;
     RECT  57.157 30.576 57.443 31.656 ;
     RECT  57.437 38.16 57.481 38.952 ;
     RECT  55.475 78.912 57.485 81.96 ;
     RECT  55.571 25.968 57.521 25.992 ;
     RECT  57.481 37.632 57.521 38.952 ;
     RECT  57.013 73.44 57.539 73.464 ;
     RECT  56.677 55.824 57.541 55.848 ;
     RECT  57.521 37.632 57.587 37.656 ;
     RECT  57.589 77.568 57.676 77.592 ;
     RECT  56.435 27.168 57.701 28.152 ;
     RECT  57.692 19.344 57.779 19.368 ;
     RECT  57.485 78.912 57.779 81.912 ;
     RECT  54.544 17.328 57.781 17.88 ;
     RECT  57.74 69.36 57.827 69.384 ;
     RECT  57.781 16.944 57.868 17.88 ;
     RECT  57.788 59.616 57.875 59.64 ;
     RECT  57.637 52.416 57.913 52.44 ;
     RECT  57.829 54.576 57.953 54.6 ;
     RECT  57.877 57.6 57.964 57.624 ;
     RECT  57.541 55.824 58.057 56.424 ;
     RECT  58.057 54.672 58.061 56.424 ;
     RECT  57.913 52.416 58.115 53.016 ;
     RECT  58.061 54.672 58.141 54.888 ;
     RECT  57.829 25.152 58.163 25.176 ;
     RECT  58.021 61.536 58.165 61.56 ;
     RECT  57.779 78.912 58.165 78.936 ;
     RECT  58.093 65.664 58.211 65.688 ;
     RECT  58.124 71.04 58.211 71.064 ;
     RECT  57.197 21.504 58.213 22.2 ;
     RECT  57.868 17.328 58.241 17.88 ;
     RECT  58.115 52.416 58.349 52.44 ;
     RECT  58.345 75.84 58.357 75.864 ;
     RECT  58.213 21.12 58.385 22.2 ;
     RECT  57.701 27.168 58.405 27.672 ;
     RECT  58.261 48.192 58.405 48.216 ;
     RECT  58.061 56.304 58.421 56.424 ;
     RECT  58.165 61.536 58.421 61.608 ;
     RECT  58.357 75.12 58.444 75.864 ;
     RECT  58.405 26.736 58.492 27.672 ;
     RECT  58.421 61.536 58.493 61.56 ;
     RECT  58.444 75.84 58.547 75.864 ;
     RECT  56.945 36.528 58.693 36.552 ;
     RECT  58.117 51.264 58.741 51.288 ;
     RECT  57.779 80.112 58.777 81.912 ;
     RECT  57.521 38.688 58.844 38.952 ;
     RECT  58.885 53.568 59.269 53.592 ;
     RECT  58.981 59.184 59.269 59.208 ;
     RECT  58.741 67.776 59.365 67.8 ;
     RECT  57.443 30.576 59.413 31.464 ;
     RECT  59.269 59.184 59.461 59.832 ;
     RECT  59.173 60.96 59.461 60.984 ;
     RECT  54.544 4.944 59.648 5.544 ;
     RECT  54.544 7.728 59.648 7.752 ;
     RECT  59.425 13.056 59.648 13.08 ;
     RECT  58.241 17.76 59.648 17.88 ;
     RECT  58.385 21.504 59.648 22.2 ;
     RECT  54.713 23.568 59.648 23.592 ;
     RECT  59.317 25.152 59.648 25.176 ;
     RECT  58.492 27.168 59.648 27.672 ;
     RECT  59.413 30.576 59.648 31.512 ;
     RECT  59.029 35.52 59.648 35.544 ;
     RECT  58.693 36.528 59.648 37.464 ;
     RECT  58.844 38.688 59.648 39.912 ;
     RECT  57.305 41.136 59.648 41.64 ;
     RECT  58.405 48.192 59.648 49.032 ;
     RECT  58.741 51.264 59.648 51.576 ;
     RECT  59.269 52.992 59.648 53.592 ;
     RECT  58.141 54.672 59.648 54.696 ;
     RECT  58.421 56.304 59.648 56.328 ;
     RECT  59.461 59.184 59.648 60.984 ;
     RECT  59.365 67.776 59.648 68.232 ;
     RECT  59.036 72.912 59.648 72.936 ;
     RECT  59.057 77.472 59.648 77.496 ;
     RECT  58.165 78.672 59.648 78.936 ;
     RECT  58.777 80.064 59.648 81.912 ;
     RECT  59.648 0.528 59.752 81.912 ;
     RECT  59.752 0.798 59.944 81.912 ;
     RECT  59.944 27.168 60.005 27.672 ;
     RECT  59.944 60.576 60.005 60.6 ;
     RECT  59.944 48.192 60.041 48.216 ;
     RECT  59.944 64.416 60.077 64.44 ;
     RECT  59.944 40.416 60.083 41.16 ;
     RECT  59.944 46.464 60.083 46.488 ;
     RECT  59.944 65.664 60.083 66.12 ;
     RECT  59.944 17.856 60.131 19.512 ;
     RECT  59.944 55.104 60.131 55.128 ;
     RECT  59.944 80.256 60.217 81.912 ;
     RECT  60.217 80.256 60.275 81.96 ;
     RECT  59.944 14.112 60.419 14.136 ;
     RECT  60.131 17.856 60.419 18.888 ;
     RECT  59.944 25.2 60.437 25.224 ;
     RECT  59.944 43.584 60.437 43.608 ;
     RECT  59.944 67.776 60.445 68.232 ;
     RECT  59.944 71.808 60.473 71.832 ;
     RECT  59.944 7.728 60.581 7.944 ;
     RECT  59.944 36.528 60.653 36.552 ;
     RECT  59.944 56.304 60.653 56.424 ;
     RECT  60.653 56.304 60.689 56.328 ;
     RECT  60.445 68.208 60.725 68.232 ;
     RECT  59.944 35.52 60.797 35.544 ;
     RECT  59.944 49.584 60.797 50.568 ;
     RECT  59.944 75.12 60.899 75.144 ;
     RECT  59.944 76.992 60.913 77.016 ;
     RECT  60.083 66 60.941 66.12 ;
     RECT  60.941 66 60.977 66.024 ;
     RECT  59.944 78.336 60.997 78.936 ;
     RECT  59.944 21.504 61.004 22.824 ;
     RECT  60.956 54.672 61.043 54.696 ;
     RECT  60.973 42.768 61.057 42.84 ;
     RECT  61.004 21.504 61.091 23.016 ;
     RECT  61.057 42.816 61.165 42.84 ;
     RECT  61.196 16.416 61.283 16.44 ;
     RECT  61.237 14.352 61.324 14.376 ;
     RECT  61.261 64.368 61.475 64.392 ;
     RECT  60.797 49.584 61.553 49.944 ;
     RECT  59.944 38.928 61.717 38.952 ;
     RECT  61.676 56.112 61.763 56.136 ;
     RECT  61.717 38.928 61.804 39.912 ;
     RECT  61.724 60.672 61.811 60.696 ;
     RECT  60.973 76.944 61.811 76.968 ;
     RECT  59.944 58.704 61.813 58.728 ;
     RECT  61.093 70.08 61.841 70.104 ;
     RECT  61.813 58.704 61.859 59.064 ;
     RECT  61.859 59.04 61.861 59.064 ;
     RECT  61.861 59.04 61.9 59.256 ;
     RECT  60.275 80.64 61.945 81.96 ;
     RECT  60.083 41.136 61.949 41.16 ;
     RECT  61.945 80.64 61.981 82.008 ;
     RECT  59.944 30.576 62.012 31.464 ;
     RECT  62.012 19.2 62.017 19.224 ;
     RECT  61.477 51.264 62.017 51.288 ;
     RECT  60.997 78.048 62.053 78.936 ;
     RECT  62.012 29.856 62.099 31.464 ;
     RECT  62.012 67.536 62.099 67.56 ;
     RECT  62.017 19.2 62.101 19.32 ;
     RECT  62.053 78 62.137 78.936 ;
     RECT  62.017 50.688 62.147 51.288 ;
     RECT  61.091 21.504 62.201 22.824 ;
     RECT  62.149 23.856 62.236 23.88 ;
     RECT  62.156 66.192 62.243 66.216 ;
     RECT  61.957 52.992 62.341 53.016 ;
     RECT  61.553 49.584 62.413 49.608 ;
     RECT  62.348 76.992 62.435 77.016 ;
     RECT  62.377 13.008 62.449 13.032 ;
     RECT  62.437 68.352 62.485 68.376 ;
     RECT  62.449 13.008 62.521 13.08 ;
     RECT  62.437 56.64 62.524 56.664 ;
     RECT  62.377 75.264 62.54 75.288 ;
     RECT  60.419 17.856 62.561 18.168 ;
     RECT  62.101 19.2 62.597 19.224 ;
     RECT  60.005 27.6 62.597 27.672 ;
     RECT  62.54 75.264 62.627 75.384 ;
     RECT  59.944 62.736 62.633 62.76 ;
     RECT  62.137 78.336 62.665 78.936 ;
     RECT  61.981 80.064 62.665 82.008 ;
     RECT  62.521 12.576 62.675 13.08 ;
     RECT  62.413 49.248 62.675 49.608 ;
     RECT  62.675 12.576 62.705 12.84 ;
     RECT  62.245 47.904 62.705 47.928 ;
     RECT  62.665 78.336 62.741 82.008 ;
     RECT  62.741 78.432 62.819 82.008 ;
     RECT  62.341 52.704 62.821 53.016 ;
     RECT  62.485 68.352 62.921 68.952 ;
     RECT  62.413 46.8 62.972 46.824 ;
     RECT  62.972 46.8 63.029 46.92 ;
     RECT  63.029 46.896 63.059 46.92 ;
     RECT  61.9 59.184 63.068 59.256 ;
     RECT  62.773 72.864 63.137 72.888 ;
     RECT  63.068 59.184 63.155 59.736 ;
     RECT  62.627 75.264 63.155 75.288 ;
     RECT  62.147 51.264 63.173 51.288 ;
     RECT  62.725 25.152 63.245 25.176 ;
     RECT  62.705 12.816 63.251 12.84 ;
     RECT  63.155 59.184 63.251 59.448 ;
     RECT  62.725 65.52 63.253 65.544 ;
     RECT  63.251 59.184 63.353 59.256 ;
     RECT  63.253 64.944 63.461 65.544 ;
     RECT  63.353 59.184 63.569 59.208 ;
     RECT  62.821 52.704 63.596 53.064 ;
     RECT  63.493 60.432 63.601 60.456 ;
     RECT  63.277 14.544 63.605 14.568 ;
     RECT  63.596 52.464 63.683 53.064 ;
     RECT  63.601 60.432 63.745 60.792 ;
     RECT  62.099 30.576 63.749 31.464 ;
     RECT  63.709 19.2 63.827 19.224 ;
     RECT  63.313 70.8 63.827 70.824 ;
     RECT  63.683 52.704 63.853 53.064 ;
     RECT  62.819 78.432 63.853 78.936 ;
     RECT  62.819 80.064 63.853 82.008 ;
     RECT  62.597 27.648 63.884 27.672 ;
     RECT  61.804 38.928 63.884 38.952 ;
     RECT  62.201 21.504 63.893 22.2 ;
     RECT  62.149 55.248 63.961 55.272 ;
     RECT  63.884 27.648 63.971 27.768 ;
     RECT  63.884 38.928 63.971 39.912 ;
     RECT  63.853 52.704 64.019 53.544 ;
     RECT  63.961 54.816 64.045 55.272 ;
     RECT  63.997 23.568 64.081 23.592 ;
     RECT  62.921 68.352 64.309 68.376 ;
     RECT  63.745 60.432 64.405 60.984 ;
     RECT  64.405 60.432 64.453 61.56 ;
     RECT  63.853 78.432 64.453 82.008 ;
     RECT  64.453 59.616 64.556 61.56 ;
     RECT  63.461 65.52 64.645 65.544 ;
     RECT  64.309 67.776 64.741 68.376 ;
     RECT  63.893 21.504 64.897 21.528 ;
     RECT  63.971 27.648 64.933 27.672 ;
     RECT  59.944 4.944 65.048 5.544 ;
     RECT  60.581 7.728 65.048 7.752 ;
     RECT  62.561 17.856 65.048 17.88 ;
     RECT  64.897 21.408 65.048 21.528 ;
     RECT  64.933 27.648 65.048 27.816 ;
     RECT  64.837 29.376 65.048 29.4 ;
     RECT  63.749 30.576 65.048 31.368 ;
     RECT  63.971 38.928 65.048 38.952 ;
     RECT  62.675 49.584 65.048 49.608 ;
     RECT  64.019 52.704 65.048 53.064 ;
     RECT  64.045 55.248 65.048 55.272 ;
     RECT  64.556 59.616 65.048 62.424 ;
     RECT  64.645 65.232 65.048 65.544 ;
     RECT  64.741 67.68 65.048 68.376 ;
     RECT  63.973 69.504 65.048 69.528 ;
     RECT  64.652 72.624 65.048 72.648 ;
     RECT  64.22 76.896 65.048 76.92 ;
     RECT  64.453 78.096 65.048 82.008 ;
     RECT  65.048 0.528 65.152 82.008 ;
     RECT  65.152 0.798 65.344 82.008 ;
     RECT  65.344 49.2 65.459 49.992 ;
     RECT  65.344 66.576 65.507 66.696 ;
     RECT  65.507 66.672 65.513 66.696 ;
     RECT  65.344 21.12 65.555 21.528 ;
     RECT  65.344 25.728 65.555 25.752 ;
     RECT  65.459 49.536 65.557 49.992 ;
     RECT  65.344 53.568 65.585 55.272 ;
     RECT  65.344 62.208 65.665 62.424 ;
     RECT  65.344 70.656 65.692 70.68 ;
     RECT  65.344 78.432 65.729 82.008 ;
     RECT  65.344 7.68 65.873 7.752 ;
     RECT  65.344 72 65.884 72.216 ;
     RECT  65.884 72.192 65.891 72.216 ;
     RECT  65.344 67.68 65.909 68.952 ;
     RECT  65.729 80.064 65.939 82.008 ;
     RECT  65.344 60.336 65.945 61.128 ;
     RECT  65.585 54.048 65.981 55.272 ;
     RECT  65.945 60.96 66.125 61.128 ;
     RECT  65.557 49.536 66.161 49.56 ;
     RECT  65.665 62.208 66.179 62.232 ;
     RECT  65.344 74.688 66.197 75.288 ;
     RECT  65.981 54.048 66.205 54.072 ;
     RECT  65.344 30.576 66.227 31.272 ;
     RECT  65.344 58.656 66.269 59.208 ;
     RECT  66.269 58.752 66.275 59.208 ;
     RECT  65.344 57.6 66.341 57.624 ;
     RECT  65.981 55.248 66.38 55.272 ;
     RECT  65.344 47.28 66.46 47.304 ;
     RECT  66.38 55.248 66.467 56.232 ;
     RECT  65.344 65.232 66.565 65.256 ;
     RECT  65.909 68.16 66.709 68.952 ;
     RECT  66.197 75.264 66.757 75.288 ;
     RECT  66.697 62.64 66.781 62.664 ;
     RECT  66.757 26.112 66.845 26.136 ;
     RECT  66.125 60.96 66.845 60.984 ;
     RECT  66.565 65.232 66.845 66.168 ;
     RECT  65.344 17.856 66.913 17.88 ;
     RECT  66.733 72.336 66.917 72.36 ;
     RECT  66.769 76.896 66.917 76.92 ;
     RECT  66.908 23.76 66.995 23.784 ;
     RECT  66.757 75.264 67.093 75.432 ;
     RECT  66.709 68.16 67.133 69.864 ;
     RECT  65.344 27.648 67.201 27.672 ;
     RECT  67.057 66.768 67.237 66.792 ;
     RECT  67.133 68.16 67.237 69 ;
     RECT  65.729 78.432 67.237 78.984 ;
     RECT  65.939 80.4 67.237 82.008 ;
     RECT  67.093 75.264 67.241 76.392 ;
     RECT  66.913 17.856 67.283 18.744 ;
     RECT  67.201 27.312 67.285 27.672 ;
     RECT  67.229 40.56 67.313 40.584 ;
     RECT  66.467 55.248 67.313 55.848 ;
     RECT  67.237 78.432 67.379 82.008 ;
     RECT  66.227 30.576 67.457 30.6 ;
     RECT  66.275 58.8 67.525 59.208 ;
     RECT  65.555 21.504 67.673 21.528 ;
     RECT  67.589 34.992 67.673 35.016 ;
     RECT  67.313 55.824 67.781 55.848 ;
     RECT  67.241 75.264 67.813 75.288 ;
     RECT  67.237 66.768 67.817 69 ;
     RECT  67.525 58.656 67.849 59.208 ;
     RECT  67.772 37.584 67.859 37.608 ;
     RECT  67.849 58.656 67.889 59.304 ;
     RECT  67.817 66.768 67.889 68.376 ;
     RECT  67.889 58.896 67.933 59.304 ;
     RECT  67.861 62.016 67.948 62.04 ;
     RECT  67.964 64.176 68.051 64.2 ;
     RECT  67.889 66.768 68.065 67.128 ;
     RECT  67.379 78.432 68.065 79.848 ;
     RECT  67.241 76.368 68.147 76.392 ;
     RECT  68.065 66.72 68.177 67.128 ;
     RECT  67.933 58.896 68.249 58.92 ;
     RECT  67.813 75.216 68.285 75.288 ;
     RECT  68.204 56.688 68.291 56.712 ;
     RECT  67.621 51.264 68.321 51.288 ;
     RECT  68.273 63.216 68.357 63.24 ;
     RECT  68.293 29.76 68.38 29.784 ;
     RECT  67.283 17.856 68.387 18.696 ;
     RECT  68.177 66.72 68.429 67.032 ;
     RECT  68.197 73.344 68.461 73.368 ;
     RECT  68.065 78.144 68.497 79.848 ;
     RECT  68.429 66.768 68.609 67.032 ;
     RECT  68.609 67.008 68.645 67.032 ;
     RECT  67.889 68.16 68.645 68.376 ;
     RECT  68.485 76.464 68.717 76.92 ;
     RECT  68.461 48.816 68.723 48.84 ;
     RECT  68.636 50.016 68.723 50.04 ;
     RECT  68.749 29.088 68.833 29.544 ;
     RECT  68.828 61.2 68.915 61.224 ;
     RECT  68.645 68.16 68.956 68.328 ;
     RECT  68.461 72.384 68.963 73.368 ;
     RECT  68.717 76.464 68.963 76.488 ;
     RECT  67.285 27.648 68.965 27.672 ;
     RECT  68.497 78.096 68.965 79.848 ;
     RECT  67.379 81.168 68.965 82.008 ;
     RECT  66.845 65.232 69.005 65.256 ;
     RECT  68.833 29.52 69.049 29.544 ;
     RECT  68.972 52.944 69.059 52.968 ;
     RECT  65.344 38.928 69.077 38.952 ;
     RECT  68.965 26.496 69.145 27.672 ;
     RECT  68.561 54.672 69.205 54.696 ;
     RECT  68.965 19.44 69.221 19.464 ;
     RECT  69.145 26.256 69.229 27.672 ;
     RECT  68.285 75.264 69.289 75.288 ;
     RECT  69.229 26.496 69.293 27.672 ;
     RECT  68.965 78.096 69.395 82.008 ;
     RECT  69.205 54.528 69.541 54.696 ;
     RECT  68.773 47.904 69.901 47.928 ;
     RECT  69.541 54.528 70.021 54.936 ;
     RECT  70.117 30.576 70.153 30.6 ;
     RECT  68.963 72.816 70.261 73.368 ;
     RECT  68.956 68.16 70.309 68.184 ;
     RECT  70.117 2.736 70.448 2.76 ;
     RECT  65.344 4.944 70.448 5.544 ;
     RECT  65.873 7.728 70.448 7.752 ;
     RECT  66.913 12.288 70.448 12.312 ;
     RECT  68.387 17.856 70.448 17.88 ;
     RECT  70.261 19.248 70.448 19.272 ;
     RECT  69.293 26.832 70.448 27.672 ;
     RECT  70.153 30.24 70.448 30.6 ;
     RECT  69.001 40.608 70.448 40.632 ;
     RECT  69.901 47.136 70.448 47.928 ;
     RECT  70.225 52.992 70.448 53.016 ;
     RECT  70.021 54.096 70.448 54.936 ;
     RECT  69.061 58.368 70.448 58.392 ;
     RECT  70.309 59.808 70.448 59.832 ;
     RECT  70.076 64.416 70.448 64.44 ;
     RECT  70.309 68.16 70.448 68.28 ;
     RECT  70.309 70.656 70.448 70.68 ;
     RECT  70.261 72.288 70.448 73.56 ;
     RECT  69.289 75.264 70.448 75.96 ;
     RECT  69.395 78.144 70.448 82.008 ;
     RECT  70.448 0.528 70.552 82.008 ;
     RECT  70.552 0.798 70.744 82.008 ;
     RECT  70.744 64.416 70.769 64.824 ;
     RECT  70.744 7.68 70.877 7.752 ;
     RECT  70.744 13.872 70.883 14.136 ;
     RECT  70.744 68.16 70.883 69.48 ;
     RECT  70.744 70.656 70.883 72.024 ;
     RECT  70.744 73.344 70.883 74.088 ;
     RECT  70.744 24.48 70.913 25.224 ;
     RECT  70.883 14.112 70.921 14.136 ;
     RECT  70.744 48.912 70.921 48.936 ;
     RECT  70.744 18.72 70.949 18.792 ;
     RECT  70.744 58.368 70.949 58.392 ;
     RECT  70.883 68.16 70.985 68.952 ;
     RECT  70.883 73.344 70.985 73.56 ;
     RECT  70.883 70.656 71.021 70.68 ;
     RECT  70.883 71.808 71.021 72.024 ;
     RECT  70.744 27.648 71.129 27.672 ;
     RECT  70.744 66.048 71.165 66.504 ;
     RECT  70.744 37.008 71.201 37.608 ;
     RECT  70.949 18.72 71.267 18.744 ;
     RECT  70.913 24.48 71.267 25.176 ;
     RECT  70.744 75.936 71.315 76.728 ;
     RECT  70.744 52.512 71.345 52.776 ;
     RECT  70.744 56.88 71.459 56.904 ;
     RECT  70.985 73.344 71.525 73.368 ;
     RECT  71.315 76.704 71.525 76.728 ;
     RECT  70.769 64.8 71.597 64.824 ;
     RECT  70.744 41.328 71.651 41.64 ;
     RECT  71.345 52.752 71.705 52.776 ;
     RECT  71.651 41.616 71.713 41.64 ;
     RECT  70.744 11.664 71.797 12.312 ;
     RECT  71.773 60.576 71.797 60.6 ;
     RECT  70.744 62.736 71.813 63.24 ;
     RECT  70.744 78.576 71.845 82.008 ;
     RECT  71.845 74.736 71.929 74.76 ;
     RECT  71.021 71.808 71.941 71.832 ;
     RECT  71.845 77.52 71.957 82.008 ;
     RECT  70.744 50.976 71.993 51 ;
     RECT  71.941 71.616 72.028 71.832 ;
     RECT  71.797 60.576 72.101 61.416 ;
     RECT  71.749 64.368 72.137 64.392 ;
     RECT  71.797 11.664 72.209 12.552 ;
     RECT  71.813 62.736 72.353 62.76 ;
     RECT  71.881 55.008 72.385 55.032 ;
     RECT  71.201 37.008 72.428 37.032 ;
     RECT  72.428 37.008 72.515 37.272 ;
     RECT  72.449 35.856 72.533 35.88 ;
     RECT  72.373 19.488 72.601 19.512 ;
     RECT  72.028 71.664 72.605 71.832 ;
     RECT  72.493 46.128 72.611 46.152 ;
     RECT  72.524 49.92 72.611 49.944 ;
     RECT  72.593 73.488 72.677 73.512 ;
     RECT  72.601 19.44 72.685 19.512 ;
     RECT  72.613 47.856 72.7 47.88 ;
     RECT  72.133 56.976 72.713 57 ;
     RECT  71.165 66.048 72.745 66.312 ;
     RECT  72.685 19.488 72.749 19.512 ;
     RECT  72.385 54.96 72.757 55.032 ;
     RECT  72.853 58.992 72.901 59.016 ;
     RECT  72.101 60.576 72.901 60.6 ;
     RECT  72.901 58.992 72.917 60.6 ;
     RECT  72.457 26.736 72.947 26.76 ;
     RECT  72.709 32.304 72.947 32.328 ;
     RECT  72.805 48.48 72.965 48.504 ;
     RECT  72.917 25.632 73.001 25.656 ;
     RECT  72.917 58.944 73.001 60.6 ;
     RECT  73.001 58.992 73.181 60.6 ;
     RECT  73.141 25.44 73.237 25.464 ;
     RECT  72.745 66.048 73.237 67.128 ;
     RECT  70.985 68.928 73.253 68.952 ;
     RECT  72.757 54.96 73.321 55.272 ;
     RECT  73.237 24.864 73.324 25.464 ;
     RECT  72.949 53.088 73.325 53.112 ;
     RECT  73.237 66.048 73.34 67.8 ;
     RECT  73.34 65.28 73.427 67.8 ;
     RECT  71.957 77.52 73.429 81.96 ;
     RECT  73.141 20.592 73.523 20.616 ;
     RECT  73.324 25.44 73.523 25.464 ;
     RECT  72.925 72.912 73.525 72.936 ;
     RECT  73.427 66.048 73.541 67.8 ;
     RECT  73.321 54.96 73.573 55.464 ;
     RECT  73.525 72.816 73.612 72.936 ;
     RECT  73.181 59.088 73.649 60.6 ;
     RECT  73.649 60.144 73.753 60.6 ;
     RECT  73.669 52.512 73.756 52.536 ;
     RECT  73.676 56.88 73.763 56.904 ;
     RECT  73.681 41.04 73.765 41.064 ;
     RECT  73.753 60.144 73.765 60.84 ;
     RECT  73.541 66.048 73.793 67.128 ;
     RECT  72.889 64.08 73.82 64.104 ;
     RECT  73.772 75.552 73.859 75.576 ;
     RECT  72.605 71.664 73.861 71.736 ;
     RECT  73.649 59.088 73.901 59.112 ;
     RECT  73.82 63.216 73.907 64.104 ;
     RECT  73.861 70.752 74.051 71.736 ;
     RECT  73.907 64.08 74.101 64.104 ;
     RECT  74.041 18.432 74.149 18.456 ;
     RECT  74.069 3.312 74.153 3.336 ;
     RECT  73.793 66.048 74.153 66.936 ;
     RECT  73.429 76.608 74.195 81.96 ;
     RECT  74.195 76.608 74.257 76.632 ;
     RECT  74.101 64.08 74.524 64.248 ;
     RECT  74.149 18.432 74.533 18.6 ;
     RECT  74.473 34.464 74.557 34.488 ;
     RECT  73.537 74.016 74.588 74.04 ;
     RECT  70.744 4.656 74.617 5.544 ;
     RECT  73.765 60.144 74.617 61.56 ;
     RECT  74.533 18.384 74.621 18.6 ;
     RECT  74.077 69.696 74.653 69.72 ;
     RECT  73.612 72.912 74.653 72.936 ;
     RECT  74.293 51.84 74.657 51.864 ;
     RECT  74.588 74.016 74.675 74.712 ;
     RECT  74.051 71.616 74.693 71.736 ;
     RECT  74.653 72.816 74.693 72.936 ;
     RECT  74.195 78.336 74.693 81.96 ;
     RECT  73.573 54.96 74.725 55.512 ;
     RECT  74.689 46.992 74.732 47.016 ;
     RECT  74.257 76.464 74.737 76.632 ;
     RECT  74.621 18.576 74.765 18.6 ;
     RECT  74.732 46.8 74.819 47.016 ;
     RECT  74.617 60.144 74.837 62.04 ;
     RECT  74.653 69.696 74.965 69.768 ;
     RECT  74.905 58.992 75.157 59.016 ;
     RECT  75.077 26.88 75.229 26.904 ;
     RECT  74.153 66.048 75.229 66.888 ;
     RECT  74.965 68.784 75.229 69.768 ;
     RECT  74.725 54.96 75.26 56.088 ;
     RECT  74.837 62.016 75.409 62.04 ;
     RECT  75.26 54.576 75.481 56.088 ;
     RECT  75.437 57.072 75.481 57.096 ;
     RECT  74.617 10.608 75.625 10.632 ;
     RECT  74.693 71.616 75.685 71.688 ;
     RECT  75.157 58.656 75.769 59.016 ;
     RECT  74.837 60.144 75.769 60.6 ;
     RECT  74.737 76.512 75.769 76.632 ;
     RECT  74.617 3.936 75.848 5.544 ;
     RECT  70.877 7.728 75.848 7.752 ;
     RECT  74.617 8.976 75.848 9 ;
     RECT  75.625 10.608 75.848 10.68 ;
     RECT  72.209 11.664 75.848 12.312 ;
     RECT  75.193 16.272 75.848 16.296 ;
     RECT  75.733 19.008 75.848 19.272 ;
     RECT  75.769 20.688 75.848 20.712 ;
     RECT  75.229 26.736 75.848 26.904 ;
     RECT  74.819 46.992 75.848 47.016 ;
     RECT  75.253 48.096 75.848 48.12 ;
     RECT  74.917 51.264 75.848 51.288 ;
     RECT  75.356 52.368 75.848 52.392 ;
     RECT  75.397 53.568 75.848 53.592 ;
     RECT  75.481 54.576 75.848 57.096 ;
     RECT  75.769 58.656 75.848 60.6 ;
     RECT  75.409 62.016 75.848 62.184 ;
     RECT  74.524 64.08 75.848 64.104 ;
     RECT  75.229 66.048 75.848 69.768 ;
     RECT  75.685 71.616 75.848 71.736 ;
     RECT  74.693 72.816 75.848 72.84 ;
     RECT  74.675 74.016 75.848 74.376 ;
     RECT  75.769 76.512 75.848 76.824 ;
     RECT  74.693 78.432 75.848 81.96 ;
     RECT  75.848 0.528 75.917 81.96 ;
     RECT  75.917 0.528 75.952 81.864 ;
     RECT  75.952 0.798 76.144 81.864 ;
     RECT  76.144 71.472 76.259 72.84 ;
     RECT  76.144 78.432 76.259 81.864 ;
     RECT  76.144 44.976 76.307 45.432 ;
     RECT  76.144 40.56 76.313 40.584 ;
     RECT  76.259 79.2 76.349 81.864 ;
     RECT  76.144 64.08 76.355 69.768 ;
     RECT  76.144 30 76.421 30.792 ;
     RECT  76.144 47.904 76.421 48.312 ;
     RECT  76.421 30.672 76.457 30.792 ;
     RECT  76.457 30.768 76.529 30.792 ;
     RECT  76.144 34.272 76.529 34.392 ;
     RECT  76.529 34.272 76.931 34.296 ;
     RECT  76.421 48.288 76.931 48.312 ;
     RECT  76.144 52.896 76.931 52.92 ;
     RECT  76.349 79.2 76.931 81.768 ;
     RECT  76.144 54.96 76.961 57.96 ;
     RECT  76.307 45.408 77.02 45.432 ;
     RECT  76.144 36.24 77.069 36.264 ;
     RECT  76.144 20.496 77.137 20.712 ;
     RECT  76.144 14.544 77.281 15.144 ;
     RECT  76.144 16.272 77.281 16.488 ;
     RECT  76.144 58.992 77.317 60.6 ;
     RECT  76.144 62.016 77.317 62.04 ;
     RECT  76.144 26.208 77.42 26.232 ;
     RECT  76.961 57.744 77.425 57.96 ;
     RECT  77.317 58.992 77.425 62.04 ;
     RECT  76.355 66.048 77.461 69.768 ;
     RECT  76.931 79.2 77.461 79.272 ;
     RECT  77.389 32.544 77.473 32.568 ;
     RECT  77.461 2.64 77.497 2.664 ;
     RECT  77.281 14.544 77.497 16.488 ;
     RECT  76.144 76.608 77.497 76.92 ;
     RECT  77.42 26.208 77.501 26.664 ;
     RECT  77.501 26.64 77.507 26.664 ;
     RECT  77.461 65.904 77.533 69.768 ;
     RECT  76.259 71.472 77.533 71.736 ;
     RECT  77.425 57.744 77.569 62.04 ;
     RECT  77.489 32.688 77.573 32.712 ;
     RECT  77.497 76.08 77.609 76.92 ;
     RECT  76.259 72.816 77.713 72.84 ;
     RECT  76.144 74.016 77.713 74.376 ;
     RECT  77.569 57.744 77.756 62.28 ;
     RECT  76.355 64.08 77.756 64.92 ;
     RECT  77.533 65.904 77.785 71.736 ;
     RECT  77.713 72.816 77.785 74.376 ;
     RECT  77.708 30 77.795 30.024 ;
     RECT  77.509 27.84 77.821 27.864 ;
     RECT  77.756 57.744 77.843 64.92 ;
     RECT  77.461 78.96 77.893 79.272 ;
     RECT  76.931 80.256 77.893 81.768 ;
     RECT  77.821 27.408 77.905 27.864 ;
     RECT  77.843 57.744 77.969 62.28 ;
     RECT  76.961 54.96 77.989 56.616 ;
     RECT  77.969 57.744 77.989 60.6 ;
     RECT  77.893 78.96 78.001 81.768 ;
     RECT  77.905 27.84 78.005 27.864 ;
     RECT  77.843 63.312 78.005 64.92 ;
     RECT  76.144 10.608 78.037 12.312 ;
     RECT  77.137 20.352 78.037 20.712 ;
     RECT  77.413 46.704 78.041 46.728 ;
     RECT  76.144 8.976 78.073 9 ;
     RECT  77.641 52.992 78.077 53.016 ;
     RECT  76.144 6.768 78.253 7.752 ;
     RECT  77.609 76.08 78.253 76.824 ;
     RECT  78.037 20.304 78.325 20.712 ;
     RECT  78.277 28.416 78.365 28.44 ;
     RECT  77.785 65.904 78.433 74.376 ;
     RECT  78.253 75.408 78.433 76.824 ;
     RECT  78.085 0.864 78.437 0.888 ;
     RECT  77.497 2.544 78.613 2.664 ;
     RECT  78.037 10.416 78.613 12.312 ;
     RECT  78.253 6.576 78.649 7.752 ;
     RECT  78.073 8.976 78.649 9.288 ;
     RECT  78.613 10.32 78.649 12.312 ;
     RECT  77.497 13.968 78.649 16.488 ;
     RECT  78.073 23.568 78.649 23.592 ;
     RECT  78.433 65.904 78.649 76.824 ;
     RECT  78.001 78 78.649 81.768 ;
     RECT  78.277 52.416 78.653 52.44 ;
     RECT  78.541 38.592 78.659 38.616 ;
     RECT  78.649 6.576 78.685 12.312 ;
     RECT  78.649 13.968 78.685 17.352 ;
     RECT  78.661 49.056 78.748 49.08 ;
     RECT  76.144 3.696 78.865 5.544 ;
     RECT  78.685 6.576 78.865 17.352 ;
     RECT  78.661 36.096 78.905 36.12 ;
     RECT  78.86 46.656 78.947 46.68 ;
     RECT  78.541 25.872 79.153 25.896 ;
     RECT  78.037 24.816 79.189 24.84 ;
     RECT  79.153 25.872 79.189 26.472 ;
     RECT  77.989 54.96 79.189 60.6 ;
     RECT  77.969 61.584 79.189 62.28 ;
     RECT  78.649 65.904 79.217 81.768 ;
     RECT  78.613 1.968 79.225 2.664 ;
     RECT  78.865 3.696 79.225 17.352 ;
     RECT  78.649 23.376 79.225 23.592 ;
     RECT  79.189 24.816 79.225 26.472 ;
     RECT  79.225 23.376 79.261 26.472 ;
     RECT  79.196 48.24 79.283 48.264 ;
     RECT  78.325 19.44 79.369 20.712 ;
     RECT  79.369 19.44 79.513 21.672 ;
     RECT  79.297 53.52 79.532 53.544 ;
     RECT  79.189 54.96 79.549 62.28 ;
     RECT  78.005 63.312 79.549 64.872 ;
     RECT  79.628 46.896 79.715 46.92 ;
     RECT  79.225 1.968 79.801 17.928 ;
     RECT  79.513 19.152 79.801 21.672 ;
     RECT  79.532 52.992 79.813 53.544 ;
     RECT  79.801 0.72 79.837 17.928 ;
     RECT  79.801 19.152 79.837 21.768 ;
     RECT  79.261 23.28 79.837 26.472 ;
     RECT  79.801 40.512 79.885 40.536 ;
     RECT  79.549 54.96 79.909 64.872 ;
     RECT  79.217 65.904 79.909 81.864 ;
     RECT  79.861 44.4 79.948 44.424 ;
     RECT  79.813 52.512 80.201 53.544 ;
     RECT  79.837 0.72 80.341 18.024 ;
     RECT  79.837 19.152 80.341 26.472 ;
     RECT  80.341 0.72 80.377 26.472 ;
     RECT  80.201 52.992 80.38 53.544 ;
     RECT  80.38 53.088 80.389 53.544 ;
     RECT  79.909 54.96 80.389 81.864 ;
     RECT  80.377 50.688 80.461 50.712 ;
     RECT  80.389 53.088 80.461 81.864 ;
     RECT  80.485 51.84 80.569 51.864 ;
     RECT  80.461 53.616 80.597 81.864 ;
     RECT  80.593 49.536 80.677 49.56 ;
     RECT  80.597 53.616 80.812 81.096 ;
     RECT  80.809 50.112 80.915 50.136 ;
     RECT  80.812 53.616 80.921 53.64 ;
     RECT  80.812 54.768 80.921 81.096 ;
     RECT  80.377 0.624 81.036 26.472 ;
     RECT  80.921 54.96 81.036 81.096 ;
     RECT  81.036 5.472 81.065 5.496 ;
     RECT  81.036 55.008 81.065 55.032 ;
     RECT  81.036 66.048 81.065 66.072 ;
     RECT  81.036 74.016 81.065 74.04 ;
     RECT  81.036 76.8 81.065 76.824 ;
    LAYER M5 ;
     RECT  0.24 0.517 0.36 0.787 ;
     RECT  5.64 0.517 5.76 0.787 ;
     RECT  11.04 0.517 11.16 0.787 ;
     RECT  16.44 0.517 16.56 0.787 ;
     RECT  21.84 0.517 21.96 0.787 ;
     RECT  27.24 0.517 27.36 0.787 ;
     RECT  32.64 0.517 32.76 0.787 ;
     RECT  38.04 0.517 38.16 0.787 ;
     RECT  43.44 0.517 43.56 0.787 ;
     RECT  48.84 0.517 48.96 0.787 ;
     RECT  54.24 0.517 54.36 0.787 ;
     RECT  59.64 0.517 59.76 0.787 ;
     RECT  65.04 0.517 65.16 0.787 ;
     RECT  70.44 0.517 70.56 0.787 ;
     RECT  75.84 0.517 75.96 0.787 ;
     RECT  78.096 0.815 78.12 0.899 ;
     RECT  31.296 0.815 31.32 1.093 ;
     RECT  31.248 1.093 31.32 1.381 ;
     RECT  31.2 1.381 31.32 1.465 ;
     RECT  31.248 1.465 31.32 1.475 ;
     RECT  80.4 1.391 80.424 1.475 ;
     RECT  31.248 1.475 31.272 2.027 ;
     RECT  70.44 0.787 70.752 2.725 ;
     RECT  34.224 2.707 34.248 2.735 ;
     RECT  34.224 2.735 34.344 2.795 ;
     RECT  70.128 2.725 70.752 2.809 ;
     RECT  34.32 2.795 34.344 2.819 ;
     RECT  32.64 0.787 32.952 3.301 ;
     RECT  32.64 3.301 33.192 3.385 ;
     RECT  74.112 3.301 74.136 3.385 ;
     RECT  32.64 3.385 33.048 3.435 ;
     RECT  79.728 4.837 79.752 4.885 ;
     RECT  38.04 0.787 38.352 4.895 ;
     RECT  79.728 4.885 79.848 4.921 ;
     RECT  40.416 4.847 40.44 4.931 ;
     RECT  79.824 4.921 79.848 4.971 ;
     RECT  37.92 4.895 38.352 4.979 ;
     RECT  38.04 4.979 38.352 5.011 ;
     RECT  38.04 5.011 38.472 5.099 ;
     RECT  40.464 5.045 40.488 5.133 ;
     RECT  38.04 5.099 38.352 8.341 ;
     RECT  35.952 8.341 35.976 8.373 ;
     RECT  35.952 8.373 36.456 8.427 ;
     RECT  38.04 8.341 38.472 8.427 ;
     RECT  36.432 8.427 36.456 8.461 ;
     RECT  46.08 8.467 46.104 8.555 ;
     RECT  34.176 9.205 34.2 9.253 ;
     RECT  32.64 3.435 32.952 9.637 ;
     RECT  34.176 9.253 34.536 9.637 ;
     RECT  38.04 8.427 38.352 9.717 ;
     RECT  44.832 10.195 44.856 10.283 ;
     RECT  37.92 9.717 38.352 10.515 ;
     RECT  37.92 10.515 38.856 10.603 ;
     RECT  46.416 10.229 46.44 10.795 ;
     RECT  46.128 11.509 46.152 11.593 ;
     RECT  48.84 0.787 49.152 11.637 ;
     RECT  41.136 11.637 41.496 11.725 ;
     RECT  48.84 11.637 50.136 11.725 ;
     RECT  36.72 11.317 36.744 11.749 ;
     RECT  38.04 10.603 38.352 11.749 ;
     RECT  80.4 11.845 80.424 12.037 ;
     RECT  72.336 12.143 72.36 12.191 ;
     RECT  80.352 12.037 80.424 12.203 ;
     RECT  71.808 12.191 72.36 12.227 ;
     RECT  71.808 12.227 71.928 12.843 ;
     RECT  63.216 12.767 63.24 12.851 ;
     RECT  39.648 12.883 39.672 12.971 ;
     RECT  59.64 0.787 59.952 13.045 ;
     RECT  46.752 12.981 46.776 13.069 ;
     RECT  71.904 12.843 71.928 13.099 ;
     RECT  59.52 13.045 59.952 13.129 ;
     RECT  62.64 13.045 62.664 13.129 ;
     RECT  70.44 2.809 70.752 13.843 ;
     RECT  80.4 12.203 80.424 13.931 ;
     RECT  48.84 11.725 49.152 14.035 ;
     RECT  59.64 13.129 59.952 14.101 ;
     RECT  47.28 14.063 47.304 14.147 ;
     RECT  59.64 14.101 60.408 14.187 ;
     RECT  70.44 13.843 70.872 14.187 ;
     RECT  48.84 14.035 49.272 14.251 ;
     RECT  61.248 14.325 61.272 14.413 ;
     RECT  46.272 14.341 46.296 14.443 ;
     RECT  41.616 12.917 41.64 14.627 ;
     RECT  32.64 9.637 34.536 14.629 ;
     RECT  43.44 0.787 43.752 14.739 ;
     RECT  54.24 0.787 54.552 14.739 ;
     RECT  43.44 14.739 44.472 14.827 ;
     RECT  46.704 14.739 46.728 14.827 ;
     RECT  51.312 14.739 51.336 14.827 ;
     RECT  53.76 14.739 54.552 14.827 ;
     RECT  36.72 11.749 38.352 15.123 ;
     RECT  39.984 14.773 40.008 15.123 ;
     RECT  36.72 15.123 40.008 15.211 ;
     RECT  80.4 15.205 80.424 15.289 ;
     RECT  43.44 14.827 43.896 15.491 ;
     RECT  54.24 14.827 54.552 15.989 ;
     RECT  53.28 15.989 54.552 16.259 ;
     RECT  61.248 16.405 61.272 16.491 ;
     RECT  51.12 15.989 51.144 16.499 ;
     RECT  52.464 16.789 52.488 16.875 ;
     RECT  57.792 16.915 57.816 17.003 ;
     RECT  46.8 16.531 46.824 17.123 ;
     RECT  36.72 15.211 38.352 17.317 ;
     RECT  48.84 14.251 49.152 17.589 ;
     RECT  43.44 15.491 43.752 17.653 ;
     RECT  48.72 17.589 49.152 17.677 ;
     RECT  55.824 17.589 56.76 17.677 ;
     RECT  46.176 17.605 46.2 17.707 ;
     RECT  43.44 17.653 43.896 17.989 ;
     RECT  43.248 17.989 43.896 18.181 ;
     RECT  80.4 18.085 80.424 18.181 ;
     RECT  52.704 18.133 52.728 18.219 ;
     RECT  61.008 18.037 61.032 18.219 ;
     RECT  80.352 18.181 80.424 18.277 ;
     RECT  74.544 18.335 74.568 18.421 ;
     RECT  80.352 18.277 80.472 18.475 ;
     RECT  74.064 18.421 74.568 18.505 ;
     RECT  43.2 18.181 43.896 18.565 ;
     RECT  74.16 18.505 74.568 18.565 ;
     RECT  74.16 18.565 74.712 18.667 ;
     RECT  68.352 18.613 68.376 18.707 ;
     RECT  70.44 14.187 70.752 18.709 ;
     RECT  74.16 18.667 74.184 18.731 ;
     RECT  67.248 18.671 67.272 18.755 ;
     RECT  39.984 15.211 40.008 18.757 ;
     RECT  70.44 18.709 71.256 18.795 ;
     RECT  80.4 18.475 80.472 18.799 ;
     RECT  59.64 14.187 59.952 18.805 ;
     RECT  45.552 18.805 45.576 18.899 ;
     RECT  59.64 18.805 60.408 18.899 ;
     RECT  63.888 18.805 63.912 18.933 ;
     RECT  75.84 0.787 76.152 18.997 ;
     RECT  63.792 18.933 63.912 19.051 ;
     RECT  70.44 18.795 70.92 19.051 ;
     RECT  62.064 19.061 62.088 19.189 ;
     RECT  63.792 19.051 63.816 19.235 ;
     RECT  70.44 19.051 70.752 19.237 ;
     RECT  62.064 19.189 62.184 19.273 ;
     RECT  70.32 19.237 70.752 19.321 ;
     RECT  75.744 18.997 76.152 19.321 ;
     RECT  39.888 18.757 40.008 19.333 ;
     RECT  62.064 19.273 62.088 19.371 ;
     RECT  52.32 19.317 52.344 19.405 ;
     RECT  57.744 19.317 57.768 19.405 ;
     RECT  68.976 19.381 69 19.475 ;
     RECT  72.624 19.381 72.648 19.475 ;
     RECT  59.64 18.899 60.12 19.533 ;
     RECT  72.384 19.477 72.408 19.563 ;
     RECT  39.888 19.333 40.392 19.669 ;
     RECT  43.2 18.565 44.136 19.765 ;
     RECT  43.2 19.765 45.096 20.101 ;
     RECT  48.84 17.677 49.152 20.277 ;
     RECT  48.72 20.277 49.152 20.365 ;
     RECT  77.472 20.341 77.496 20.425 ;
     RECT  54.24 16.259 54.552 20.437 ;
     RECT  42.672 20.101 45.096 20.485 ;
     RECT  75.84 19.321 76.152 20.485 ;
     RECT  50.64 19.813 50.664 20.523 ;
     RECT  53.952 20.437 54.552 20.523 ;
     RECT  75.84 20.485 76.968 20.651 ;
     RECT  73.488 20.581 73.512 20.665 ;
     RECT  52.752 20.947 52.776 21.035 ;
     RECT  36.72 17.317 38.904 21.075 ;
     RECT  65.04 0.787 65.352 21.109 ;
     RECT  36.24 21.075 38.904 21.163 ;
     RECT  58.224 21.109 58.248 21.193 ;
     RECT  65.04 21.109 65.544 21.193 ;
     RECT  80.4 18.799 80.424 21.24 ;
     RECT  80.4 21.24 80.472 21.241 ;
     RECT  80.448 21.241 80.472 21.355 ;
     RECT  42.672 20.485 45.912 21.493 ;
     RECT  46.896 21.445 46.92 21.493 ;
     RECT  39.888 19.669 40.824 21.637 ;
     RECT  59.64 19.533 59.952 21.843 ;
     RECT  59.64 21.843 60.072 21.931 ;
     RECT  62.16 21.877 62.184 21.961 ;
     RECT  42.672 21.493 46.92 22.021 ;
     RECT  36.72 21.163 38.904 22.453 ;
     RECT  39.888 21.637 40.872 22.453 ;
     RECT  50.832 22.389 50.856 22.477 ;
     RECT  56.064 22.419 56.088 22.507 ;
     RECT  36.336 22.453 38.904 22.537 ;
     RECT  36.72 22.537 38.904 22.995 ;
     RECT  39.888 22.453 41.352 22.995 ;
     RECT  61.056 22.965 61.08 23.053 ;
     RECT  36.72 22.995 41.352 23.083 ;
     RECT  48.84 20.365 49.152 23.317 ;
     RECT  42.672 22.021 47.688 23.557 ;
     RECT  64.032 23.519 64.056 23.603 ;
     RECT  66.96 23.733 66.984 23.821 ;
     RECT  42.672 23.557 47.736 23.845 ;
     RECT  48.72 23.317 49.152 23.845 ;
     RECT  53.04 23.845 53.064 23.861 ;
     RECT  36.72 23.083 38.904 23.893 ;
     RECT  54.24 20.523 54.552 23.903 ;
     RECT  62.16 23.827 62.184 23.915 ;
     RECT  52.512 23.861 53.064 23.929 ;
     RECT  54.144 23.903 54.552 23.987 ;
     RECT  52.512 23.929 52.536 24.131 ;
     RECT  36.432 23.893 38.904 24.245 ;
     RECT  42.672 23.845 49.152 24.277 ;
     RECT  36.096 24.245 38.904 24.333 ;
     RECT  70.44 19.321 70.752 24.431 ;
     RECT  55.536 24.949 55.56 25.043 ;
     RECT  59.64 21.931 59.952 25.107 ;
     RECT  57.84 25.077 57.864 25.141 ;
     RECT  57.84 25.141 58.152 25.187 ;
     RECT  59.328 25.107 59.952 25.189 ;
     RECT  80.4 23.941 80.424 25.189 ;
     RECT  59.328 25.189 60.408 25.195 ;
     RECT  80.4 25.189 80.472 25.195 ;
     RECT  58.128 25.187 58.152 25.225 ;
     RECT  62.736 25.141 62.76 25.225 ;
     RECT  70.44 24.431 71.256 25.225 ;
     RECT  59.64 25.195 60.408 25.273 ;
     RECT  70.44 25.225 70.872 25.273 ;
     RECT  73.248 24.437 73.272 25.429 ;
     RECT  73.248 25.429 73.512 25.515 ;
     RECT  80.448 25.195 80.472 25.515 ;
     RECT  50.64 25.333 50.664 25.621 ;
     RECT  65.04 21.193 65.352 25.717 ;
     RECT  72.96 25.621 72.984 25.771 ;
     RECT  65.04 25.717 65.544 25.801 ;
     RECT  42.672 24.277 49.272 25.957 ;
     RECT  50.64 25.621 51.336 25.957 ;
     RECT  39.888 23.083 41.352 26.067 ;
     RECT  39.888 26.067 41.64 26.155 ;
     RECT  75.84 20.651 76.152 26.197 ;
     RECT  66.768 26.101 66.792 26.219 ;
     RECT  32.64 14.629 34.68 26.229 ;
     RECT  42.672 25.957 51.336 26.229 ;
     RECT  32.64 26.229 35.304 26.317 ;
     RECT  80.4 26.341 80.424 26.425 ;
     RECT  69.168 26.207 69.192 26.485 ;
     RECT  42.672 26.229 51.96 26.539 ;
     RECT  68.976 26.485 69.192 26.569 ;
     RECT  54.24 23.987 54.552 26.677 ;
     RECT  42.672 26.539 51.336 26.725 ;
     RECT  75.84 26.197 76.392 26.725 ;
     RECT  77.472 26.629 77.496 26.731 ;
     RECT  75.264 26.725 76.392 26.741 ;
     RECT  58.416 26.613 58.44 26.771 ;
     RECT  54.24 26.677 54.744 26.795 ;
     RECT  72.912 26.707 72.936 26.795 ;
     RECT  75.12 26.741 76.392 26.795 ;
     RECT  70.44 25.273 70.752 26.805 ;
     RECT  69.504 26.805 70.872 26.893 ;
     RECT  75.12 26.795 76.152 26.915 ;
     RECT  70.44 26.893 70.872 26.987 ;
     RECT  75.264 26.915 76.152 26.987 ;
     RECT  36.432 24.333 38.904 27.301 ;
     RECT  39.888 26.155 41.544 27.301 ;
     RECT  42.576 26.725 51.336 27.301 ;
     RECT  67.248 27.301 67.272 27.385 ;
     RECT  53.232 27.589 53.256 27.637 ;
     RECT  54.24 26.795 54.552 27.637 ;
     RECT  65.04 25.801 65.352 27.765 ;
     RECT  63.936 27.733 63.96 27.819 ;
     RECT  77.856 27.359 77.88 27.829 ;
     RECT  64.944 27.765 65.352 27.853 ;
     RECT  77.52 27.829 77.88 27.913 ;
     RECT  53.232 27.637 54.552 28.213 ;
     RECT  36.432 27.301 51.336 28.371 ;
     RECT  78.288 28.341 78.312 28.451 ;
     RECT  35.808 28.371 51.336 28.459 ;
     RECT  56.4 28.981 56.424 29.065 ;
     RECT  32.64 26.317 34.68 29.269 ;
     RECT  36.432 28.459 51.336 29.331 ;
     RECT  53.04 28.213 54.552 29.331 ;
     RECT  65.04 27.853 65.352 29.365 ;
     RECT  36.432 29.331 54.552 29.419 ;
     RECT  68.784 29.039 68.808 29.471 ;
     RECT  68.784 29.471 69 29.555 ;
     RECT  68.304 29.685 68.328 29.795 ;
     RECT  64.848 29.365 65.352 29.867 ;
     RECT  62.064 29.813 62.088 29.901 ;
     RECT  75.84 26.987 76.152 29.989 ;
     RECT  77.76 29.941 77.784 30.035 ;
     RECT  70.44 26.987 70.752 30.191 ;
     RECT  70.176 30.191 70.752 30.565 ;
     RECT  70.128 30.565 70.752 30.649 ;
     RECT  75.84 29.989 76.392 30.661 ;
     RECT  61.104 30.773 61.128 30.861 ;
     RECT  75.84 30.661 76.44 30.955 ;
     RECT  57.36 30.901 57.384 30.995 ;
     RECT  65.04 29.867 65.352 31.221 ;
     RECT  32.64 29.269 34.776 31.285 ;
     RECT  65.04 31.221 66.216 31.309 ;
     RECT  65.04 31.309 65.352 31.333 ;
     RECT  64.416 31.333 65.352 31.417 ;
     RECT  59.64 25.273 59.952 31.443 ;
     RECT  57.408 31.285 57.528 31.531 ;
     RECT  59.424 31.443 59.952 31.531 ;
     RECT  61.056 31.285 61.08 31.531 ;
     RECT  57.408 31.531 57.432 31.667 ;
     RECT  72.912 32.245 72.936 32.339 ;
     RECT  77.424 32.495 77.448 32.579 ;
     RECT  77.52 32.677 77.544 32.761 ;
     RECT  56.88 32.979 56.904 33.067 ;
     RECT  56.4 33.781 56.424 33.865 ;
     RECT  53.04 29.419 54.552 34.165 ;
     RECT  75.84 30.955 76.152 34.223 ;
     RECT  75.84 34.223 76.92 34.307 ;
     RECT  75.84 34.307 76.392 34.441 ;
     RECT  74.496 34.415 74.52 34.499 ;
     RECT  55.824 34.597 55.848 34.789 ;
     RECT  36.432 29.419 51.336 34.799 ;
     RECT  52.464 34.165 54.552 34.799 ;
     RECT  55.536 34.789 55.848 34.883 ;
     RECT  67.632 34.933 67.656 35.027 ;
     RECT  32.64 31.285 34.824 35.317 ;
     RECT  55.536 34.883 55.56 35.411 ;
     RECT  59.64 31.531 59.952 35.445 ;
     RECT  59.04 35.445 59.952 35.509 ;
     RECT  59.04 35.509 60.456 35.555 ;
     RECT  59.136 35.555 60.456 35.563 ;
     RECT  59.232 35.563 60.456 35.593 ;
     RECT  78.672 36.085 78.696 36.169 ;
     RECT  75.84 34.441 76.152 36.213 ;
     RECT  75.84 36.213 77.016 36.301 ;
     RECT  70.44 30.649 70.752 37.045 ;
     RECT  70.44 37.045 70.968 37.139 ;
     RECT  72.48 35.845 72.504 37.283 ;
     RECT  59.232 35.593 59.952 37.429 ;
     RECT  58.704 37.429 59.952 37.513 ;
     RECT  70.44 37.139 70.92 37.619 ;
     RECT  67.824 37.557 67.848 37.645 ;
     RECT  57.552 37.429 57.576 37.667 ;
     RECT  57.456 38.111 57.48 38.195 ;
     RECT  78.624 38.581 78.648 38.665 ;
     RECT  36.432 34.799 54.552 39.205 ;
     RECT  32.64 35.317 35.112 39.301 ;
     RECT  36.432 39.205 54.648 39.445 ;
     RECT  36.432 39.445 55.32 39.787 ;
     RECT  59.64 37.513 59.952 39.877 ;
     RECT  61.728 39.733 61.752 39.949 ;
     RECT  63.936 39.733 63.96 39.949 ;
     RECT  58.896 39.877 59.952 40.405 ;
     RECT  36.432 39.787 54.648 40.453 ;
     RECT  58.896 40.405 60.072 40.491 ;
     RECT  75.84 36.301 76.152 40.549 ;
     RECT  36.384 40.453 54.648 40.555 ;
     RECT  70.44 37.619 70.752 40.559 ;
     RECT  79.824 40.501 79.848 40.585 ;
     RECT  67.248 40.501 67.272 40.595 ;
     RECT  75.84 40.549 76.248 40.633 ;
     RECT  69.504 40.559 70.752 40.643 ;
     RECT  73.728 40.991 73.752 41.075 ;
     RECT  56.256 41.013 56.28 41.101 ;
     RECT  70.44 40.643 70.752 41.269 ;
     RECT  70.44 41.269 71.64 41.567 ;
     RECT  36.432 40.555 54.648 41.605 ;
     RECT  70.44 41.567 71.688 41.651 ;
     RECT  57.12 42.085 57.144 42.169 ;
     RECT  61.008 42.741 61.128 42.851 ;
     RECT  59.64 40.491 59.952 43.573 ;
     RECT  59.64 43.573 60.408 43.657 ;
     RECT  57.024 43.669 57.048 43.947 ;
     RECT  55.824 43.871 55.848 43.955 ;
     RECT  75.84 40.633 76.152 44.725 ;
     RECT  79.872 44.389 79.896 44.779 ;
     RECT  57.216 44.597 57.24 44.915 ;
     RECT  56.112 44.965 56.136 45.227 ;
     RECT  75.84 44.725 76.968 45.443 ;
     RECT  72.576 46.117 72.6 46.201 ;
     RECT  59.64 43.657 59.952 46.389 ;
     RECT  59.64 46.389 60.072 46.499 ;
     RECT  78.912 46.611 78.936 46.699 ;
     RECT  74.784 46.773 74.808 46.861 ;
     RECT  79.68 46.867 79.704 46.955 ;
     RECT  70.44 41.651 70.752 47.087 ;
     RECT  70.08 47.087 70.752 47.171 ;
     RECT  65.04 31.417 65.352 47.221 ;
     RECT  63.024 46.885 63.048 47.275 ;
     RECT  65.04 47.221 66.408 47.315 ;
     RECT  36.432 41.605 54.696 47.571 ;
     RECT  75.84 45.443 76.152 47.797 ;
     RECT  56.976 47.797 57 47.881 ;
     RECT  72.624 47.797 72.648 47.891 ;
     RECT  75.84 47.797 76.392 48.085 ;
     RECT  75.264 48.085 76.392 48.171 ;
     RECT  75.84 48.171 76.392 48.277 ;
     RECT  77.424 46.693 77.448 48.277 ;
     RECT  79.248 48.211 79.272 48.299 ;
     RECT  75.84 48.277 77.448 48.363 ;
     RECT  36.432 47.571 54.744 48.421 ;
     RECT  68.784 47.893 68.808 48.805 ;
     RECT  58.272 48.181 58.296 48.885 ;
     RECT  59.64 46.499 59.952 48.885 ;
     RECT  70.44 47.171 70.752 48.885 ;
     RECT  58.272 48.885 59.952 48.973 ;
     RECT  70.44 48.885 70.872 48.973 ;
     RECT  78.672 49.007 78.696 49.091 ;
     RECT  65.04 47.315 65.352 49.171 ;
     RECT  62.256 47.893 62.28 49.199 ;
     RECT  62.256 49.199 62.664 49.283 ;
     RECT  59.64 48.973 59.952 49.573 ;
     RECT  65.04 49.171 65.448 49.573 ;
     RECT  80.64 49.525 80.664 49.609 ;
     RECT  72.816 48.469 72.84 49.909 ;
     RECT  64.176 49.573 65.448 49.957 ;
     RECT  72.576 49.909 72.84 50.027 ;
     RECT  64.176 49.957 65.544 50.041 ;
     RECT  68.688 48.805 68.808 50.091 ;
     RECT  80.88 50.101 80.904 50.185 ;
     RECT  62.256 49.283 62.568 50.643 ;
     RECT  80.4 50.643 80.424 50.731 ;
     RECT  71.808 50.965 71.832 51.051 ;
     RECT  75.84 48.363 76.152 51.219 ;
     RECT  58.272 48.973 58.44 51.253 ;
     RECT  59.64 49.573 60.744 51.253 ;
     RECT  62.112 50.643 62.568 51.253 ;
     RECT  74.928 51.219 76.152 51.307 ;
     RECT  58.128 51.253 58.44 51.541 ;
     RECT  59.64 51.253 62.568 51.541 ;
     RECT  58.128 51.541 62.568 51.627 ;
     RECT  80.496 51.829 80.52 51.913 ;
     RECT  75.84 51.307 76.152 52.357 ;
     RECT  56.928 48.997 56.952 52.405 ;
     RECT  58.128 51.627 58.44 52.405 ;
     RECT  77.424 48.363 77.448 52.405 ;
     RECT  64.176 50.041 65.352 52.435 ;
     RECT  75.408 52.357 76.152 52.459 ;
     RECT  72.816 50.027 72.84 52.469 ;
     RECT  74.304 51.829 74.328 52.469 ;
     RECT  31.2 52.405 31.224 52.489 ;
     RECT  63.648 52.435 65.352 52.523 ;
     RECT  72.816 52.469 74.328 52.557 ;
     RECT  70.44 48.973 70.752 52.853 ;
     RECT  75.84 52.459 76.152 52.885 ;
     RECT  77.424 52.405 78.312 52.885 ;
     RECT  68.784 50.091 68.808 52.917 ;
     RECT  79.824 52.463 80.04 52.947 ;
     RECT  75.84 52.885 78.312 52.971 ;
     RECT  56.928 52.405 58.44 52.981 ;
     RECT  59.64 51.627 62.568 52.981 ;
     RECT  70.44 52.853 70.872 52.981 ;
     RECT  68.784 52.917 69.048 53.005 ;
     RECT  56.928 52.981 62.568 53.029 ;
     RECT  70.32 52.981 70.872 53.035 ;
     RECT  79.584 52.947 80.328 53.039 ;
     RECT  70.32 53.035 70.752 53.065 ;
     RECT  72.816 52.557 72.984 53.123 ;
     RECT  79.584 53.039 80.424 53.471 ;
     RECT  63.984 52.523 65.352 53.555 ;
     RECT  79.344 53.471 80.424 53.555 ;
     RECT  64.176 53.555 65.352 53.557 ;
     RECT  75.84 52.971 76.152 53.557 ;
     RECT  80.16 53.555 80.424 53.581 ;
     RECT  80.4 53.581 80.424 53.907 ;
     RECT  80.4 53.907 80.76 53.995 ;
     RECT  64.176 53.557 65.496 54.037 ;
     RECT  70.44 53.065 70.752 54.085 ;
     RECT  64.176 54.037 66.168 54.123 ;
     RECT  29.904 53.509 29.928 54.431 ;
     RECT  68.784 53.005 68.808 54.453 ;
     RECT  70.032 54.085 70.752 54.453 ;
     RECT  29.904 54.431 30.744 54.515 ;
     RECT  75.408 53.557 76.152 54.547 ;
     RECT  75.312 54.547 76.152 54.635 ;
     RECT  67.632 51.253 67.656 54.661 ;
     RECT  68.784 54.453 70.752 54.661 ;
     RECT  64.176 54.123 65.544 54.767 ;
     RECT  63.984 54.767 65.544 54.851 ;
     RECT  67.632 54.661 70.752 54.925 ;
     RECT  75.408 54.635 76.152 55.029 ;
     RECT  77.424 52.971 78.312 55.029 ;
     RECT  75.408 55.029 78.312 55.139 ;
     RECT  80.4 53.995 80.424 55.221 ;
     RECT  72.816 53.123 72.84 55.237 ;
     RECT  79.872 55.221 80.424 55.285 ;
     RECT  79.872 55.285 80.904 55.309 ;
     RECT  72.768 55.237 72.84 55.403 ;
     RECT  80.4 55.309 80.904 55.523 ;
     RECT  31.392 55.413 31.416 55.667 ;
     RECT  56.928 53.029 62.856 55.813 ;
     RECT  67.632 54.925 68.808 55.813 ;
     RECT  80.4 55.523 80.856 55.955 ;
     RECT  64.176 54.851 65.544 56.181 ;
     RECT  66.96 55.813 68.808 56.181 ;
     RECT  64.176 56.181 68.808 56.269 ;
     RECT  32.64 39.301 35.4 56.389 ;
     RECT  80.592 55.955 80.856 56.427 ;
     RECT  32.544 56.389 35.4 56.693 ;
     RECT  31.92 56.693 35.4 56.781 ;
     RECT  70.032 54.925 70.752 56.851 ;
     RECT  72.816 55.403 72.84 56.855 ;
     RECT  74.304 52.557 74.328 56.855 ;
     RECT  70.032 56.851 71.448 56.939 ;
     RECT  56.688 55.813 62.856 56.965 ;
     RECT  72.816 56.855 74.328 56.965 ;
     RECT  29.904 54.515 29.928 57.013 ;
     RECT  75.408 55.139 76.152 57.013 ;
     RECT  77.424 55.139 78.312 57.013 ;
     RECT  80.592 56.427 80.76 57.013 ;
     RECT  72.144 56.965 74.328 57.067 ;
     RECT  80.4 57.013 80.76 57.107 ;
     RECT  36.432 48.421 55.272 57.427 ;
     RECT  56.4 56.965 62.856 57.427 ;
     RECT  36.432 57.427 62.856 57.515 ;
     RECT  29.904 57.013 30.12 57.973 ;
     RECT  29.904 57.973 30.744 58.057 ;
     RECT  80.88 57.493 80.904 58.069 ;
     RECT  80.64 58.069 80.904 58.165 ;
     RECT  66.96 56.269 68.808 58.293 ;
     RECT  70.032 56.939 70.752 58.293 ;
     RECT  66.96 58.293 70.752 58.357 ;
     RECT  66.96 58.357 70.872 58.441 ;
     RECT  64.176 56.269 65.544 58.741 ;
     RECT  66.96 58.441 68.808 58.741 ;
     RECT  80.4 58.165 80.904 58.795 ;
     RECT  72.144 57.067 72.84 58.933 ;
     RECT  64.176 58.741 68.808 58.987 ;
     RECT  72.144 58.933 72.984 59.017 ;
     RECT  29.904 58.057 30.12 59.221 ;
     RECT  32.544 56.781 35.4 59.221 ;
     RECT  29.904 59.221 30.696 59.231 ;
     RECT  32.496 59.221 35.4 59.307 ;
     RECT  29.904 59.231 31.176 59.315 ;
     RECT  80.976 59.253 81 59.411 ;
     RECT  56.4 57.515 62.856 59.413 ;
     RECT  64.176 58.987 65.544 59.413 ;
     RECT  29.904 59.315 30.744 59.507 ;
     RECT  74.304 57.067 74.328 60.767 ;
     RECT  80.784 60.405 80.808 60.805 ;
     RECT  29.904 59.507 30.696 60.949 ;
     RECT  66.96 58.987 68.808 60.949 ;
     RECT  80.4 60.805 80.808 60.959 ;
     RECT  66.672 60.949 68.808 61.189 ;
     RECT  72.144 59.017 72.936 61.343 ;
     RECT  66.672 61.189 68.904 61.419 ;
     RECT  71.808 61.343 72.936 61.427 ;
     RECT  80.4 60.959 80.904 61.483 ;
     RECT  72.144 61.427 72.936 61.525 ;
     RECT  74.064 60.767 74.328 61.525 ;
     RECT  80.544 61.483 80.904 61.619 ;
     RECT  29.904 60.949 31.224 61.621 ;
     RECT  80.832 61.619 80.904 61.669 ;
     RECT  29.904 61.621 31.32 61.705 ;
     RECT  80.832 61.669 81 62.123 ;
     RECT  56.4 59.413 65.544 62.163 ;
     RECT  66.672 61.419 68.808 62.163 ;
     RECT  56.4 62.163 68.808 62.251 ;
     RECT  80.88 62.123 81 62.251 ;
     RECT  56.4 62.251 65.64 62.473 ;
     RECT  70.032 58.441 70.752 62.709 ;
     RECT  70.032 62.709 70.872 62.797 ;
     RECT  79.824 62.709 79.848 62.797 ;
     RECT  72.144 61.525 74.328 63.109 ;
     RECT  71.76 63.109 74.328 63.275 ;
     RECT  36.432 57.515 55.272 63.733 ;
     RECT  36.432 63.733 55.416 63.827 ;
     RECT  72.144 63.275 74.328 64.053 ;
     RECT  75.408 57.013 78.312 64.053 ;
     RECT  29.904 61.705 31.224 64.357 ;
     RECT  32.544 59.307 35.4 64.357 ;
     RECT  72.144 64.053 78.312 64.357 ;
     RECT  79.728 64.213 79.752 64.357 ;
     RECT  71.76 64.357 79.752 64.403 ;
     RECT  71.76 64.403 79.272 64.427 ;
     RECT  29.904 64.357 35.4 64.441 ;
     RECT  75.408 64.427 79.272 64.441 ;
     RECT  36.432 63.827 55.272 65.567 ;
     RECT  36.432 65.567 55.32 65.651 ;
     RECT  66.672 62.251 68.808 66.133 ;
     RECT  32.544 64.441 35.4 66.165 ;
     RECT  36.432 65.651 55.272 66.165 ;
     RECT  70.032 62.797 70.752 66.229 ;
     RECT  71.76 64.427 74.328 66.229 ;
     RECT  32.496 66.165 55.272 66.253 ;
     RECT  32.544 66.253 55.272 66.371 ;
     RECT  70.032 66.229 74.328 66.515 ;
     RECT  75.408 64.441 78.312 66.579 ;
     RECT  75.408 66.579 78.696 66.667 ;
     RECT  80.688 66.677 80.712 67.091 ;
     RECT  56.4 62.473 65.544 68.149 ;
     RECT  66.576 66.133 68.808 68.149 ;
     RECT  56.4 68.149 68.808 68.277 ;
     RECT  56.4 68.277 68.904 68.365 ;
     RECT  71.76 66.515 74.328 68.755 ;
     RECT  75.408 66.667 78.312 68.755 ;
     RECT  71.76 68.755 78.696 68.843 ;
     RECT  70.032 66.515 70.752 68.917 ;
     RECT  71.76 68.843 74.328 68.917 ;
     RECT  29.904 64.441 31.224 69.267 ;
     RECT  29.904 69.267 31.272 69.355 ;
     RECT  32.544 66.371 35.4 69.941 ;
     RECT  32.496 69.941 35.4 70.029 ;
     RECT  80.88 70.133 80.904 70.451 ;
     RECT  75.408 68.843 78.312 71.285 ;
     RECT  75.408 71.285 78.888 71.373 ;
     RECT  29.904 69.355 31.224 71.941 ;
     RECT  32.544 70.029 35.4 71.941 ;
     RECT  56.4 68.365 68.808 72.309 ;
     RECT  75.408 71.373 78.312 72.373 ;
     RECT  79.536 72.325 79.56 72.373 ;
     RECT  75.408 72.373 79.56 72.563 ;
     RECT  56.4 72.309 68.952 72.805 ;
     RECT  70.032 68.917 74.328 72.805 ;
     RECT  36.432 66.371 55.272 73.381 ;
     RECT  56.4 72.805 74.328 73.381 ;
     RECT  79.536 72.563 79.56 73.477 ;
     RECT  36.432 73.381 74.328 73.515 ;
     RECT  56.4 73.515 74.328 74.101 ;
     RECT  75.408 72.563 78.312 74.101 ;
     RECT  79.536 73.477 80.136 74.101 ;
     RECT  56.4 74.101 80.136 74.185 ;
     RECT  36.432 73.515 55.272 74.62 ;
     RECT  29.904 71.941 35.4 75.157 ;
     RECT  36.384 74.62 55.272 75.157 ;
     RECT  29.904 75.157 55.272 75.243 ;
     RECT  56.4 74.185 78.312 75.541 ;
     RECT  56.4 75.541 78.456 75.627 ;
     RECT  29.904 75.243 35.4 75.781 ;
     RECT  29.04 75.781 35.4 77.461 ;
     RECT  36.432 75.243 55.272 77.509 ;
     RECT  56.4 75.627 78.312 77.509 ;
     RECT  36.432 77.509 78.312 78.069 ;
     RECT  79.536 74.185 80.136 78.069 ;
     RECT  36.432 78.069 80.136 78.157 ;
     RECT  28.944 77.461 35.4 79.189 ;
     RECT  36.432 78.157 78.312 79.391 ;
     RECT  79.344 78.157 80.136 79.391 ;
     RECT  28.848 79.189 35.4 80.293 ;
     RECT  36.432 79.391 80.136 80.293 ;
     RECT  28.848 80.293 80.136 80.389 ;
     RECT  28.848 80.389 80.424 80.917 ;
     RECT  0.24 0.787 0.552 81.023 ;
     RECT  5.64 0.787 5.952 81.023 ;
     RECT  11.04 0.787 11.352 81.023 ;
     RECT  16.44 0.787 16.752 81.023 ;
     RECT  21.84 0.787 22.152 81.023 ;
     RECT  27.24 0.787 27.552 81.023 ;
     RECT  28.752 80.917 80.424 81.061 ;
     RECT  0.432 81.023 0.552 81.293 ;
     RECT  5.832 81.023 5.952 81.293 ;
     RECT  11.232 81.023 11.352 81.293 ;
     RECT  16.632 81.023 16.752 81.293 ;
     RECT  22.032 81.023 22.152 81.293 ;
     RECT  27.432 81.023 27.552 81.293 ;
     RECT  28.752 81.061 80.52 82 ;
    LAYER M6 ;
     RECT  0 54.996 30.709 55.86 ;
     RECT  0 60.396 30.709 61.26 ;
     RECT  0 49.596 31.029 50.46 ;
     RECT  30.709 57.984 31.141 58.016 ;
     RECT  30.709 59.456 31.141 61.26 ;
     RECT  0 76.596 31.141 77.46 ;
     RECT  31.029 49.596 31.211 50.848 ;
     RECT  0 0.996 31.214 1.86 ;
     RECT  31.157 52.416 31.235 52.448 ;
     RECT  31.141 57.984 31.275 61.792 ;
     RECT  31.214 0.996 31.283 2.016 ;
     RECT  31.283 0.996 31.285 1.86 ;
     RECT  30.709 54.464 31.349 55.86 ;
     RECT  31.275 57.984 31.349 61.664 ;
     RECT  0 71.196 31.349 72.06 ;
     RECT  31.141 75.584 31.349 77.46 ;
     RECT  31.349 54.464 31.403 61.664 ;
     RECT  31.349 75.584 31.427 78.112 ;
     RECT  31.349 71.196 31.523 72.864 ;
     RECT  31.403 54.996 31.915 61.664 ;
     RECT  31.237 69.312 32.485 69.344 ;
     RECT  31.523 71.196 32.485 72.06 ;
     RECT  31.915 59.264 32.531 61.664 ;
     RECT  31.861 64.384 32.555 64.416 ;
     RECT  32.485 69.312 32.683 72.06 ;
     RECT  33.013 3.392 33.082 3.424 ;
     RECT  32.683 69.568 33.082 72.06 ;
     RECT  32.531 60.396 33.251 61.664 ;
     RECT  31.915 54.996 33.637 56.736 ;
     RECT  31.427 75.584 33.683 77.46 ;
     RECT  31.285 0.832 34.101 1.86 ;
     RECT  33.157 3.328 34.101 3.36 ;
     RECT  33.637 54.996 34.117 56.928 ;
     RECT  33.082 70.208 34.403 72.06 ;
     RECT  31.211 49.596 34.693 50.46 ;
     RECT  34.693 49.596 34.795 50.72 ;
     RECT  34.117 54.996 34.869 57.568 ;
     RECT  34.869 54.144 34.883 57.568 ;
     RECT  34.261 52.608 34.923 52.64 ;
     RECT  33.683 76.596 35.221 77.46 ;
     RECT  34.069 74.112 35.253 74.144 ;
     RECT  35.221 76.596 35.307 77.6 ;
     RECT  34.883 57.536 35.691 57.568 ;
     RECT  35.253 74.112 35.691 75.232 ;
     RECT  0 6.396 35.941 7.26 ;
     RECT  0 22.596 36.085 23.46 ;
     RECT  35.957 21.12 36.275 21.152 ;
     RECT  36.085 22.596 36.325 24.288 ;
     RECT  35.269 26.24 36.341 26.272 ;
     RECT  0 38.796 36.373 39.66 ;
     RECT  36.325 22.464 36.395 24.288 ;
     RECT  35.691 75.2 36.419 75.232 ;
     RECT  36.341 25.92 36.459 26.272 ;
     RECT  34.883 54.144 36.515 55.86 ;
     RECT  36.459 25.92 36.563 26.016 ;
     RECT  36.563 25.92 36.659 25.952 ;
     RECT  34.117 37.056 36.661 37.088 ;
     RECT  0 27.996 36.725 28.86 ;
     RECT  36.725 27.996 36.803 29.728 ;
     RECT  36.661 36.416 36.843 37.088 ;
     RECT  36.515 54.996 36.974 55.86 ;
     RECT  36.974 54.996 37.043 56.416 ;
     RECT  36.725 68.992 37.091 69.024 ;
     RECT  34.795 49.596 37.794 50.46 ;
     RECT  37.525 46.912 37.813 46.944 ;
     RECT  37.794 48.96 37.813 50.46 ;
     RECT  36.803 27.996 37.861 28.86 ;
     RECT  34.403 71.196 37.861 72.06 ;
     RECT  37.813 46.912 37.867 50.46 ;
     RECT  0 11.796 37.909 12.66 ;
     RECT  37.909 4.928 37.941 4.96 ;
     RECT  37.861 70.72 37.995 72.06 ;
     RECT  37.909 9.728 38.187 12.66 ;
     RECT  36.373 38.796 38.437 40.544 ;
     RECT  37.941 4.928 38.483 5.088 ;
     RECT  35.941 6.396 38.483 8.416 ;
     RECT  36.725 63.872 38.773 63.904 ;
     RECT  38.187 10.56 38.867 12.66 ;
     RECT  38.773 63.872 39.029 63.968 ;
     RECT  39.029 63.232 39.083 63.968 ;
     RECT  37.043 54.996 39.253 55.86 ;
     RECT  0 33.396 39.285 34.26 ;
     RECT  38.437 38.796 39.301 40.608 ;
     RECT  39.253 54.996 39.339 55.968 ;
     RECT  39.278 37.056 39.347 37.088 ;
     RECT  38.725 24.896 39.413 24.928 ;
     RECT  37.861 27.328 39.413 28.86 ;
     RECT  37.867 48.064 39.445 48.096 ;
     RECT  37.867 49.596 39.445 50.46 ;
     RECT  39.413 24.896 39.467 28.86 ;
     RECT  39.445 48.064 39.531 50.46 ;
     RECT  38.867 11.796 39.605 12.66 ;
     RECT  39.013 15.168 39.659 15.2 ;
     RECT  39.301 38.656 39.906 40.608 ;
     RECT  39.605 19.392 39.971 19.424 ;
     RECT  39.906 38.656 39.971 41.056 ;
     RECT  39.971 41.024 39.979 41.056 ;
     RECT  40.069 75.072 40.213 75.104 ;
     RECT  38.483 4.928 40.245 4.96 ;
     RECT  40.213 74.688 40.299 75.104 ;
     RECT  40.245 4.928 40.405 5.088 ;
     RECT  40.405 4.864 40.499 5.088 ;
     RECT  38.821 42.688 40.499 42.72 ;
     RECT  39.083 63.232 40.499 63.264 ;
     RECT  37.813 51.904 40.595 51.936 ;
     RECT  39.531 48.064 40.787 48.096 ;
     RECT  39.605 11.796 41.125 12.96 ;
     RECT  39.285 33.396 41.315 35.36 ;
     RECT  41.125 11.648 41.515 12.96 ;
     RECT  41.515 11.796 41.651 12.96 ;
     RECT  39.467 24.896 41.651 26.144 ;
     RECT  41.315 33.396 42.133 34.26 ;
     RECT  42.741 69.376 42.814 69.408 ;
     RECT  37.995 71.196 42.997 72.06 ;
     RECT  40.299 75.072 43.051 75.104 ;
     RECT  39.531 49.596 43.141 50.46 ;
     RECT  39.971 38.656 43.701 39.66 ;
     RECT  0 44.196 43.765 45.06 ;
     RECT  43.141 49.596 43.819 51.04 ;
     RECT  39.467 27.996 43.829 28.86 ;
     RECT  42.133 32.192 43.829 34.26 ;
     RECT  43.701 38.528 43.829 39.66 ;
     RECT  43.765 43.776 43.829 45.06 ;
     RECT  39.339 54.996 43.829 55.86 ;
     RECT  0 65.796 43.829 66.66 ;
     RECT  41.141 14.4 43.861 14.432 ;
     RECT  43.829 27.996 43.955 29.6 ;
     RECT  43.829 42.752 43.955 45.06 ;
     RECT  43.819 49.596 43.955 50.912 ;
     RECT  43.829 54.72 43.955 55.86 ;
     RECT  43.829 65.796 43.955 66.784 ;
     RECT  43.829 31.36 44.099 34.784 ;
     RECT  44.099 31.872 44.197 34.784 ;
     RECT  42.997 71.196 44.243 72.8 ;
     RECT  43.829 38.464 44.405 39.66 ;
     RECT  43.861 14.4 44.459 15.456 ;
     RECT  44.197 31.872 44.459 35.424 ;
     RECT  44.459 14.4 44.483 14.816 ;
     RECT  44.459 32.896 45.059 34.26 ;
     RECT  43.955 65.796 45.349 66.66 ;
     RECT  0 17.196 45.493 18.06 ;
     RECT  45.493 17.196 45.587 18.848 ;
     RECT  43.317 52.48 45.635 52.512 ;
     RECT  43.955 43.776 45.877 45.06 ;
     RECT  44.243 71.196 45.877 72.48 ;
     RECT  45.349 65.664 45.931 66.66 ;
     RECT  38.483 6.396 46.05 7.26 ;
     RECT  44.821 10.24 46.117 10.272 ;
     RECT  41.651 11.796 46.117 12.66 ;
     RECT  44.405 37.248 46.117 39.66 ;
     RECT  46.05 6.396 46.123 8.544 ;
     RECT  45.877 68.864 46.259 68.896 ;
     RECT  46.117 10.24 46.451 12.66 ;
     RECT  46.451 10.752 46.462 12.66 ;
     RECT  44.483 14.4 46.693 14.432 ;
     RECT  43.955 27.996 46.693 28.86 ;
     RECT  46.693 27.2 46.709 28.86 ;
     RECT  46.462 11.52 46.741 12.66 ;
     RECT  35.307 76.596 46.741 77.46 ;
     RECT  45.587 17.196 46.789 18.06 ;
     RECT  46.741 11.52 46.827 13.024 ;
     RECT  46.741 73.92 46.827 73.952 ;
     RECT  46.693 14.4 46.891 14.816 ;
     RECT  46.789 16.576 46.891 18.06 ;
     RECT  33.251 60.396 46.933 61.26 ;
     RECT  46.709 27.072 47.221 28.86 ;
     RECT  45.931 65.796 47.221 66.66 ;
     RECT  46.891 14.4 47.269 14.432 ;
     RECT  41.651 24.896 47.275 24.928 ;
     RECT  46.117 37.248 47.275 39.968 ;
     RECT  47.275 37.248 47.285 37.28 ;
     RECT  47.221 64.768 47.285 66.66 ;
     RECT  47.285 36.416 47.363 37.28 ;
     RECT  47.285 64.768 47.363 66.784 ;
     RECT  46.741 76.48 47.413 77.46 ;
     RECT  47.363 37.248 47.467 37.28 ;
     RECT  47.275 38.592 47.467 39.968 ;
     RECT  46.693 58.624 47.557 58.656 ;
     RECT  47.413 41.6 47.603 41.632 ;
     RECT  43.955 54.996 47.861 55.86 ;
     RECT  47.557 57.472 47.861 58.656 ;
     RECT  47.861 54.996 47.915 58.656 ;
     RECT  45.877 71.196 47.939 72.608 ;
     RECT  46.933 60.396 48.373 61.408 ;
     RECT  47.221 26.24 48.661 28.86 ;
     RECT  47.915 58.624 48.661 58.656 ;
     RECT  48.373 60.396 48.661 61.6 ;
     RECT  48.661 24.96 48.747 28.86 ;
     RECT  48.661 36.992 48.747 37.024 ;
     RECT  48.661 58.624 48.747 61.6 ;
     RECT  48.709 20.288 48.949 20.32 ;
     RECT  48.747 60.396 48.949 61.6 ;
     RECT  48.661 63.232 48.949 63.264 ;
     RECT  48.949 19.968 49.003 20.32 ;
     RECT  48.949 60.396 49.067 63.264 ;
     RECT  47.269 14.08 49.283 14.432 ;
     RECT  47.363 64.768 49.387 66.66 ;
     RECT  49.387 65.664 49.427 66.66 ;
     RECT  45.877 43.264 49.619 45.06 ;
     RECT  46.827 11.796 50.082 12.66 ;
     RECT  50.082 11.648 50.155 12.66 ;
     RECT  47.915 54.996 50.243 56.928 ;
     RECT  46.891 17.196 50.357 18.06 ;
     RECT  48.747 26.24 50.411 28.86 ;
     RECT  50.101 74.048 50.475 74.08 ;
     RECT  50.357 16.96 50.485 18.06 ;
     RECT  47.317 31.36 50.485 31.392 ;
     RECT  50.485 31.04 50.539 31.392 ;
     RECT  50.539 31.04 50.627 31.072 ;
     RECT  49.003 19.968 50.629 20 ;
     RECT  50.629 19.968 50.675 20.512 ;
     RECT  49.067 60.396 50.677 62.688 ;
     RECT  49.427 65.796 50.677 66.66 ;
     RECT  36.395 22.596 50.821 23.46 ;
     RECT  50.821 22.4 50.869 23.46 ;
     RECT  50.675 20.48 50.923 20.512 ;
     RECT  50.869 22.4 50.923 23.904 ;
     RECT  50.485 16.832 51.109 18.06 ;
     RECT  47.467 38.592 51.125 39.66 ;
     RECT  51.125 38.592 51.179 40.544 ;
     RECT  49.283 14.208 51.301 14.432 ;
     RECT  51.109 16 51.301 18.06 ;
     RECT  51.301 14.208 51.371 18.06 ;
     RECT  50.677 65.796 51.395 67.616 ;
     RECT  47.413 75.392 51.395 77.46 ;
     RECT  47.939 71.196 51.541 72.48 ;
     RECT  51.541 70.976 51.627 72.48 ;
     RECT  51.179 38.796 51.683 40.544 ;
     RECT  51.573 74.688 51.683 74.72 ;
     RECT  50.101 64 51.829 64.032 ;
     RECT  51.829 64 51.875 64.416 ;
     RECT  50.411 26.496 51.925 28.86 ;
     RECT  51.925 26.24 52.194 28.86 ;
     RECT  45.059 33.396 52.213 34.26 ;
     RECT  50.243 54.996 52.213 55.86 ;
     RECT  51.371 16 52.309 18.06 ;
     RECT  51.875 64.384 52.405 64.416 ;
     RECT  51.395 65.796 52.405 67.424 ;
     RECT  52.194 26.24 52.459 29.408 ;
     RECT  52.459 26.24 52.523 28.86 ;
     RECT  51.627 70.976 52.547 72.06 ;
     RECT  52.213 54.996 52.725 56.928 ;
     RECT  52.309 16 52.779 19.36 ;
     RECT  49.619 43.776 53.123 45.06 ;
     RECT  50.677 60.032 53.125 62.688 ;
     RECT  53.125 59.264 53.227 62.688 ;
     RECT  51.395 76.596 53.429 77.46 ;
     RECT  43.955 49.596 53.461 50.46 ;
     RECT  53.461 49.596 53.493 51.616 ;
     RECT  53.429 76.596 53.507 78.304 ;
     RECT  53.493 49.344 53.547 51.616 ;
     RECT  52.725 54.528 53.557 56.928 ;
     RECT  53.557 54.528 53.603 56.992 ;
     RECT  52.213 33.024 53.699 35.104 ;
     RECT  52.779 16 53.749 18.06 ;
     RECT  53.749 14.784 53.803 18.06 ;
     RECT  52.469 20.992 53.813 21.024 ;
     RECT  50.923 22.596 53.813 23.904 ;
     RECT  53.227 60.396 53.813 62.688 ;
     RECT  52.405 64.384 53.813 67.424 ;
     RECT  53.803 14.784 53.818 14.816 ;
     RECT  50.917 53.184 53.843 53.216 ;
     RECT  53.813 20.48 53.867 21.024 ;
     RECT  53.813 60.396 53.867 67.424 ;
     RECT  53.867 20.48 53.987 20.512 ;
     RECT  53.603 54.72 54.035 56.992 ;
     RECT  53.867 63.744 54.123 67.424 ;
     RECT  54.123 65.6 54.133 67.424 ;
     RECT  53.813 22.596 54.179 23.968 ;
     RECT  52.523 26.752 54.755 28.86 ;
     RECT  54.581 47.616 54.755 47.648 ;
     RECT  54.035 54.996 54.755 56.992 ;
     RECT  54.133 65.6 54.755 67.936 ;
     RECT  53.547 49.344 54.803 50.46 ;
     RECT  51.683 38.796 55.285 39.66 ;
     RECT  54.755 65.6 55.331 66.66 ;
     RECT  54.123 63.744 55.427 63.776 ;
     RECT  54.179 22.596 55.541 23.46 ;
     RECT  55.525 24.96 55.541 24.992 ;
     RECT  53.699 33.396 55.571 35.104 ;
     RECT  55.541 24.96 55.595 25.12 ;
     RECT  53.123 44.196 55.813 45.06 ;
     RECT  54.709 73.472 55.907 73.504 ;
     RECT  55.541 22.464 56.099 23.46 ;
     RECT  55.813 43.904 56.101 45.06 ;
     RECT  56.101 43.904 56.171 45.216 ;
     RECT  55.285 38.796 56.226 39.776 ;
     RECT  56.226 38.796 56.299 41.056 ;
     RECT  54.755 27.072 56.373 28.86 ;
     RECT  55.571 33.396 56.869 34.848 ;
     RECT  56.869 33.024 56.885 34.848 ;
     RECT  56.885 33.024 56.939 35.488 ;
     RECT  53.867 60.396 56.965 62.176 ;
     RECT  56.171 43.904 57.077 45.06 ;
     RECT  57.077 42.112 57.155 42.144 ;
     RECT  57.205 31.36 57.326 31.392 ;
     RECT  56.373 27.072 57.333 29.536 ;
     RECT  57.326 30.912 57.395 31.392 ;
     RECT  57.395 31.36 57.397 31.392 ;
     RECT  56.299 38.796 57.397 39.776 ;
     RECT  57.397 38.144 57.451 39.776 ;
     RECT  57.397 31.36 57.466 31.648 ;
     RECT  57.451 38.144 57.491 39.66 ;
     RECT  57.333 26.624 57.525 29.536 ;
     RECT  56.965 60.288 57.525 62.176 ;
     RECT  53.507 76.596 57.525 77.46 ;
     RECT  57.525 26.496 57.579 29.536 ;
     RECT  57.493 73.472 57.579 73.504 ;
     RECT  53.803 17.196 57.733 18.06 ;
     RECT  57.733 17.196 57.762 19.36 ;
     RECT  54.755 54.996 57.762 55.86 ;
     RECT  57.762 54.996 57.781 55.968 ;
     RECT  56.149 57.472 57.781 57.504 ;
     RECT  57.525 60.288 57.829 62.432 ;
     RECT  57.762 16.96 57.835 19.36 ;
     RECT  57.781 54.592 57.835 55.968 ;
     RECT  57.781 57.472 57.835 57.632 ;
     RECT  57.835 57.6 57.845 57.632 ;
     RECT  55.595 25.088 57.875 25.12 ;
     RECT  57.835 54.592 57.875 55.86 ;
     RECT  57.829 59.648 57.899 62.432 ;
     RECT  57.845 57.6 57.923 57.76 ;
     RECT  55.331 65.796 58.165 66.66 ;
     RECT  52.547 71.196 58.165 72.06 ;
     RECT  57.835 17.196 58.219 19.36 ;
     RECT  58.165 21.12 58.259 21.152 ;
     RECT  57.525 75.072 58.403 75.104 ;
     RECT  58.165 65.664 58.421 66.66 ;
     RECT  58.165 71.04 58.421 72.06 ;
     RECT  57.579 26.496 58.451 26.656 ;
     RECT  57.781 69.376 58.475 69.408 ;
     RECT  58.421 71.04 58.475 72.224 ;
     RECT  56.965 47.808 58.722 47.84 ;
     RECT  54.803 49.596 58.722 50.46 ;
     RECT  57.541 37.44 58.739 37.472 ;
     RECT  58.421 65.664 58.787 67.808 ;
     RECT  58.722 47.808 58.795 51.616 ;
     RECT  57.491 38.796 58.885 39.66 ;
     RECT  58.475 71.196 59.077 72.224 ;
     RECT  56.939 33.396 59.125 35.488 ;
     RECT  57.579 27.996 59.189 29.536 ;
     RECT  57.466 31.36 59.189 31.52 ;
     RECT  59.125 33.396 59.189 35.552 ;
     RECT  59.189 33.396 59.267 36.512 ;
     RECT  58.069 52.992 59.315 53.024 ;
     RECT  57.525 76.596 59.363 77.6 ;
     RECT  50.155 11.796 59.509 12.66 ;
     RECT  56.099 22.596 60.037 23.46 ;
     RECT  58.787 65.664 60.083 66.66 ;
     RECT  59.077 71.196 60.083 72.352 ;
     RECT  58.219 17.196 60.085 19.104 ;
     RECT  57.875 54.848 60.085 55.86 ;
     RECT  59.893 46.4 60.094 46.432 ;
     RECT  59.509 11.796 60.373 13.088 ;
     RECT  58.117 25.152 60.373 25.184 ;
     RECT  58.451 26.496 60.373 26.528 ;
     RECT  60.083 65.796 60.373 66.66 ;
     RECT  57.077 43.584 60.419 45.06 ;
     RECT  59.267 33.396 60.467 35.552 ;
     RECT  58.795 49.596 60.467 50.592 ;
     RECT  60.373 65.796 60.715 67.808 ;
     RECT  60.085 17.196 61.035 19.488 ;
     RECT  60.467 33.396 61.035 34.656 ;
     RECT  59.189 27.996 61.091 31.52 ;
     RECT  58.885 38.796 61.163 40.48 ;
     RECT  60.974 42.752 61.163 42.784 ;
     RECT  60.373 11.796 61.173 14.176 ;
     RECT  61.173 11.796 61.227 14.368 ;
     RECT  61.035 17.196 61.237 19.36 ;
     RECT  61.227 14.144 61.355 14.368 ;
     RECT  61.237 16.448 61.355 19.36 ;
     RECT  61.429 64.384 61.493 64.416 ;
     RECT  60.715 65.796 61.493 66.66 ;
     RECT  61.493 64.384 61.547 66.66 ;
     RECT  60.085 54.72 61.717 55.86 ;
     RECT  57.899 60.396 61.742 62.432 ;
     RECT  61.742 60.396 61.749 62.688 ;
     RECT  61.163 38.796 61.763 39.904 ;
     RECT  61.749 59.072 61.811 62.688 ;
     RECT  61.717 54.72 61.813 56.16 ;
     RECT  61.811 59.072 61.813 62.432 ;
     RECT  61.813 54.72 61.867 56.672 ;
     RECT  61.813 58.752 61.882 62.432 ;
     RECT  61.547 64.96 62.053 66.66 ;
     RECT  59.363 76.596 62.053 77.46 ;
     RECT  60.467 49.596 62.101 50.46 ;
     RECT  61.355 17.196 62.123 19.36 ;
     RECT  60.037 21.888 62.133 23.46 ;
     RECT  60.373 25.152 62.133 26.528 ;
     RECT  62.123 17.196 62.195 19.232 ;
     RECT  62.133 21.888 62.195 26.528 ;
     RECT  62.195 22.596 62.206 26.528 ;
     RECT  62.053 64.96 62.251 67.552 ;
     RECT  61.867 54.848 62.483 56.672 ;
     RECT  60.853 75.136 62.562 75.168 ;
     RECT  62.053 76.596 62.562 78.048 ;
     RECT  60.083 71.196 62.581 72.224 ;
     RECT  62.562 75.136 62.581 78.048 ;
     RECT  61.227 11.796 62.629 12.66 ;
     RECT  61.355 14.144 62.629 14.176 ;
     RECT  62.101 49.596 62.629 50.72 ;
     RECT  62.581 75.136 62.635 78.112 ;
     RECT  56.117 81.088 62.645 81.12 ;
     RECT  62.206 25.152 62.771 26.528 ;
     RECT  62.581 71.196 62.819 72.928 ;
     RECT  62.645 79.808 62.819 81.12 ;
     RECT  61.882 59.648 63.205 62.432 ;
     RECT  62.251 64.96 63.299 66.66 ;
     RECT  62.629 49.216 63.723 50.72 ;
     RECT  63.637 52.48 63.723 52.512 ;
     RECT  62.819 71.196 63.781 72.224 ;
     RECT  61.763 38.796 63.906 39.776 ;
     RECT  62.771 25.216 63.925 26.528 ;
     RECT  61.091 27.996 63.925 31.392 ;
     RECT  63.906 38.796 63.925 39.904 ;
     RECT  62.483 54.848 63.973 55.86 ;
     RECT  62.206 22.596 64.021 23.46 ;
     RECT  63.973 53.504 64.043 55.86 ;
     RECT  62.195 17.196 64.053 19.104 ;
     RECT  64.021 22.596 64.107 23.584 ;
     RECT  63.925 25.216 64.451 31.392 ;
     RECT  62.635 76.596 64.499 78.112 ;
     RECT  63.781 70.784 64.674 72.224 ;
     RECT  64.674 70.784 64.693 72.608 ;
     RECT  64.693 70.656 64.747 72.608 ;
     RECT  63.723 49.216 65.459 50.46 ;
     RECT  64.451 25.216 65.515 31.264 ;
     RECT  64.747 70.656 65.843 72.288 ;
     RECT  65.843 70.656 66.037 72.224 ;
     RECT  64.357 68.352 66.091 68.384 ;
     RECT  66.037 69.824 66.091 72.224 ;
     RECT  64.043 54.848 66.133 55.86 ;
     RECT  66.133 54.08 66.165 55.86 ;
     RECT  66.165 54.08 66.219 56.224 ;
     RECT  63.205 59.456 66.229 62.432 ;
     RECT  63.013 47.232 66.419 47.264 ;
     RECT  66.085 74.688 66.613 74.72 ;
     RECT  64.499 76.596 66.613 77.46 ;
     RECT  66.613 74.688 66.667 78.112 ;
     RECT  66.667 75.392 66.682 78.112 ;
     RECT  66.229 58.944 66.709 62.432 ;
     RECT  66.091 69.824 66.741 69.856 ;
     RECT  66.741 68.992 66.755 69.856 ;
     RECT  66.709 58.944 66.795 62.688 ;
     RECT  66.682 75.392 66.803 77.46 ;
     RECT  64.107 22.596 66.933 23.46 ;
     RECT  65.509 21.12 66.987 21.152 ;
     RECT  66.755 68.992 66.987 69.472 ;
     RECT  66.091 71.196 66.987 72.224 ;
     RECT  66.933 22.596 67.006 23.776 ;
     RECT  65.515 25.216 67.237 26.528 ;
     RECT  65.515 27.996 67.237 31.264 ;
     RECT  63.925 38.796 67.283 40.544 ;
     RECT  61.035 33.396 67.621 34.26 ;
     RECT  67.621 33.396 67.691 34.976 ;
     RECT  67.283 38.796 67.813 39.66 ;
     RECT  67.237 25.216 67.819 31.264 ;
     RECT  66.795 58.944 67.829 62.24 ;
     RECT  67.829 58.304 67.907 62.24 ;
     RECT  63.299 65.796 68.021 66.66 ;
     RECT  68.005 64.192 68.075 64.224 ;
     RECT  66.219 54.848 68.245 56.224 ;
     RECT  66.987 69.44 68.341 69.472 ;
     RECT  68.021 65.796 68.433 66.784 ;
     RECT  67.819 25.216 68.789 26.528 ;
     RECT  66.987 71.196 68.917 72.06 ;
     RECT  66.803 76.596 68.917 77.46 ;
     RECT  67.819 27.996 69.011 31.264 ;
     RECT  68.245 54.848 69.045 56.416 ;
     RECT  69.013 52.928 69.099 52.96 ;
     RECT  67.006 22.596 69.173 23.46 ;
     RECT  69.045 54.464 69.291 56.416 ;
     RECT  69.291 54.464 69.297 55.86 ;
     RECT  68.789 24.768 69.493 26.528 ;
     RECT  69.011 27.996 69.493 28.86 ;
     RECT  67.813 37.568 69.493 39.66 ;
     RECT  67.907 58.304 69.493 58.336 ;
     RECT  69.493 58.304 69.621 58.4 ;
     RECT  69.297 54.848 69.675 55.86 ;
     RECT  69.621 48.128 70.069 48.16 ;
     RECT  34.101 0.832 70.163 3.36 ;
     RECT  69.173 21.312 70.197 23.46 ;
     RECT  69.493 24.768 70.197 28.86 ;
     RECT  68.917 71.196 70.307 72.352 ;
     RECT  67.907 60.396 70.309 61.472 ;
     RECT  69.621 57.28 70.645 58.4 ;
     RECT  70.309 59.776 70.645 61.472 ;
     RECT  70.645 57.28 70.699 62.752 ;
     RECT  70.117 64.384 70.699 64.416 ;
     RECT  70.069 47.104 70.837 48.16 ;
     RECT  65.459 49.596 70.837 50.46 ;
     RECT  70.309 52.992 70.837 53.024 ;
     RECT  62.629 11.796 70.883 14.176 ;
     RECT  70.699 57.28 70.883 58.976 ;
     RECT  70.699 60.396 70.883 62.752 ;
     RECT  70.197 21.312 70.901 28.86 ;
     RECT  69.011 30.208 70.901 31.264 ;
     RECT  69.493 37.568 70.901 40.608 ;
     RECT  70.901 37.056 70.931 40.608 ;
     RECT  70.901 21.312 70.955 31.264 ;
     RECT  68.341 68.288 70.955 69.472 ;
     RECT  70.931 37.056 70.979 37.088 ;
     RECT  69.675 54.996 71.413 55.86 ;
     RECT  70.883 57.28 71.413 57.312 ;
     RECT  68.917 76.48 71.413 77.46 ;
     RECT  68.917 79.424 71.413 79.456 ;
     RECT  71.413 76.48 71.459 79.456 ;
     RECT  71.459 76.596 71.467 79.456 ;
     RECT  70.931 38.796 71.586 40.608 ;
     RECT  71.586 38.796 71.653 41.312 ;
     RECT  67.691 33.396 71.669 34.26 ;
     RECT  71.653 38.796 71.723 41.632 ;
     RECT  70.837 47.104 71.733 50.46 ;
     RECT  70.837 52.864 71.733 53.024 ;
     RECT  71.733 52.864 71.787 53.088 ;
     RECT  70.307 71.196 71.797 72.06 ;
     RECT  70.837 74.048 71.797 74.08 ;
     RECT  71.797 71.196 71.851 74.72 ;
     RECT  71.851 74.688 71.891 74.72 ;
     RECT  60.419 44.196 72.565 45.06 ;
     RECT  71.733 47.104 72.565 51.04 ;
     RECT  72.565 44.196 72.619 51.296 ;
     RECT  72.619 44.196 72.634 48.16 ;
     RECT  72.634 46.784 72.659 48.16 ;
     RECT  64.053 17.196 72.683 19.552 ;
     RECT  71.669 33.396 72.901 34.4 ;
     RECT  71.787 53.056 72.995 53.088 ;
     RECT  70.883 58.944 72.995 58.976 ;
     RECT  68.433 65.796 73.381 66.66 ;
     RECT  70.955 21.312 73.477 30.048 ;
     RECT  71.851 71.196 73.589 72.864 ;
     RECT  72.619 49.596 73.653 51.296 ;
     RECT  71.723 38.796 73.717 40.608 ;
     RECT  73.653 49.596 73.726 52.512 ;
     RECT  71.749 63.232 73.781 63.264 ;
     RECT  73.381 65.28 73.781 66.66 ;
     RECT  73.717 38.796 73.786 41.056 ;
     RECT  71.467 76.596 73.813 78.624 ;
     RECT  70.955 69.44 73.835 69.472 ;
     RECT  73.781 63.232 73.861 66.66 ;
     RECT  73.589 71.196 73.899 72.992 ;
     RECT  73.861 63.232 73.963 66.784 ;
     RECT  73.899 71.196 74.005 72.928 ;
     RECT  74.005 70.72 74.091 72.928 ;
     RECT  70.163 3.328 74.147 3.36 ;
     RECT  73.813 75.584 74.155 78.624 ;
     RECT  74.155 76.416 74.341 78.624 ;
     RECT  62.819 81.088 74.341 81.12 ;
     RECT  74.341 76.416 74.411 81.12 ;
     RECT  74.411 76.416 74.453 79.456 ;
     RECT  73.963 64.064 74.483 64.416 ;
     RECT  72.901 32.256 74.485 34.4 ;
     RECT  74.485 32.256 74.554 34.464 ;
     RECT  73.726 49.596 74.963 51.296 ;
     RECT  73.909 68.8 75.011 68.832 ;
     RECT  72.659 48.128 75.299 48.16 ;
     RECT  71.413 54.996 75.301 57.312 ;
     RECT  75.301 54.592 75.491 57.312 ;
     RECT  70.883 60.396 75.733 61.472 ;
     RECT  72.683 17.196 75.779 19.296 ;
     RECT  70.163 0.832 76.152 1.86 ;
     RECT  46.123 6.396 76.152 7.26 ;
     RECT  70.883 11.796 76.152 13.92 ;
     RECT  73.477 20.608 76.152 30.048 ;
     RECT  73.786 38.796 76.152 40.608 ;
     RECT  72.634 44.196 76.152 45.06 ;
     RECT  74.963 49.596 76.152 50.46 ;
     RECT  75.491 54.592 76.152 55.86 ;
     RECT  73.963 65.796 76.152 66.66 ;
     RECT  74.453 76.416 76.152 77.46 ;
     RECT  74.091 71.196 76.213 72.928 ;
     RECT  76.152 40.576 76.259 40.608 ;
     RECT  72.659 46.784 76.277 46.816 ;
     RECT  75.491 57.28 76.277 57.312 ;
     RECT  76.277 58.88 76.309 58.912 ;
     RECT  75.733 60.396 76.309 62.176 ;
     RECT  76.152 65.796 76.309 66.084 ;
     RECT  76.277 46.784 76.331 47.84 ;
     RECT  74.483 64.064 76.341 64.096 ;
     RECT  76.309 65.6 76.341 66.084 ;
     RECT  76.309 58.88 76.355 62.176 ;
     RECT  76.355 59.264 76.395 62.176 ;
     RECT  76.341 64.064 76.395 66.084 ;
     RECT  76.152 30.016 76.403 30.048 ;
     RECT  74.554 32.256 76.403 34.4 ;
     RECT  76.331 47.808 76.403 47.84 ;
     RECT  76.277 57.28 76.403 57.568 ;
     RECT  76.152 76.416 76.403 76.884 ;
     RECT  76.152 6.396 76.744 6.684 ;
     RECT  76.152 11.796 76.744 12.256 ;
     RECT  75.779 17.196 76.744 19.04 ;
     RECT  76.152 20.608 76.744 28.284 ;
     RECT  76.403 32.256 76.744 34.272 ;
     RECT  76.152 38.796 76.744 39.084 ;
     RECT  76.152 44.196 76.744 45.024 ;
     RECT  76.152 49.596 76.744 49.884 ;
     RECT  76.152 54.592 76.744 55.284 ;
     RECT  76.395 60.396 76.744 61.472 ;
     RECT  76.395 64.384 76.744 66.084 ;
     RECT  76.213 71.196 76.744 74.144 ;
     RECT  76.403 76.596 76.744 76.884 ;
     RECT  75.397 52.416 76.853 52.448 ;
     RECT  76.744 64.384 76.883 64.864 ;
     RECT  76.405 30.912 76.907 30.944 ;
     RECT  76.744 32.256 76.907 32.736 ;
     RECT  76.853 52.416 76.907 52.96 ;
     RECT  76.744 54.592 76.907 55.072 ;
     RECT  76.907 52.928 76.931 52.96 ;
     RECT  76.744 34.24 76.971 34.272 ;
     RECT  76.885 48.32 76.971 49.056 ;
     RECT  76.744 44.736 76.979 45.024 ;
     RECT  76.853 36.096 77.027 36.256 ;
     RECT  76.907 55.04 77.123 55.072 ;
     RECT  76.744 61.248 77.363 61.472 ;
     RECT  76.744 20.608 77.461 21.344 ;
     RECT  76.907 32.512 77.483 32.736 ;
     RECT  77.483 32.704 77.555 32.736 ;
     RECT  76.744 24 77.749 28.284 ;
     RECT  76.883 64.384 77.797 64.416 ;
     RECT  77.73 29.952 77.803 29.984 ;
     RECT  77.797 63.168 77.867 64.416 ;
     RECT  77.749 24 77.931 28.384 ;
     RECT  76.837 57.216 78.035 57.248 ;
     RECT  76.152 0.832 78.131 1.44 ;
     RECT  76.744 72.384 78.131 74.144 ;
     RECT  77.931 28.352 78.323 28.384 ;
     RECT  78.037 67.2 78.645 67.232 ;
     RECT  77.461 69.568 78.661 69.6 ;
     RECT  76.971 49.024 78.707 49.056 ;
     RECT  74.453 79.424 78.707 79.456 ;
     RECT  77.027 36.096 78.714 36.128 ;
     RECT  78.645 66.624 78.718 67.232 ;
     RECT  78.131 72.384 78.837 72.416 ;
     RECT  78.718 67.2 78.891 67.232 ;
     RECT  78.661 68.8 78.891 69.6 ;
     RECT  78.837 71.296 78.891 72.416 ;
     RECT  78.891 71.296 78.91 71.328 ;
     RECT  78.613 38.592 78.955 38.624 ;
     RECT  78.882 46.656 78.955 46.688 ;
     RECT  74.411 81.088 79.029 81.12 ;
     RECT  78.131 74.112 79.083 74.144 ;
     RECT  78.421 75.584 79.083 75.616 ;
     RECT  78.997 78.08 79.083 78.112 ;
     RECT  78.901 52.48 79.221 52.512 ;
     RECT  77.867 64.384 79.283 64.416 ;
     RECT  79.221 48.256 79.294 48.288 ;
     RECT  79.221 52.48 79.333 53.088 ;
     RECT  77.363 61.44 79.349 61.472 ;
     RECT  79.333 52.48 79.669 53.536 ;
     RECT  79.65 46.912 79.723 46.944 ;
     RECT  40.499 4.864 79.763 4.96 ;
     RECT  79.669 52.48 79.842 54.176 ;
     RECT  79.605 55.872 79.842 55.904 ;
     RECT  79.763 4.928 79.859 4.96 ;
     RECT  78.901 40.512 79.859 40.544 ;
     RECT  79.349 61.44 79.859 62.752 ;
     RECT  79.029 79.808 79.859 81.12 ;
     RECT  79.842 52.48 79.861 55.904 ;
     RECT  76.979 44.736 79.907 44.768 ;
     RECT  79.861 52.48 80.117 57.056 ;
     RECT  80.053 58.752 80.117 58.784 ;
     RECT  76.744 12.16 80.387 12.256 ;
     RECT  78.131 1.408 80.435 1.44 ;
     RECT  80.387 12.224 80.435 12.256 ;
     RECT  76.152 13.888 80.435 13.92 ;
     RECT  72.629 15.232 80.435 15.264 ;
     RECT  76.744 18.368 80.435 19.04 ;
     RECT  77.461 20.352 80.435 21.344 ;
     RECT  77.931 24 80.435 26.4 ;
     RECT  80.366 50.688 80.435 50.72 ;
     RECT  80.117 52.48 80.435 58.784 ;
     RECT  80.435 53.952 80.446 58.784 ;
     RECT  80.435 18.752 80.483 18.784 ;
     RECT  80.435 21.312 80.483 21.344 ;
     RECT  80.435 25.472 80.483 25.504 ;
     RECT  79.859 81.088 80.531 81.12 ;
     RECT  80.485 51.84 80.555 51.872 ;
     RECT  80.629 49.536 80.698 50.144 ;
     RECT  80.629 66.688 80.723 66.72 ;
     RECT  79.859 61.44 80.75 62.24 ;
     RECT  80.446 53.952 80.771 53.984 ;
     RECT  80.75 60.416 80.819 62.24 ;
     RECT  80.446 55.296 80.89 58.784 ;
     RECT  80.819 60.992 80.915 62.24 ;
     RECT  80.821 70.144 80.915 70.176 ;
     RECT  80.698 50.112 80.939 50.144 ;
     RECT  80.89 55.296 80.939 55.84 ;
     RECT  80.89 57.536 80.942 58.784 ;
     RECT  80.942 57.536 81.003 59.296 ;
     RECT  81.003 58.304 81.011 59.296 ;
     RECT  80.915 61.76 81.011 62.24 ;
     RECT  80.939 55.808 81.131 55.84 ;
     RECT  81.011 58.304 81.131 58.336 ;
    LAYER M7 ;
     RECT  31.168 1.397 31.2 1.973 ;
     RECT  33.256 0.531 33.544 2.741 ;
     RECT  33.256 2.741 34.144 3.381 ;
     RECT  38.656 0.531 38.944 5.045 ;
     RECT  46.08 8.501 46.112 10.283 ;
     RECT  46.4 10.741 46.432 11.509 ;
     RECT  46.4 11.509 46.816 11.563 ;
     RECT  40.256 5.045 40.288 11.637 ;
     RECT  49.456 0.531 49.744 11.637 ;
     RECT  37.952 5.045 38.944 12.917 ;
     RECT  40.256 11.637 41.504 12.917 ;
     RECT  37.952 12.917 41.504 12.971 ;
     RECT  46.784 11.563 46.816 13.035 ;
     RECT  60.256 0.531 60.544 13.045 ;
     RECT  49.456 11.637 50.144 14.197 ;
     RECT  60.256 13.045 61.216 14.325 ;
     RECT  37.952 12.971 41.184 14.443 ;
     RECT  44.056 0.531 44.344 14.773 ;
     RECT  54.856 0.531 55.144 14.773 ;
     RECT  44.056 14.773 44.448 15.467 ;
     RECT  49.456 14.197 51.36 16.043 ;
     RECT  53.76 14.773 55.144 16.043 ;
     RECT  46.848 14.773 46.88 16.619 ;
     RECT  49.456 16.043 50.656 17.067 ;
     RECT  49.456 17.067 50.4 17.589 ;
     RECT  44.056 15.467 44.344 17.653 ;
     RECT  44.056 17.653 45.536 18.859 ;
     RECT  65.656 0.531 65.944 18.933 ;
     RECT  57.792 16.949 57.824 19.061 ;
     RECT  52.736 18.165 52.768 19.317 ;
     RECT  60.256 14.325 61.344 19.317 ;
     RECT  52.48 19.317 52.768 19.371 ;
     RECT  57.792 19.061 58.208 19.371 ;
     RECT  37.952 14.443 40.288 19.435 ;
     RECT  72.64 15.221 72.672 19.435 ;
     RECT  60.256 19.317 62.112 19.499 ;
     RECT  48.96 17.589 50.4 20.331 ;
     RECT  49.456 20.331 50.4 20.469 ;
     RECT  54.856 16.043 55.144 20.469 ;
     RECT  52.48 19.371 52.512 21.035 ;
     RECT  65.656 18.933 66.848 21.109 ;
     RECT  35.968 8.373 36 21.163 ;
     RECT  58.176 19.371 58.208 21.163 ;
     RECT  76.456 0.531 76.744 21.173 ;
     RECT  53.824 20.469 55.144 22.453 ;
     RECT  60.256 19.499 60.544 22.965 ;
     RECT  62.08 19.499 62.112 22.965 ;
     RECT  37.952 19.435 38.944 23.029 ;
     RECT  40.256 19.435 40.288 23.029 ;
     RECT  64.064 19.509 64.096 23.595 ;
     RECT  65.656 21.109 66.976 23.787 ;
     RECT  60.256 22.965 62.112 23.861 ;
     RECT  49.456 20.469 50.912 23.915 ;
     RECT  53.824 22.453 55.584 23.979 ;
     RECT  69.184 21.301 69.216 24.245 ;
     RECT  71.056 0.531 71.344 24.245 ;
     RECT  69.184 24.245 71.344 24.757 ;
     RECT  49.456 23.915 50.4 24.949 ;
     RECT  54.856 23.979 55.584 25.131 ;
     RECT  60.256 23.861 62.176 25.195 ;
     RECT  36.352 22.453 36.384 25.973 ;
     RECT  36.352 25.973 36.448 25.974 ;
     RECT  65.656 23.787 65.944 26.165 ;
     RECT  52.48 23.861 52.512 26.283 ;
     RECT  68.8 24.757 71.344 26.283 ;
     RECT  48.704 24.949 50.4 26.485 ;
     RECT  57.536 26.485 57.568 26.613 ;
     RECT  57.344 26.613 57.568 26.795 ;
     RECT  47.232 24.885 47.264 27.061 ;
     RECT  57.344 26.795 57.44 27.061 ;
     RECT  46.72 27.061 47.264 27.243 ;
     RECT  68.8 26.283 68.832 27.317 ;
     RECT  37.952 23.029 40.288 27.371 ;
     RECT  76.456 21.173 77.92 27.435 ;
     RECT  65.472 26.165 65.944 27.765 ;
     RECT  48.704 26.485 50.528 27.883 ;
     RECT  36.416 25.974 36.448 28.405 ;
     RECT  37.952 27.371 38.944 28.405 ;
     RECT  36.416 28.405 38.944 28.459 ;
     RECT  67.776 27.317 68.832 29.099 ;
     RECT  52.416 26.741 52.448 29.365 ;
     RECT  52.224 29.365 52.448 29.419 ;
     RECT  54.856 25.131 55.144 29.493 ;
     RECT  57.216 27.061 57.44 29.493 ;
     RECT  44.056 18.859 44.344 29.557 ;
     RECT  67.776 29.099 67.808 29.685 ;
     RECT  36.736 28.459 38.944 29.739 ;
     RECT  67.648 29.685 67.808 29.739 ;
     RECT  64.448 27.765 65.944 29.867 ;
     RECT  76.456 27.435 77.792 29.995 ;
     RECT  70.208 26.283 71.344 30.251 ;
     RECT  60.256 25.195 61.6 30.581 ;
     RECT  59.2 30.581 61.6 31.275 ;
     RECT  47.232 27.243 47.264 31.349 ;
     RECT  49.456 27.883 50.528 31.349 ;
     RECT  43.84 29.557 44.344 31.403 ;
     RECT  47.232 31.349 50.528 31.403 ;
     RECT  54.856 29.493 57.44 31.659 ;
     RECT  44.056 31.403 44.344 31.861 ;
     RECT  76.456 29.995 77.472 32.555 ;
     RECT  74.496 27.829 74.528 32.693 ;
     RECT  47.232 31.403 49.744 33.835 ;
     RECT  54.856 31.659 57.248 33.835 ;
     RECT  76.456 32.555 76.96 34.283 ;
     RECT  70.912 30.251 71.344 34.357 ;
     RECT  73.728 32.693 74.528 34.475 ;
     RECT  44.056 31.861 44.448 34.741 ;
     RECT  52.224 29.419 52.256 34.859 ;
     RECT  67.648 29.739 67.68 34.987 ;
     RECT  37.952 29.739 38.944 35.317 ;
     RECT  40.256 27.371 40.288 35.317 ;
     RECT  56.896 33.835 57.248 35.499 ;
     RECT  76.456 34.283 76.896 36.267 ;
     RECT  37.952 35.317 40.288 36.405 ;
     RECT  47.232 33.835 47.264 36.405 ;
     RECT  59.2 31.275 61.024 36.523 ;
     RECT  49.456 33.835 49.744 36.981 ;
     RECT  36.8 36.405 40.288 37.099 ;
     RECT  47.232 36.405 47.328 37.237 ;
     RECT  48.704 36.981 49.744 37.237 ;
     RECT  43.84 34.741 44.448 37.291 ;
     RECT  47.232 37.237 49.744 37.547 ;
     RECT  70.912 34.357 71.712 37.557 ;
     RECT  57.216 35.499 57.248 38.133 ;
     RECT  43.84 37.291 44.344 38.517 ;
     RECT  78.656 36.085 78.688 38.581 ;
     RECT  47.424 37.547 49.744 38.635 ;
     RECT  78.656 38.581 78.944 38.635 ;
     RECT  43.712 38.517 44.344 38.699 ;
     RECT  54.856 33.835 55.144 39.733 ;
     RECT  57.216 38.133 57.44 39.733 ;
     RECT  54.856 39.733 57.44 39.787 ;
     RECT  60.256 36.523 61.024 39.861 ;
     RECT  51.136 38.581 51.168 40.501 ;
     RECT  36.8 37.099 38.944 40.555 ;
     RECT  51.136 40.501 51.296 40.555 ;
     RECT  63.936 39.861 63.968 40.555 ;
     RECT  78.912 38.635 78.944 40.555 ;
     RECT  70.4 37.557 71.712 40.619 ;
     RECT  37.952 40.555 38.944 41.013 ;
     RECT  40.256 37.099 40.288 41.013 ;
     RECT  54.856 39.787 57.248 41.067 ;
     RECT  73.728 34.475 73.76 41.067 ;
     RECT  47.424 38.635 47.456 41.643 ;
     RECT  71.056 40.619 71.712 41.643 ;
     RECT  37.952 41.013 40.288 42.731 ;
     RECT  60.256 39.861 61.152 42.795 ;
     RECT  45.888 37.557 45.92 43.307 ;
     RECT  60.256 42.795 60.544 43.573 ;
     RECT  43.84 38.699 44.344 43.765 ;
     RECT  51.264 40.555 51.296 43.819 ;
     RECT  37.952 42.731 38.944 44.597 ;
     RECT  76.456 36.267 76.744 44.981 ;
     RECT  54.856 41.067 55.144 45.173 ;
     RECT  57.088 41.067 57.248 45.173 ;
     RECT  71.056 41.643 71.344 46.133 ;
     RECT  60.032 43.573 60.544 46.389 ;
     RECT  78.912 46.645 78.944 46.901 ;
     RECT  37.632 44.597 38.944 46.955 ;
     RECT  65.656 29.867 65.944 47.221 ;
     RECT  54.856 45.173 57.248 47.605 ;
     RECT  59.904 46.389 60.544 47.797 ;
     RECT  76.288 44.981 76.744 47.851 ;
     RECT  76.456 47.851 76.744 48.309 ;
     RECT  58.752 47.797 60.544 48.939 ;
     RECT  37.824 46.955 38.944 48.949 ;
     RECT  40.256 42.731 40.288 48.949 ;
     RECT  76.456 48.309 76.96 49.067 ;
     RECT  65.408 47.221 65.944 49.259 ;
     RECT  54.592 47.605 57.248 49.333 ;
     RECT  53.504 49.333 57.248 49.387 ;
     RECT  78.912 46.901 79.712 49.525 ;
     RECT  69.632 48.117 69.664 50.037 ;
     RECT  78.912 49.525 80.672 50.101 ;
     RECT  59.904 48.939 60.544 50.603 ;
     RECT  33.024 3.381 34.144 50.677 ;
     RECT  63.296 49.205 63.328 50.677 ;
     RECT  63.296 50.677 63.712 50.731 ;
     RECT  31.168 1.973 31.264 50.805 ;
     RECT  43.776 43.765 44.344 50.997 ;
     RECT  71.056 46.133 72.608 51.253 ;
     RECT  71.056 51.253 73.696 51.307 ;
     RECT  37.824 48.949 40.288 51.947 ;
     RECT  76.456 49.067 76.744 52.405 ;
     RECT  43.328 50.997 44.344 52.523 ;
     RECT  63.68 50.731 63.712 52.523 ;
     RECT  73.664 51.307 73.696 52.523 ;
     RECT  78.912 50.101 80.928 52.523 ;
     RECT  33.024 50.677 34.784 52.597 ;
     RECT  58.752 51.573 58.784 53.035 ;
     RECT  71.056 51.307 71.776 53.099 ;
     RECT  79.232 52.523 80.928 53.099 ;
     RECT  53.504 49.387 53.536 53.227 ;
     RECT  65.656 49.259 65.944 54.069 ;
     RECT  31.04 50.805 31.264 54.453 ;
     RECT  69.056 50.037 69.664 54.507 ;
     RECT  54.856 49.387 57.248 54.581 ;
     RECT  31.04 54.453 31.392 54.635 ;
     RECT  44.056 52.523 44.344 54.709 ;
     RECT  60.256 50.603 60.544 54.709 ;
     RECT  64 53.493 64.032 54.827 ;
     RECT  65.656 54.069 66.208 54.837 ;
     RECT  49.456 38.635 49.744 55.413 ;
     RECT  33.024 52.597 34.912 55.414 ;
     RECT  79.36 53.099 80.928 55.797 ;
     RECT  37.952 51.947 40.288 56.373 ;
     RECT  69.248 54.507 69.664 56.373 ;
     RECT  48.256 55.413 49.744 56.885 ;
     RECT  52.736 54.517 52.768 56.885 ;
     RECT  33.024 55.414 34.848 56.939 ;
     RECT  47.872 56.885 49.744 56.939 ;
     RECT  72.768 55.349 72.8 56.939 ;
     RECT  76.456 52.405 76.896 57.259 ;
     RECT  68.352 56.373 69.664 57.323 ;
     RECT  76.456 57.259 76.744 57.525 ;
     RECT  54.856 54.581 57.824 57.717 ;
     RECT  31.168 54.635 31.392 57.973 ;
     RECT  33.024 56.939 34.144 57.973 ;
     RECT  65.656 54.837 66.72 58.293 ;
     RECT  68.352 57.323 68.384 58.293 ;
     RECT  65.656 58.293 68.384 58.347 ;
     RECT  79.36 55.797 81.12 58.347 ;
     RECT  47.872 56.939 47.904 58.613 ;
     RECT  49.456 56.939 49.744 58.613 ;
     RECT  47.872 58.613 49.744 58.667 ;
     RECT  60.256 54.709 61.856 58.795 ;
     RECT  76.288 57.525 76.744 58.923 ;
     RECT  71.056 53.099 71.344 58.933 ;
     RECT  31.168 57.973 34.144 59.307 ;
     RECT  65.656 58.347 67.872 59.307 ;
     RECT  79.36 58.347 80.992 59.307 ;
     RECT  65.656 59.307 66.72 59.637 ;
     RECT  48.704 58.667 49.744 59.883 ;
     RECT  36.992 56.373 40.288 60.843 ;
     RECT  54.856 57.717 57.888 61.557 ;
     RECT  31.232 59.307 34.144 61.675 ;
     RECT  54.856 61.557 58.336 61.739 ;
     RECT  31.232 61.675 31.264 61.803 ;
     RECT  54.856 61.739 57.568 62.187 ;
     RECT  76.352 58.923 76.744 62.187 ;
     RECT  64.448 59.637 66.72 62.251 ;
     RECT  52.736 56.885 53.216 62.261 ;
     RECT  48.96 59.883 49.744 62.315 ;
     RECT  57.536 62.187 57.568 62.443 ;
     RECT  52.608 62.261 53.216 62.645 ;
     RECT  54.856 62.187 56.16 62.645 ;
     RECT  65.656 62.251 66.72 62.645 ;
     RECT  60.256 58.795 61.792 62.699 ;
     RECT  79.36 59.307 80.864 62.763 ;
     RECT  76.456 62.187 76.744 63.157 ;
     RECT  36.992 60.843 38.944 63.221 ;
     RECT  40.256 60.843 40.288 63.221 ;
     RECT  52.608 62.645 56.16 63.787 ;
     RECT  35.648 57.525 35.68 63.861 ;
     RECT  36.992 63.221 40.288 63.861 ;
     RECT  35.648 63.861 40.288 63.979 ;
     RECT  76.456 63.157 77.856 64.053 ;
     RECT  65.656 62.645 66.784 64.181 ;
     RECT  73.92 63.221 73.952 64.245 ;
     RECT  33.024 61.675 34.144 64.373 ;
     RECT  60.256 62.699 60.544 64.373 ;
     RECT  70.656 58.933 71.344 64.427 ;
     RECT  76.352 64.053 77.856 64.427 ;
     RECT  49.024 62.315 49.744 64.811 ;
     RECT  60.256 64.373 61.536 64.949 ;
     RECT  60.256 64.949 62.24 65.003 ;
     RECT  52.608 63.787 52.64 65.589 ;
     RECT  54.08 63.787 56.16 65.589 ;
     RECT  52.608 65.589 56.16 65.643 ;
     RECT  76.352 64.427 76.744 65.643 ;
     RECT  49.344 64.811 49.744 65.707 ;
     RECT  32.512 64.373 34.144 66.219 ;
     RECT  71.056 64.427 71.344 66.229 ;
     RECT  80.64 62.763 80.864 66.731 ;
     RECT  65.656 64.181 68.064 66.741 ;
     RECT  43.84 54.709 44.344 66.795 ;
     RECT  47.296 64.757 47.328 66.795 ;
     RECT  65.656 66.741 68.384 66.795 ;
     RECT  52.608 65.643 52.96 67.189 ;
     RECT  78.656 66.613 78.688 67.189 ;
     RECT  51.584 67.189 52.96 67.243 ;
     RECT  78.656 67.189 78.88 67.243 ;
     RECT  52.928 67.243 52.96 67.381 ;
     RECT  54.856 65.643 56.16 67.381 ;
     RECT  52.928 67.381 56.16 67.435 ;
     RECT  62.208 65.003 62.24 67.563 ;
     RECT  60.256 65.003 60.544 67.765 ;
     RECT  54.144 67.435 56.16 67.947 ;
     RECT  68.352 66.795 68.384 68.331 ;
     RECT  70.912 66.229 71.344 68.331 ;
     RECT  73.792 64.245 73.952 68.789 ;
     RECT  65.656 66.795 66.784 68.981 ;
     RECT  35.648 63.979 38.944 69.035 ;
     RECT  44.056 66.795 44.344 69.365 ;
     RECT  80.832 66.731 80.864 70.187 ;
     RECT  32.64 66.219 34.144 70.251 ;
     RECT  65.656 68.981 66.976 70.645 ;
     RECT  37.952 69.035 38.944 70.763 ;
     RECT  73.792 68.789 74.08 70.763 ;
     RECT  49.456 65.707 49.744 71.605 ;
     RECT  51.584 67.243 51.616 71.605 ;
     RECT  71.056 68.331 71.344 71.605 ;
     RECT  42.752 69.365 44.344 71.659 ;
     RECT  60.256 67.765 60.704 72.181 ;
     RECT  58.432 67.765 58.464 72.235 ;
     RECT  64.704 70.645 66.976 72.235 ;
     RECT  78.848 67.243 78.88 72.427 ;
     RECT  45.888 65.653 45.92 72.565 ;
     RECT  45.888 72.565 46.816 72.619 ;
     RECT  64.704 72.235 65.944 72.619 ;
     RECT  73.792 70.763 73.824 72.693 ;
     RECT  73.6 72.693 73.824 72.949 ;
     RECT  73.6 72.949 73.888 73.003 ;
     RECT  33.256 70.251 34.144 74.155 ;
     RECT  35.648 69.035 35.68 74.155 ;
     RECT  65.656 72.619 65.944 74.677 ;
     RECT  40.256 63.979 40.288 74.731 ;
     RECT  49.456 71.605 51.616 74.731 ;
     RECT  71.056 71.605 71.84 74.731 ;
     RECT  43.008 71.659 44.344 75.115 ;
     RECT  73.856 73.003 73.888 75.573 ;
     RECT  49.456 74.731 50.464 76.139 ;
     RECT  73.856 75.573 74.144 76.459 ;
     RECT  46.784 72.619 46.816 76.523 ;
     RECT  49.456 76.139 50.4 77.035 ;
     RECT  60.256 72.181 60.896 77.035 ;
     RECT  35.264 75.189 35.296 77.611 ;
     RECT  57.536 73.461 57.568 77.611 ;
     RECT  73.856 76.459 73.888 77.611 ;
     RECT  62.592 72.885 62.624 78.005 ;
     RECT  31.36 72.821 31.392 78.123 ;
     RECT  62.592 78.005 62.688 78.123 ;
     RECT  64.256 76.981 64.288 78.123 ;
     RECT  65.656 74.677 66.656 78.123 ;
     RECT  53.44 76.981 53.472 78.315 ;
     RECT  71.056 74.731 71.344 78.581 ;
     RECT  71.056 78.581 71.456 79.467 ;
     RECT  62.656 78.123 62.688 79.851 ;
     RECT  74.368 78.581 74.4 79.851 ;
     RECT  79.04 74.101 79.072 79.851 ;
     RECT  54.856 67.947 56.16 81.131 ;
     RECT  0.856 0.531 1.144 81.279 ;
     RECT  6.256 0.531 6.544 81.279 ;
     RECT  11.656 0.531 11.944 81.279 ;
     RECT  17.056 0.531 17.344 81.279 ;
     RECT  22.456 0.531 22.744 81.279 ;
     RECT  27.856 0.531 28.144 81.279 ;
     RECT  33.256 74.155 33.544 81.279 ;
     RECT  38.656 70.763 38.944 81.279 ;
     RECT  44.056 75.115 44.344 81.279 ;
     RECT  49.456 77.035 49.744 81.279 ;
     RECT  54.856 81.131 55.144 81.279 ;
     RECT  60.256 77.035 60.544 81.279 ;
     RECT  65.656 78.123 65.944 81.279 ;
     RECT  71.056 79.467 71.344 81.279 ;
     RECT  76.456 65.643 76.744 81.279 ;
  END
END hfd_gath_r8
END LIBRARY
